VERSION 5.8 ;
BUSBITCHARS "[]" ;
DIVIDERCHAR "/" ;
UNITS
    DATABASE MICRONS 1000 ;
END UNITS

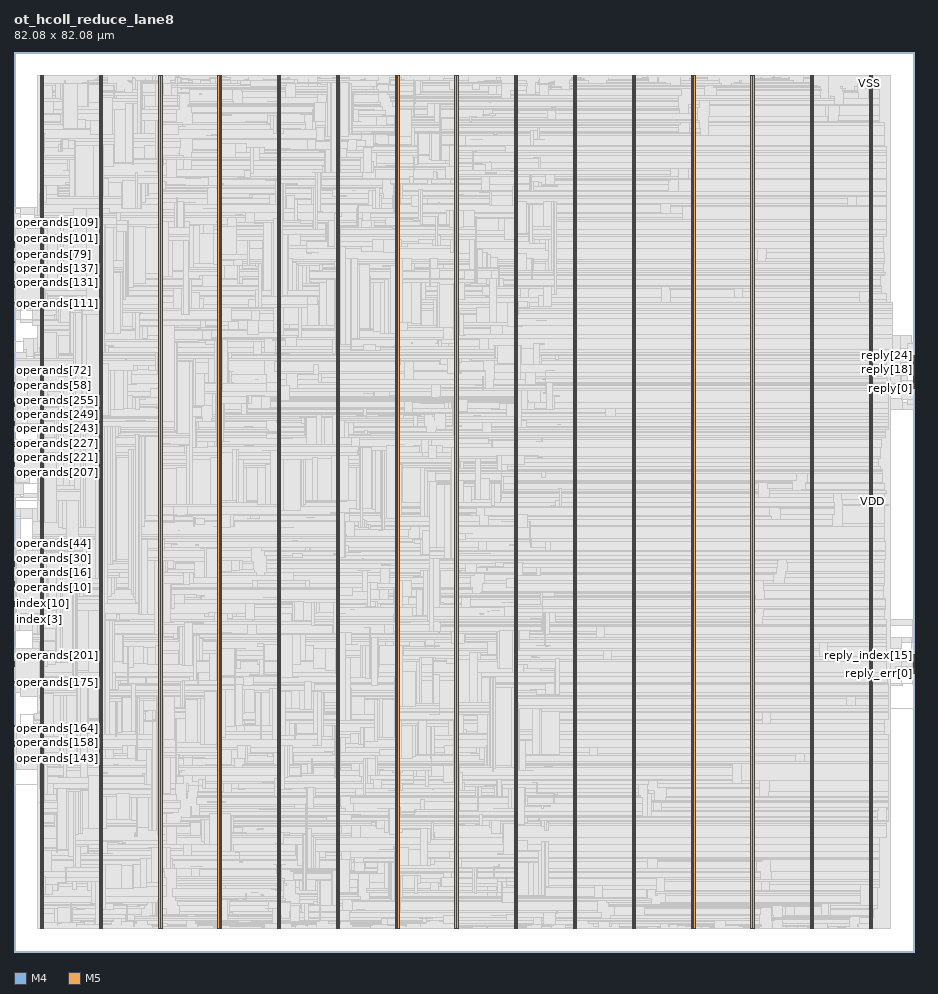
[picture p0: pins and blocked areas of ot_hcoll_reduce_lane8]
MACRO ot_hcoll_reduce_lane8
  FOREIGN ot_hcoll_reduce_lane8 0 0 ;
  CLASS BLOCK ;
  SIZE 82.08 BY 82.08 ;
  PIN clk
    DIRECTION INPUT ;
    USE SIGNAL ;
    PORT
      LAYER M4 ;
        RECT  0 30.672 0.084 30.696 ;
    END
  END clk
  PIN index[0]
    DIRECTION INPUT ;
    USE SIGNAL ;
    PORT
      LAYER M4 ;
        RECT  0 30.768 0.084 30.792 ;
    END
  END index[0]
  PIN index[10]
    DIRECTION INPUT ;
    USE SIGNAL ;
    PORT
      LAYER M4 ;
        RECT  0 31.728 0.084 31.752 ;
    END
  END index[10]
  PIN index[11]
    DIRECTION INPUT ;
    USE SIGNAL ;
    PORT
      LAYER M4 ;
        RECT  0 31.824 0.084 31.848 ;
    END
  END index[11]
  PIN index[12]
    DIRECTION INPUT ;
    USE SIGNAL ;
    PORT
      LAYER M4 ;
        RECT  0 31.92 0.084 31.944 ;
    END
  END index[12]
  PIN index[13]
    DIRECTION INPUT ;
    USE SIGNAL ;
    PORT
      LAYER M4 ;
        RECT  0 32.016 0.084 32.04 ;
    END
  END index[13]
  PIN index[14]
    DIRECTION INPUT ;
    USE SIGNAL ;
    PORT
      LAYER M4 ;
        RECT  0 32.112 0.084 32.136 ;
    END
  END index[14]
  PIN index[15]
    DIRECTION INPUT ;
    USE SIGNAL ;
    PORT
      LAYER M4 ;
        RECT  0 32.208 0.084 32.232 ;
    END
  END index[15]
  PIN index[1]
    DIRECTION INPUT ;
    USE SIGNAL ;
    PORT
      LAYER M4 ;
        RECT  0 30.864 0.084 30.888 ;
    END
  END index[1]
  PIN index[2]
    DIRECTION INPUT ;
    USE SIGNAL ;
    PORT
      LAYER M4 ;
        RECT  0 30.96 0.084 30.984 ;
    END
  END index[2]
  PIN index[3]
    DIRECTION INPUT ;
    USE SIGNAL ;
    PORT
      LAYER M4 ;
        RECT  0 31.056 0.084 31.08 ;
    END
  END index[3]
  PIN index[4]
    DIRECTION INPUT ;
    USE SIGNAL ;
    PORT
      LAYER M4 ;
        RECT  0 31.152 0.084 31.176 ;
    END
  END index[4]
  PIN index[5]
    DIRECTION INPUT ;
    USE SIGNAL ;
    PORT
      LAYER M4 ;
        RECT  0 31.248 0.084 31.272 ;
    END
  END index[5]
  PIN index[6]
    DIRECTION INPUT ;
    USE SIGNAL ;
    PORT
      LAYER M4 ;
        RECT  0 31.344 0.084 31.368 ;
    END
  END index[6]
  PIN index[7]
    DIRECTION INPUT ;
    USE SIGNAL ;
    PORT
      LAYER M4 ;
        RECT  0 31.44 0.084 31.464 ;
    END
  END index[7]
  PIN index[8]
    DIRECTION INPUT ;
    USE SIGNAL ;
    PORT
      LAYER M4 ;
        RECT  0 31.536 0.084 31.56 ;
    END
  END index[8]
  PIN index[9]
    DIRECTION INPUT ;
    USE SIGNAL ;
    PORT
      LAYER M4 ;
        RECT  0 31.632 0.084 31.656 ;
    END
  END index[9]
  PIN operands[0]
    DIRECTION INPUT ;
    USE SIGNAL ;
    PORT
      LAYER M4 ;
        RECT  0 32.304 0.084 32.328 ;
    END
  END operands[0]
  PIN operands[100]
    DIRECTION INPUT ;
    USE SIGNAL ;
    PORT
      LAYER M4 ;
        RECT  0 64.944 0.084 64.968 ;
    END
  END operands[100]
  PIN operands[101]
    DIRECTION INPUT ;
    USE SIGNAL ;
    PORT
      LAYER M4 ;
        RECT  0 65.04 0.084 65.064 ;
    END
  END operands[101]
  PIN operands[102]
    DIRECTION INPUT ;
    USE SIGNAL ;
    PORT
      LAYER M4 ;
        RECT  0 65.136 0.084 65.16 ;
    END
  END operands[102]
  PIN operands[103]
    DIRECTION INPUT ;
    USE SIGNAL ;
    PORT
      LAYER M4 ;
        RECT  0 65.232 0.084 65.256 ;
    END
  END operands[103]
  PIN operands[104]
    DIRECTION INPUT ;
    USE SIGNAL ;
    PORT
      LAYER M4 ;
        RECT  0 65.328 0.084 65.352 ;
    END
  END operands[104]
  PIN operands[105]
    DIRECTION INPUT ;
    USE SIGNAL ;
    PORT
      LAYER M4 ;
        RECT  0 65.424 0.084 65.448 ;
    END
  END operands[105]
  PIN operands[106]
    DIRECTION INPUT ;
    USE SIGNAL ;
    PORT
      LAYER M4 ;
        RECT  0 65.52 0.084 65.544 ;
    END
  END operands[106]
  PIN operands[107]
    DIRECTION INPUT ;
    USE SIGNAL ;
    PORT
      LAYER M4 ;
        RECT  0 65.616 0.084 65.64 ;
    END
  END operands[107]
  PIN operands[108]
    DIRECTION INPUT ;
    USE SIGNAL ;
    PORT
      LAYER M4 ;
        RECT  0 65.712 0.084 65.736 ;
    END
  END operands[108]
  PIN operands[109]
    DIRECTION INPUT ;
    USE SIGNAL ;
    PORT
      LAYER M4 ;
        RECT  0 65.808 0.084 65.832 ;
    END
  END operands[109]
  PIN operands[10]
    DIRECTION INPUT ;
    USE SIGNAL ;
    PORT
      LAYER M4 ;
        RECT  0 33.264 0.084 33.288 ;
    END
  END operands[10]
  PIN operands[110]
    DIRECTION INPUT ;
    USE SIGNAL ;
    PORT
      LAYER M4 ;
        RECT  0 65.904 0.084 65.928 ;
    END
  END operands[110]
  PIN operands[111]
    DIRECTION INPUT ;
    USE SIGNAL ;
    PORT
      LAYER M4 ;
        RECT  0 59.088 0.084 59.112 ;
    END
  END operands[111]
  PIN operands[112]
    DIRECTION INPUT ;
    USE SIGNAL ;
    PORT
      LAYER M4 ;
        RECT  0 59.184 0.084 59.208 ;
    END
  END operands[112]
  PIN operands[113]
    DIRECTION INPUT ;
    USE SIGNAL ;
    PORT
      LAYER M4 ;
        RECT  0 59.28 0.084 59.304 ;
    END
  END operands[113]
  PIN operands[114]
    DIRECTION INPUT ;
    USE SIGNAL ;
    PORT
      LAYER M4 ;
        RECT  0 59.376 0.084 59.4 ;
    END
  END operands[114]
  PIN operands[115]
    DIRECTION INPUT ;
    USE SIGNAL ;
    PORT
      LAYER M4 ;
        RECT  0 59.472 0.084 59.496 ;
    END
  END operands[115]
  PIN operands[116]
    DIRECTION INPUT ;
    USE SIGNAL ;
    PORT
      LAYER M4 ;
        RECT  0 59.568 0.084 59.592 ;
    END
  END operands[116]
  PIN operands[117]
    DIRECTION INPUT ;
    USE SIGNAL ;
    PORT
      LAYER M4 ;
        RECT  0 59.664 0.084 59.688 ;
    END
  END operands[117]
  PIN operands[118]
    DIRECTION INPUT ;
    USE SIGNAL ;
    PORT
      LAYER M4 ;
        RECT  0 59.76 0.084 59.784 ;
    END
  END operands[118]
  PIN operands[119]
    DIRECTION INPUT ;
    USE SIGNAL ;
    PORT
      LAYER M4 ;
        RECT  0 59.856 0.084 59.88 ;
    END
  END operands[119]
  PIN operands[11]
    DIRECTION INPUT ;
    USE SIGNAL ;
    PORT
      LAYER M4 ;
        RECT  0 33.36 0.084 33.384 ;
    END
  END operands[11]
  PIN operands[120]
    DIRECTION INPUT ;
    USE SIGNAL ;
    PORT
      LAYER M4 ;
        RECT  0 59.952 0.084 59.976 ;
    END
  END operands[120]
  PIN operands[121]
    DIRECTION INPUT ;
    USE SIGNAL ;
    PORT
      LAYER M4 ;
        RECT  0 60.048 0.084 60.072 ;
    END
  END operands[121]
  PIN operands[122]
    DIRECTION INPUT ;
    USE SIGNAL ;
    PORT
      LAYER M4 ;
        RECT  0 60.144 0.084 60.168 ;
    END
  END operands[122]
  PIN operands[123]
    DIRECTION INPUT ;
    USE SIGNAL ;
    PORT
      LAYER M4 ;
        RECT  0 60.24 0.084 60.264 ;
    END
  END operands[123]
  PIN operands[124]
    DIRECTION INPUT ;
    USE SIGNAL ;
    PORT
      LAYER M4 ;
        RECT  0 60.336 0.084 60.36 ;
    END
  END operands[124]
  PIN operands[125]
    DIRECTION INPUT ;
    USE SIGNAL ;
    PORT
      LAYER M4 ;
        RECT  0 60.432 0.084 60.456 ;
    END
  END operands[125]
  PIN operands[126]
    DIRECTION INPUT ;
    USE SIGNAL ;
    PORT
      LAYER M4 ;
        RECT  0 60.528 0.084 60.552 ;
    END
  END operands[126]
  PIN operands[127]
    DIRECTION INPUT ;
    USE SIGNAL ;
    PORT
      LAYER M4 ;
        RECT  0 60.624 0.084 60.648 ;
    END
  END operands[127]
  PIN operands[128]
    DIRECTION INPUT ;
    USE SIGNAL ;
    PORT
      LAYER M4 ;
        RECT  0 60.72 0.084 60.744 ;
    END
  END operands[128]
  PIN operands[129]
    DIRECTION INPUT ;
    USE SIGNAL ;
    PORT
      LAYER M4 ;
        RECT  0 60.816 0.084 60.84 ;
    END
  END operands[129]
  PIN operands[12]
    DIRECTION INPUT ;
    USE SIGNAL ;
    PORT
      LAYER M4 ;
        RECT  0 33.456 0.084 33.48 ;
    END
  END operands[12]
  PIN operands[130]
    DIRECTION INPUT ;
    USE SIGNAL ;
    PORT
      LAYER M4 ;
        RECT  0 60.912 0.084 60.936 ;
    END
  END operands[130]
  PIN operands[131]
    DIRECTION INPUT ;
    USE SIGNAL ;
    PORT
      LAYER M4 ;
        RECT  0 61.008 0.084 61.032 ;
    END
  END operands[131]
  PIN operands[132]
    DIRECTION INPUT ;
    USE SIGNAL ;
    PORT
      LAYER M4 ;
        RECT  0 61.104 0.084 61.128 ;
    END
  END operands[132]
  PIN operands[133]
    DIRECTION INPUT ;
    USE SIGNAL ;
    PORT
      LAYER M4 ;
        RECT  0 61.2 0.084 61.224 ;
    END
  END operands[133]
  PIN operands[134]
    DIRECTION INPUT ;
    USE SIGNAL ;
    PORT
      LAYER M4 ;
        RECT  0 61.296 0.084 61.32 ;
    END
  END operands[134]
  PIN operands[135]
    DIRECTION INPUT ;
    USE SIGNAL ;
    PORT
      LAYER M4 ;
        RECT  0 61.392 0.084 61.416 ;
    END
  END operands[135]
  PIN operands[136]
    DIRECTION INPUT ;
    USE SIGNAL ;
    PORT
      LAYER M4 ;
        RECT  0 61.488 0.084 61.512 ;
    END
  END operands[136]
  PIN operands[137]
    DIRECTION INPUT ;
    USE SIGNAL ;
    PORT
      LAYER M4 ;
        RECT  0 61.584 0.084 61.608 ;
    END
  END operands[137]
  PIN operands[138]
    DIRECTION INPUT ;
    USE SIGNAL ;
    PORT
      LAYER M4 ;
        RECT  0 61.68 0.084 61.704 ;
    END
  END operands[138]
  PIN operands[139]
    DIRECTION INPUT ;
    USE SIGNAL ;
    PORT
      LAYER M4 ;
        RECT  0 61.776 0.084 61.8 ;
    END
  END operands[139]
  PIN operands[13]
    DIRECTION INPUT ;
    USE SIGNAL ;
    PORT
      LAYER M4 ;
        RECT  0 33.552 0.084 33.576 ;
    END
  END operands[13]
  PIN operands[140]
    DIRECTION INPUT ;
    USE SIGNAL ;
    PORT
      LAYER M4 ;
        RECT  0 61.872 0.084 61.896 ;
    END
  END operands[140]
  PIN operands[141]
    DIRECTION INPUT ;
    USE SIGNAL ;
    PORT
      LAYER M4 ;
        RECT  0 61.968 0.084 61.992 ;
    END
  END operands[141]
  PIN operands[142]
    DIRECTION INPUT ;
    USE SIGNAL ;
    PORT
      LAYER M4 ;
        RECT  0 62.064 0.084 62.088 ;
    END
  END operands[142]
  PIN operands[143]
    DIRECTION INPUT ;
    USE SIGNAL ;
    PORT
      LAYER M4 ;
        RECT  0 17.616 0.084 17.64 ;
    END
  END operands[143]
  PIN operands[144]
    DIRECTION INPUT ;
    USE SIGNAL ;
    PORT
      LAYER M4 ;
        RECT  0 17.712 0.084 17.736 ;
    END
  END operands[144]
  PIN operands[145]
    DIRECTION INPUT ;
    USE SIGNAL ;
    PORT
      LAYER M4 ;
        RECT  0 17.808 0.084 17.832 ;
    END
  END operands[145]
  PIN operands[146]
    DIRECTION INPUT ;
    USE SIGNAL ;
    PORT
      LAYER M4 ;
        RECT  0 17.904 0.084 17.928 ;
    END
  END operands[146]
  PIN operands[147]
    DIRECTION INPUT ;
    USE SIGNAL ;
    PORT
      LAYER M4 ;
        RECT  0 18 0.084 18.024 ;
    END
  END operands[147]
  PIN operands[148]
    DIRECTION INPUT ;
    USE SIGNAL ;
    PORT
      LAYER M4 ;
        RECT  0 18.096 0.084 18.12 ;
    END
  END operands[148]
  PIN operands[149]
    DIRECTION INPUT ;
    USE SIGNAL ;
    PORT
      LAYER M4 ;
        RECT  0 18.192 0.084 18.216 ;
    END
  END operands[149]
  PIN operands[14]
    DIRECTION INPUT ;
    USE SIGNAL ;
    PORT
      LAYER M4 ;
        RECT  0 33.648 0.084 33.672 ;
    END
  END operands[14]
  PIN operands[150]
    DIRECTION INPUT ;
    USE SIGNAL ;
    PORT
      LAYER M4 ;
        RECT  0 18.288 0.084 18.312 ;
    END
  END operands[150]
  PIN operands[151]
    DIRECTION INPUT ;
    USE SIGNAL ;
    PORT
      LAYER M4 ;
        RECT  0 18.384 0.084 18.408 ;
    END
  END operands[151]
  PIN operands[152]
    DIRECTION INPUT ;
    USE SIGNAL ;
    PORT
      LAYER M4 ;
        RECT  0 18.48 0.084 18.504 ;
    END
  END operands[152]
  PIN operands[153]
    DIRECTION INPUT ;
    USE SIGNAL ;
    PORT
      LAYER M4 ;
        RECT  0 18.576 0.084 18.6 ;
    END
  END operands[153]
  PIN operands[154]
    DIRECTION INPUT ;
    USE SIGNAL ;
    PORT
      LAYER M4 ;
        RECT  0 18.672 0.084 18.696 ;
    END
  END operands[154]
  PIN operands[155]
    DIRECTION INPUT ;
    USE SIGNAL ;
    PORT
      LAYER M4 ;
        RECT  0 18.768 0.084 18.792 ;
    END
  END operands[155]
  PIN operands[156]
    DIRECTION INPUT ;
    USE SIGNAL ;
    PORT
      LAYER M4 ;
        RECT  0 18.864 0.084 18.888 ;
    END
  END operands[156]
  PIN operands[157]
    DIRECTION INPUT ;
    USE SIGNAL ;
    PORT
      LAYER M4 ;
        RECT  0 18.96 0.084 18.984 ;
    END
  END operands[157]
  PIN operands[158]
    DIRECTION INPUT ;
    USE SIGNAL ;
    PORT
      LAYER M4 ;
        RECT  0 19.056 0.084 19.08 ;
    END
  END operands[158]
  PIN operands[159]
    DIRECTION INPUT ;
    USE SIGNAL ;
    PORT
      LAYER M4 ;
        RECT  0 19.152 0.084 19.176 ;
    END
  END operands[159]
  PIN operands[15]
    DIRECTION INPUT ;
    USE SIGNAL ;
    PORT
      LAYER M4 ;
        RECT  0 33.744 0.084 33.768 ;
    END
  END operands[15]
  PIN operands[160]
    DIRECTION INPUT ;
    USE SIGNAL ;
    PORT
      LAYER M4 ;
        RECT  0 19.248 0.084 19.272 ;
    END
  END operands[160]
  PIN operands[161]
    DIRECTION INPUT ;
    USE SIGNAL ;
    PORT
      LAYER M4 ;
        RECT  0 19.344 0.084 19.368 ;
    END
  END operands[161]
  PIN operands[162]
    DIRECTION INPUT ;
    USE SIGNAL ;
    PORT
      LAYER M4 ;
        RECT  0 19.44 0.084 19.464 ;
    END
  END operands[162]
  PIN operands[163]
    DIRECTION INPUT ;
    USE SIGNAL ;
    PORT
      LAYER M4 ;
        RECT  0 19.536 0.084 19.56 ;
    END
  END operands[163]
  PIN operands[164]
    DIRECTION INPUT ;
    USE SIGNAL ;
    PORT
      LAYER M4 ;
        RECT  0 19.632 0.084 19.656 ;
    END
  END operands[164]
  PIN operands[165]
    DIRECTION INPUT ;
    USE SIGNAL ;
    PORT
      LAYER M4 ;
        RECT  0 19.728 0.084 19.752 ;
    END
  END operands[165]
  PIN operands[166]
    DIRECTION INPUT ;
    USE SIGNAL ;
    PORT
      LAYER M4 ;
        RECT  0 19.824 0.084 19.848 ;
    END
  END operands[166]
  PIN operands[167]
    DIRECTION INPUT ;
    USE SIGNAL ;
    PORT
      LAYER M4 ;
        RECT  0 19.92 0.084 19.944 ;
    END
  END operands[167]
  PIN operands[168]
    DIRECTION INPUT ;
    USE SIGNAL ;
    PORT
      LAYER M4 ;
        RECT  0 20.016 0.084 20.04 ;
    END
  END operands[168]
  PIN operands[169]
    DIRECTION INPUT ;
    USE SIGNAL ;
    PORT
      LAYER M4 ;
        RECT  0 20.112 0.084 20.136 ;
    END
  END operands[169]
  PIN operands[16]
    DIRECTION INPUT ;
    USE SIGNAL ;
    PORT
      LAYER M4 ;
        RECT  0 33.84 0.084 33.864 ;
    END
  END operands[16]
  PIN operands[170]
    DIRECTION INPUT ;
    USE SIGNAL ;
    PORT
      LAYER M4 ;
        RECT  0 20.208 0.084 20.232 ;
    END
  END operands[170]
  PIN operands[171]
    DIRECTION INPUT ;
    USE SIGNAL ;
    PORT
      LAYER M4 ;
        RECT  0 20.304 0.084 20.328 ;
    END
  END operands[171]
  PIN operands[172]
    DIRECTION INPUT ;
    USE SIGNAL ;
    PORT
      LAYER M4 ;
        RECT  0 20.4 0.084 20.424 ;
    END
  END operands[172]
  PIN operands[173]
    DIRECTION INPUT ;
    USE SIGNAL ;
    PORT
      LAYER M4 ;
        RECT  0 20.496 0.084 20.52 ;
    END
  END operands[173]
  PIN operands[174]
    DIRECTION INPUT ;
    USE SIGNAL ;
    PORT
      LAYER M4 ;
        RECT  0 20.592 0.084 20.616 ;
    END
  END operands[174]
  PIN operands[175]
    DIRECTION INPUT ;
    USE SIGNAL ;
    PORT
      LAYER M4 ;
        RECT  0 24.528 0.084 24.552 ;
    END
  END operands[175]
  PIN operands[176]
    DIRECTION INPUT ;
    USE SIGNAL ;
    PORT
      LAYER M4 ;
        RECT  0 24.624 0.084 24.648 ;
    END
  END operands[176]
  PIN operands[177]
    DIRECTION INPUT ;
    USE SIGNAL ;
    PORT
      LAYER M4 ;
        RECT  0 24.72 0.084 24.744 ;
    END
  END operands[177]
  PIN operands[178]
    DIRECTION INPUT ;
    USE SIGNAL ;
    PORT
      LAYER M4 ;
        RECT  0 24.816 0.084 24.84 ;
    END
  END operands[178]
  PIN operands[179]
    DIRECTION INPUT ;
    USE SIGNAL ;
    PORT
      LAYER M4 ;
        RECT  0 24.912 0.084 24.936 ;
    END
  END operands[179]
  PIN operands[17]
    DIRECTION INPUT ;
    USE SIGNAL ;
    PORT
      LAYER M4 ;
        RECT  0 33.936 0.084 33.96 ;
    END
  END operands[17]
  PIN operands[180]
    DIRECTION INPUT ;
    USE SIGNAL ;
    PORT
      LAYER M4 ;
        RECT  0 25.008 0.084 25.032 ;
    END
  END operands[180]
  PIN operands[181]
    DIRECTION INPUT ;
    USE SIGNAL ;
    PORT
      LAYER M4 ;
        RECT  0 25.104 0.084 25.128 ;
    END
  END operands[181]
  PIN operands[182]
    DIRECTION INPUT ;
    USE SIGNAL ;
    PORT
      LAYER M4 ;
        RECT  0 25.2 0.084 25.224 ;
    END
  END operands[182]
  PIN operands[183]
    DIRECTION INPUT ;
    USE SIGNAL ;
    PORT
      LAYER M4 ;
        RECT  0 25.296 0.084 25.32 ;
    END
  END operands[183]
  PIN operands[184]
    DIRECTION INPUT ;
    USE SIGNAL ;
    PORT
      LAYER M4 ;
        RECT  0 25.392 0.084 25.416 ;
    END
  END operands[184]
  PIN operands[185]
    DIRECTION INPUT ;
    USE SIGNAL ;
    PORT
      LAYER M4 ;
        RECT  0 25.488 0.084 25.512 ;
    END
  END operands[185]
  PIN operands[186]
    DIRECTION INPUT ;
    USE SIGNAL ;
    PORT
      LAYER M4 ;
        RECT  0 25.584 0.084 25.608 ;
    END
  END operands[186]
  PIN operands[187]
    DIRECTION INPUT ;
    USE SIGNAL ;
    PORT
      LAYER M4 ;
        RECT  0 25.68 0.084 25.704 ;
    END
  END operands[187]
  PIN operands[188]
    DIRECTION INPUT ;
    USE SIGNAL ;
    PORT
      LAYER M4 ;
        RECT  0 25.776 0.084 25.8 ;
    END
  END operands[188]
  PIN operands[189]
    DIRECTION INPUT ;
    USE SIGNAL ;
    PORT
      LAYER M4 ;
        RECT  0 25.872 0.084 25.896 ;
    END
  END operands[189]
  PIN operands[18]
    DIRECTION INPUT ;
    USE SIGNAL ;
    PORT
      LAYER M4 ;
        RECT  0 34.032 0.084 34.056 ;
    END
  END operands[18]
  PIN operands[190]
    DIRECTION INPUT ;
    USE SIGNAL ;
    PORT
      LAYER M4 ;
        RECT  0 25.968 0.084 25.992 ;
    END
  END operands[190]
  PIN operands[191]
    DIRECTION INPUT ;
    USE SIGNAL ;
    PORT
      LAYER M4 ;
        RECT  0 26.064 0.084 26.088 ;
    END
  END operands[191]
  PIN operands[192]
    DIRECTION INPUT ;
    USE SIGNAL ;
    PORT
      LAYER M4 ;
        RECT  0 26.16 0.084 26.184 ;
    END
  END operands[192]
  PIN operands[193]
    DIRECTION INPUT ;
    USE SIGNAL ;
    PORT
      LAYER M4 ;
        RECT  0 26.256 0.084 26.28 ;
    END
  END operands[193]
  PIN operands[194]
    DIRECTION INPUT ;
    USE SIGNAL ;
    PORT
      LAYER M4 ;
        RECT  0 26.352 0.084 26.376 ;
    END
  END operands[194]
  PIN operands[195]
    DIRECTION INPUT ;
    USE SIGNAL ;
    PORT
      LAYER M4 ;
        RECT  0 26.448 0.084 26.472 ;
    END
  END operands[195]
  PIN operands[196]
    DIRECTION INPUT ;
    USE SIGNAL ;
    PORT
      LAYER M4 ;
        RECT  0 26.544 0.084 26.568 ;
    END
  END operands[196]
  PIN operands[197]
    DIRECTION INPUT ;
    USE SIGNAL ;
    PORT
      LAYER M4 ;
        RECT  0 26.64 0.084 26.664 ;
    END
  END operands[197]
  PIN operands[198]
    DIRECTION INPUT ;
    USE SIGNAL ;
    PORT
      LAYER M4 ;
        RECT  0 26.736 0.084 26.76 ;
    END
  END operands[198]
  PIN operands[199]
    DIRECTION INPUT ;
    USE SIGNAL ;
    PORT
      LAYER M4 ;
        RECT  0 26.832 0.084 26.856 ;
    END
  END operands[199]
  PIN operands[19]
    DIRECTION INPUT ;
    USE SIGNAL ;
    PORT
      LAYER M4 ;
        RECT  0 34.128 0.084 34.152 ;
    END
  END operands[19]
  PIN operands[1]
    DIRECTION INPUT ;
    USE SIGNAL ;
    PORT
      LAYER M4 ;
        RECT  0 32.4 0.084 32.424 ;
    END
  END operands[1]
  PIN operands[200]
    DIRECTION INPUT ;
    USE SIGNAL ;
    PORT
      LAYER M4 ;
        RECT  0 26.928 0.084 26.952 ;
    END
  END operands[200]
  PIN operands[201]
    DIRECTION INPUT ;
    USE SIGNAL ;
    PORT
      LAYER M4 ;
        RECT  0 27.024 0.084 27.048 ;
    END
  END operands[201]
  PIN operands[202]
    DIRECTION INPUT ;
    USE SIGNAL ;
    PORT
      LAYER M4 ;
        RECT  0 27.12 0.084 27.144 ;
    END
  END operands[202]
  PIN operands[203]
    DIRECTION INPUT ;
    USE SIGNAL ;
    PORT
      LAYER M4 ;
        RECT  0 27.216 0.084 27.24 ;
    END
  END operands[203]
  PIN operands[204]
    DIRECTION INPUT ;
    USE SIGNAL ;
    PORT
      LAYER M4 ;
        RECT  0 27.312 0.084 27.336 ;
    END
  END operands[204]
  PIN operands[205]
    DIRECTION INPUT ;
    USE SIGNAL ;
    PORT
      LAYER M4 ;
        RECT  0 27.408 0.084 27.432 ;
    END
  END operands[205]
  PIN operands[206]
    DIRECTION INPUT ;
    USE SIGNAL ;
    PORT
      LAYER M4 ;
        RECT  0 27.504 0.084 27.528 ;
    END
  END operands[206]
  PIN operands[207]
    DIRECTION INPUT ;
    USE SIGNAL ;
    PORT
      LAYER M4 ;
        RECT  0 43.728 0.084 43.752 ;
    END
  END operands[207]
  PIN operands[208]
    DIRECTION INPUT ;
    USE SIGNAL ;
    PORT
      LAYER M4 ;
        RECT  0 43.824 0.084 43.848 ;
    END
  END operands[208]
  PIN operands[209]
    DIRECTION INPUT ;
    USE SIGNAL ;
    PORT
      LAYER M4 ;
        RECT  0 43.92 0.084 43.944 ;
    END
  END operands[209]
  PIN operands[20]
    DIRECTION INPUT ;
    USE SIGNAL ;
    PORT
      LAYER M4 ;
        RECT  0 34.224 0.084 34.248 ;
    END
  END operands[20]
  PIN operands[210]
    DIRECTION INPUT ;
    USE SIGNAL ;
    PORT
      LAYER M4 ;
        RECT  0 44.016 0.084 44.04 ;
    END
  END operands[210]
  PIN operands[211]
    DIRECTION INPUT ;
    USE SIGNAL ;
    PORT
      LAYER M4 ;
        RECT  0 44.112 0.084 44.136 ;
    END
  END operands[211]
  PIN operands[212]
    DIRECTION INPUT ;
    USE SIGNAL ;
    PORT
      LAYER M4 ;
        RECT  0 44.208 0.084 44.232 ;
    END
  END operands[212]
  PIN operands[213]
    DIRECTION INPUT ;
    USE SIGNAL ;
    PORT
      LAYER M4 ;
        RECT  0 44.304 0.084 44.328 ;
    END
  END operands[213]
  PIN operands[214]
    DIRECTION INPUT ;
    USE SIGNAL ;
    PORT
      LAYER M4 ;
        RECT  0 44.4 0.084 44.424 ;
    END
  END operands[214]
  PIN operands[215]
    DIRECTION INPUT ;
    USE SIGNAL ;
    PORT
      LAYER M4 ;
        RECT  0 44.496 0.084 44.52 ;
    END
  END operands[215]
  PIN operands[216]
    DIRECTION INPUT ;
    USE SIGNAL ;
    PORT
      LAYER M4 ;
        RECT  0 44.592 0.084 44.616 ;
    END
  END operands[216]
  PIN operands[217]
    DIRECTION INPUT ;
    USE SIGNAL ;
    PORT
      LAYER M4 ;
        RECT  0 44.688 0.084 44.712 ;
    END
  END operands[217]
  PIN operands[218]
    DIRECTION INPUT ;
    USE SIGNAL ;
    PORT
      LAYER M4 ;
        RECT  0 44.784 0.084 44.808 ;
    END
  END operands[218]
  PIN operands[219]
    DIRECTION INPUT ;
    USE SIGNAL ;
    PORT
      LAYER M4 ;
        RECT  0 44.88 0.084 44.904 ;
    END
  END operands[219]
  PIN operands[21]
    DIRECTION INPUT ;
    USE SIGNAL ;
    PORT
      LAYER M4 ;
        RECT  0 34.32 0.084 34.344 ;
    END
  END operands[21]
  PIN operands[220]
    DIRECTION INPUT ;
    USE SIGNAL ;
    PORT
      LAYER M4 ;
        RECT  0 44.976 0.084 45 ;
    END
  END operands[220]
  PIN operands[221]
    DIRECTION INPUT ;
    USE SIGNAL ;
    PORT
      LAYER M4 ;
        RECT  0 45.072 0.084 45.096 ;
    END
  END operands[221]
  PIN operands[222]
    DIRECTION INPUT ;
    USE SIGNAL ;
    PORT
      LAYER M4 ;
        RECT  0 45.168 0.084 45.192 ;
    END
  END operands[222]
  PIN operands[223]
    DIRECTION INPUT ;
    USE SIGNAL ;
    PORT
      LAYER M4 ;
        RECT  0 45.264 0.084 45.288 ;
    END
  END operands[223]
  PIN operands[224]
    DIRECTION INPUT ;
    USE SIGNAL ;
    PORT
      LAYER M4 ;
        RECT  0 45.36 0.084 45.384 ;
    END
  END operands[224]
  PIN operands[225]
    DIRECTION INPUT ;
    USE SIGNAL ;
    PORT
      LAYER M4 ;
        RECT  0 45.456 0.084 45.48 ;
    END
  END operands[225]
  PIN operands[226]
    DIRECTION INPUT ;
    USE SIGNAL ;
    PORT
      LAYER M4 ;
        RECT  0 45.552 0.084 45.576 ;
    END
  END operands[226]
  PIN operands[227]
    DIRECTION INPUT ;
    USE SIGNAL ;
    PORT
      LAYER M4 ;
        RECT  0 45.648 0.084 45.672 ;
    END
  END operands[227]
  PIN operands[228]
    DIRECTION INPUT ;
    USE SIGNAL ;
    PORT
      LAYER M4 ;
        RECT  0 45.744 0.084 45.768 ;
    END
  END operands[228]
  PIN operands[229]
    DIRECTION INPUT ;
    USE SIGNAL ;
    PORT
      LAYER M4 ;
        RECT  0 45.84 0.084 45.864 ;
    END
  END operands[229]
  PIN operands[22]
    DIRECTION INPUT ;
    USE SIGNAL ;
    PORT
      LAYER M4 ;
        RECT  0 34.416 0.084 34.44 ;
    END
  END operands[22]
  PIN operands[230]
    DIRECTION INPUT ;
    USE SIGNAL ;
    PORT
      LAYER M4 ;
        RECT  0 45.936 0.084 45.96 ;
    END
  END operands[230]
  PIN operands[231]
    DIRECTION INPUT ;
    USE SIGNAL ;
    PORT
      LAYER M4 ;
        RECT  0 46.032 0.084 46.056 ;
    END
  END operands[231]
  PIN operands[232]
    DIRECTION INPUT ;
    USE SIGNAL ;
    PORT
      LAYER M4 ;
        RECT  0 46.128 0.084 46.152 ;
    END
  END operands[232]
  PIN operands[233]
    DIRECTION INPUT ;
    USE SIGNAL ;
    PORT
      LAYER M4 ;
        RECT  0 46.224 0.084 46.248 ;
    END
  END operands[233]
  PIN operands[234]
    DIRECTION INPUT ;
    USE SIGNAL ;
    PORT
      LAYER M4 ;
        RECT  0 46.32 0.084 46.344 ;
    END
  END operands[234]
  PIN operands[235]
    DIRECTION INPUT ;
    USE SIGNAL ;
    PORT
      LAYER M4 ;
        RECT  0 46.416 0.084 46.44 ;
    END
  END operands[235]
  PIN operands[236]
    DIRECTION INPUT ;
    USE SIGNAL ;
    PORT
      LAYER M4 ;
        RECT  0 46.512 0.084 46.536 ;
    END
  END operands[236]
  PIN operands[237]
    DIRECTION INPUT ;
    USE SIGNAL ;
    PORT
      LAYER M4 ;
        RECT  0 46.608 0.084 46.632 ;
    END
  END operands[237]
  PIN operands[238]
    DIRECTION INPUT ;
    USE SIGNAL ;
    PORT
      LAYER M4 ;
        RECT  0 46.704 0.084 46.728 ;
    END
  END operands[238]
  PIN operands[239]
    DIRECTION INPUT ;
    USE SIGNAL ;
    PORT
      LAYER M4 ;
        RECT  0 48.048 0.084 48.072 ;
    END
  END operands[239]
  PIN operands[23]
    DIRECTION INPUT ;
    USE SIGNAL ;
    PORT
      LAYER M4 ;
        RECT  0 34.512 0.084 34.536 ;
    END
  END operands[23]
  PIN operands[240]
    DIRECTION INPUT ;
    USE SIGNAL ;
    PORT
      LAYER M4 ;
        RECT  0 48.144 0.084 48.168 ;
    END
  END operands[240]
  PIN operands[241]
    DIRECTION INPUT ;
    USE SIGNAL ;
    PORT
      LAYER M4 ;
        RECT  0 48.24 0.084 48.264 ;
    END
  END operands[241]
  PIN operands[242]
    DIRECTION INPUT ;
    USE SIGNAL ;
    PORT
      LAYER M4 ;
        RECT  0 48.336 0.084 48.36 ;
    END
  END operands[242]
  PIN operands[243]
    DIRECTION INPUT ;
    USE SIGNAL ;
    PORT
      LAYER M4 ;
        RECT  0 48.432 0.084 48.456 ;
    END
  END operands[243]
  PIN operands[244]
    DIRECTION INPUT ;
    USE SIGNAL ;
    PORT
      LAYER M4 ;
        RECT  0 48.528 0.084 48.552 ;
    END
  END operands[244]
  PIN operands[245]
    DIRECTION INPUT ;
    USE SIGNAL ;
    PORT
      LAYER M4 ;
        RECT  0 48.624 0.084 48.648 ;
    END
  END operands[245]
  PIN operands[246]
    DIRECTION INPUT ;
    USE SIGNAL ;
    PORT
      LAYER M4 ;
        RECT  0 48.72 0.084 48.744 ;
    END
  END operands[246]
  PIN operands[247]
    DIRECTION INPUT ;
    USE SIGNAL ;
    PORT
      LAYER M4 ;
        RECT  0 48.816 0.084 48.84 ;
    END
  END operands[247]
  PIN operands[248]
    DIRECTION INPUT ;
    USE SIGNAL ;
    PORT
      LAYER M4 ;
        RECT  0 48.912 0.084 48.936 ;
    END
  END operands[248]
  PIN operands[249]
    DIRECTION INPUT ;
    USE SIGNAL ;
    PORT
      LAYER M4 ;
        RECT  0 49.008 0.084 49.032 ;
    END
  END operands[249]
  PIN operands[24]
    DIRECTION INPUT ;
    USE SIGNAL ;
    PORT
      LAYER M4 ;
        RECT  0 34.608 0.084 34.632 ;
    END
  END operands[24]
  PIN operands[250]
    DIRECTION INPUT ;
    USE SIGNAL ;
    PORT
      LAYER M4 ;
        RECT  0 49.104 0.084 49.128 ;
    END
  END operands[250]
  PIN operands[251]
    DIRECTION INPUT ;
    USE SIGNAL ;
    PORT
      LAYER M4 ;
        RECT  0 49.2 0.084 49.224 ;
    END
  END operands[251]
  PIN operands[252]
    DIRECTION INPUT ;
    USE SIGNAL ;
    PORT
      LAYER M4 ;
        RECT  0 49.296 0.084 49.32 ;
    END
  END operands[252]
  PIN operands[253]
    DIRECTION INPUT ;
    USE SIGNAL ;
    PORT
      LAYER M4 ;
        RECT  0 49.392 0.084 49.416 ;
    END
  END operands[253]
  PIN operands[254]
    DIRECTION INPUT ;
    USE SIGNAL ;
    PORT
      LAYER M4 ;
        RECT  0 49.488 0.084 49.512 ;
    END
  END operands[254]
  PIN operands[255]
    DIRECTION INPUT ;
    USE SIGNAL ;
    PORT
      LAYER M4 ;
        RECT  0 49.584 0.084 49.608 ;
    END
  END operands[255]
  PIN operands[25]
    DIRECTION INPUT ;
    USE SIGNAL ;
    PORT
      LAYER M4 ;
        RECT  0 34.704 0.084 34.728 ;
    END
  END operands[25]
  PIN operands[26]
    DIRECTION INPUT ;
    USE SIGNAL ;
    PORT
      LAYER M4 ;
        RECT  0 34.8 0.084 34.824 ;
    END
  END operands[26]
  PIN operands[27]
    DIRECTION INPUT ;
    USE SIGNAL ;
    PORT
      LAYER M4 ;
        RECT  0 34.896 0.084 34.92 ;
    END
  END operands[27]
  PIN operands[28]
    DIRECTION INPUT ;
    USE SIGNAL ;
    PORT
      LAYER M4 ;
        RECT  0 34.992 0.084 35.016 ;
    END
  END operands[28]
  PIN operands[29]
    DIRECTION INPUT ;
    USE SIGNAL ;
    PORT
      LAYER M4 ;
        RECT  0 35.088 0.084 35.112 ;
    END
  END operands[29]
  PIN operands[2]
    DIRECTION INPUT ;
    USE SIGNAL ;
    PORT
      LAYER M4 ;
        RECT  0 32.496 0.084 32.52 ;
    END
  END operands[2]
  PIN operands[30]
    DIRECTION INPUT ;
    USE SIGNAL ;
    PORT
      LAYER M4 ;
        RECT  0 35.184 0.084 35.208 ;
    END
  END operands[30]
  PIN operands[31]
    DIRECTION INPUT ;
    USE SIGNAL ;
    PORT
      LAYER M4 ;
        RECT  0 35.28 0.084 35.304 ;
    END
  END operands[31]
  PIN operands[32]
    DIRECTION INPUT ;
    USE SIGNAL ;
    PORT
      LAYER M4 ;
        RECT  0 35.376 0.084 35.4 ;
    END
  END operands[32]
  PIN operands[33]
    DIRECTION INPUT ;
    USE SIGNAL ;
    PORT
      LAYER M4 ;
        RECT  0 35.472 0.084 35.496 ;
    END
  END operands[33]
  PIN operands[34]
    DIRECTION INPUT ;
    USE SIGNAL ;
    PORT
      LAYER M4 ;
        RECT  0 35.568 0.084 35.592 ;
    END
  END operands[34]
  PIN operands[35]
    DIRECTION INPUT ;
    USE SIGNAL ;
    PORT
      LAYER M4 ;
        RECT  0 35.664 0.084 35.688 ;
    END
  END operands[35]
  PIN operands[36]
    DIRECTION INPUT ;
    USE SIGNAL ;
    PORT
      LAYER M4 ;
        RECT  0 35.76 0.084 35.784 ;
    END
  END operands[36]
  PIN operands[37]
    DIRECTION INPUT ;
    USE SIGNAL ;
    PORT
      LAYER M4 ;
        RECT  0 35.856 0.084 35.88 ;
    END
  END operands[37]
  PIN operands[38]
    DIRECTION INPUT ;
    USE SIGNAL ;
    PORT
      LAYER M4 ;
        RECT  0 35.952 0.084 35.976 ;
    END
  END operands[38]
  PIN operands[39]
    DIRECTION INPUT ;
    USE SIGNAL ;
    PORT
      LAYER M4 ;
        RECT  0 36.048 0.084 36.072 ;
    END
  END operands[39]
  PIN operands[3]
    DIRECTION INPUT ;
    USE SIGNAL ;
    PORT
      LAYER M4 ;
        RECT  0 32.592 0.084 32.616 ;
    END
  END operands[3]
  PIN operands[40]
    DIRECTION INPUT ;
    USE SIGNAL ;
    PORT
      LAYER M4 ;
        RECT  0 36.144 0.084 36.168 ;
    END
  END operands[40]
  PIN operands[41]
    DIRECTION INPUT ;
    USE SIGNAL ;
    PORT
      LAYER M4 ;
        RECT  0 36.24 0.084 36.264 ;
    END
  END operands[41]
  PIN operands[42]
    DIRECTION INPUT ;
    USE SIGNAL ;
    PORT
      LAYER M4 ;
        RECT  0 36.336 0.084 36.36 ;
    END
  END operands[42]
  PIN operands[43]
    DIRECTION INPUT ;
    USE SIGNAL ;
    PORT
      LAYER M4 ;
        RECT  0 36.432 0.084 36.456 ;
    END
  END operands[43]
  PIN operands[44]
    DIRECTION INPUT ;
    USE SIGNAL ;
    PORT
      LAYER M4 ;
        RECT  0 36.528 0.084 36.552 ;
    END
  END operands[44]
  PIN operands[45]
    DIRECTION INPUT ;
    USE SIGNAL ;
    PORT
      LAYER M4 ;
        RECT  0 36.624 0.084 36.648 ;
    END
  END operands[45]
  PIN operands[46]
    DIRECTION INPUT ;
    USE SIGNAL ;
    PORT
      LAYER M4 ;
        RECT  0 36.72 0.084 36.744 ;
    END
  END operands[46]
  PIN operands[47]
    DIRECTION INPUT ;
    USE SIGNAL ;
    PORT
      LAYER M4 ;
        RECT  0 49.872 0.084 49.896 ;
    END
  END operands[47]
  PIN operands[48]
    DIRECTION INPUT ;
    USE SIGNAL ;
    PORT
      LAYER M4 ;
        RECT  0 49.968 0.084 49.992 ;
    END
  END operands[48]
  PIN operands[49]
    DIRECTION INPUT ;
    USE SIGNAL ;
    PORT
      LAYER M4 ;
        RECT  0 50.064 0.084 50.088 ;
    END
  END operands[49]
  PIN operands[4]
    DIRECTION INPUT ;
    USE SIGNAL ;
    PORT
      LAYER M4 ;
        RECT  0 32.688 0.084 32.712 ;
    END
  END operands[4]
  PIN operands[50]
    DIRECTION INPUT ;
    USE SIGNAL ;
    PORT
      LAYER M4 ;
        RECT  0 50.16 0.084 50.184 ;
    END
  END operands[50]
  PIN operands[51]
    DIRECTION INPUT ;
    USE SIGNAL ;
    PORT
      LAYER M4 ;
        RECT  0 50.256 0.084 50.28 ;
    END
  END operands[51]
  PIN operands[52]
    DIRECTION INPUT ;
    USE SIGNAL ;
    PORT
      LAYER M4 ;
        RECT  0 50.352 0.084 50.376 ;
    END
  END operands[52]
  PIN operands[53]
    DIRECTION INPUT ;
    USE SIGNAL ;
    PORT
      LAYER M4 ;
        RECT  0 50.448 0.084 50.472 ;
    END
  END operands[53]
  PIN operands[54]
    DIRECTION INPUT ;
    USE SIGNAL ;
    PORT
      LAYER M4 ;
        RECT  0 50.544 0.084 50.568 ;
    END
  END operands[54]
  PIN operands[55]
    DIRECTION INPUT ;
    USE SIGNAL ;
    PORT
      LAYER M4 ;
        RECT  0 50.64 0.084 50.664 ;
    END
  END operands[55]
  PIN operands[56]
    DIRECTION INPUT ;
    USE SIGNAL ;
    PORT
      LAYER M4 ;
        RECT  0 50.736 0.084 50.76 ;
    END
  END operands[56]
  PIN operands[57]
    DIRECTION INPUT ;
    USE SIGNAL ;
    PORT
      LAYER M4 ;
        RECT  0 50.832 0.084 50.856 ;
    END
  END operands[57]
  PIN operands[58]
    DIRECTION INPUT ;
    USE SIGNAL ;
    PORT
      LAYER M4 ;
        RECT  0 50.928 0.084 50.952 ;
    END
  END operands[58]
  PIN operands[59]
    DIRECTION INPUT ;
    USE SIGNAL ;
    PORT
      LAYER M4 ;
        RECT  0 51.024 0.084 51.048 ;
    END
  END operands[59]
  PIN operands[5]
    DIRECTION INPUT ;
    USE SIGNAL ;
    PORT
      LAYER M4 ;
        RECT  0 32.784 0.084 32.808 ;
    END
  END operands[5]
  PIN operands[60]
    DIRECTION INPUT ;
    USE SIGNAL ;
    PORT
      LAYER M4 ;
        RECT  0 51.12 0.084 51.144 ;
    END
  END operands[60]
  PIN operands[61]
    DIRECTION INPUT ;
    USE SIGNAL ;
    PORT
      LAYER M4 ;
        RECT  0 51.216 0.084 51.24 ;
    END
  END operands[61]
  PIN operands[62]
    DIRECTION INPUT ;
    USE SIGNAL ;
    PORT
      LAYER M4 ;
        RECT  0 51.312 0.084 51.336 ;
    END
  END operands[62]
  PIN operands[63]
    DIRECTION INPUT ;
    USE SIGNAL ;
    PORT
      LAYER M4 ;
        RECT  0 51.408 0.084 51.432 ;
    END
  END operands[63]
  PIN operands[64]
    DIRECTION INPUT ;
    USE SIGNAL ;
    PORT
      LAYER M4 ;
        RECT  0 51.504 0.084 51.528 ;
    END
  END operands[64]
  PIN operands[65]
    DIRECTION INPUT ;
    USE SIGNAL ;
    PORT
      LAYER M4 ;
        RECT  0 51.6 0.084 51.624 ;
    END
  END operands[65]
  PIN operands[66]
    DIRECTION INPUT ;
    USE SIGNAL ;
    PORT
      LAYER M4 ;
        RECT  0 51.696 0.084 51.72 ;
    END
  END operands[66]
  PIN operands[67]
    DIRECTION INPUT ;
    USE SIGNAL ;
    PORT
      LAYER M4 ;
        RECT  0 51.792 0.084 51.816 ;
    END
  END operands[67]
  PIN operands[68]
    DIRECTION INPUT ;
    USE SIGNAL ;
    PORT
      LAYER M4 ;
        RECT  0 51.888 0.084 51.912 ;
    END
  END operands[68]
  PIN operands[69]
    DIRECTION INPUT ;
    USE SIGNAL ;
    PORT
      LAYER M4 ;
        RECT  0 51.984 0.084 52.008 ;
    END
  END operands[69]
  PIN operands[6]
    DIRECTION INPUT ;
    USE SIGNAL ;
    PORT
      LAYER M4 ;
        RECT  0 32.88 0.084 32.904 ;
    END
  END operands[6]
  PIN operands[70]
    DIRECTION INPUT ;
    USE SIGNAL ;
    PORT
      LAYER M4 ;
        RECT  0 52.08 0.084 52.104 ;
    END
  END operands[70]
  PIN operands[71]
    DIRECTION INPUT ;
    USE SIGNAL ;
    PORT
      LAYER M4 ;
        RECT  0 52.176 0.084 52.2 ;
    END
  END operands[71]
  PIN operands[72]
    DIRECTION INPUT ;
    USE SIGNAL ;
    PORT
      LAYER M4 ;
        RECT  0 52.272 0.084 52.296 ;
    END
  END operands[72]
  PIN operands[73]
    DIRECTION INPUT ;
    USE SIGNAL ;
    PORT
      LAYER M4 ;
        RECT  0 52.368 0.084 52.392 ;
    END
  END operands[73]
  PIN operands[74]
    DIRECTION INPUT ;
    USE SIGNAL ;
    PORT
      LAYER M4 ;
        RECT  0 52.464 0.084 52.488 ;
    END
  END operands[74]
  PIN operands[75]
    DIRECTION INPUT ;
    USE SIGNAL ;
    PORT
      LAYER M4 ;
        RECT  0 52.56 0.084 52.584 ;
    END
  END operands[75]
  PIN operands[76]
    DIRECTION INPUT ;
    USE SIGNAL ;
    PORT
      LAYER M4 ;
        RECT  0 52.656 0.084 52.68 ;
    END
  END operands[76]
  PIN operands[77]
    DIRECTION INPUT ;
    USE SIGNAL ;
    PORT
      LAYER M4 ;
        RECT  0 52.752 0.084 52.776 ;
    END
  END operands[77]
  PIN operands[78]
    DIRECTION INPUT ;
    USE SIGNAL ;
    PORT
      LAYER M4 ;
        RECT  0 52.848 0.084 52.872 ;
    END
  END operands[78]
  PIN operands[79]
    DIRECTION INPUT ;
    USE SIGNAL ;
    PORT
      LAYER M4 ;
        RECT  0 62.928 0.084 62.952 ;
    END
  END operands[79]
  PIN operands[7]
    DIRECTION INPUT ;
    USE SIGNAL ;
    PORT
      LAYER M4 ;
        RECT  0 32.976 0.084 33 ;
    END
  END operands[7]
  PIN operands[80]
    DIRECTION INPUT ;
    USE SIGNAL ;
    PORT
      LAYER M4 ;
        RECT  0 63.024 0.084 63.048 ;
    END
  END operands[80]
  PIN operands[81]
    DIRECTION INPUT ;
    USE SIGNAL ;
    PORT
      LAYER M4 ;
        RECT  0 63.12 0.084 63.144 ;
    END
  END operands[81]
  PIN operands[82]
    DIRECTION INPUT ;
    USE SIGNAL ;
    PORT
      LAYER M4 ;
        RECT  0 63.216 0.084 63.24 ;
    END
  END operands[82]
  PIN operands[83]
    DIRECTION INPUT ;
    USE SIGNAL ;
    PORT
      LAYER M4 ;
        RECT  0 63.312 0.084 63.336 ;
    END
  END operands[83]
  PIN operands[84]
    DIRECTION INPUT ;
    USE SIGNAL ;
    PORT
      LAYER M4 ;
        RECT  0 63.408 0.084 63.432 ;
    END
  END operands[84]
  PIN operands[85]
    DIRECTION INPUT ;
    USE SIGNAL ;
    PORT
      LAYER M4 ;
        RECT  0 63.504 0.084 63.528 ;
    END
  END operands[85]
  PIN operands[86]
    DIRECTION INPUT ;
    USE SIGNAL ;
    PORT
      LAYER M4 ;
        RECT  0 63.6 0.084 63.624 ;
    END
  END operands[86]
  PIN operands[87]
    DIRECTION INPUT ;
    USE SIGNAL ;
    PORT
      LAYER M4 ;
        RECT  0 63.696 0.084 63.72 ;
    END
  END operands[87]
  PIN operands[88]
    DIRECTION INPUT ;
    USE SIGNAL ;
    PORT
      LAYER M4 ;
        RECT  0 63.792 0.084 63.816 ;
    END
  END operands[88]
  PIN operands[89]
    DIRECTION INPUT ;
    USE SIGNAL ;
    PORT
      LAYER M4 ;
        RECT  0 63.888 0.084 63.912 ;
    END
  END operands[89]
  PIN operands[8]
    DIRECTION INPUT ;
    USE SIGNAL ;
    PORT
      LAYER M4 ;
        RECT  0 33.072 0.084 33.096 ;
    END
  END operands[8]
  PIN operands[90]
    DIRECTION INPUT ;
    USE SIGNAL ;
    PORT
      LAYER M4 ;
        RECT  0 63.984 0.084 64.008 ;
    END
  END operands[90]
  PIN operands[91]
    DIRECTION INPUT ;
    USE SIGNAL ;
    PORT
      LAYER M4 ;
        RECT  0 64.08 0.084 64.104 ;
    END
  END operands[91]
  PIN operands[92]
    DIRECTION INPUT ;
    USE SIGNAL ;
    PORT
      LAYER M4 ;
        RECT  0 64.176 0.084 64.2 ;
    END
  END operands[92]
  PIN operands[93]
    DIRECTION INPUT ;
    USE SIGNAL ;
    PORT
      LAYER M4 ;
        RECT  0 64.272 0.084 64.296 ;
    END
  END operands[93]
  PIN operands[94]
    DIRECTION INPUT ;
    USE SIGNAL ;
    PORT
      LAYER M4 ;
        RECT  0 64.368 0.084 64.392 ;
    END
  END operands[94]
  PIN operands[95]
    DIRECTION INPUT ;
    USE SIGNAL ;
    PORT
      LAYER M4 ;
        RECT  0 64.464 0.084 64.488 ;
    END
  END operands[95]
  PIN operands[96]
    DIRECTION INPUT ;
    USE SIGNAL ;
    PORT
      LAYER M4 ;
        RECT  0 64.56 0.084 64.584 ;
    END
  END operands[96]
  PIN operands[97]
    DIRECTION INPUT ;
    USE SIGNAL ;
    PORT
      LAYER M4 ;
        RECT  0 64.656 0.084 64.68 ;
    END
  END operands[97]
  PIN operands[98]
    DIRECTION INPUT ;
    USE SIGNAL ;
    PORT
      LAYER M4 ;
        RECT  0 64.752 0.084 64.776 ;
    END
  END operands[98]
  PIN operands[99]
    DIRECTION INPUT ;
    USE SIGNAL ;
    PORT
      LAYER M4 ;
        RECT  0 64.848 0.084 64.872 ;
    END
  END operands[99]
  PIN operands[9]
    DIRECTION INPUT ;
    USE SIGNAL ;
    PORT
      LAYER M4 ;
        RECT  0 33.168 0.084 33.192 ;
    END
  END operands[9]
  PIN reply[0]
    DIRECTION OUTPUT ;
    USE SIGNAL ;
    PORT
      LAYER M4 ;
        RECT  81.996 51.408 82.08 51.432 ;
    END
  END reply[0]
  PIN reply[10]
    DIRECTION OUTPUT ;
    USE SIGNAL ;
    PORT
      LAYER M4 ;
        RECT  81.996 52.368 82.08 52.392 ;
    END
  END reply[10]
  PIN reply[11]
    DIRECTION OUTPUT ;
    USE SIGNAL ;
    PORT
      LAYER M4 ;
        RECT  81.996 52.464 82.08 52.488 ;
    END
  END reply[11]
  PIN reply[12]
    DIRECTION OUTPUT ;
    USE SIGNAL ;
    PORT
      LAYER M4 ;
        RECT  81.996 52.56 82.08 52.584 ;
    END
  END reply[12]
  PIN reply[13]
    DIRECTION OUTPUT ;
    USE SIGNAL ;
    PORT
      LAYER M4 ;
        RECT  81.996 52.656 82.08 52.68 ;
    END
  END reply[13]
  PIN reply[14]
    DIRECTION OUTPUT ;
    USE SIGNAL ;
    PORT
      LAYER M4 ;
        RECT  81.996 52.752 82.08 52.776 ;
    END
  END reply[14]
  PIN reply[15]
    DIRECTION OUTPUT ;
    USE SIGNAL ;
    PORT
      LAYER M4 ;
        RECT  81.996 52.848 82.08 52.872 ;
    END
  END reply[15]
  PIN reply[16]
    DIRECTION OUTPUT ;
    USE SIGNAL ;
    PORT
      LAYER M4 ;
        RECT  81.996 52.944 82.08 52.968 ;
    END
  END reply[16]
  PIN reply[17]
    DIRECTION OUTPUT ;
    USE SIGNAL ;
    PORT
      LAYER M4 ;
        RECT  81.996 53.04 82.08 53.064 ;
    END
  END reply[17]
  PIN reply[18]
    DIRECTION OUTPUT ;
    USE SIGNAL ;
    PORT
      LAYER M4 ;
        RECT  81.996 53.136 82.08 53.16 ;
    END
  END reply[18]
  PIN reply[19]
    DIRECTION OUTPUT ;
    USE SIGNAL ;
    PORT
      LAYER M4 ;
        RECT  81.996 53.232 82.08 53.256 ;
    END
  END reply[19]
  PIN reply[1]
    DIRECTION OUTPUT ;
    USE SIGNAL ;
    PORT
      LAYER M4 ;
        RECT  81.996 51.504 82.08 51.528 ;
    END
  END reply[1]
  PIN reply[20]
    DIRECTION OUTPUT ;
    USE SIGNAL ;
    PORT
      LAYER M4 ;
        RECT  81.996 53.328 82.08 53.352 ;
    END
  END reply[20]
  PIN reply[21]
    DIRECTION OUTPUT ;
    USE SIGNAL ;
    PORT
      LAYER M4 ;
        RECT  81.996 53.424 82.08 53.448 ;
    END
  END reply[21]
  PIN reply[22]
    DIRECTION OUTPUT ;
    USE SIGNAL ;
    PORT
      LAYER M4 ;
        RECT  81.996 53.52 82.08 53.544 ;
    END
  END reply[22]
  PIN reply[23]
    DIRECTION OUTPUT ;
    USE SIGNAL ;
    PORT
      LAYER M4 ;
        RECT  81.996 53.616 82.08 53.64 ;
    END
  END reply[23]
  PIN reply[24]
    DIRECTION OUTPUT ;
    USE SIGNAL ;
    PORT
      LAYER M4 ;
        RECT  81.996 53.712 82.08 53.736 ;
    END
  END reply[24]
  PIN reply[25]
    DIRECTION OUTPUT ;
    USE SIGNAL ;
    PORT
      LAYER M4 ;
        RECT  81.996 53.808 82.08 53.832 ;
    END
  END reply[25]
  PIN reply[26]
    DIRECTION OUTPUT ;
    USE SIGNAL ;
    PORT
      LAYER M4 ;
        RECT  81.996 53.904 82.08 53.928 ;
    END
  END reply[26]
  PIN reply[27]
    DIRECTION OUTPUT ;
    USE SIGNAL ;
    PORT
      LAYER M4 ;
        RECT  81.996 54 82.08 54.024 ;
    END
  END reply[27]
  PIN reply[28]
    DIRECTION OUTPUT ;
    USE SIGNAL ;
    PORT
      LAYER M4 ;
        RECT  81.996 54.096 82.08 54.12 ;
    END
  END reply[28]
  PIN reply[29]
    DIRECTION OUTPUT ;
    USE SIGNAL ;
    PORT
      LAYER M4 ;
        RECT  81.996 54.192 82.08 54.216 ;
    END
  END reply[29]
  PIN reply[2]
    DIRECTION OUTPUT ;
    USE SIGNAL ;
    PORT
      LAYER M4 ;
        RECT  81.996 51.6 82.08 51.624 ;
    END
  END reply[2]
  PIN reply[30]
    DIRECTION OUTPUT ;
    USE SIGNAL ;
    PORT
      LAYER M4 ;
        RECT  81.996 54.288 82.08 54.312 ;
    END
  END reply[30]
  PIN reply[31]
    DIRECTION OUTPUT ;
    USE SIGNAL ;
    PORT
      LAYER M4 ;
        RECT  81.996 54.384 82.08 54.408 ;
    END
  END reply[31]
  PIN reply[3]
    DIRECTION OUTPUT ;
    USE SIGNAL ;
    PORT
      LAYER M4 ;
        RECT  81.996 51.696 82.08 51.72 ;
    END
  END reply[3]
  PIN reply[4]
    DIRECTION OUTPUT ;
    USE SIGNAL ;
    PORT
      LAYER M4 ;
        RECT  81.996 51.792 82.08 51.816 ;
    END
  END reply[4]
  PIN reply[5]
    DIRECTION OUTPUT ;
    USE SIGNAL ;
    PORT
      LAYER M4 ;
        RECT  81.996 51.888 82.08 51.912 ;
    END
  END reply[5]
  PIN reply[6]
    DIRECTION OUTPUT ;
    USE SIGNAL ;
    PORT
      LAYER M4 ;
        RECT  81.996 51.984 82.08 52.008 ;
    END
  END reply[6]
  PIN reply[7]
    DIRECTION OUTPUT ;
    USE SIGNAL ;
    PORT
      LAYER M4 ;
        RECT  81.996 52.08 82.08 52.104 ;
    END
  END reply[7]
  PIN reply[8]
    DIRECTION OUTPUT ;
    USE SIGNAL ;
    PORT
      LAYER M4 ;
        RECT  81.996 52.176 82.08 52.2 ;
    END
  END reply[8]
  PIN reply[9]
    DIRECTION OUTPUT ;
    USE SIGNAL ;
    PORT
      LAYER M4 ;
        RECT  81.996 52.272 82.08 52.296 ;
    END
  END reply[9]
  PIN reply_err[0]
    DIRECTION OUTPUT ;
    USE SIGNAL ;
    PORT
      LAYER M4 ;
        RECT  81.996 25.392 82.08 25.416 ;
    END
  END reply_err[0]
  PIN reply_err[1]
    DIRECTION OUTPUT ;
    USE SIGNAL ;
    PORT
      LAYER M4 ;
        RECT  81.996 25.488 82.08 25.512 ;
    END
  END reply_err[1]
  PIN reply_index[0]
    DIRECTION OUTPUT ;
    USE SIGNAL ;
    PORT
      LAYER M4 ;
        RECT  81.996 25.584 82.08 25.608 ;
    END
  END reply_index[0]
  PIN reply_index[10]
    DIRECTION OUTPUT ;
    USE SIGNAL ;
    PORT
      LAYER M4 ;
        RECT  81.996 26.544 82.08 26.568 ;
    END
  END reply_index[10]
  PIN reply_index[11]
    DIRECTION OUTPUT ;
    USE SIGNAL ;
    PORT
      LAYER M4 ;
        RECT  81.996 26.64 82.08 26.664 ;
    END
  END reply_index[11]
  PIN reply_index[12]
    DIRECTION OUTPUT ;
    USE SIGNAL ;
    PORT
      LAYER M4 ;
        RECT  81.996 26.736 82.08 26.76 ;
    END
  END reply_index[12]
  PIN reply_index[13]
    DIRECTION OUTPUT ;
    USE SIGNAL ;
    PORT
      LAYER M4 ;
        RECT  81.996 26.832 82.08 26.856 ;
    END
  END reply_index[13]
  PIN reply_index[14]
    DIRECTION OUTPUT ;
    USE SIGNAL ;
    PORT
      LAYER M4 ;
        RECT  81.996 26.928 82.08 26.952 ;
    END
  END reply_index[14]
  PIN reply_index[15]
    DIRECTION OUTPUT ;
    USE SIGNAL ;
    PORT
      LAYER M4 ;
        RECT  81.996 27.024 82.08 27.048 ;
    END
  END reply_index[15]
  PIN reply_index[1]
    DIRECTION OUTPUT ;
    USE SIGNAL ;
    PORT
      LAYER M4 ;
        RECT  81.996 25.68 82.08 25.704 ;
    END
  END reply_index[1]
  PIN reply_index[2]
    DIRECTION OUTPUT ;
    USE SIGNAL ;
    PORT
      LAYER M4 ;
        RECT  81.996 25.776 82.08 25.8 ;
    END
  END reply_index[2]
  PIN reply_index[3]
    DIRECTION OUTPUT ;
    USE SIGNAL ;
    PORT
      LAYER M4 ;
        RECT  81.996 25.872 82.08 25.896 ;
    END
  END reply_index[3]
  PIN reply_index[4]
    DIRECTION OUTPUT ;
    USE SIGNAL ;
    PORT
      LAYER M4 ;
        RECT  81.996 25.968 82.08 25.992 ;
    END
  END reply_index[4]
  PIN reply_index[5]
    DIRECTION OUTPUT ;
    USE SIGNAL ;
    PORT
      LAYER M4 ;
        RECT  81.996 26.064 82.08 26.088 ;
    END
  END reply_index[5]
  PIN reply_index[6]
    DIRECTION OUTPUT ;
    USE SIGNAL ;
    PORT
      LAYER M4 ;
        RECT  81.996 26.16 82.08 26.184 ;
    END
  END reply_index[6]
  PIN reply_index[7]
    DIRECTION OUTPUT ;
    USE SIGNAL ;
    PORT
      LAYER M4 ;
        RECT  81.996 26.256 82.08 26.28 ;
    END
  END reply_index[7]
  PIN reply_index[8]
    DIRECTION OUTPUT ;
    USE SIGNAL ;
    PORT
      LAYER M4 ;
        RECT  81.996 26.352 82.08 26.376 ;
    END
  END reply_index[8]
  PIN reply_index[9]
    DIRECTION OUTPUT ;
    USE SIGNAL ;
    PORT
      LAYER M4 ;
        RECT  81.996 26.448 82.08 26.472 ;
    END
  END reply_index[9]
  PIN reply_v
    DIRECTION OUTPUT ;
    USE SIGNAL ;
    PORT
      LAYER M4 ;
        RECT  81.996 27.12 82.08 27.144 ;
    END
  END reply_v
  PIN rst_n
    DIRECTION INPUT ;
    USE SIGNAL ;
    PORT
      LAYER M4 ;
        RECT  0 49.68 0.084 49.704 ;
    END
  END rst_n
  PIN valid
    DIRECTION INPUT ;
    USE SIGNAL ;
    PORT
      LAYER M4 ;
        RECT  0 49.776 0.084 49.8 ;
    END
  END valid
  PIN VDD
    DIRECTION INOUT ;
    USE POWER ;
    PORT
      LAYER M5 ;
        RECT  78.192 2.151 78.312 79.929 ;
        RECT  72.792 2.151 72.912 79.929 ;
        RECT  67.392 2.151 67.512 79.929 ;
        RECT  61.992 2.151 62.112 79.929 ;
        RECT  56.592 2.151 56.712 79.929 ;
        RECT  51.192 2.151 51.312 79.929 ;
        RECT  45.792 2.151 45.912 79.929 ;
        RECT  40.392 2.151 40.512 79.929 ;
        RECT  34.992 2.151 35.112 79.929 ;
        RECT  29.592 2.151 29.712 79.929 ;
        RECT  24.192 2.151 24.312 79.929 ;
        RECT  18.792 2.151 18.912 79.929 ;
        RECT  13.392 2.151 13.512 79.929 ;
        RECT  7.992 2.151 8.112 79.929 ;
        RECT  2.592 2.151 2.712 79.929 ;
    END
  END VDD
  PIN VSS
    DIRECTION INOUT ;
    USE GROUND ;
    PORT
      LAYER M5 ;
        RECT  78 2.137 78.12 79.943 ;
        RECT  72.6 2.137 72.72 79.943 ;
        RECT  67.2 2.137 67.32 79.943 ;
        RECT  61.8 2.137 61.92 79.943 ;
        RECT  56.4 2.137 56.52 79.943 ;
        RECT  51 2.137 51.12 79.943 ;
        RECT  45.6 2.137 45.72 79.943 ;
        RECT  40.2 2.137 40.32 79.943 ;
        RECT  34.8 2.137 34.92 79.943 ;
        RECT  29.4 2.137 29.52 79.943 ;
        RECT  24 2.137 24.12 79.943 ;
        RECT  18.6 2.137 18.72 79.943 ;
        RECT  13.2 2.137 13.32 79.943 ;
        RECT  7.8 2.137 7.92 79.943 ;
        RECT  2.4 2.137 2.52 79.943 ;
    END
  END VSS
  # OT_OBS_CLOSED layer=M5 d_um=1.536 added=299
  OBS
    LAYER RVTN ;
     RECT  2.16 2.16 79.92 2.295 ;
     RECT  2.16 2.565 79.92 2.835 ;
     RECT  2.16 3.105 79.92 3.375 ;
     RECT  2.16 3.645 79.92 3.915 ;
     RECT  2.16 4.185 79.92 4.455 ;
     RECT  2.16 4.725 79.92 4.995 ;
     RECT  2.16 5.265 79.92 5.535 ;
     RECT  2.16 5.805 79.92 6.075 ;
     RECT  2.16 6.345 79.92 6.615 ;
     RECT  2.16 6.885 79.92 7.155 ;
     RECT  2.16 7.425 79.92 7.695 ;
     RECT  2.16 7.965 79.92 8.235 ;
     RECT  2.16 8.505 79.92 8.775 ;
     RECT  2.16 9.045 79.92 9.315 ;
     RECT  2.16 9.585 79.92 9.855 ;
     RECT  2.16 10.125 79.92 10.395 ;
     RECT  2.16 10.665 79.92 10.935 ;
     RECT  2.16 11.205 79.92 11.475 ;
     RECT  2.16 11.745 79.92 12.015 ;
     RECT  2.16 12.285 79.92 12.555 ;
     RECT  2.16 12.825 79.92 13.095 ;
     RECT  2.16 13.365 79.92 13.635 ;
     RECT  2.16 13.905 79.92 14.175 ;
     RECT  2.16 14.445 79.92 14.715 ;
     RECT  2.16 14.985 79.92 15.255 ;
     RECT  2.16 15.525 79.92 15.795 ;
     RECT  2.16 16.065 79.92 16.335 ;
     RECT  2.16 16.605 79.92 16.875 ;
     RECT  2.16 17.145 79.92 17.415 ;
     RECT  2.16 17.685 79.92 17.955 ;
     RECT  2.16 18.225 79.92 18.495 ;
     RECT  2.16 18.765 79.92 19.035 ;
     RECT  2.16 19.305 79.92 19.575 ;
     RECT  2.16 19.845 79.92 20.115 ;
     RECT  2.16 20.385 79.92 20.655 ;
     RECT  2.16 20.925 79.92 21.195 ;
     RECT  2.16 21.465 79.92 21.735 ;
     RECT  2.16 22.005 79.92 22.275 ;
     RECT  2.16 22.545 79.92 22.815 ;
     RECT  2.16 23.085 79.92 23.355 ;
     RECT  2.16 23.625 79.92 23.895 ;
     RECT  2.16 24.165 79.92 24.435 ;
     RECT  2.16 24.705 79.92 24.975 ;
     RECT  2.16 25.245 79.92 25.515 ;
     RECT  2.16 25.785 79.92 26.055 ;
     RECT  2.16 26.325 79.92 26.595 ;
     RECT  2.16 26.865 79.92 27.135 ;
     RECT  2.16 27.405 79.92 27.675 ;
     RECT  2.16 27.945 79.92 28.215 ;
     RECT  2.16 28.485 79.92 28.755 ;
     RECT  2.16 29.025 79.92 29.295 ;
     RECT  2.16 29.565 79.92 29.835 ;
     RECT  2.16 30.105 79.92 30.375 ;
     RECT  2.16 30.645 79.92 30.915 ;
     RECT  2.16 31.185 79.92 31.455 ;
     RECT  2.16 31.725 79.92 31.995 ;
     RECT  2.16 32.265 79.92 32.535 ;
     RECT  2.16 32.805 79.92 33.075 ;
     RECT  2.16 33.345 79.92 33.615 ;
     RECT  2.16 33.885 79.92 34.155 ;
     RECT  2.16 34.425 79.92 34.695 ;
     RECT  2.16 34.965 79.92 35.235 ;
     RECT  2.16 35.505 79.92 35.775 ;
     RECT  2.16 36.045 79.92 36.315 ;
     RECT  2.16 36.585 79.92 36.855 ;
     RECT  2.16 37.125 79.92 37.395 ;
     RECT  2.16 37.665 79.92 37.935 ;
     RECT  2.16 38.205 79.92 38.475 ;
     RECT  2.16 38.745 79.92 39.015 ;
     RECT  2.16 39.285 79.92 39.555 ;
     RECT  2.16 39.825 79.92 40.095 ;
     RECT  2.16 40.365 79.92 40.635 ;
     RECT  2.16 40.905 79.92 41.175 ;
     RECT  2.16 41.445 79.92 41.715 ;
     RECT  2.16 41.985 79.92 42.255 ;
     RECT  2.16 42.525 79.92 42.795 ;
     RECT  2.16 43.065 79.92 43.335 ;
     RECT  2.16 43.605 79.92 43.875 ;
     RECT  2.16 44.145 79.92 44.415 ;
     RECT  2.16 44.685 79.92 44.955 ;
     RECT  2.16 45.225 79.92 45.495 ;
     RECT  2.16 45.765 79.92 46.035 ;
     RECT  2.16 46.305 79.92 46.575 ;
     RECT  2.16 46.845 79.92 47.115 ;
     RECT  2.16 47.385 79.92 47.655 ;
     RECT  2.16 47.925 79.92 48.195 ;
     RECT  2.16 48.465 79.92 48.735 ;
     RECT  2.16 49.005 79.92 49.275 ;
     RECT  2.16 49.545 79.92 49.815 ;
     RECT  2.16 50.085 79.92 50.355 ;
     RECT  2.16 50.625 79.92 50.895 ;
     RECT  2.16 51.165 79.92 51.435 ;
     RECT  2.16 51.705 79.92 51.975 ;
     RECT  2.16 52.245 79.92 52.515 ;
     RECT  2.16 52.785 79.92 53.055 ;
     RECT  2.16 53.325 79.92 53.595 ;
     RECT  2.16 53.865 79.92 54.135 ;
     RECT  2.16 54.405 79.92 54.675 ;
     RECT  2.16 54.945 79.92 55.215 ;
     RECT  2.16 55.485 79.92 55.755 ;
     RECT  2.16 56.025 79.92 56.295 ;
     RECT  2.16 56.565 79.92 56.835 ;
     RECT  2.16 57.105 79.92 57.375 ;
     RECT  2.16 57.645 79.92 57.915 ;
     RECT  2.16 58.185 79.92 58.455 ;
     RECT  2.16 58.725 79.92 58.995 ;
     RECT  2.16 59.265 79.92 59.535 ;
     RECT  2.16 59.805 79.92 60.075 ;
     RECT  2.16 60.345 79.92 60.615 ;
     RECT  2.16 60.885 79.92 61.155 ;
     RECT  2.16 61.425 79.92 61.695 ;
     RECT  2.16 61.965 79.92 62.235 ;
     RECT  2.16 62.505 79.92 62.775 ;
     RECT  2.16 63.045 79.92 63.315 ;
     RECT  2.16 63.585 79.92 63.855 ;
     RECT  2.16 64.125 79.92 64.395 ;
     RECT  2.16 64.665 79.92 64.935 ;
     RECT  2.16 65.205 79.92 65.475 ;
     RECT  2.16 65.745 79.92 66.015 ;
     RECT  2.16 66.285 79.92 66.555 ;
     RECT  2.16 66.825 79.92 67.095 ;
     RECT  2.16 67.365 79.92 67.635 ;
     RECT  2.16 67.905 79.92 68.175 ;
     RECT  2.16 68.445 79.92 68.715 ;
     RECT  2.16 68.985 79.92 69.255 ;
     RECT  2.16 69.525 79.92 69.795 ;
     RECT  2.16 70.065 79.92 70.335 ;
     RECT  2.16 70.605 79.92 70.875 ;
     RECT  2.16 71.145 79.92 71.415 ;
     RECT  2.16 71.685 79.92 71.955 ;
     RECT  2.16 72.225 79.92 72.495 ;
     RECT  2.16 72.765 79.92 73.035 ;
     RECT  2.16 73.305 79.92 73.575 ;
     RECT  2.16 73.845 79.92 74.115 ;
     RECT  2.16 74.385 79.92 74.655 ;
     RECT  2.16 74.925 79.92 75.195 ;
     RECT  2.16 75.465 79.92 75.735 ;
     RECT  2.16 76.005 79.92 76.275 ;
     RECT  2.16 76.545 79.92 76.815 ;
     RECT  2.16 77.085 79.92 77.355 ;
     RECT  2.16 77.625 79.92 77.895 ;
     RECT  2.16 78.165 79.92 78.435 ;
     RECT  2.16 78.705 79.92 78.975 ;
     RECT  2.16 79.245 79.92 79.515 ;
     RECT  2.16 79.785 79.92 79.92 ;
    LAYER RVTP ;
     RECT  2.16 2.295 79.92 2.565 ;
     RECT  2.16 2.835 79.92 3.105 ;
     RECT  2.16 3.375 79.92 3.645 ;
     RECT  2.16 3.915 79.92 4.185 ;
     RECT  2.16 4.455 79.92 4.725 ;
     RECT  2.16 4.995 79.92 5.265 ;
     RECT  2.16 5.535 79.92 5.805 ;
     RECT  2.16 6.075 79.92 6.345 ;
     RECT  2.16 6.615 79.92 6.885 ;
     RECT  2.16 7.155 79.92 7.425 ;
     RECT  2.16 7.695 79.92 7.965 ;
     RECT  2.16 8.235 79.92 8.505 ;
     RECT  2.16 8.775 79.92 9.045 ;
     RECT  2.16 9.315 79.92 9.585 ;
     RECT  2.16 9.855 79.92 10.125 ;
     RECT  2.16 10.395 79.92 10.665 ;
     RECT  2.16 10.935 79.92 11.205 ;
     RECT  2.16 11.475 79.92 11.745 ;
     RECT  2.16 12.015 79.92 12.285 ;
     RECT  2.16 12.555 79.92 12.825 ;
     RECT  2.16 13.095 79.92 13.365 ;
     RECT  2.16 13.635 79.92 13.905 ;
     RECT  2.16 14.175 79.92 14.445 ;
     RECT  2.16 14.715 79.92 14.985 ;
     RECT  2.16 15.255 79.92 15.525 ;
     RECT  2.16 15.795 79.92 16.065 ;
     RECT  2.16 16.335 79.92 16.605 ;
     RECT  2.16 16.875 79.92 17.145 ;
     RECT  2.16 17.415 79.92 17.685 ;
     RECT  2.16 17.955 79.92 18.225 ;
     RECT  2.16 18.495 79.92 18.765 ;
     RECT  2.16 19.035 79.92 19.305 ;
     RECT  2.16 19.575 79.92 19.845 ;
     RECT  2.16 20.115 79.92 20.385 ;
     RECT  2.16 20.655 79.92 20.925 ;
     RECT  2.16 21.195 79.92 21.465 ;
     RECT  2.16 21.735 79.92 22.005 ;
     RECT  2.16 22.275 79.92 22.545 ;
     RECT  2.16 22.815 79.92 23.085 ;
     RECT  2.16 23.355 79.92 23.625 ;
     RECT  2.16 23.895 79.92 24.165 ;
     RECT  2.16 24.435 79.92 24.705 ;
     RECT  2.16 24.975 79.92 25.245 ;
     RECT  2.16 25.515 79.92 25.785 ;
     RECT  2.16 26.055 79.92 26.325 ;
     RECT  2.16 26.595 79.92 26.865 ;
     RECT  2.16 27.135 79.92 27.405 ;
     RECT  2.16 27.675 79.92 27.945 ;
     RECT  2.16 28.215 79.92 28.485 ;
     RECT  2.16 28.755 79.92 29.025 ;
     RECT  2.16 29.295 79.92 29.565 ;
     RECT  2.16 29.835 79.92 30.105 ;
     RECT  2.16 30.375 79.92 30.645 ;
     RECT  2.16 30.915 79.92 31.185 ;
     RECT  2.16 31.455 79.92 31.725 ;
     RECT  2.16 31.995 79.92 32.265 ;
     RECT  2.16 32.535 79.92 32.805 ;
     RECT  2.16 33.075 79.92 33.345 ;
     RECT  2.16 33.615 79.92 33.885 ;
     RECT  2.16 34.155 79.92 34.425 ;
     RECT  2.16 34.695 79.92 34.965 ;
     RECT  2.16 35.235 79.92 35.505 ;
     RECT  2.16 35.775 79.92 36.045 ;
     RECT  2.16 36.315 79.92 36.585 ;
     RECT  2.16 36.855 79.92 37.125 ;
     RECT  2.16 37.395 79.92 37.665 ;
     RECT  2.16 37.935 79.92 38.205 ;
     RECT  2.16 38.475 79.92 38.745 ;
     RECT  2.16 39.015 79.92 39.285 ;
     RECT  2.16 39.555 79.92 39.825 ;
     RECT  2.16 40.095 79.92 40.365 ;
     RECT  2.16 40.635 79.92 40.905 ;
     RECT  2.16 41.175 79.92 41.445 ;
     RECT  2.16 41.715 79.92 41.985 ;
     RECT  2.16 42.255 79.92 42.525 ;
     RECT  2.16 42.795 79.92 43.065 ;
     RECT  2.16 43.335 79.92 43.605 ;
     RECT  2.16 43.875 79.92 44.145 ;
     RECT  2.16 44.415 79.92 44.685 ;
     RECT  2.16 44.955 79.92 45.225 ;
     RECT  2.16 45.495 79.92 45.765 ;
     RECT  2.16 46.035 79.92 46.305 ;
     RECT  2.16 46.575 79.92 46.845 ;
     RECT  2.16 47.115 79.92 47.385 ;
     RECT  2.16 47.655 79.92 47.925 ;
     RECT  2.16 48.195 79.92 48.465 ;
     RECT  2.16 48.735 79.92 49.005 ;
     RECT  2.16 49.275 79.92 49.545 ;
     RECT  2.16 49.815 79.92 50.085 ;
     RECT  2.16 50.355 79.92 50.625 ;
     RECT  2.16 50.895 79.92 51.165 ;
     RECT  2.16 51.435 79.92 51.705 ;
     RECT  2.16 51.975 79.92 52.245 ;
     RECT  2.16 52.515 79.92 52.785 ;
     RECT  2.16 53.055 79.92 53.325 ;
     RECT  2.16 53.595 79.92 53.865 ;
     RECT  2.16 54.135 79.92 54.405 ;
     RECT  2.16 54.675 79.92 54.945 ;
     RECT  2.16 55.215 79.92 55.485 ;
     RECT  2.16 55.755 79.92 56.025 ;
     RECT  2.16 56.295 79.92 56.565 ;
     RECT  2.16 56.835 79.92 57.105 ;
     RECT  2.16 57.375 79.92 57.645 ;
     RECT  2.16 57.915 79.92 58.185 ;
     RECT  2.16 58.455 79.92 58.725 ;
     RECT  2.16 58.995 79.92 59.265 ;
     RECT  2.16 59.535 79.92 59.805 ;
     RECT  2.16 60.075 79.92 60.345 ;
     RECT  2.16 60.615 79.92 60.885 ;
     RECT  2.16 61.155 79.92 61.425 ;
     RECT  2.16 61.695 79.92 61.965 ;
     RECT  2.16 62.235 79.92 62.505 ;
     RECT  2.16 62.775 79.92 63.045 ;
     RECT  2.16 63.315 79.92 63.585 ;
     RECT  2.16 63.855 79.92 64.125 ;
     RECT  2.16 64.395 79.92 64.665 ;
     RECT  2.16 64.935 79.92 65.205 ;
     RECT  2.16 65.475 79.92 65.745 ;
     RECT  2.16 66.015 79.92 66.285 ;
     RECT  2.16 66.555 79.92 66.825 ;
     RECT  2.16 67.095 79.92 67.365 ;
     RECT  2.16 67.635 79.92 67.905 ;
     RECT  2.16 68.175 79.92 68.445 ;
     RECT  2.16 68.715 79.92 68.985 ;
     RECT  2.16 69.255 79.92 69.525 ;
     RECT  2.16 69.795 79.92 70.065 ;
     RECT  2.16 70.335 79.92 70.605 ;
     RECT  2.16 70.875 79.92 71.145 ;
     RECT  2.16 71.415 79.92 71.685 ;
     RECT  2.16 71.955 79.92 72.225 ;
     RECT  2.16 72.495 79.92 72.765 ;
     RECT  2.16 73.035 79.92 73.305 ;
     RECT  2.16 73.575 79.92 73.845 ;
     RECT  2.16 74.115 79.92 74.385 ;
     RECT  2.16 74.655 79.92 74.925 ;
     RECT  2.16 75.195 79.92 75.465 ;
     RECT  2.16 75.735 79.92 76.005 ;
     RECT  2.16 76.275 79.92 76.545 ;
     RECT  2.16 76.815 79.92 77.085 ;
     RECT  2.16 77.355 79.92 77.625 ;
     RECT  2.16 77.895 79.92 78.165 ;
     RECT  2.16 78.435 79.92 78.705 ;
     RECT  2.16 78.975 79.92 79.245 ;
     RECT  2.16 79.515 79.92 79.785 ;
    LAYER M1 ;
     RECT  2.16 2.151 79.92 79.929 ;
    LAYER M2 ;
     RECT  0.031 40.41 0.103 40.428 ;
     RECT  0.031 54.684 0.103 54.702 ;
     RECT  0.031 65.646 0.103 65.664 ;
     RECT  0.031 42.768 0.131 42.786 ;
     RECT  0.103 30.69 0.139 30.978 ;
     RECT  0.031 31.896 0.139 31.914 ;
     RECT  0.103 44.424 0.139 45.216 ;
     RECT  0.103 47.862 0.139 47.88 ;
     RECT  0.103 48.942 0.139 49.338 ;
     RECT  0.103 51.291 0.139 51.309 ;
     RECT  0.103 62.55 0.139 62.568 ;
     RECT  0.103 64.98 0.167 66.159 ;
     RECT  0.103 18.162 0.175 18.72 ;
     RECT  0.139 23.67 0.175 23.688 ;
     RECT  0.103 24.48 0.175 24.768 ;
     RECT  0.031 29.34 0.175 29.358 ;
     RECT  0.139 30.42 0.175 30.978 ;
     RECT  0.139 31.896 0.175 32.292 ;
     RECT  0.139 47.7 0.175 49.338 ;
     RECT  0.103 58.5 0.175 58.518 ;
     RECT  0.103 16.65 0.211 16.668 ;
     RECT  0.175 17.46 0.211 18.72 ;
     RECT  0.103 60.93 0.247 60.948 ;
     RECT  0.175 61.74 0.247 61.758 ;
     RECT  0.175 23.67 0.535 24.768 ;
     RECT  0.139 25.56 0.535 25.578 ;
     RECT  0.175 29.34 0.535 32.292 ;
     RECT  0.103 33.048 0.535 33.066 ;
     RECT  0.103 59.814 0.535 59.832 ;
     RECT  0.247 60.93 0.535 61.758 ;
     RECT  0.535 23.67 0.571 25.578 ;
     RECT  0.139 57.654 0.571 57.672 ;
     RECT  0.031 67.842 0.571 67.86 ;
     RECT  0.167 66.141 0.599 66.159 ;
     RECT  0.103 39.762 0.607 40.428 ;
     RECT  0.167 64.98 0.635 64.998 ;
     RECT  0.103 54.342 0.823 54.702 ;
     RECT  0.031 55.692 0.823 55.71 ;
     RECT  0.571 41.49 0.859 41.508 ;
     RECT  0.823 54.342 0.859 55.71 ;
     RECT  0.139 51.291 0.887 51.894 ;
     RECT  0.535 59.814 1.139 61.758 ;
     RECT  0.887 51.876 1.175 51.894 ;
     RECT  0.175 19.89 1.723 19.908 ;
     RECT  0.535 29.34 1.723 33.174 ;
     RECT  0.607 39.492 1.723 40.428 ;
     RECT  0.571 53.262 1.723 53.28 ;
     RECT  0.571 57.42 1.723 57.672 ;
     RECT  1.723 19.89 1.759 20.61 ;
     RECT  1.723 52.452 1.759 53.55 ;
     RECT  0.859 54.342 1.759 55.98 ;
     RECT  1.759 19.89 1.795 20.682 ;
     RECT  0.571 21.672 1.795 21.69 ;
     RECT  1.795 19.89 1.831 21.69 ;
     RECT  0.571 67.302 1.903 67.86 ;
     RECT  0.139 15.3 2.16 15.318 ;
     RECT  0.211 16.65 2.16 18.72 ;
     RECT  1.831 19.89 2.16 21.762 ;
     RECT  0.571 23.328 2.16 25.578 ;
     RECT  1.723 29.034 2.16 33.174 ;
     RECT  0.103 34.74 2.16 34.758 ;
     RECT  0.103 35.82 2.16 35.838 ;
     RECT  0.535 37.062 2.16 37.08 ;
     RECT  1.723 39.222 2.16 40.428 ;
     RECT  0.859 41.49 2.16 41.778 ;
     RECT  1.399 42.732 2.16 42.75 ;
     RECT  0.139 43.848 2.16 45.216 ;
     RECT  0.175 47.628 2.16 49.338 ;
     RECT  1.759 52.452 2.16 55.98 ;
     RECT  1.723 57.15 2.16 57.672 ;
     RECT  0.175 58.5 2.16 58.986 ;
     RECT  1.139 60.354 2.16 61.758 ;
     RECT  0.139 62.55 2.16 62.838 ;
     RECT  0.139 63.828 2.16 63.846 ;
     RECT  0.607 66.222 2.16 66.24 ;
     RECT  1.903 67.104 2.16 67.86 ;
     RECT  2.16 2.151 12.595 79.929 ;
     RECT  12.595 2.106 12.911 79.929 ;
     RECT  12.911 2.151 57.739 79.929 ;
     RECT  57.739 2.106 74.255 79.929 ;
     RECT  74.255 2.151 79.92 79.929 ;
     RECT  79.92 59.166 80.087 59.184 ;
     RECT  79.92 51.444 80.879 56.214 ;
     RECT  79.92 27.648 80.915 28.674 ;
     RECT  80.879 51.444 80.915 54.054 ;
     RECT  79.92 25.488 80.951 26.784 ;
     RECT  80.915 51.444 80.951 53.964 ;
     RECT  79.92 24.336 80.987 24.462 ;
     RECT  79.92 49.446 80.987 50.454 ;
     RECT  80.951 51.444 80.987 53.01 ;
     RECT  80.987 51.444 81.023 52.074 ;
     RECT  81.023 51.444 81.059 51.894 ;
     RECT  81.059 51.444 81.455 51.804 ;
     RECT  80.951 25.992 81.491 26.046 ;
     RECT  81.455 51.786 81.491 51.804 ;
     RECT  80.987 52.992 81.491 53.01 ;
     RECT  81.491 26.028 81.527 26.046 ;
     RECT  80.879 55.026 81.851 56.214 ;
     RECT  80.915 28.224 81.887 28.674 ;
     RECT  81.851 55.026 81.887 55.674 ;
     RECT  79.92 29.736 81.923 30.294 ;
     RECT  81.887 55.026 81.923 55.584 ;
     RECT  80.987 24.444 81.959 24.462 ;
     RECT  81.859 26.802 81.959 26.82 ;
     RECT  81.887 28.656 81.959 28.674 ;
     RECT  81.923 55.116 81.959 55.584 ;
     RECT  81.923 30.276 81.995 30.294 ;
     RECT  80.987 49.446 81.995 50.148 ;
     RECT  81.959 55.566 81.995 55.584 ;
     RECT  79.92 22.212 82.067 22.23 ;
     RECT  81.995 49.446 82.067 49.464 ;
     RECT  81.967 52.056 82.067 52.074 ;
    LAYER M3 ;
     RECT  12.6 2.101 12.906 2.143 ;
     RECT  62.496 2.101 62.73 2.143 ;
     RECT  66.708 2.101 67.194 2.143 ;
     RECT  18.615 2.143 18.705 2.191 ;
     RECT  29.415 2.143 29.505 2.191 ;
     RECT  40.215 2.143 40.305 2.191 ;
     RECT  56.415 2.143 56.505 2.191 ;
     RECT  72.615 2.143 72.705 2.191 ;
     RECT  51.015 2.143 51.105 2.227 ;
     RECT  66.708 2.143 67.305 2.227 ;
     RECT  55.224 2.191 55.242 2.251 ;
     RECT  56.415 2.191 56.574 2.251 ;
     RECT  57.744 2.101 57.762 2.251 ;
     RECT  58.716 2.101 58.806 2.251 ;
     RECT  72.576 2.191 72.705 2.251 ;
     RECT  22.572 2.191 22.59 2.263 ;
     RECT  40.176 2.191 40.305 2.263 ;
     RECT  41.58 2.227 41.85 2.263 ;
     RECT  45.615 2.143 45.705 2.263 ;
     RECT  46.764 2.227 46.782 2.263 ;
     RECT  75.06 2.191 75.078 2.263 ;
     RECT  18.216 2.191 18.705 2.293 ;
     RECT  12.6 2.143 13.305 2.299 ;
     RECT  40.176 2.263 41.85 2.299 ;
     RECT  48.132 2.227 48.15 2.299 ;
     RECT  49.032 2.263 49.05 2.299 ;
     RECT  53.316 2.263 53.334 2.299 ;
     RECT  61.815 2.143 62.73 2.299 ;
     RECT  63.468 2.263 63.882 2.299 ;
     RECT  72.324 2.251 72.705 2.299 ;
     RECT  14.976 2.299 14.994 2.335 ;
     RECT  19.656 2.299 20.214 2.335 ;
     RECT  21.024 2.299 21.042 2.335 ;
     RECT  22.572 2.263 22.842 2.335 ;
     RECT  40.176 2.299 42.39 2.335 ;
     RECT  61.308 2.299 63.882 2.335 ;
     RECT  70.452 2.251 70.47 2.335 ;
     RECT  10.98 2.335 10.998 2.371 ;
     RECT  14.976 2.335 15.498 2.371 ;
     RECT  25.632 2.191 25.65 2.371 ;
     RECT  29.376 2.191 29.505 2.371 ;
     RECT  31.572 2.335 31.59 2.371 ;
     RECT  32.508 2.191 32.526 2.371 ;
     RECT  40.14 2.335 42.39 2.371 ;
     RECT  43.128 2.227 43.146 2.371 ;
     RECT  45.615 2.263 46.782 2.371 ;
     RECT  55.224 2.251 57.762 2.371 ;
     RECT  58.716 2.251 58.95 2.371 ;
     RECT  66.564 2.227 67.986 2.371 ;
     RECT  70.128 2.335 70.47 2.371 ;
     RECT  71.46 2.251 71.478 2.371 ;
     RECT  72.324 2.299 72.774 2.371 ;
     RECT  74.232 2.101 74.25 2.371 ;
     RECT  75.06 2.263 75.798 2.371 ;
     RECT  2.415 2.143 2.505 2.413 ;
     RECT  7.815 2.143 7.905 2.413 ;
     RECT  18.216 2.293 18.774 2.413 ;
     RECT  24.015 2.143 24.105 2.413 ;
     RECT  29.376 2.371 29.574 2.413 ;
     RECT  34.815 2.143 34.905 2.413 ;
     RECT  35.748 2.371 35.766 2.413 ;
     RECT  50.292 2.227 51.105 2.413 ;
     RECT  70.128 2.371 72.774 2.413 ;
     RECT  78.015 2.143 78.105 2.413 ;
     RECT  12.6 2.299 14.022 2.461 ;
     RECT  14.976 2.371 15.714 2.461 ;
     RECT  16.776 2.371 16.794 2.461 ;
     RECT  18.216 2.413 18.897 2.461 ;
     RECT  19.656 2.335 22.842 2.461 ;
     RECT  25.308 2.371 25.65 2.461 ;
     RECT  26.748 2.371 26.766 2.461 ;
     RECT  30.852 2.371 32.526 2.461 ;
     RECT  34.815 2.413 35.766 2.461 ;
     RECT  40.14 2.371 46.782 2.461 ;
     RECT  48.132 2.299 49.05 2.461 ;
     RECT  60.48 2.335 60.498 2.461 ;
     RECT  61.236 2.335 63.882 2.461 ;
     RECT  64.872 2.371 64.89 2.461 ;
     RECT  66.132 2.371 68.13 2.461 ;
     RECT  16.776 2.461 22.842 2.488 ;
     RECT  64.872 2.461 68.13 2.489 ;
     RECT  5.724 2.299 5.742 2.497 ;
     RECT  12.528 2.461 15.714 2.497 ;
     RECT  26.604 2.461 26.766 2.497 ;
     RECT  27.612 2.371 27.63 2.497 ;
     RECT  30.852 2.461 32.67 2.497 ;
     RECT  59.724 2.371 59.742 2.497 ;
     RECT  60.48 2.461 63.882 2.497 ;
     RECT  76.968 2.371 76.986 2.525 ;
     RECT  25.308 2.461 25.722 2.533 ;
     RECT  26.604 2.497 27.63 2.533 ;
     RECT  34.056 2.461 35.766 2.533 ;
     RECT  48.132 2.461 49.158 2.533 ;
     RECT  50.292 2.413 51.297 2.533 ;
     RECT  16.74 2.488 22.842 2.569 ;
     RECT  24.015 2.413 24.297 2.569 ;
     RECT  33.66 2.533 35.766 2.569 ;
     RECT  37.044 2.371 37.062 2.569 ;
     RECT  54.288 2.371 54.45 2.569 ;
     RECT  55.224 2.371 58.95 2.569 ;
     RECT  24.015 2.569 24.354 2.587 ;
     RECT  25.308 2.533 27.63 2.587 ;
     RECT  7.815 2.413 8.097 2.605 ;
     RECT  8.892 2.539 8.91 2.605 ;
     RECT  10.908 2.371 10.998 2.605 ;
     RECT  16.704 2.569 22.842 2.605 ;
     RECT  23.58 2.587 27.63 2.605 ;
     RECT  29.376 2.413 29.697 2.605 ;
     RECT  30.708 2.497 32.886 2.605 ;
     RECT  33.66 2.569 35.946 2.605 ;
     RECT  37.044 2.569 37.422 2.605 ;
     RECT  52.848 2.299 53.334 2.605 ;
     RECT  3.924 2.461 3.942 2.641 ;
     RECT  16.704 2.605 27.63 2.641 ;
     RECT  30.708 2.605 35.946 2.641 ;
     RECT  37.044 2.605 37.53 2.641 ;
     RECT  39.204 2.587 39.222 2.641 ;
     RECT  40.14 2.461 47.214 2.641 ;
     RECT  54.288 2.569 58.95 2.641 ;
     RECT  59.724 2.497 63.882 2.641 ;
     RECT  70.128 2.413 72.897 2.641 ;
     RECT  74.232 2.371 76.194 2.641 ;
     RECT  78.015 2.413 78.297 2.641 ;
     RECT  10.908 2.605 11.214 2.669 ;
     RECT  30.708 2.641 37.566 2.725 ;
     RECT  2.415 2.413 2.697 2.731 ;
     RECT  3.924 2.641 4.338 2.731 ;
     RECT  16.596 2.641 27.63 2.731 ;
     RECT  39.204 2.641 39.402 2.731 ;
     RECT  16.56 2.731 27.63 2.759 ;
     RECT  26.064 2.759 27.63 2.767 ;
     RECT  30.708 2.725 37.638 2.767 ;
     RECT  52.38 2.605 53.334 2.767 ;
     RECT  54.288 2.641 63.882 2.767 ;
     RECT  5.724 2.497 6.426 2.803 ;
     RECT  7.416 2.605 8.91 2.803 ;
     RECT  9.828 2.533 9.846 2.803 ;
     RECT  26.064 2.767 27.702 2.803 ;
     RECT  30.6 2.767 37.638 2.803 ;
     RECT  39.132 2.731 39.402 2.803 ;
     RECT  52.308 2.767 53.334 2.803 ;
     RECT  54.18 2.767 63.882 2.803 ;
     RECT  28.656 2.605 29.79 2.827 ;
     RECT  30.6 2.803 37.854 2.827 ;
     RECT  16.56 2.759 25.218 2.839 ;
     RECT  38.844 2.803 39.402 2.839 ;
     RECT  64.872 2.489 67.986 2.839 ;
     RECT  69.192 2.191 69.21 2.839 ;
     RECT  2.415 2.731 4.806 2.875 ;
     RECT  5.724 2.803 9.054 2.875 ;
     RECT  10.98 2.669 11.214 2.875 ;
     RECT  12.204 2.497 15.714 2.875 ;
     RECT  26.064 2.803 27.882 2.875 ;
     RECT  28.656 2.827 37.854 2.875 ;
     RECT  38.7 2.839 39.402 2.875 ;
     RECT  52.308 2.803 63.882 2.875 ;
     RECT  64.764 2.839 67.986 2.875 ;
     RECT  69.084 2.839 69.246 2.875 ;
     RECT  10.98 2.875 15.714 2.911 ;
     RECT  16.488 2.839 25.218 2.911 ;
     RECT  26.064 2.875 39.402 2.911 ;
     RECT  40.14 2.641 47.358 2.911 ;
     RECT  48.132 2.533 51.297 2.911 ;
     RECT  52.308 2.875 67.986 2.911 ;
     RECT  69.084 2.875 69.318 3.001 ;
     RECT  70.128 2.641 76.194 3.001 ;
     RECT  9.828 2.803 10.134 3.019 ;
     RECT  69.084 3.001 76.194 3.029 ;
     RECT  10.98 2.911 25.218 3.065 ;
     RECT  48.132 2.911 67.986 3.065 ;
     RECT  2.415 2.875 9.054 3.073 ;
     RECT  9.828 3.019 10.206 3.073 ;
     RECT  69.12 3.029 76.194 3.109 ;
     RECT  26.064 2.911 47.358 3.145 ;
     RECT  48.132 3.065 53.622 3.145 ;
     RECT  69.12 3.109 76.23 3.173 ;
     RECT  70.056 3.173 76.23 3.181 ;
     RECT  77.112 2.641 78.297 3.181 ;
     RECT  10.98 3.065 24.354 3.209 ;
     RECT  70.056 3.181 76.302 3.271 ;
     RECT  77.112 3.181 78.354 3.271 ;
     RECT  12.384 3.209 24.354 3.299 ;
     RECT  54.36 3.065 67.986 3.299 ;
     RECT  69.12 3.173 69.246 3.299 ;
     RECT  70.056 3.271 78.354 3.299 ;
     RECT  54.432 3.299 67.986 3.341 ;
     RECT  54.432 3.341 56.697 3.371 ;
     RECT  70.056 3.299 73.602 3.371 ;
     RECT  12.816 3.299 24.297 3.437 ;
     RECT  12.996 3.437 24.297 3.443 ;
     RECT  2.415 3.073 10.206 3.451 ;
     RECT  10.98 3.209 11.646 3.451 ;
     RECT  57.456 3.341 67.986 3.451 ;
     RECT  26.064 3.145 53.622 3.569 ;
     RECT  26.064 3.569 53.226 3.581 ;
     RECT  26.064 3.581 29.97 3.649 ;
     RECT  15.12 3.443 24.297 3.713 ;
     RECT  25.128 3.065 25.218 3.713 ;
     RECT  30.744 3.581 53.226 3.749 ;
     RECT  74.448 3.299 78.354 3.883 ;
     RECT  57.456 3.451 68.094 3.955 ;
     RECT  74.448 3.883 78.462 3.955 ;
     RECT  12.996 3.443 13.95 3.983 ;
     RECT  2.415 3.451 11.646 3.991 ;
     RECT  57.456 3.955 68.202 4.081 ;
     RECT  69.12 3.299 69.138 4.081 ;
     RECT  54.72 3.371 56.697 4.117 ;
     RECT  57.456 4.081 69.138 4.117 ;
     RECT  70.056 3.371 70.398 4.189 ;
     RECT  71.136 3.371 73.602 4.189 ;
     RECT  74.448 3.955 78.75 4.253 ;
     RECT  2.415 3.991 11.934 4.261 ;
     RECT  15.12 3.713 23.202 4.261 ;
     RECT  25.2 3.713 25.218 4.261 ;
     RECT  25.992 3.649 29.97 4.261 ;
     RECT  54.252 4.117 69.138 4.261 ;
     RECT  70.056 4.189 73.602 4.261 ;
     RECT  54.252 4.261 73.602 4.289 ;
     RECT  2.415 4.261 12.078 4.351 ;
     RECT  58.968 4.289 73.602 4.423 ;
     RECT  74.448 4.253 77.238 4.423 ;
     RECT  25.2 4.261 29.97 4.445 ;
     RECT  54.252 4.289 58.158 4.495 ;
     RECT  58.968 4.423 77.238 4.523 ;
     RECT  2.415 4.351 12.15 4.531 ;
     RECT  12.996 3.983 13.518 4.531 ;
     RECT  24.015 3.713 24.297 4.555 ;
     RECT  25.2 4.445 25.218 4.555 ;
     RECT  24.015 4.555 25.218 4.589 ;
     RECT  14.94 4.261 23.202 4.621 ;
     RECT  24.015 4.589 24.75 4.621 ;
     RECT  30.888 3.749 53.226 4.621 ;
     RECT  14.94 4.621 24.75 4.657 ;
     RECT  30.78 4.621 53.226 4.685 ;
     RECT  32.436 4.685 53.226 4.693 ;
     RECT  54.072 4.495 58.158 4.693 ;
     RECT  25.992 4.445 29.97 4.765 ;
     RECT  30.78 4.685 31.59 4.765 ;
     RECT  14.724 4.657 24.75 4.919 ;
     RECT  32.436 4.693 58.158 4.919 ;
     RECT  32.436 4.919 57.654 4.955 ;
     RECT  14.724 4.919 24.57 5.035 ;
     RECT  2.415 4.531 13.518 5.069 ;
     RECT  14.652 5.035 24.57 5.071 ;
     RECT  25.992 4.765 31.59 5.099 ;
     RECT  32.436 4.955 52.902 5.099 ;
     RECT  59.436 4.523 77.238 5.117 ;
     RECT  25.992 5.099 31.374 5.269 ;
     RECT  25.884 5.269 31.374 5.341 ;
     RECT  58.536 5.131 58.698 5.341 ;
     RECT  59.436 5.117 77.166 5.341 ;
     RECT  32.436 5.099 43.218 5.467 ;
     RECT  58.536 5.341 77.166 5.531 ;
     RECT  32.148 5.467 43.218 5.603 ;
     RECT  59.364 5.531 77.166 5.639 ;
     RECT  53.64 4.955 57.654 5.701 ;
     RECT  58.536 5.531 58.554 5.701 ;
     RECT  14.436 5.071 24.57 5.765 ;
     RECT  32.148 5.603 37.998 5.765 ;
     RECT  78.015 4.253 78.75 5.845 ;
     RECT  25.668 5.341 31.374 5.885 ;
     RECT  44.028 5.099 52.902 5.909 ;
     RECT  44.028 5.909 44.118 5.971 ;
     RECT  2.415 5.069 13.497 5.995 ;
     RECT  38.736 5.603 43.218 6.007 ;
     RECT  43.992 5.971 44.118 6.007 ;
     RECT  14.832 5.765 24.57 6.079 ;
     RECT  44.892 5.909 52.902 6.079 ;
     RECT  53.64 5.701 58.554 6.079 ;
     RECT  68.94 5.639 77.166 6.151 ;
     RECT  78.015 5.845 78.966 6.151 ;
     RECT  14.832 6.079 24.822 6.269 ;
     RECT  38.736 6.007 44.118 6.269 ;
     RECT  32.436 5.765 37.998 6.349 ;
     RECT  38.736 6.269 39.186 6.349 ;
     RECT  31.32 5.885 31.374 6.385 ;
     RECT  59.364 5.639 68.202 6.421 ;
     RECT  68.94 6.151 78.966 6.421 ;
     RECT  14.832 6.269 24.678 6.547 ;
     RECT  31.32 6.385 31.41 6.574 ;
     RECT  59.364 6.421 78.966 6.611 ;
     RECT  25.668 5.885 30.51 6.613 ;
     RECT  25.668 6.613 30.546 6.619 ;
     RECT  31.32 6.574 31.446 6.619 ;
     RECT  25.668 6.619 31.446 6.655 ;
     RECT  39.924 6.269 44.118 6.691 ;
     RECT  44.892 6.079 58.554 6.691 ;
     RECT  14.796 6.547 24.678 6.719 ;
     RECT  39.924 6.691 58.554 6.781 ;
     RECT  59.364 6.611 68.094 6.781 ;
     RECT  2.415 5.995 13.914 6.809 ;
     RECT  14.796 6.719 24.297 6.845 ;
     RECT  25.524 6.655 31.446 7.123 ;
     RECT  32.436 6.349 39.186 7.123 ;
     RECT  25.524 7.123 39.186 7.231 ;
     RECT  39.924 6.781 68.094 7.231 ;
     RECT  25.524 7.231 68.094 7.321 ;
     RECT  2.415 6.809 13.77 7.349 ;
     RECT  25.2 7.321 68.094 7.349 ;
     RECT  69.048 6.611 78.966 7.357 ;
     RECT  31.932 7.349 68.094 7.373 ;
     RECT  25.2 7.349 31.194 7.385 ;
     RECT  25.2 7.385 31.014 7.421 ;
     RECT  16.956 6.845 24.297 7.501 ;
     RECT  25.2 7.421 29.898 7.501 ;
     RECT  14.796 6.845 16.182 7.591 ;
     RECT  16.956 7.501 29.898 7.591 ;
     RECT  31.932 7.373 67.698 7.619 ;
     RECT  14.796 7.591 29.898 7.627 ;
     RECT  30.672 7.421 31.014 8.155 ;
     RECT  30.636 8.155 31.014 8.239 ;
     RECT  58.644 7.619 67.698 8.239 ;
     RECT  31.932 7.619 57.798 8.275 ;
     RECT  3.42 7.349 13.626 8.311 ;
     RECT  14.4 7.627 29.898 8.311 ;
     RECT  30.636 8.239 31.086 8.311 ;
     RECT  58.644 8.239 68.166 8.311 ;
     RECT  58.644 8.311 68.238 8.401 ;
     RECT  68.976 7.357 78.966 8.401 ;
     RECT  3.42 8.311 31.086 8.429 ;
     RECT  31.86 8.275 57.798 8.539 ;
     RECT  58.644 8.401 78.966 8.539 ;
     RECT  30.672 8.429 31.086 8.581 ;
     RECT  31.86 8.539 78.966 8.581 ;
     RECT  3.42 8.429 29.862 8.807 ;
     RECT  16.164 8.807 29.862 9.211 ;
     RECT  30.672 8.581 78.966 9.211 ;
     RECT  2.415 7.349 2.697 9.247 ;
     RECT  3.42 8.807 15.426 9.247 ;
     RECT  2.415 9.247 15.426 9.419 ;
     RECT  3.42 9.419 15.426 9.779 ;
     RECT  14.796 9.779 15.426 9.823 ;
     RECT  16.164 9.211 78.966 9.823 ;
     RECT  2.415 9.419 2.697 10.201 ;
     RECT  3.42 9.779 13.95 10.201 ;
     RECT  14.796 9.823 78.966 10.463 ;
     RECT  31.572 10.463 78.966 10.471 ;
     RECT  14.796 10.463 30.798 10.661 ;
     RECT  14.832 10.661 30.798 10.769 ;
     RECT  2.415 10.201 13.95 11.479 ;
     RECT  14.832 10.769 29.862 11.479 ;
     RECT  2.415 11.479 29.862 11.551 ;
     RECT  30.78 10.769 30.798 11.551 ;
     RECT  31.572 10.471 79.578 11.551 ;
     RECT  2.415 11.551 79.578 11.705 ;
     RECT  15.228 11.705 79.578 11.947 ;
     RECT  15.228 11.947 79.758 12.011 ;
     RECT  15.264 12.011 79.758 12.029 ;
     RECT  15.264 12.029 78.75 12.281 ;
     RECT  15.264 12.281 15.282 12.317 ;
     RECT  16.128 12.281 78.75 12.317 ;
     RECT  16.128 12.317 57.33 12.479 ;
     RECT  2.415 11.705 13.95 12.631 ;
     RECT  2.415 12.631 14.49 12.763 ;
     RECT  16.92 12.479 57.33 12.785 ;
     RECT  58.104 12.317 78.75 12.857 ;
     RECT  58.14 12.857 78.75 12.893 ;
     RECT  59.04 12.893 78.75 12.901 ;
     RECT  79.56 12.029 79.758 13.027 ;
     RECT  16.92 12.785 30.222 13.055 ;
     RECT  2.415 12.763 15.03 13.099 ;
     RECT  79.56 13.027 79.794 13.102 ;
     RECT  59.04 12.901 78.822 13.171 ;
     RECT  79.56 13.102 79.758 13.171 ;
     RECT  16.128 12.479 16.146 13.289 ;
     RECT  16.92 13.055 29.898 13.289 ;
     RECT  16.92 13.289 29.79 13.441 ;
     RECT  30.96 12.785 57.33 13.531 ;
     RECT  2.415 13.099 15.174 13.603 ;
     RECT  2.34 13.603 15.174 13.661 ;
     RECT  58.14 12.893 58.302 13.675 ;
     RECT  59.04 13.171 79.758 13.675 ;
     RECT  58.14 13.675 79.758 13.711 ;
     RECT  2.415 13.661 15.174 13.829 ;
     RECT  58.104 13.711 79.758 13.829 ;
     RECT  16.632 13.441 29.79 14.099 ;
     RECT  30.672 13.531 57.33 14.099 ;
     RECT  59.436 13.829 79.758 14.099 ;
     RECT  16.704 14.099 29.79 14.143 ;
     RECT  30.672 14.099 57.15 14.143 ;
     RECT  59.508 14.099 79.758 14.171 ;
     RECT  16.704 14.143 57.15 14.237 ;
     RECT  2.415 13.829 14.85 14.369 ;
     RECT  58.104 13.829 58.446 14.449 ;
     RECT  16.704 14.237 56.97 14.513 ;
     RECT  16.704 14.513 19.098 14.639 ;
     RECT  15.732 13.981 15.858 14.647 ;
     RECT  68.796 14.171 79.758 14.675 ;
     RECT  57.888 14.449 58.446 14.711 ;
     RECT  2.415 14.369 14.742 14.791 ;
     RECT  57.888 14.711 57.906 14.819 ;
     RECT  2.376 14.791 14.742 14.881 ;
     RECT  59.508 14.171 68.022 14.881 ;
     RECT  19.872 14.513 56.97 14.909 ;
     RECT  59.472 14.881 68.022 15.025 ;
     RECT  33.552 14.909 56.97 15.295 ;
     RECT  15.732 14.647 15.93 15.323 ;
     RECT  2.304 14.881 14.742 15.331 ;
     RECT  16.848 14.639 19.098 15.355 ;
     RECT  19.872 14.909 32.814 15.355 ;
     RECT  58.68 15.025 68.022 15.359 ;
     RECT  16.848 15.355 32.814 15.389 ;
     RECT  16.848 15.389 31.698 15.529 ;
     RECT  33.552 15.295 57.834 15.601 ;
     RECT  58.68 15.359 65.502 15.601 ;
     RECT  66.348 15.359 68.022 15.601 ;
     RECT  68.868 14.675 79.758 15.601 ;
     RECT  32.508 15.389 32.814 15.691 ;
     RECT  33.552 15.601 65.502 15.691 ;
     RECT  2.304 15.331 15.462 15.989 ;
     RECT  16.308 15.529 31.698 16.123 ;
     RECT  32.508 15.691 65.502 16.123 ;
     RECT  2.34 15.989 15.462 16.141 ;
     RECT  16.308 16.123 65.502 16.141 ;
     RECT  0.144 15.295 0.162 16.645 ;
     RECT  2.34 16.141 65.502 16.871 ;
     RECT  2.34 16.871 20.07 16.979 ;
     RECT  20.808 16.871 65.502 17.041 ;
     RECT  20.808 17.041 65.538 17.069 ;
     RECT  20.988 17.069 65.538 17.185 ;
     RECT  66.348 15.601 79.758 17.185 ;
     RECT  20.988 17.185 79.758 17.339 ;
     RECT  0.108 16.645 0.162 17.383 ;
     RECT  0.108 17.383 0.234 17.419 ;
     RECT  2.34 16.979 15.462 17.608 ;
     RECT  16.236 16.979 20.07 17.611 ;
     RECT  20.988 17.339 71.298 17.915 ;
     RECT  2.304 17.608 15.462 17.923 ;
     RECT  16.236 17.611 20.25 17.923 ;
     RECT  53.244 17.915 71.298 18.139 ;
     RECT  72.072 17.339 79.758 18.139 ;
     RECT  2.304 17.923 20.25 18.157 ;
     RECT  20.988 17.915 52.506 18.157 ;
     RECT  0.108 17.419 0.558 18.221 ;
     RECT  0.108 18.221 0.234 18.413 ;
     RECT  0.108 18.413 0.198 18.605 ;
     RECT  2.304 18.157 52.506 18.661 ;
     RECT  53.244 18.139 79.758 18.661 ;
     RECT  2.304 18.661 79.758 19.339 ;
     RECT  0.108 18.605 0.162 19.757 ;
     RECT  1.728 19.339 79.758 19.877 ;
     RECT  0.144 19.757 0.162 19.885 ;
     RECT  0.144 19.885 0.198 19.915 ;
     RECT  1.728 19.877 79.434 20.093 ;
     RECT  17.424 20.093 79.434 20.111 ;
     RECT  0.144 19.915 0.594 20.429 ;
     RECT  1.728 20.093 16.686 20.615 ;
     RECT  0.18 20.429 0.594 20.621 ;
     RECT  1.764 20.615 16.686 20.687 ;
     RECT  1.8 20.687 16.686 20.821 ;
     RECT  17.424 20.111 20.25 20.821 ;
     RECT  20.988 20.111 79.434 20.849 ;
     RECT  1.8 20.821 20.25 21.091 ;
     RECT  20.988 20.849 68.238 21.091 ;
     RECT  1.8 21.091 68.238 21.155 ;
     RECT  1.8 21.155 11.97 21.227 ;
     RECT  12.708 21.155 68.238 21.227 ;
     RECT  68.976 20.849 79.434 21.235 ;
     RECT  0.576 20.621 0.594 21.695 ;
     RECT  1.836 21.227 11.97 21.767 ;
     RECT  12.924 21.227 68.238 21.811 ;
     RECT  68.976 21.235 79.794 21.811 ;
     RECT  2.304 21.767 11.97 21.901 ;
     RECT  2.304 21.901 12.186 21.929 ;
     RECT  12.924 21.811 79.794 21.929 ;
     RECT  2.376 21.929 12.186 22.171 ;
     RECT  12.924 21.929 79.758 22.171 ;
     RECT  2.376 22.171 79.758 22.235 ;
     RECT  2.412 22.235 79.758 22.505 ;
     RECT  76.716 22.505 79.758 23.089 ;
     RECT  2.412 22.505 75.942 23.125 ;
     RECT  2.376 23.125 75.942 23.161 ;
     RECT  76.716 23.089 79.794 23.279 ;
     RECT  2.34 23.161 75.942 23.323 ;
     RECT  76.716 23.279 79.758 23.323 ;
     RECT  2.304 23.323 79.758 23.423 ;
     RECT  2.415 23.423 79.758 23.657 ;
     RECT  0.576 23.323 0.594 23.665 ;
     RECT  2.415 23.657 36.558 23.819 ;
     RECT  2.415 23.819 26.55 24.269 ;
     RECT  2.415 24.269 20.934 24.359 ;
     RECT  21.708 24.269 26.55 24.359 ;
     RECT  27.432 23.819 36.558 24.403 ;
     RECT  37.332 23.657 79.758 24.403 ;
     RECT  82.044 22.207 82.062 24.439 ;
     RECT  0.144 23.665 0.594 24.475 ;
     RECT  27.432 24.403 79.758 24.503 ;
     RECT  21.816 24.359 26.55 24.601 ;
     RECT  27.432 24.503 79.65 24.601 ;
     RECT  21.816 24.601 26.622 24.619 ;
     RECT  27.36 24.601 79.65 24.619 ;
     RECT  2.415 24.359 20.898 25.003 ;
     RECT  2.304 25.003 20.898 25.141 ;
     RECT  21.816 24.619 79.65 25.141 ;
     RECT  81.936 24.439 82.062 25.325 ;
     RECT  81.936 25.325 81.99 25.421 ;
     RECT  2.304 25.141 79.65 25.475 ;
     RECT  80.964 24.331 80.982 25.483 ;
     RECT  0.108 24.475 0.594 25.517 ;
     RECT  0.108 25.517 0.558 25.613 ;
     RECT  80.928 25.483 80.982 25.681 ;
     RECT  0.144 25.613 0.558 25.709 ;
     RECT  80.388 25.681 80.982 25.861 ;
     RECT  0.324 25.709 0.558 25.901 ;
     RECT  80.352 25.861 80.982 25.901 ;
     RECT  80.388 25.901 80.982 25.987 ;
     RECT  81.936 25.421 81.954 25.987 ;
     RECT  80.388 25.987 81.954 25.997 ;
     RECT  0.324 25.901 0.342 26.093 ;
     RECT  80.928 25.997 81.954 26.477 ;
     RECT  2.304 25.475 79.614 26.539 ;
     RECT  2.196 26.539 79.614 26.699 ;
     RECT  80.928 26.477 80.946 26.731 ;
     RECT  81.864 26.477 81.954 26.827 ;
     RECT  54.504 26.699 79.614 26.933 ;
     RECT  2.196 26.699 53.766 27.019 ;
     RECT  1.728 27.019 53.766 27.473 ;
     RECT  34.632 27.473 53.766 27.481 ;
     RECT  54.504 26.933 73.422 27.481 ;
     RECT  34.632 27.481 73.422 27.635 ;
     RECT  80.892 26.731 80.946 27.671 ;
     RECT  0.108 27.499 0.126 27.725 ;
     RECT  74.16 26.933 79.614 27.869 ;
     RECT  38.34 27.635 73.422 28.183 ;
     RECT  74.16 27.869 79.542 28.183 ;
     RECT  81.864 26.827 81.99 28.247 ;
     RECT  1.728 27.473 33.858 28.291 ;
     RECT  34.632 27.635 37.566 28.291 ;
     RECT  80.928 27.671 80.946 28.409 ;
     RECT  1.728 28.291 37.566 28.489 ;
     RECT  38.34 28.183 79.542 28.489 ;
     RECT  1.728 28.489 79.542 28.715 ;
     RECT  53.892 28.715 79.542 28.921 ;
     RECT  1.728 28.715 53.118 28.949 ;
     RECT  22.14 28.949 53.118 29.021 ;
     RECT  1.728 28.949 21.33 29.057 ;
     RECT  34.596 29.021 53.118 29.219 ;
     RECT  38.88 29.219 53.118 29.641 ;
     RECT  53.892 28.921 79.614 29.641 ;
     RECT  81.9 28.247 81.99 29.759 ;
     RECT  38.88 29.641 79.614 29.795 ;
     RECT  38.88 29.795 79.542 29.867 ;
     RECT  0.036 29.335 0.054 29.875 ;
     RECT  2.34 29.057 21.33 29.875 ;
     RECT  22.14 29.021 33.822 29.875 ;
     RECT  2.34 29.875 33.822 29.911 ;
     RECT  34.596 29.219 37.962 29.911 ;
     RECT  38.88 29.867 67.497 30.037 ;
     RECT  2.34 29.911 37.962 30.187 ;
     RECT  38.808 30.037 67.497 30.187 ;
     RECT  2.34 30.187 67.497 30.299 ;
     RECT  81.972 29.759 81.99 30.299 ;
     RECT  68.22 29.867 79.542 30.335 ;
     RECT  21.924 30.299 67.497 30.569 ;
     RECT  68.22 30.335 79.434 30.569 ;
     RECT  0.036 29.875 0.198 30.613 ;
     RECT  2.34 30.299 21.114 30.859 ;
     RECT  45.615 30.569 67.497 30.991 ;
     RECT  68.328 30.569 79.434 31.261 ;
     RECT  0.036 30.613 0.306 31.339 ;
     RECT  45.615 30.991 67.59 31.351 ;
     RECT  68.328 31.261 79.47 31.351 ;
     RECT  21.924 30.569 44.694 31.379 ;
     RECT  0.036 31.339 0.378 31.469 ;
     RECT  41.616 31.379 44.694 31.531 ;
     RECT  45.615 31.351 79.47 31.531 ;
     RECT  21.924 31.379 40.77 31.709 ;
     RECT  2.304 30.859 21.114 31.765 ;
     RECT  21.924 31.709 35.097 31.765 ;
     RECT  0.036 31.469 0.306 31.919 ;
     RECT  2.304 31.765 35.097 32.189 ;
     RECT  41.616 31.531 79.47 32.189 ;
     RECT  68.4 32.189 79.47 32.225 ;
     RECT  0.108 31.919 0.306 32.341 ;
     RECT  36 31.709 40.77 32.341 ;
     RECT  41.616 32.189 67.59 32.341 ;
     RECT  34.164 32.189 35.097 32.467 ;
     RECT  36 32.341 67.59 32.467 ;
     RECT  34.164 32.467 67.59 32.531 ;
     RECT  34.164 32.531 67.554 32.729 ;
     RECT  42.552 32.729 67.554 32.765 ;
     RECT  42.624 32.765 67.554 32.837 ;
     RECT  68.4 32.225 79.326 32.971 ;
     RECT  2.304 32.189 33.318 33.067 ;
     RECT  34.164 32.729 41.778 33.067 ;
     RECT  2.304 33.067 41.778 33.163 ;
     RECT  2.268 33.163 41.778 33.269 ;
     RECT  0.108 32.341 0.558 33.389 ;
     RECT  68.364 32.971 79.326 33.421 ;
     RECT  2.268 33.269 41.634 33.575 ;
     RECT  42.768 32.837 67.554 33.611 ;
     RECT  68.364 33.421 79.362 33.629 ;
     RECT  42.912 33.611 67.554 33.889 ;
     RECT  68.364 33.629 69.246 33.889 ;
     RECT  0.54 33.389 0.558 34.061 ;
     RECT  70.308 33.629 79.362 34.115 ;
     RECT  34.236 33.575 41.634 34.123 ;
     RECT  34.236 34.123 41.67 34.321 ;
     RECT  2.268 33.575 33.462 34.349 ;
     RECT  42.912 33.889 69.246 34.465 ;
     RECT  34.236 34.321 42.03 34.501 ;
     RECT  42.912 34.465 69.318 34.501 ;
     RECT  70.344 34.115 79.362 34.501 ;
     RECT  2.268 34.349 22.086 34.619 ;
     RECT  22.86 34.349 33.462 34.619 ;
     RECT  34.236 34.501 69.498 34.619 ;
     RECT  42.012 34.619 69.498 34.655 ;
     RECT  70.344 34.501 79.434 34.691 ;
     RECT  0.144 34.507 0.234 34.735 ;
     RECT  0.108 34.735 0.234 34.891 ;
     RECT  2.268 34.619 21.942 34.925 ;
     RECT  23.004 34.619 33.462 34.969 ;
     RECT  34.236 34.619 41.166 34.969 ;
     RECT  42.156 34.655 69.498 35.041 ;
     RECT  23.004 34.969 41.166 35.401 ;
     RECT  42.156 35.041 69.606 35.401 ;
     RECT  2.268 34.925 21.798 35.419 ;
     RECT  70.56 34.691 79.434 35.545 ;
     RECT  2.232 35.419 21.798 35.573 ;
     RECT  2.232 35.573 21.654 35.597 ;
     RECT  23.004 35.401 69.606 35.671 ;
     RECT  23.004 35.671 69.678 35.815 ;
     RECT  70.488 35.545 79.434 35.815 ;
     RECT  2.268 35.597 21.654 36.005 ;
     RECT  0.108 34.891 0.558 36.043 ;
     RECT  23.004 35.815 79.47 36.121 ;
     RECT  22.86 36.121 79.47 36.517 ;
     RECT  22.824 36.517 79.47 36.581 ;
     RECT  2.268 36.005 21.618 36.619 ;
     RECT  22.824 36.581 42.354 36.661 ;
     RECT  22.536 36.661 42.354 36.895 ;
     RECT  1.728 36.619 21.618 36.931 ;
     RECT  22.428 36.895 42.354 36.931 ;
     RECT  43.128 36.581 79.47 37.463 ;
     RECT  1.728 36.931 42.354 37.471 ;
     RECT  43.128 37.463 79.434 37.471 ;
     RECT  1.728 37.471 79.434 37.733 ;
     RECT  1.728 37.733 35.982 37.859 ;
     RECT  1.728 37.859 30.33 38.045 ;
     RECT  31.068 37.859 35.982 38.551 ;
     RECT  31.068 38.551 36.126 38.785 ;
     RECT  36.936 37.733 79.434 38.785 ;
     RECT  31.068 38.785 79.434 38.813 ;
     RECT  31.068 38.813 74.646 38.939 ;
     RECT  75.564 38.813 79.434 39.119 ;
     RECT  1.728 38.045 30.258 39.245 ;
     RECT  2.304 39.245 30.258 39.289 ;
     RECT  31.068 38.939 42.426 39.289 ;
     RECT  2.304 39.289 42.426 39.293 ;
     RECT  2.304 39.293 29.697 39.317 ;
     RECT  43.308 38.939 74.646 39.479 ;
     RECT  0.108 36.043 0.63 39.515 ;
     RECT  43.308 39.479 69.102 39.749 ;
     RECT  0.108 39.515 0.126 39.785 ;
     RECT  43.308 39.749 68.958 39.785 ;
     RECT  2.415 39.317 29.697 39.821 ;
     RECT  30.6 39.293 42.426 39.821 ;
     RECT  43.308 39.785 68.922 39.829 ;
     RECT  2.415 39.821 14.85 39.857 ;
     RECT  69.948 39.479 74.646 39.883 ;
     RECT  2.415 39.857 14.634 39.893 ;
     RECT  15.624 39.821 29.697 39.893 ;
     RECT  30.6 39.821 42.21 40.021 ;
     RECT  30.42 40.021 42.21 40.061 ;
     RECT  69.948 39.883 74.79 40.441 ;
     RECT  30.636 40.061 42.21 40.469 ;
     RECT  42.948 39.829 68.922 40.555 ;
     RECT  69.732 40.441 74.79 40.555 ;
     RECT  31.32 40.469 42.21 40.567 ;
     RECT  42.948 40.555 74.79 40.567 ;
     RECT  31.32 40.567 74.79 40.603 ;
     RECT  2.415 39.893 14.562 40.639 ;
     RECT  15.84 39.893 29.697 40.639 ;
     RECT  75.564 39.119 79.398 40.711 ;
     RECT  75.564 40.711 79.794 40.829 ;
     RECT  2.415 40.639 29.697 40.973 ;
     RECT  31.32 40.603 74.826 40.973 ;
     RECT  20.196 40.973 29.697 41.071 ;
     RECT  2.415 40.973 19.35 41.135 ;
     RECT  20.196 41.071 30.294 41.171 ;
     RECT  2.415 41.135 15.462 41.215 ;
     RECT  25.92 41.171 30.294 41.251 ;
     RECT  75.564 40.829 79.398 41.251 ;
     RECT  31.32 40.973 35.586 41.377 ;
     RECT  36.324 40.973 74.718 41.405 ;
     RECT  25.92 41.251 30.546 41.449 ;
     RECT  31.284 41.377 35.586 41.449 ;
     RECT  0.036 40.405 0.054 41.485 ;
     RECT  0.036 41.485 0.594 41.755 ;
     RECT  16.272 41.135 19.35 41.791 ;
     RECT  20.196 41.171 25.11 41.791 ;
     RECT  25.92 41.449 35.586 41.791 ;
     RECT  36.324 41.405 67.914 41.791 ;
     RECT  68.868 41.405 74.718 41.791 ;
     RECT  75.456 41.251 79.398 41.791 ;
     RECT  16.272 41.791 25.11 41.917 ;
     RECT  25.92 41.791 67.914 41.917 ;
     RECT  2.268 41.215 15.462 42.025 ;
     RECT  16.272 41.917 67.914 42.025 ;
     RECT  68.868 41.791 79.578 42.053 ;
     RECT  68.868 42.053 79.398 42.089 ;
     RECT  71.784 42.089 79.398 42.179 ;
     RECT  2.268 42.025 67.914 42.215 ;
     RECT  68.868 42.089 70.974 42.272 ;
     RECT  68.76 42.272 70.974 42.715 ;
     RECT  0.036 41.755 0.882 42.727 ;
     RECT  2.268 42.215 27.378 42.755 ;
     RECT  28.188 42.215 67.914 42.755 ;
     RECT  72.18 42.179 79.398 42.755 ;
     RECT  0.036 42.727 1.422 42.791 ;
     RECT  72.18 42.755 79.182 42.827 ;
     RECT  38.412 42.755 67.914 42.835 ;
     RECT  68.724 42.715 70.974 42.835 ;
     RECT  38.412 42.835 70.974 42.899 ;
     RECT  25.992 42.755 27.378 42.961 ;
     RECT  28.188 42.755 37.674 42.961 ;
     RECT  38.448 42.899 70.974 42.997 ;
     RECT  25.992 42.961 37.674 43.025 ;
     RECT  31.932 43.025 37.674 43.295 ;
     RECT  31.932 43.295 33.03 43.325 ;
     RECT  2.268 42.755 25.254 43.601 ;
     RECT  20.016 43.601 25.254 43.609 ;
     RECT  25.992 43.025 30.87 43.609 ;
     RECT  38.448 42.997 71.334 43.681 ;
     RECT  72.324 42.827 79.182 43.681 ;
     RECT  31.932 43.325 32.886 43.771 ;
     RECT  34.02 43.295 37.674 43.843 ;
     RECT  38.448 43.681 79.182 43.843 ;
     RECT  2.268 43.601 19.278 43.871 ;
     RECT  34.02 43.843 79.182 43.871 ;
     RECT  20.016 43.609 30.87 43.915 ;
     RECT  31.68 43.771 32.886 43.915 ;
     RECT  45.036 43.871 79.182 43.979 ;
     RECT  34.02 43.871 44.226 44.059 ;
     RECT  0.108 42.791 1.422 44.141 ;
     RECT  20.016 43.915 32.886 44.185 ;
     RECT  33.912 44.059 44.226 44.185 ;
     RECT  45.036 43.979 79.002 44.249 ;
     RECT  2.304 43.871 19.278 44.347 ;
     RECT  20.016 44.185 44.226 44.347 ;
     RECT  1.404 44.141 1.422 44.447 ;
     RECT  2.304 44.347 44.226 44.519 ;
     RECT  34.2 44.519 44.226 44.617 ;
     RECT  45.036 44.249 78.822 44.617 ;
     RECT  34.2 44.617 78.822 44.681 ;
     RECT  2.304 44.519 33.318 44.887 ;
     RECT  0.108 44.141 0.234 44.959 ;
     RECT  34.524 44.681 78.822 45.019 ;
     RECT  0.108 44.959 0.558 45.197 ;
     RECT  34.524 45.019 79.002 45.221 ;
     RECT  2.268 44.887 33.318 45.265 ;
     RECT  2.268 45.265 33.462 45.301 ;
     RECT  2.268 45.301 33.642 45.535 ;
     RECT  34.524 45.221 37.242 45.535 ;
     RECT  0.108 45.197 0.198 45.869 ;
     RECT  38.052 45.221 79.002 45.967 ;
     RECT  2.268 45.535 37.242 46.111 ;
     RECT  2.268 46.111 37.278 46.139 ;
     RECT  2.268 46.139 30.798 46.253 ;
     RECT  0.108 45.869 0.126 46.445 ;
     RECT  31.536 46.139 37.278 46.699 ;
     RECT  38.052 45.967 79.146 46.699 ;
     RECT  2.304 46.253 30.798 46.885 ;
     RECT  31.536 46.699 79.146 46.885 ;
     RECT  2.304 46.885 79.146 46.921 ;
     RECT  2.304 46.921 79.47 47.075 ;
     RECT  2.376 47.075 79.47 47.345 ;
     RECT  43.524 47.345 79.47 47.461 ;
     RECT  2.376 47.345 37.638 47.489 ;
     RECT  38.412 47.345 42.714 47.579 ;
     RECT  2.376 47.489 23.202 47.615 ;
     RECT  38.556 47.579 42.714 47.615 ;
     RECT  43.524 47.461 79.506 47.623 ;
     RECT  0.18 47.623 0.198 47.695 ;
     RECT  0.144 47.695 0.198 47.731 ;
     RECT  2.376 47.615 23.058 47.821 ;
     RECT  43.524 47.623 79.722 47.848 ;
     RECT  24.015 47.489 37.638 47.849 ;
     RECT  38.556 47.615 38.574 47.849 ;
     RECT  0.144 47.731 0.558 47.857 ;
     RECT  24.015 47.849 37.602 47.885 ;
     RECT  43.524 47.848 79.794 47.885 ;
     RECT  0.108 47.857 0.558 48.077 ;
     RECT  24.015 47.885 37.422 48.271 ;
     RECT  39.348 47.615 42.714 48.271 ;
     RECT  43.524 47.885 79.722 48.271 ;
     RECT  2.304 47.821 23.058 48.425 ;
     RECT  18 48.425 23.058 48.505 ;
     RECT  23.976 48.271 37.422 48.505 ;
     RECT  39.348 48.271 79.722 48.541 ;
     RECT  0.144 48.077 0.558 48.653 ;
     RECT  2.304 48.425 17.19 48.695 ;
     RECT  18 48.505 37.422 48.695 ;
     RECT  7.668 48.695 17.19 48.731 ;
     RECT  38.376 48.505 38.394 48.739 ;
     RECT  0.144 48.653 0.234 48.749 ;
     RECT  18.072 48.695 37.422 48.811 ;
     RECT  38.304 48.739 38.394 48.811 ;
     RECT  7.668 48.731 17.118 48.839 ;
     RECT  39.312 48.541 79.722 48.845 ;
     RECT  0.144 48.749 0.198 48.937 ;
     RECT  18.072 48.811 37.458 49.045 ;
     RECT  38.196 48.811 38.394 49.045 ;
     RECT  18.072 49.045 38.394 49.081 ;
     RECT  39.312 48.845 53.982 49.081 ;
     RECT  54.828 48.845 79.722 49.081 ;
     RECT  2.304 48.695 6.93 49.099 ;
     RECT  18.072 49.081 53.982 49.199 ;
     RECT  0.108 48.937 0.198 49.421 ;
     RECT  18.072 49.199 35.622 49.469 ;
     RECT  18.18 49.469 35.622 49.577 ;
     RECT  36.36 49.199 53.982 49.579 ;
     RECT  54.828 49.081 79.758 49.579 ;
     RECT  23.328 49.577 35.622 49.613 ;
     RECT  2.268 49.099 6.93 49.621 ;
     RECT  7.704 48.839 17.118 49.621 ;
     RECT  2.268 49.621 17.118 49.747 ;
     RECT  2.268 49.747 17.19 49.891 ;
     RECT  82.044 49.441 82.062 49.891 ;
     RECT  36.36 49.579 79.758 50.141 ;
     RECT  23.364 49.613 35.622 50.161 ;
     RECT  36.36 50.141 46.962 50.161 ;
     RECT  0.108 49.421 0.126 50.251 ;
     RECT  23.364 50.161 46.962 50.279 ;
     RECT  23.364 50.279 46.818 50.429 ;
     RECT  81.504 49.891 82.062 50.431 ;
     RECT  23.364 50.429 46.566 50.459 ;
     RECT  2.268 49.891 17.442 50.539 ;
     RECT  23.364 50.459 46.53 50.549 ;
     RECT  38.844 50.549 46.53 50.621 ;
     RECT  1.728 50.539 17.442 50.629 ;
     RECT  18.18 49.577 22.59 50.629 ;
     RECT  1.728 50.629 22.59 50.683 ;
     RECT  23.364 50.549 38.106 50.683 ;
     RECT  1.728 50.683 38.106 51.149 ;
     RECT  48.024 50.141 79.758 51.211 ;
     RECT  38.916 50.621 46.53 51.241 ;
     RECT  47.304 51.211 79.758 51.241 ;
     RECT  0.108 50.251 0.846 51.286 ;
     RECT  38.916 51.241 79.758 51.395 ;
     RECT  24.015 51.149 38.106 51.431 ;
     RECT  38.916 51.395 42.966 51.439 ;
     RECT  80.964 50.431 82.062 51.511 ;
     RECT  43.704 51.395 79.758 51.673 ;
     RECT  80.928 51.511 82.062 51.673 ;
     RECT  43.704 51.673 82.062 51.773 ;
     RECT  25.848 51.431 38.106 51.781 ;
     RECT  38.88 51.439 42.966 51.781 ;
     RECT  47.52 51.773 82.062 51.821 ;
     RECT  0.108 51.286 0.882 51.871 ;
     RECT  1.728 51.149 23.058 51.871 ;
     RECT  47.52 51.821 79.758 51.971 ;
     RECT  80.928 51.821 82.062 52.079 ;
     RECT  80.928 52.079 81.99 52.109 ;
     RECT  43.704 51.773 46.638 52.205 ;
     RECT  24.015 51.431 24.822 52.213 ;
     RECT  25.848 51.781 42.966 52.241 ;
     RECT  47.52 51.971 79.65 52.277 ;
     RECT  47.52 52.277 79.578 52.493 ;
     RECT  80.928 52.109 81.486 52.555 ;
     RECT  80.388 52.555 81.486 52.592 ;
     RECT  0.108 51.871 23.058 52.709 ;
     RECT  24.015 52.213 24.894 52.789 ;
     RECT  25.848 52.241 35.622 52.789 ;
     RECT  43.776 52.205 46.638 52.825 ;
     RECT  47.52 52.493 79.506 52.825 ;
     RECT  80.892 52.592 81.486 52.843 ;
     RECT  36.396 52.241 42.966 52.979 ;
     RECT  24.015 52.789 35.622 52.987 ;
     RECT  36.432 52.979 42.966 53.051 ;
     RECT  43.776 52.825 79.506 53.563 ;
     RECT  80.892 52.843 81.99 53.788 ;
     RECT  23.76 52.987 35.622 53.869 ;
     RECT  36.432 53.051 42.822 53.869 ;
     RECT  23.76 53.869 42.822 53.905 ;
     RECT  43.776 53.563 79.578 53.905 ;
     RECT  0.108 52.709 22.878 53.941 ;
     RECT  23.76 53.905 79.614 53.941 ;
     RECT  0.108 53.941 79.722 54.095 ;
     RECT  80.856 53.788 81.99 54.329 ;
     RECT  1.908 54.095 79.722 54.379 ;
     RECT  1.908 54.379 80.082 54.509 ;
     RECT  1.908 54.509 21.834 54.635 ;
     RECT  0.108 54.095 1.17 54.679 ;
     RECT  22.572 54.509 80.082 54.701 ;
     RECT  0.036 54.679 1.17 54.707 ;
     RECT  23.652 54.701 80.082 54.707 ;
     RECT  0.828 54.707 1.17 54.905 ;
     RECT  23.868 54.707 80.082 54.905 ;
     RECT  0.828 54.905 0.882 55.013 ;
     RECT  22.572 54.701 22.878 55.139 ;
     RECT  2.304 54.635 21.834 55.175 ;
     RECT  23.868 54.905 42.498 55.211 ;
     RECT  81.468 54.329 81.99 55.481 ;
     RECT  81.828 55.481 81.99 55.589 ;
     RECT  2.415 55.175 21.834 55.651 ;
     RECT  22.572 55.139 22.806 55.651 ;
     RECT  81.828 55.589 81.882 55.679 ;
     RECT  0.036 54.707 0.054 55.715 ;
     RECT  23.868 55.211 24.786 55.759 ;
     RECT  2.415 55.651 22.806 55.823 ;
     RECT  23.616 55.759 24.786 55.831 ;
     RECT  2.415 55.823 17.298 55.859 ;
     RECT  25.74 55.211 42.498 55.859 ;
     RECT  18.036 55.823 22.806 55.921 ;
     RECT  23.58 55.831 24.786 55.921 ;
     RECT  40.104 55.859 42.498 55.921 ;
     RECT  43.308 54.905 80.082 55.921 ;
     RECT  0.864 55.013 0.882 55.985 ;
     RECT  18.036 55.921 24.786 56.029 ;
     RECT  25.74 55.859 39.186 56.029 ;
     RECT  81.828 55.679 81.846 56.219 ;
     RECT  40.104 55.921 80.082 56.291 ;
     RECT  2.415 55.859 17.226 56.641 ;
     RECT  18.036 56.029 39.186 56.641 ;
     RECT  2.415 56.641 39.186 56.669 ;
     RECT  2.415 56.669 35.19 56.795 ;
     RECT  20.448 56.795 35.19 56.831 ;
     RECT  40.104 56.291 43.47 56.875 ;
     RECT  35.928 56.669 39.186 56.971 ;
     RECT  40.032 56.875 43.47 56.971 ;
     RECT  2.415 56.795 19.602 57.145 ;
     RECT  35.928 56.971 43.47 57.181 ;
     RECT  44.568 56.291 80.082 57.181 ;
     RECT  1.728 57.145 19.602 57.577 ;
     RECT  20.448 56.831 25.146 57.581 ;
     RECT  0.576 57.415 0.594 57.649 ;
     RECT  1.692 57.577 19.602 57.685 ;
     RECT  20.448 57.581 21.654 57.685 ;
     RECT  25.92 56.831 35.19 57.811 ;
     RECT  35.928 57.181 80.082 57.811 ;
     RECT  22.428 57.581 25.146 58.225 ;
     RECT  25.92 57.811 80.082 58.225 ;
     RECT  0.144 57.649 0.594 58.495 ;
     RECT  1.692 57.685 21.654 58.531 ;
     RECT  22.428 58.225 80.082 58.531 ;
     RECT  0.108 58.495 0.594 58.657 ;
     RECT  1.692 58.531 80.082 58.657 ;
     RECT  0.108 58.657 80.082 59.069 ;
     RECT  27.648 59.069 80.082 59.189 ;
     RECT  27.648 59.189 79.578 59.225 ;
     RECT  77.904 59.225 79.578 59.495 ;
     RECT  36.468 59.225 59.058 59.729 ;
     RECT  59.868 59.225 77.13 59.729 ;
     RECT  0.108 59.069 26.802 59.809 ;
     RECT  27.648 59.225 35.55 59.809 ;
     RECT  0.108 59.809 35.55 59.837 ;
     RECT  36.468 59.729 46.206 59.837 ;
     RECT  77.976 59.495 79.578 60.035 ;
     RECT  66.456 59.729 77.13 60.241 ;
     RECT  77.976 60.035 79.11 60.241 ;
     RECT  36.468 59.837 42.75 60.277 ;
     RECT  1.692 59.837 35.55 60.349 ;
     RECT  36.324 60.277 42.75 60.349 ;
     RECT  59.868 59.729 65.682 60.421 ;
     RECT  59.796 60.421 65.682 60.511 ;
     RECT  66.456 60.241 79.11 60.511 ;
     RECT  43.56 59.837 46.206 60.547 ;
     RECT  46.944 59.729 59.058 60.547 ;
     RECT  43.56 60.547 59.058 60.655 ;
     RECT  59.796 60.511 79.11 60.655 ;
     RECT  1.692 60.349 42.75 60.667 ;
     RECT  43.488 60.655 79.11 60.667 ;
     RECT  1.692 60.667 79.11 60.749 ;
     RECT  2.304 60.749 79.11 60.809 ;
     RECT  0.108 59.837 0.558 60.845 ;
     RECT  0.108 60.845 0.162 61.037 ;
     RECT  2.304 60.809 79.038 61.349 ;
     RECT  2.304 61.349 41.094 61.457 ;
     RECT  0.144 61.037 0.162 61.517 ;
     RECT  44.244 61.349 79.038 61.663 ;
     RECT  44.244 61.663 79.362 61.771 ;
     RECT  0.18 61.663 0.27 61.867 ;
     RECT  44.244 61.771 79.47 61.961 ;
     RECT  0.18 61.867 0.342 61.997 ;
     RECT  2.304 61.457 37.998 62.059 ;
     RECT  38.772 61.457 41.094 62.131 ;
     RECT  42.192 61.349 43.506 62.131 ;
     RECT  44.244 61.961 79.326 62.131 ;
     RECT  2.268 62.059 37.998 62.231 ;
     RECT  20.808 62.231 37.998 62.299 ;
     RECT  38.772 62.131 79.326 62.299 ;
     RECT  2.268 62.231 20.034 62.465 ;
     RECT  0.18 61.997 0.27 62.545 ;
     RECT  20.808 62.299 79.326 62.779 ;
     RECT  20.808 62.779 79.362 62.969 ;
     RECT  2.304 62.465 20.034 63.085 ;
     RECT  2.304 63.085 20.07 63.121 ;
     RECT  20.808 62.969 67.806 63.121 ;
     RECT  0.108 62.545 0.27 63.245 ;
     RECT  68.58 62.969 79.362 63.275 ;
     RECT  68.652 63.275 79.362 63.779 ;
     RECT  2.304 63.121 67.806 64.129 ;
     RECT  68.652 63.779 79.326 64.129 ;
     RECT  2.304 64.129 79.326 64.843 ;
     RECT  0.108 63.245 0.162 64.975 ;
     RECT  2.268 64.843 79.326 65.281 ;
     RECT  2.268 65.281 79.614 65.419 ;
     RECT  1.908 65.419 79.614 65.435 ;
     RECT  0.108 64.975 0.63 65.641 ;
     RECT  18.216 65.435 79.614 65.849 ;
     RECT  18.216 65.849 44.73 66.209 ;
     RECT  0.036 65.641 0.63 66.245 ;
     RECT  20.268 66.209 44.73 66.245 ;
     RECT  1.908 65.435 17.262 66.325 ;
     RECT  18.216 66.209 19.494 66.325 ;
     RECT  20.268 66.245 33.858 66.515 ;
     RECT  34.776 66.245 44.73 66.631 ;
     RECT  45.468 65.849 79.614 66.631 ;
     RECT  21.96 66.515 33.858 66.701 ;
     RECT  34.776 66.631 79.614 66.785 ;
     RECT  1.908 66.325 19.494 66.991 ;
     RECT  20.268 66.515 21.114 66.991 ;
     RECT  32.544 66.701 33.858 67.027 ;
     RECT  34.776 66.785 60.966 67.027 ;
     RECT  1.908 66.991 21.114 67.127 ;
     RECT  0.036 66.245 0.594 67.325 ;
     RECT  32.544 67.027 60.966 67.325 ;
     RECT  2.304 67.127 21.114 67.405 ;
     RECT  21.96 66.701 31.806 67.405 ;
     RECT  2.304 67.405 31.806 67.441 ;
     RECT  32.544 67.325 59.094 67.441 ;
     RECT  2.304 67.441 59.094 67.469 ;
     RECT  0.036 67.325 0.054 67.865 ;
     RECT  59.868 67.325 60.966 67.981 ;
     RECT  61.815 66.785 79.614 67.981 ;
     RECT  59.868 67.981 79.614 68.099 ;
     RECT  2.304 67.469 58.95 68.135 ;
     RECT  18.615 68.135 58.95 68.251 ;
     RECT  59.868 68.099 76.05 68.251 ;
     RECT  2.304 68.135 17.622 68.675 ;
     RECT  18.615 68.251 76.05 68.675 ;
     RECT  34.56 68.675 76.05 68.881 ;
     RECT  76.824 68.099 79.614 68.881 ;
     RECT  34.56 68.881 79.614 68.981 ;
     RECT  18.615 68.675 33.678 69.179 ;
     RECT  2.34 68.675 17.622 69.215 ;
     RECT  2.376 69.215 17.622 69.331 ;
     RECT  34.596 68.981 79.614 69.341 ;
     RECT  2.376 69.331 17.658 69.449 ;
     RECT  34.596 69.341 59.706 69.449 ;
     RECT  2.415 69.449 17.658 69.601 ;
     RECT  18.615 69.179 33.57 69.601 ;
     RECT  2.415 69.601 17.694 69.691 ;
     RECT  18.504 69.601 33.57 69.691 ;
     RECT  2.415 69.691 33.57 69.899 ;
     RECT  43.344 69.449 59.706 70.025 ;
     RECT  34.596 69.449 42.606 70.033 ;
     RECT  34.416 70.033 42.606 70.069 ;
     RECT  49.284 70.025 59.706 70.375 ;
     RECT  18.576 69.899 33.57 70.411 ;
     RECT  34.344 70.069 42.606 70.411 ;
     RECT  49.284 70.375 59.85 70.411 ;
     RECT  60.588 69.341 79.614 70.411 ;
     RECT  18.576 70.411 42.606 70.529 ;
     RECT  49.284 70.411 79.614 70.529 ;
     RECT  32.544 70.529 42.606 70.565 ;
     RECT  2.415 69.899 17.694 70.673 ;
     RECT  14.796 70.673 17.694 70.681 ;
     RECT  18.576 70.529 31.806 70.681 ;
     RECT  40.215 70.565 42.606 70.681 ;
     RECT  43.344 70.025 48.51 70.681 ;
     RECT  49.284 70.529 60.606 70.685 ;
     RECT  2.415 70.673 13.95 70.807 ;
     RECT  40.215 70.681 48.51 70.879 ;
     RECT  49.284 70.685 59.85 70.879 ;
     RECT  40.215 70.879 59.85 71.261 ;
     RECT  14.796 70.681 31.806 71.339 ;
     RECT  33.012 70.565 39.366 71.383 ;
     RECT  43.524 71.261 59.85 71.455 ;
     RECT  60.588 70.685 60.606 71.455 ;
     RECT  43.524 71.455 60.606 71.491 ;
     RECT  61.524 70.529 79.614 71.491 ;
     RECT  32.652 71.383 39.366 71.519 ;
     RECT  33.048 71.519 39.366 71.611 ;
     RECT  40.215 71.261 42.75 71.611 ;
     RECT  16.164 71.339 31.806 71.725 ;
     RECT  33.048 71.611 42.75 71.879 ;
     RECT  2.376 70.807 13.95 71.915 ;
     RECT  40.215 71.879 42.75 72.031 ;
     RECT  43.524 71.491 79.614 72.031 ;
     RECT  16.164 71.725 32.238 72.149 ;
     RECT  2.415 71.915 13.95 72.265 ;
     RECT  14.796 71.339 15.426 72.265 ;
     RECT  2.415 72.265 15.426 72.301 ;
     RECT  16.164 72.149 32.022 72.301 ;
     RECT  2.415 72.301 32.022 72.419 ;
     RECT  2.415 72.419 15.426 72.599 ;
     RECT  33.048 71.879 39.366 72.667 ;
     RECT  40.215 72.031 79.614 72.667 ;
     RECT  16.164 72.419 32.022 72.907 ;
     RECT  33.048 72.667 79.614 72.907 ;
     RECT  16.164 72.907 79.614 72.959 ;
     RECT  16.236 72.959 79.614 73.139 ;
     RECT  16.236 73.139 30.438 73.229 ;
     RECT  2.415 72.599 15.066 73.381 ;
     RECT  31.212 73.139 79.614 73.499 ;
     RECT  32.796 73.499 79.398 73.535 ;
     RECT  32.796 73.535 40.497 73.607 ;
     RECT  32.796 73.607 33.138 73.769 ;
     RECT  2.415 73.381 15.174 73.921 ;
     RECT  27.504 73.229 30.438 73.921 ;
     RECT  27.504 73.921 30.474 74.039 ;
     RECT  31.212 73.499 32.022 74.039 ;
     RECT  31.212 74.039 31.734 74.075 ;
     RECT  16.236 73.229 26.73 74.083 ;
     RECT  27.504 74.039 27.558 74.083 ;
     RECT  28.296 74.039 30.474 74.119 ;
     RECT  31.212 74.075 31.698 74.119 ;
     RECT  2.415 73.921 15.21 74.191 ;
     RECT  16.236 74.083 27.558 74.191 ;
     RECT  34.164 73.607 40.497 74.425 ;
     RECT  34.056 74.425 40.497 74.461 ;
     RECT  41.22 73.535 79.398 74.461 ;
     RECT  34.056 74.461 79.398 74.489 ;
     RECT  32.796 73.769 32.994 74.623 ;
     RECT  34.056 74.489 62.622 74.623 ;
     RECT  32.58 74.623 62.622 74.759 ;
     RECT  28.296 74.119 31.698 74.821 ;
     RECT  32.58 74.759 60.642 74.821 ;
     RECT  2.415 74.191 27.558 75.005 ;
     RECT  61.56 74.759 62.622 75.119 ;
     RECT  27.54 75.005 27.558 75.199 ;
     RECT  28.296 74.821 60.642 75.199 ;
     RECT  27.54 75.199 60.642 75.389 ;
     RECT  63.36 74.489 79.398 75.389 ;
     RECT  2.415 75.005 26.55 75.425 ;
     RECT  33.948 75.389 60.642 75.461 ;
     RECT  34.74 75.461 60.642 75.505 ;
     RECT  34.74 75.505 60.786 75.631 ;
     RECT  61.56 75.119 62.514 75.631 ;
     RECT  2.415 75.425 15.39 75.659 ;
     RECT  16.236 75.425 26.55 75.659 ;
     RECT  34.74 75.631 62.514 75.659 ;
     RECT  63.36 75.389 79.362 75.659 ;
     RECT  2.415 75.659 14.85 75.767 ;
     RECT  63.36 75.659 78.894 75.767 ;
     RECT  75.132 75.767 78.894 75.812 ;
     RECT  34.776 75.659 62.514 75.839 ;
     RECT  34.776 75.839 62.37 75.965 ;
     RECT  34.776 75.965 48.654 76.109 ;
     RECT  33.948 75.461 33.966 76.199 ;
     RECT  63.36 75.767 74.178 76.199 ;
     RECT  27.54 75.389 33.066 76.207 ;
     RECT  63.432 76.199 74.178 76.235 ;
     RECT  75.168 75.812 78.894 76.271 ;
     RECT  27.54 76.207 33.858 76.363 ;
     RECT  27.324 76.363 33.858 76.397 ;
     RECT  16.236 75.659 26.478 76.441 ;
     RECT  27.324 76.397 27.342 76.441 ;
     RECT  2.415 75.767 14.778 76.469 ;
     RECT  49.428 75.965 62.37 76.469 ;
     RECT  16.236 76.441 27.342 76.585 ;
     RECT  28.116 76.397 33.858 76.739 ;
     RECT  43.596 76.109 48.654 76.747 ;
     RECT  49.428 76.469 60.714 76.747 ;
     RECT  3.564 76.469 14.778 76.855 ;
     RECT  34.776 76.109 42.786 76.855 ;
     RECT  43.596 76.747 60.714 76.855 ;
     RECT  34.776 76.855 60.714 76.919 ;
     RECT  61.488 76.469 62.37 76.981 ;
     RECT  16.164 76.585 27.342 77.083 ;
     RECT  34.776 76.919 60.57 77.089 ;
     RECT  28.116 76.739 33.642 77.153 ;
     RECT  15.84 77.083 27.342 77.161 ;
     RECT  28.116 77.153 33.462 77.161 ;
     RECT  63.432 76.235 74.034 77.161 ;
     RECT  75.24 76.271 78.894 77.161 ;
     RECT  15.84 77.161 33.462 77.189 ;
     RECT  15.912 77.189 33.462 77.279 ;
     RECT  61.488 76.981 62.514 77.279 ;
     RECT  63.432 77.161 78.894 77.279 ;
     RECT  15.984 77.279 27.666 77.387 ;
     RECT  28.512 77.279 33.462 77.459 ;
     RECT  15.984 77.387 20.034 77.549 ;
     RECT  2.415 76.469 2.697 77.557 ;
     RECT  3.564 76.855 15.066 77.557 ;
     RECT  34.524 77.089 60.57 77.557 ;
     RECT  34.38 77.557 60.57 77.701 ;
     RECT  61.812 77.279 62.514 77.701 ;
     RECT  63.432 77.279 74.79 77.701 ;
     RECT  2.415 77.557 15.066 77.819 ;
     RECT  34.38 77.701 60.642 77.819 ;
     RECT  61.812 77.701 74.79 77.855 ;
     RECT  75.672 77.279 78.894 77.855 ;
     RECT  34.38 77.819 44.442 77.899 ;
     RECT  34.344 77.899 44.442 77.935 ;
     RECT  20.88 77.387 27.666 77.963 ;
     RECT  74.448 77.855 74.79 77.999 ;
     RECT  34.272 77.935 44.442 78.061 ;
     RECT  3.528 77.819 15.066 78.089 ;
     RECT  61.812 77.855 73.566 78.089 ;
     RECT  74.448 77.999 74.466 78.089 ;
     RECT  45.252 77.819 60.642 78.097 ;
     RECT  3.528 78.089 14.418 78.125 ;
     RECT  45.252 78.097 60.858 78.125 ;
     RECT  34.2 78.061 44.442 78.161 ;
     RECT  45.252 78.125 47.934 78.161 ;
     RECT  45.252 78.161 46.782 78.173 ;
     RECT  34.2 78.161 43.29 78.205 ;
     RECT  25.632 77.963 27.666 78.241 ;
     RECT  28.512 77.459 33.21 78.241 ;
     RECT  3.528 78.125 13.59 78.359 ;
     RECT  47.52 78.161 47.934 78.359 ;
     RECT  75.672 77.855 76.986 78.359 ;
     RECT  25.632 78.241 33.21 78.367 ;
     RECT  34.092 78.205 43.29 78.367 ;
     RECT  20.88 77.963 24.786 78.439 ;
     RECT  25.632 78.367 43.29 78.467 ;
     RECT  3.528 78.359 10.098 78.503 ;
     RECT  75.672 78.359 76.914 78.511 ;
     RECT  3.528 78.503 9.342 78.539 ;
     RECT  45.324 78.173 46.782 78.539 ;
     RECT  75.528 78.511 76.914 78.539 ;
     RECT  64.044 78.089 73.566 78.601 ;
     RECT  10.08 78.503 10.098 78.629 ;
     RECT  25.632 78.467 33.21 78.629 ;
     RECT  77.904 77.855 78.894 78.629 ;
     RECT  15.984 77.549 19.926 78.673 ;
     RECT  20.772 78.439 24.786 78.673 ;
     RECT  48.744 78.125 60.858 78.701 ;
     RECT  64.044 78.601 73.602 78.701 ;
     RECT  61.812 78.089 62.982 78.709 ;
     RECT  50.688 78.701 60.858 78.745 ;
     RECT  61.668 78.709 62.982 78.745 ;
     RECT  75.528 78.539 75.798 78.745 ;
     RECT  75.384 78.745 75.798 78.773 ;
     RECT  15.156 78.673 15.246 78.781 ;
     RECT  15.984 78.673 24.786 78.781 ;
     RECT  77.904 78.629 78.297 78.781 ;
     RECT  14.328 78.125 14.346 78.871 ;
     RECT  15.156 78.781 24.786 78.871 ;
     RECT  48.744 78.701 49.95 78.871 ;
     RECT  64.044 78.701 73.53 78.871 ;
     RECT  63.828 78.871 73.53 78.899 ;
     RECT  75.384 78.773 75.546 78.899 ;
     RECT  76.644 78.539 76.914 78.899 ;
     RECT  50.688 78.745 62.982 78.907 ;
     RECT  25.632 78.629 33.102 78.935 ;
     RECT  63.828 78.899 73.278 78.935 ;
     RECT  76.716 78.899 76.914 78.935 ;
     RECT  48.708 78.871 49.95 78.971 ;
     RECT  63.828 78.935 73.242 79.007 ;
     RECT  2.415 77.819 2.697 79.015 ;
     RECT  3.528 78.539 4.734 79.015 ;
     RECT  50.688 78.907 63.054 79.043 ;
     RECT  63.828 79.007 72.954 79.043 ;
     RECT  14.328 78.871 24.786 79.051 ;
     RECT  34.164 78.467 43.29 79.051 ;
     RECT  44.028 78.161 44.442 79.051 ;
     RECT  45.615 78.539 46.782 79.051 ;
     RECT  60.804 79.043 63.054 79.051 ;
     RECT  63.828 79.043 64.53 79.051 ;
     RECT  2.415 79.015 4.734 79.169 ;
     RECT  5.472 78.539 9.342 79.169 ;
     RECT  10.836 78.359 13.59 79.169 ;
     RECT  34.164 79.051 44.442 79.169 ;
     RECT  45.615 79.051 46.854 79.169 ;
     RECT  50.688 79.043 59.886 79.169 ;
     RECT  60.804 79.051 64.53 79.169 ;
     RECT  65.412 79.043 72.897 79.169 ;
     RECT  77.688 78.781 78.297 79.169 ;
     RECT  34.164 79.169 36.558 79.181 ;
     RECT  5.58 79.169 9.162 79.205 ;
     RECT  53.676 79.169 59.886 79.205 ;
     RECT  60.804 79.169 64.35 79.205 ;
     RECT  76.896 78.935 76.914 79.205 ;
     RECT  14.328 79.051 24.894 79.213 ;
     RECT  25.632 78.935 26.838 79.213 ;
     RECT  2.415 79.169 3.402 79.229 ;
     RECT  14.328 79.213 26.838 79.229 ;
     RECT  4.356 79.169 4.734 79.241 ;
     RECT  5.688 79.205 8.514 79.241 ;
     RECT  14.328 79.229 19.746 79.241 ;
     RECT  20.484 79.229 26.838 79.241 ;
     RECT  50.688 79.169 52.434 79.241 ;
     RECT  53.676 79.205 59.418 79.241 ;
     RECT  65.412 79.169 66.33 79.241 ;
     RECT  6.264 79.241 8.514 79.277 ;
     RECT  54.036 79.241 59.418 79.277 ;
     RECT  10.836 79.169 13.497 79.285 ;
     RECT  14.328 79.241 16.254 79.285 ;
     RECT  22.716 79.241 26.838 79.313 ;
     RECT  37.296 79.169 44.442 79.313 ;
     RECT  47.592 78.359 47.934 79.313 ;
     RECT  48.708 78.971 49.266 79.313 ;
     RECT  54.036 79.277 59.346 79.313 ;
     RECT  65.736 79.241 66.33 79.313 ;
     RECT  67.215 79.169 72.897 79.313 ;
     RECT  42.264 79.313 44.442 79.349 ;
     RECT  49.032 79.313 49.266 79.349 ;
     RECT  10.548 79.285 13.497 79.435 ;
     RECT  4.608 79.241 4.734 79.439 ;
     RECT  20.484 79.241 21.87 79.439 ;
     RECT  27.72 78.935 33.102 79.439 ;
     RECT  37.296 79.313 41.49 79.439 ;
     RECT  42.912 79.349 44.442 79.439 ;
     RECT  47.808 79.313 47.934 79.439 ;
     RECT  49.248 79.349 49.266 79.439 ;
     RECT  60.804 79.205 64.314 79.439 ;
     RECT  66.168 79.313 66.33 79.439 ;
     RECT  33.084 79.439 33.102 79.447 ;
     RECT  4.608 79.439 4.626 79.475 ;
     RECT  6.732 79.277 8.514 79.475 ;
     RECT  10.404 79.435 13.497 79.475 ;
     RECT  14.292 79.285 16.254 79.475 ;
     RECT  20.628 79.439 21.402 79.475 ;
     RECT  27.72 79.439 32.022 79.475 ;
     RECT  33.084 79.447 33.246 79.475 ;
     RECT  34.236 79.181 36.558 79.475 ;
     RECT  39.204 79.439 41.49 79.475 ;
     RECT  42.912 79.439 43.182 79.475 ;
     RECT  43.956 79.439 44.37 79.475 ;
     RECT  45.615 79.169 46.71 79.475 ;
     RECT  47.88 79.439 47.934 79.475 ;
     RECT  54.036 79.313 57.906 79.475 ;
     RECT  66.312 79.439 66.33 79.475 ;
     RECT  10.836 79.475 12.006 79.511 ;
     RECT  16.992 79.241 19.746 79.511 ;
     RECT  34.236 79.475 36.45 79.511 ;
     RECT  43.164 79.475 43.182 79.511 ;
     RECT  50.688 79.241 52.398 79.511 ;
     RECT  67.215 79.313 71.118 79.511 ;
     RECT  37.296 79.439 37.926 79.517 ;
     RECT  14.616 79.475 16.254 79.547 ;
     RECT  17.028 79.511 19.746 79.547 ;
     RECT  21.06 79.475 21.402 79.547 ;
     RECT  22.716 79.313 25.866 79.547 ;
     RECT  26.82 79.313 26.838 79.547 ;
     RECT  31.608 79.475 32.022 79.547 ;
     RECT  36.432 79.511 36.45 79.547 ;
     RECT  54.18 79.475 57.906 79.547 ;
     RECT  7.38 79.475 8.514 79.583 ;
     RECT  14.724 79.547 16.254 79.583 ;
     RECT  21.132 79.547 21.402 79.583 ;
     RECT  34.236 79.511 35.658 79.583 ;
     RECT  50.796 79.511 52.002 79.583 ;
     RECT  54.18 79.547 54.45 79.583 ;
     RECT  55.224 79.547 55.242 79.583 ;
     RECT  67.215 79.511 70.758 79.583 ;
     RECT  24.015 79.547 25.866 79.613 ;
     RECT  11.988 79.511 12.006 79.619 ;
     RECT  14.724 79.583 15.966 79.619 ;
     RECT  22.716 79.547 22.734 79.619 ;
     RECT  27.72 79.475 30.582 79.619 ;
     RECT  32.004 79.547 32.022 79.619 ;
     RECT  39.204 79.475 40.497 79.619 ;
     RECT  47.88 79.475 47.898 79.619 ;
     RECT  50.832 79.583 52.002 79.619 ;
     RECT  54.18 79.583 54.198 79.619 ;
     RECT  61.596 79.439 63.234 79.619 ;
     RECT  64.296 79.439 64.314 79.619 ;
     RECT  67.215 79.583 70.686 79.619 ;
     RECT  2.415 79.229 2.697 79.667 ;
     RECT  13.215 79.475 13.497 79.667 ;
     RECT  24.015 79.613 25.146 79.667 ;
     RECT  40.215 79.619 40.497 79.667 ;
     RECT  45.615 79.475 45.897 79.667 ;
     RECT  56.415 79.547 57.906 79.667 ;
     RECT  67.215 79.619 68.166 79.667 ;
     RECT  71.964 79.313 72.897 79.667 ;
     RECT  78.015 79.169 78.297 79.667 ;
     RECT  7.596 79.583 8.514 79.709 ;
     RECT  10.836 79.511 11.034 79.709 ;
     RECT  14.724 79.619 15.282 79.709 ;
     RECT  17.82 79.547 19.746 79.709 ;
     RECT  24.984 79.667 25.146 79.709 ;
     RECT  27.72 79.619 27.954 79.709 ;
     RECT  29.016 79.619 30.582 79.709 ;
     RECT  37.908 79.517 37.926 79.709 ;
     RECT  43.992 79.475 44.334 79.709 ;
     RECT  50.832 79.619 51.75 79.709 ;
     RECT  57.348 79.667 57.906 79.709 ;
     RECT  60.804 79.439 60.822 79.709 ;
     RECT  61.815 79.619 63.234 79.709 ;
     RECT  68.04 79.667 68.166 79.709 ;
     RECT  69.12 79.619 69.93 79.709 ;
     RECT  71.964 79.667 72.705 79.709 ;
     RECT  10.836 79.709 10.962 79.715 ;
     RECT  17.82 79.709 19.458 79.745 ;
     RECT  24.984 79.709 25.002 79.745 ;
     RECT  27.792 79.709 27.81 79.745 ;
     RECT  29.415 79.709 30.15 79.745 ;
     RECT  33.228 79.475 33.246 79.745 ;
     RECT  40.215 79.667 40.374 79.745 ;
     RECT  41.472 79.475 41.49 79.745 ;
     RECT  43.992 79.709 44.01 79.745 ;
     RECT  62.676 79.709 63.198 79.745 ;
     RECT  10.944 79.715 10.962 79.781 ;
     RECT  17.856 79.745 19.458 79.781 ;
     RECT  21.384 79.583 21.402 79.781 ;
     RECT  34.236 79.583 35.334 79.781 ;
     RECT  39.276 79.619 39.294 79.781 ;
     RECT  50.976 79.709 51.105 79.781 ;
     RECT  57.348 79.709 57.366 79.781 ;
     RECT  58.716 79.313 58.734 79.781 ;
     RECT  62.676 79.745 62.694 79.781 ;
     RECT  68.04 79.709 68.058 79.781 ;
     RECT  69.12 79.709 69.678 79.781 ;
     RECT  70.668 79.619 70.686 79.781 ;
     RECT  14.724 79.709 15.138 79.805 ;
     RECT  69.3 79.781 69.318 79.817 ;
     RECT  18.615 79.781 19.386 79.853 ;
     RECT  2.415 79.667 2.505 79.937 ;
     RECT  7.815 79.709 7.905 79.937 ;
     RECT  13.215 79.667 13.305 79.937 ;
     RECT  18.615 79.853 18.705 79.937 ;
     RECT  24.015 79.667 24.105 79.937 ;
     RECT  29.415 79.745 29.505 79.937 ;
     RECT  34.815 79.781 34.905 79.937 ;
     RECT  40.215 79.745 40.305 79.937 ;
     RECT  45.615 79.667 45.705 79.937 ;
     RECT  51.015 79.781 51.105 79.937 ;
     RECT  56.415 79.667 56.505 79.937 ;
     RECT  61.815 79.709 61.905 79.937 ;
     RECT  67.215 79.667 67.305 79.937 ;
     RECT  72.615 79.709 72.705 79.937 ;
     RECT  78.015 79.667 78.105 79.937 ;
    LAYER M4 ;
     RECT  0.06 24.528 0.097 27.528 ;
     RECT  0.06 59.088 0.133 65.928 ;
     RECT  0.097 24.528 0.137 27.72 ;
     RECT  0.06 30.672 0.137 36.744 ;
     RECT  0.06 48.048 0.137 52.872 ;
     RECT  0.137 24.624 0.173 27.72 ;
     RECT  0.137 48.144 0.173 52.872 ;
     RECT  0.06 17.616 0.209 20.616 ;
     RECT  0.137 30.672 0.227 36.648 ;
     RECT  0.173 48.24 1.249 52.872 ;
     RECT  0.173 24.72 2.293 27.72 ;
     RECT  2.329 13.632 2.408 13.656 ;
     RECT  2.365 15.984 2.408 16.008 ;
     RECT  0.209 17.616 2.408 20.52 ;
     RECT  2.401 22.8 2.408 22.824 ;
     RECT  2.293 24.72 2.408 28.344 ;
     RECT  2.285 29.76 2.408 29.784 ;
     RECT  0.227 30.864 2.408 36.648 ;
     RECT  0.181 41.136 2.408 41.16 ;
     RECT  0.06 43.728 2.408 46.728 ;
     RECT  1.249 48.24 2.408 52.968 ;
     RECT  0.133 59.088 2.408 66.024 ;
     RECT  2.408 2.148 2.512 79.932 ;
     RECT  2.512 2.418 2.704 79.662 ;
     RECT  2.704 13.632 2.765 18.648 ;
     RECT  2.704 24.528 2.765 27.384 ;
     RECT  2.704 50.544 2.765 52.008 ;
     RECT  2.704 59.184 2.765 65.976 ;
     RECT  2.765 24.528 2.801 24.936 ;
     RECT  2.704 39.168 2.801 47.304 ;
     RECT  2.765 13.632 2.819 17.112 ;
     RECT  2.765 59.28 2.819 65.976 ;
     RECT  2.704 71.184 2.819 71.208 ;
     RECT  2.704 72.912 2.819 74.664 ;
     RECT  2.704 48.432 2.837 49.512 ;
     RECT  2.819 59.28 2.837 60.36 ;
     RECT  2.704 5.28 2.867 6.888 ;
     RECT  2.819 74.64 2.867 74.664 ;
     RECT  2.704 31.152 2.945 36.504 ;
     RECT  2.704 68.352 2.963 69.864 ;
     RECT  2.819 61.344 3.017 65.976 ;
     RECT  2.819 14.352 3.053 17.112 ;
     RECT  2.837 59.28 3.053 60.024 ;
     RECT  2.765 26.064 3.089 27.384 ;
     RECT  2.945 31.152 3.089 34.776 ;
     RECT  2.765 50.544 3.089 51.24 ;
     RECT  3.089 31.152 3.125 34.68 ;
     RECT  3.089 50.544 3.125 50.856 ;
     RECT  2.867 5.28 3.491 6.12 ;
     RECT  3.053 14.352 3.557 15.384 ;
     RECT  2.704 19.632 3.635 23.544 ;
     RECT  2.704 2.736 3.685 3.48 ;
     RECT  2.704 11.808 3.697 12.552 ;
     RECT  2.704 58.032 3.697 58.056 ;
     RECT  3.697 11.52 3.733 12.552 ;
     RECT  2.801 46.896 3.733 47.304 ;
     RECT  2.837 48.432 3.733 49.224 ;
     RECT  3.089 26.256 3.773 27.384 ;
     RECT  3.773 26.448 3.805 27.384 ;
     RECT  2.704 28.416 3.805 29.544 ;
     RECT  2.704 77.856 3.805 77.88 ;
     RECT  2.704 79.2 3.805 79.224 ;
     RECT  2.704 9.552 3.841 10.344 ;
     RECT  3.733 11.424 3.841 12.552 ;
     RECT  3.733 46.896 3.841 49.224 ;
     RECT  2.704 54.144 3.845 56.52 ;
     RECT  3.841 9.552 3.877 12.552 ;
     RECT  3.805 26.448 3.877 29.544 ;
     RECT  3.125 31.152 3.877 34.248 ;
     RECT  2.801 39.168 3.877 44.904 ;
     RECT  3.697 57.696 3.877 58.152 ;
     RECT  3.053 59.28 3.877 59.64 ;
     RECT  3.877 39.168 3.881 45.048 ;
     RECT  3.769 52.848 3.905 52.872 ;
     RECT  3.557 14.352 3.913 14.904 ;
     RECT  3.125 50.544 3.925 50.664 ;
     RECT  3.017 61.344 3.949 65.304 ;
     RECT  2.963 69.072 3.949 69.864 ;
     RECT  3.877 9.12 3.964 12.552 ;
     RECT  3.685 2.736 3.985 3.96 ;
     RECT  3.491 5.616 3.985 6.12 ;
     RECT  3.964 9.36 3.985 12.552 ;
     RECT  3.913 13.872 3.985 14.904 ;
     RECT  3.905 52.848 3.989 53.064 ;
     RECT  3.881 39.168 4.021 41.16 ;
     RECT  3.841 46.512 4.021 49.224 ;
     RECT  3.877 57.696 4.021 59.64 ;
     RECT  3.949 73.056 4.021 73.08 ;
     RECT  3.985 5.616 4.025 6.312 ;
     RECT  3.845 54.144 4.025 56.184 ;
     RECT  2.945 36.48 4.057 36.504 ;
     RECT  4.021 46.176 4.057 49.224 ;
     RECT  3.925 50.4 4.057 50.664 ;
     RECT  3.989 52.848 4.057 52.872 ;
     RECT  3.949 68.928 4.061 69.864 ;
     RECT  4.021 73.056 4.093 73.656 ;
     RECT  3.053 16.944 4.165 17.112 ;
     RECT  2.765 18.24 4.165 18.648 ;
     RECT  2.704 76.416 4.201 76.44 ;
     RECT  3.805 77.856 4.201 79.224 ;
     RECT  4.057 36.288 4.237 36.504 ;
     RECT  4.057 46.176 4.237 50.664 ;
     RECT  3.949 61.152 4.237 65.304 ;
     RECT  4.165 66.72 4.237 66.744 ;
     RECT  4.165 16.944 4.273 18.648 ;
     RECT  3.635 19.632 4.273 23.352 ;
     RECT  3.877 26.448 4.273 34.248 ;
     RECT  4.093 73.008 4.273 73.656 ;
     RECT  4.021 57.408 4.277 59.64 ;
     RECT  4.273 73.008 4.309 73.992 ;
     RECT  4.273 26.448 4.403 34.536 ;
     RECT  2.801 24.528 4.417 24.552 ;
     RECT  4.237 35.952 4.417 36.504 ;
     RECT  4.201 75.456 4.417 76.44 ;
     RECT  4.403 26.448 4.421 33.576 ;
     RECT  4.309 73.008 4.421 74.088 ;
     RECT  4.021 38.736 4.453 41.16 ;
     RECT  4.417 75.36 4.453 76.44 ;
     RECT  4.201 77.712 4.453 79.224 ;
     RECT  3.881 42.528 4.489 45.048 ;
     RECT  4.237 46.176 4.489 51.288 ;
     RECT  4.237 61.152 4.489 66.744 ;
     RECT  4.453 75.36 4.501 79.224 ;
     RECT  4.057 15.936 4.549 15.96 ;
     RECT  4.273 16.944 4.549 23.352 ;
     RECT  4.025 6.288 4.705 6.312 ;
     RECT  4.633 7.68 4.705 7.704 ;
     RECT  4.549 15.936 4.745 23.352 ;
     RECT  3.985 9.36 4.781 14.904 ;
     RECT  4.417 24.528 4.789 25.08 ;
     RECT  2.704 37.584 4.813 37.608 ;
     RECT  4.453 38.64 4.813 41.16 ;
     RECT  4.705 6.288 4.817 7.704 ;
     RECT  4.489 71.232 4.921 71.256 ;
     RECT  4.057 52.464 4.957 52.872 ;
     RECT  4.817 7.68 4.961 7.704 ;
     RECT  4.781 9.36 4.993 14.616 ;
     RECT  4.421 73.248 4.997 74.088 ;
     RECT  4.025 54.576 5.029 56.184 ;
     RECT  4.277 57.408 5.029 59.304 ;
     RECT  4.061 68.928 5.101 68.952 ;
     RECT  4.669 69.984 5.101 70.152 ;
     RECT  4.921 71.232 5.101 72.264 ;
     RECT  4.489 42.528 5.105 51.288 ;
     RECT  5.029 54.576 5.141 59.304 ;
     RECT  3.985 2.736 5.173 4.056 ;
     RECT  5.141 59.28 5.245 59.304 ;
     RECT  5.173 2.736 5.257 4.536 ;
     RECT  4.817 6.288 5.317 6.408 ;
     RECT  4.789 24.336 5.317 25.08 ;
     RECT  4.421 26.448 5.317 33.24 ;
     RECT  5.105 49.392 5.317 51.288 ;
     RECT  4.957 52.464 5.317 52.968 ;
     RECT  5.257 2.736 5.363 4.056 ;
     RECT  4.417 34.656 5.389 36.504 ;
     RECT  4.489 60.912 5.389 66.984 ;
     RECT  5.029 7.728 5.42 7.752 ;
     RECT  4.993 8.736 5.42 14.616 ;
     RECT  5.317 49.392 5.425 52.968 ;
     RECT  5.141 54.576 5.425 58.296 ;
     RECT  5.317 24.336 5.461 33.24 ;
     RECT  5.105 42.528 5.497 48.36 ;
     RECT  5.101 68.928 5.525 72.264 ;
     RECT  4.997 73.248 5.525 73.992 ;
     RECT  5.497 42.144 5.537 48.36 ;
     RECT  5.425 49.392 5.573 58.296 ;
     RECT  5.42 7.728 5.609 14.616 ;
     RECT  5.461 24.336 5.609 33.432 ;
     RECT  5.525 68.928 5.609 73.992 ;
     RECT  5.245 59.28 5.677 59.496 ;
     RECT  5.317 5.664 5.699 6.408 ;
     RECT  4.745 17.664 5.708 23.352 ;
     RECT  5.609 24.336 5.708 33.24 ;
     RECT  5.363 3.888 5.717 4.056 ;
     RECT  4.501 75.12 5.747 79.224 ;
     RECT  5.717 3.888 5.753 3.96 ;
     RECT  5.708 17.664 5.789 33.24 ;
     RECT  5.609 10.752 5.861 14.616 ;
     RECT  4.813 37.584 5.897 41.16 ;
     RECT  5.789 32.448 6.005 33.24 ;
     RECT  5.861 10.848 6.037 14.616 ;
     RECT  5.609 7.728 6.041 9.624 ;
     RECT  5.363 2.736 6.077 2.904 ;
     RECT  4.745 15.936 6.109 16.536 ;
     RECT  5.789 17.664 6.109 24.36 ;
     RECT  5.897 38.736 6.109 41.16 ;
     RECT  5.537 42.144 6.109 48.312 ;
     RECT  5.573 49.44 6.14 58.296 ;
     RECT  5.677 59.28 6.14 59.832 ;
     RECT  6.037 10.848 6.227 14.76 ;
     RECT  6.14 49.44 6.227 59.832 ;
     RECT  5.389 34.56 6.277 36.504 ;
     RECT  5.897 37.584 6.277 37.608 ;
     RECT  6.005 32.448 6.293 33 ;
     RECT  6.109 38.736 6.293 48.312 ;
     RECT  6.077 2.736 6.397 2.808 ;
     RECT  5.753 3.888 6.401 3.912 ;
     RECT  6.293 38.736 6.508 47.928 ;
     RECT  5.747 75.12 6.509 75.96 ;
     RECT  6.227 59.472 6.577 59.832 ;
     RECT  5.389 60.912 6.577 67.8 ;
     RECT  6.277 34.56 6.613 37.608 ;
     RECT  6.227 49.44 6.617 58.152 ;
     RECT  6.041 9.024 6.677 9.624 ;
     RECT  6.109 15.936 6.689 24.36 ;
     RECT  5.699 6.288 6.709 6.408 ;
     RECT  5.747 77.088 6.716 79.224 ;
     RECT  6.677 9.024 6.761 9.72 ;
     RECT  6.689 20.928 6.761 24.36 ;
     RECT  6.716 77.088 6.761 79.464 ;
     RECT  5.789 25.68 6.793 31.128 ;
     RECT  6.761 77.52 6.803 79.464 ;
     RECT  6.227 11.232 6.829 14.76 ;
     RECT  6.689 15.936 6.829 16.104 ;
     RECT  6.509 75.12 6.973 75.864 ;
     RECT  7.009 4.464 7.081 4.488 ;
     RECT  6.709 5.616 7.081 6.408 ;
     RECT  5.609 68.928 7.225 73.56 ;
     RECT  6.397 2.544 7.333 2.808 ;
     RECT  6.761 9.024 7.369 9.192 ;
     RECT  7.333 2.544 7.441 3.096 ;
     RECT  7.081 4.464 7.441 6.408 ;
     RECT  6.613 34.08 7.477 37.608 ;
     RECT  6.508 38.736 7.477 47.304 ;
     RECT  6.761 21.264 7.669 24.36 ;
     RECT  7.477 34.08 7.669 47.304 ;
     RECT  7.669 34.08 7.693 47.352 ;
     RECT  7.369 8.976 7.765 9.192 ;
     RECT  7.441 2.544 7.808 6.408 ;
     RECT  6.041 7.728 7.808 7.992 ;
     RECT  7.765 8.976 7.808 9.288 ;
     RECT  6.829 11.232 7.808 16.104 ;
     RECT  6.689 17.76 7.808 19.944 ;
     RECT  7.669 21.264 7.808 24.456 ;
     RECT  6.793 25.488 7.808 31.128 ;
     RECT  6.293 32.448 7.808 32.472 ;
     RECT  7.693 34.08 7.808 47.4 ;
     RECT  6.617 50.4 7.808 58.152 ;
     RECT  6.577 59.472 7.808 67.8 ;
     RECT  7.225 68.88 7.808 73.56 ;
     RECT  6.973 74.592 7.808 75.864 ;
     RECT  6.803 77.52 7.808 79.08 ;
     RECT  7.808 2.148 7.912 79.932 ;
     RECT  7.912 2.418 8.104 79.662 ;
     RECT  8.104 68.928 8.165 73.608 ;
     RECT  8.104 54.72 8.243 66.36 ;
     RECT  8.104 19.872 8.291 47.928 ;
     RECT  8.104 3.84 8.309 7.992 ;
     RECT  8.104 17.664 8.309 18.504 ;
     RECT  8.243 54.72 8.309 55.464 ;
     RECT  8.243 56.448 8.309 66.36 ;
     RECT  8.291 19.872 8.317 30.744 ;
     RECT  8.104 11.28 8.417 14.184 ;
     RECT  8.104 16.32 8.489 16.344 ;
     RECT  8.104 8.976 8.525 10.104 ;
     RECT  8.291 31.824 8.531 47.928 ;
     RECT  8.104 48.912 8.633 53.64 ;
     RECT  8.309 54.72 8.633 55.272 ;
     RECT  8.165 68.928 8.633 70.584 ;
     RECT  8.104 67.392 8.705 67.848 ;
     RECT  8.317 19.872 8.741 30.216 ;
     RECT  8.531 35.328 8.777 47.928 ;
     RECT  8.633 48.912 8.819 53.064 ;
     RECT  8.531 32.448 8.849 34.152 ;
     RECT  8.104 2.544 8.921 2.568 ;
     RECT  8.777 35.328 8.957 47.88 ;
     RECT  8.104 74.592 8.957 77.928 ;
     RECT  8.741 23.904 8.963 30.216 ;
     RECT  8.525 8.976 8.993 9 ;
     RECT  8.309 3.84 9.029 4.44 ;
     RECT  8.309 17.664 9.029 18.456 ;
     RECT  8.309 56.448 9.029 66.072 ;
     RECT  8.165 71.664 9.065 73.608 ;
     RECT  8.957 77.856 9.097 77.928 ;
     RECT  8.104 79.008 9.097 79.032 ;
     RECT  8.633 55.248 9.109 55.272 ;
     RECT  8.963 26.496 9.137 30.216 ;
     RECT  8.849 32.688 9.137 34.152 ;
     RECT  8.819 49.488 9.137 53.064 ;
     RECT  9.097 77.856 9.173 79.032 ;
     RECT  9.065 72 9.205 73.608 ;
     RECT  8.957 74.592 9.205 76.824 ;
     RECT  9.173 77.856 9.209 78.072 ;
     RECT  8.741 19.872 9.241 22.824 ;
     RECT  8.963 23.904 9.281 25.512 ;
     RECT  8.957 35.664 9.299 47.88 ;
     RECT  9.137 30.192 9.313 30.216 ;
     RECT  9.029 63.072 9.313 66.072 ;
     RECT  8.705 67.392 9.313 67.416 ;
     RECT  9.137 33.024 9.317 34.152 ;
     RECT  9.209 77.904 9.317 78.072 ;
     RECT  9.299 35.664 9.347 45.24 ;
     RECT  8.417 12.048 9.349 14.184 ;
     RECT  9.313 63.072 9.353 67.416 ;
     RECT  9.241 19.68 9.389 22.824 ;
     RECT  9.317 33.024 9.389 33.096 ;
     RECT  9.317 77.904 9.389 77.928 ;
     RECT  9.389 19.872 9.461 22.824 ;
     RECT  9.097 17.088 9.497 17.112 ;
     RECT  9.281 23.904 9.497 24.792 ;
     RECT  9.029 4.416 9.529 4.44 ;
     RECT  8.525 10.032 9.529 10.104 ;
     RECT  9.299 47.04 9.569 47.88 ;
     RECT  9.313 30.192 9.587 30.792 ;
     RECT  9.317 34.128 9.637 34.152 ;
     RECT  9.569 47.28 9.677 47.88 ;
     RECT  9.029 56.448 9.677 61.992 ;
     RECT  9.497 24.432 9.713 24.792 ;
     RECT  9.677 47.856 9.749 47.88 ;
     RECT  9.353 66.672 9.749 67.416 ;
     RECT  9.461 20.016 9.781 22.824 ;
     RECT  8.633 68.928 9.817 70.152 ;
     RECT  8.309 5.76 9.821 7.992 ;
     RECT  9.529 4.416 9.857 4.488 ;
     RECT  9.817 67.824 9.889 70.152 ;
     RECT  9.529 9.936 9.893 10.104 ;
     RECT  9.781 20.016 9.923 23.256 ;
     RECT  9.029 18.144 9.925 18.456 ;
     RECT  9.137 26.496 9.925 28.968 ;
     RECT  9.857 4.416 9.929 4.44 ;
     RECT  9.677 57.024 9.929 61.992 ;
     RECT  9.925 26.304 9.965 28.968 ;
     RECT  9.929 59.472 9.997 61.992 ;
     RECT  9.353 63.072 9.997 65.688 ;
     RECT  9.137 49.488 10.001 53.016 ;
     RECT  10.069 54.096 10.152 54.12 ;
     RECT  9.205 72 10.177 76.824 ;
     RECT  9.893 9.936 10.181 9.96 ;
     RECT  9.997 59.472 10.211 65.688 ;
     RECT  9.961 3.024 10.249 3.048 ;
     RECT  10.152 54.048 10.259 54.12 ;
     RECT  10.249 3.024 10.261 4.296 ;
     RECT  10.211 59.76 10.289 65.688 ;
     RECT  10.261 2.784 10.307 4.296 ;
     RECT  9.713 24.48 10.321 24.792 ;
     RECT  10.001 49.536 10.325 53.016 ;
     RECT  10.307 3.984 10.333 4.296 ;
     RECT  10.321 24.48 10.357 25.032 ;
     RECT  9.965 26.304 10.357 27.864 ;
     RECT  9.925 18.144 10.393 18.84 ;
     RECT  10.289 59.904 10.393 65.688 ;
     RECT  9.749 66.672 10.393 66.696 ;
     RECT  10.393 59.904 10.397 66.696 ;
     RECT  9.637 34.128 10.405 34.632 ;
     RECT  9.347 35.76 10.405 45.144 ;
     RECT  10.405 34.128 10.412 45.144 ;
     RECT  10.357 24.48 10.433 27.864 ;
     RECT  10.397 60.576 10.433 66.696 ;
     RECT  9.389 33.024 10.465 33.048 ;
     RECT  10.412 34.128 10.465 45.864 ;
     RECT  9.349 12.048 10.541 14.472 ;
     RECT  9.587 30.192 10.541 30.216 ;
     RECT  10.541 12.048 10.681 14.136 ;
     RECT  10.465 33.024 10.681 45.864 ;
     RECT  9.923 20.112 10.717 23.256 ;
     RECT  10.433 24.48 10.717 24.504 ;
     RECT  10.325 51.792 10.757 53.016 ;
     RECT  10.325 49.536 10.793 50.712 ;
     RECT  9.821 5.76 10.825 7.896 ;
     RECT  9.929 57.024 10.825 58.344 ;
     RECT  10.177 72 10.825 77.352 ;
     RECT  10.393 79.44 10.825 79.464 ;
     RECT  10.681 32.64 10.861 45.864 ;
     RECT  10.757 52.992 10.861 53.016 ;
     RECT  10.825 5.76 10.865 7.992 ;
     RECT  10.433 25.968 10.865 27.864 ;
     RECT  10.433 60.576 10.865 66.12 ;
     RECT  10.825 71.808 10.883 77.352 ;
     RECT  10.883 71.808 10.909 73.416 ;
     RECT  10.861 32.304 11.036 45.864 ;
     RECT  11.005 47.136 11.036 47.16 ;
     RECT  10.969 10.512 11.041 10.776 ;
     RECT  10.393 17.616 11.041 18.84 ;
     RECT  10.825 78.624 11.045 79.704 ;
     RECT  11.036 32.304 11.077 47.16 ;
     RECT  10.793 49.536 11.077 50.616 ;
     RECT  10.307 2.784 11.081 2.904 ;
     RECT  10.717 20.112 11.081 24.504 ;
     RECT  11.081 20.112 11.113 23.256 ;
     RECT  9.889 67.824 11.113 70.392 ;
     RECT  11.005 55.872 11.125 55.896 ;
     RECT  10.825 56.88 11.125 58.344 ;
     RECT  11.041 17.472 11.149 18.84 ;
     RECT  11.113 19.824 11.149 23.256 ;
     RECT  10.757 51.792 11.171 51.816 ;
     RECT  11.041 10.512 11.185 10.872 ;
     RECT  10.681 11.952 11.185 14.136 ;
     RECT  11.113 67.824 11.225 71.064 ;
     RECT  10.883 74.64 11.257 77.352 ;
     RECT  11.045 78.624 11.257 79.464 ;
     RECT  10.333 4.176 11.261 4.296 ;
     RECT  11.185 10.512 11.261 14.136 ;
     RECT  11.149 17.472 11.261 23.256 ;
     RECT  10.861 52.992 11.297 53.496 ;
     RECT  11.077 31.872 11.365 47.16 ;
     RECT  11.261 4.176 11.405 4.2 ;
     RECT  11.077 49.488 11.411 50.616 ;
     RECT  11.125 55.872 11.441 58.344 ;
     RECT  11.261 19.824 11.477 23.256 ;
     RECT  11.365 30.768 11.477 47.16 ;
     RECT  11.081 2.88 11.513 2.904 ;
     RECT  11.257 74.64 11.513 79.464 ;
     RECT  11.441 58.128 11.549 58.344 ;
     RECT  11.225 67.824 11.557 70.104 ;
     RECT  10.865 5.856 11.581 7.992 ;
     RECT  11.293 10.128 11.585 10.152 ;
     RECT  11.477 30.768 11.585 46.968 ;
     RECT  11.513 74.64 11.621 79.224 ;
     RECT  11.557 67.776 11.644 70.104 ;
     RECT  10.753 54.672 11.729 54.696 ;
     RECT  11.441 55.872 11.729 57.048 ;
     RECT  11.549 58.224 11.729 58.344 ;
     RECT  11.621 76.944 11.729 79.224 ;
     RECT  11.329 16.08 11.761 16.104 ;
     RECT  10.865 26.304 11.765 27.864 ;
     RECT  11.477 19.824 11.837 22.92 ;
     RECT  11.621 74.64 11.873 75.864 ;
     RECT  11.729 76.944 11.873 78.12 ;
     RECT  11.761 16.08 11.905 16.296 ;
     RECT  10.909 72.384 11.905 73.416 ;
     RECT  11.585 38.784 11.945 46.968 ;
     RECT  11.081 24.48 11.969 24.504 ;
     RECT  10.865 60.96 11.981 66.12 ;
     RECT  11.945 39.552 12.017 46.968 ;
     RECT  10.141 48.432 12.017 48.456 ;
     RECT  11.411 50.4 12.017 50.616 ;
     RECT  11.981 60.96 12.017 66.072 ;
     RECT  11.644 68.352 12.017 70.104 ;
     RECT  11.969 24.48 12.053 25.128 ;
     RECT  11.905 15.312 12.085 16.296 ;
     RECT  11.261 17.472 12.085 18.456 ;
     RECT  11.581 5.856 12.089 8.568 ;
     RECT  11.765 26.304 12.157 27.768 ;
     RECT  11.585 30.768 12.161 37.656 ;
     RECT  11.729 55.92 12.161 57.048 ;
     RECT  12.017 68.976 12.161 70.104 ;
     RECT  11.261 11.328 12.229 14.136 ;
     RECT  12.161 69.024 12.233 70.104 ;
     RECT  11.297 53.088 12.265 53.496 ;
     RECT  12.017 50.592 12.409 50.616 ;
     RECT  12.229 11.088 12.517 14.136 ;
     RECT  12.085 15.312 12.517 18.456 ;
     RECT  12.089 6.384 12.565 8.568 ;
     RECT  12.229 9.552 12.565 9.576 ;
     RECT  12.517 11.088 12.625 18.456 ;
     RECT  11.837 19.824 12.625 21 ;
     RECT  9.965 28.944 12.841 28.968 ;
     RECT  12.161 30.768 12.841 35.736 ;
     RECT  11.873 77.088 12.877 78.12 ;
     RECT  11.729 79.2 12.877 79.224 ;
     RECT  11.905 72.384 12.901 73.56 ;
     RECT  11.873 74.64 12.901 75.816 ;
     RECT  12.157 26.208 12.913 27.768 ;
     RECT  12.265 53.04 12.913 53.496 ;
     RECT  12.913 53.04 12.949 54.456 ;
     RECT  12.625 11.088 12.985 21 ;
     RECT  11.837 21.984 12.985 22.92 ;
     RECT  11.941 71.184 13.057 71.208 ;
     RECT  12.805 3.408 13.093 3.432 ;
     RECT  12.985 11.088 13.093 23.304 ;
     RECT  12.949 53.04 13.093 54.696 ;
     RECT  13.057 71.088 13.093 71.208 ;
     RECT  12.901 72.384 13.093 75.816 ;
     RECT  13.093 52.992 13.129 54.696 ;
     RECT  12.913 26.208 13.165 27.96 ;
     RECT  12.841 28.944 13.165 35.736 ;
     RECT  13.201 2.352 13.208 2.376 ;
     RECT  13.093 3.408 13.208 4.68 ;
     RECT  12.565 6.384 13.208 9.576 ;
     RECT  13.093 10.704 13.208 23.304 ;
     RECT  12.053 24.48 13.208 24.504 ;
     RECT  13.165 26.208 13.208 35.736 ;
     RECT  12.161 36.816 13.208 37.656 ;
     RECT  12.017 39.84 13.208 46.968 ;
     RECT  12.985 49.584 13.208 49.608 ;
     RECT  12.409 50.592 13.208 51.432 ;
     RECT  13.129 52.752 13.208 54.696 ;
     RECT  12.161 56.208 13.208 57.048 ;
     RECT  11.729 58.224 13.208 58.248 ;
     RECT  12.017 61.872 13.208 66.072 ;
     RECT  12.233 69.168 13.208 70.104 ;
     RECT  13.093 71.088 13.208 75.816 ;
     RECT  12.877 77.088 13.208 79.224 ;
     RECT  13.208 2.148 13.312 79.932 ;
     RECT  13.312 2.352 13.504 79.662 ;
     RECT  13.504 4.656 13.529 6.024 ;
     RECT  13.504 71.76 13.619 72.36 ;
     RECT  13.504 28.8 13.637 35.736 ;
     RECT  13.504 14.496 13.667 23.304 ;
     RECT  13.619 72.336 13.667 72.36 ;
     RECT  13.504 36.816 13.715 37.608 ;
     RECT  13.504 10.704 13.737 10.728 ;
     RECT  13.715 36.864 13.756 37.608 ;
     RECT  13.637 34.656 13.817 35.736 ;
     RECT  13.504 69.504 13.859 70.248 ;
     RECT  13.859 69.984 13.9 70.248 ;
     RECT  13.529 5.04 13.907 6.024 ;
     RECT  13.504 7.632 13.925 9.576 ;
     RECT  13.907 6 13.948 6.024 ;
     RECT  13.504 2.352 13.997 2.616 ;
     RECT  13.817 34.704 13.997 35.736 ;
     RECT  13.504 61.584 14.105 66.6 ;
     RECT  13.925 7.632 14.243 9.528 ;
     RECT  14.243 9.504 14.249 9.528 ;
     RECT  13.637 30.048 14.249 33.576 ;
     RECT  13.667 14.496 14.291 17.736 ;
     RECT  13.504 46.32 14.291 46.344 ;
     RECT  14.249 30.048 14.393 30.12 ;
     RECT  14.249 31.296 14.393 33.576 ;
     RECT  13.756 36.864 14.393 37.224 ;
     RECT  14.243 7.632 14.429 8.52 ;
     RECT  14.105 61.584 14.429 64.92 ;
     RECT  13.504 39.168 14.533 39.192 ;
     RECT  13.504 58.656 14.533 59.256 ;
     RECT  13.504 60.48 14.533 60.504 ;
     RECT  14.393 30.048 14.537 30.072 ;
     RECT  13.997 34.944 14.537 35.736 ;
     RECT  13.637 28.8 14.569 29.016 ;
     RECT  14.105 66.048 14.605 66.6 ;
     RECT  13.504 67.728 14.605 68.376 ;
     RECT  14.533 39.168 14.609 39.768 ;
     RECT  13.667 19.344 14.641 23.304 ;
     RECT  14.429 7.632 14.645 7.992 ;
     RECT  14.641 19.296 14.645 23.304 ;
     RECT  14.393 31.296 14.645 32.568 ;
     RECT  13.504 48.384 14.677 57.144 ;
     RECT  14.677 47.568 14.681 57.144 ;
     RECT  14.645 19.296 14.705 21.288 ;
     RECT  13.504 79.2 14.713 79.224 ;
     RECT  14.537 34.944 14.717 35.592 ;
     RECT  14.291 15.408 14.725 17.736 ;
     RECT  14.705 18.768 14.725 21.288 ;
     RECT  13.504 40.848 14.785 44.136 ;
     RECT  14.725 15.408 14.789 21.288 ;
     RECT  14.605 66.048 14.821 68.376 ;
     RECT  14.393 37.152 14.825 37.224 ;
     RECT  14.681 47.568 14.857 55.608 ;
     RECT  14.789 15.408 14.861 18.024 ;
     RECT  13.504 77.136 14.869 77.16 ;
     RECT  14.713 79.2 14.869 79.8 ;
     RECT  14.569 28.56 14.893 29.016 ;
     RECT  14.825 37.152 14.897 37.176 ;
     RECT  14.681 56.976 14.897 57.144 ;
     RECT  14.869 77.136 14.915 79.8 ;
     RECT  14.857 47.328 14.933 55.608 ;
     RECT  14.821 66.048 14.933 68.808 ;
     RECT  14.915 77.136 14.956 78.36 ;
     RECT  14.861 16.08 14.969 18.024 ;
     RECT  14.956 77.136 14.997 77.16 ;
     RECT  13.504 74.592 15.004 75.432 ;
     RECT  14.645 7.632 15.005 7.656 ;
     RECT  13.504 26.208 15.037 27.192 ;
     RECT  14.893 28.56 15.037 29.688 ;
     RECT  13.504 12.768 15.041 13.128 ;
     RECT  14.969 16.08 15.077 16.536 ;
     RECT  14.969 17.712 15.077 18.024 ;
     RECT  14.917 72.816 15.077 72.84 ;
     RECT  15.037 26.208 15.109 27.384 ;
     RECT  15.037 28.416 15.109 29.688 ;
     RECT  14.965 38.448 15.113 38.472 ;
     RECT  14.915 79.344 15.149 79.8 ;
     RECT  15.041 13.104 15.185 13.128 ;
     RECT  14.645 22.32 15.217 23.304 ;
     RECT  13.504 24.48 15.217 24.648 ;
     RECT  14.533 58.656 15.253 60.504 ;
     RECT  15.077 16.416 15.293 16.536 ;
     RECT  15.149 79.344 15.293 79.656 ;
     RECT  15.109 26.208 15.356 29.688 ;
     RECT  15.217 22.32 15.361 24.648 ;
     RECT  15.004 75.264 15.401 75.432 ;
     RECT  14.393 33.552 15.433 33.576 ;
     RECT  15.361 34.56 15.433 34.584 ;
     RECT  15.253 58.128 15.433 60.504 ;
     RECT  15.433 58.128 15.469 61.032 ;
     RECT  14.429 62.16 15.469 64.92 ;
     RECT  14.933 66.048 15.473 68.424 ;
     RECT  13.997 2.352 15.509 2.376 ;
     RECT  15.293 16.512 15.509 16.536 ;
     RECT  14.645 31.776 15.509 32.568 ;
     RECT  15.356 26.112 15.541 29.688 ;
     RECT  15.109 46.128 15.541 46.152 ;
     RECT  15.473 66.048 15.545 68.376 ;
     RECT  15.361 22.32 15.581 24.744 ;
     RECT  15.545 67.728 15.581 68.376 ;
     RECT  13.9 69.984 15.617 70.008 ;
     RECT  15.401 75.264 15.617 75.288 ;
     RECT  14.789 19.104 15.685 21.288 ;
     RECT  15.581 22.32 15.685 23.016 ;
     RECT  14.785 40.848 15.757 44.232 ;
     RECT  15.541 45.456 15.757 46.152 ;
     RECT  15.541 3.408 15.829 3.432 ;
     RECT  15.469 58.128 15.941 64.92 ;
     RECT  15.293 79.344 15.941 79.56 ;
     RECT  15.581 24.72 15.973 24.744 ;
     RECT  15.757 40.848 16.009 46.152 ;
     RECT  14.933 47.328 16.009 53.88 ;
     RECT  15.433 33.552 16.013 34.584 ;
     RECT  15.545 66.048 16.013 66.6 ;
     RECT  15.941 62.448 16.021 64.92 ;
     RECT  16.013 66.048 16.021 66.264 ;
     RECT  16.009 11.664 16.045 11.688 ;
     RECT  15.941 58.128 16.049 61.368 ;
     RECT  14.956 78.336 16.049 78.36 ;
     RECT  16.009 10.608 16.081 10.632 ;
     RECT  16.045 11.664 16.081 11.784 ;
     RECT  16.049 58.656 16.157 61.368 ;
     RECT  15.941 79.488 16.157 79.56 ;
     RECT  16.009 40.848 16.265 53.88 ;
     RECT  16.153 72.912 16.265 72.936 ;
     RECT  15.541 26.112 16.301 30.024 ;
     RECT  14.609 39.744 16.301 39.768 ;
     RECT  16.265 40.848 16.301 48.84 ;
     RECT  16.013 33.6 16.337 34.584 ;
     RECT  16.021 62.448 16.337 66.264 ;
     RECT  15.973 24.72 16.369 25.128 ;
     RECT  16.301 26.112 16.369 28.824 ;
     RECT  16.265 49.824 16.369 53.88 ;
     RECT  16.337 34.176 16.477 34.584 ;
     RECT  14.717 35.568 16.477 35.592 ;
     RECT  16.369 38.784 16.481 39.624 ;
     RECT  16.369 49.824 16.517 54.12 ;
     RECT  16.301 45.984 16.547 48.84 ;
     RECT  15.829 3.264 16.553 3.432 ;
     RECT  16.553 3.264 16.589 3.288 ;
     RECT  16.481 39.024 16.589 39.624 ;
     RECT  15.581 68.352 16.589 68.376 ;
     RECT  14.897 56.976 16.621 57 ;
     RECT  15.509 32.304 16.625 32.568 ;
     RECT  16.547 45.984 16.625 48.312 ;
     RECT  16.369 24.72 16.661 28.824 ;
     RECT  16.621 56.928 16.693 57 ;
     RECT  15.685 19.104 16.741 23.016 ;
     RECT  16.661 24.72 16.741 25.512 ;
     RECT  16.549 37.104 16.805 37.128 ;
     RECT  16.741 24.288 16.828 25.512 ;
     RECT  15.901 15.168 16.837 15.192 ;
     RECT  14.933 55.584 16.837 55.608 ;
     RECT  16.625 47.616 16.841 48.312 ;
     RECT  16.337 62.832 16.877 66.264 ;
     RECT  16.157 61.344 16.909 61.368 ;
     RECT  16.157 58.656 16.913 60.168 ;
     RECT  16.661 26.544 16.949 28.824 ;
     RECT  15.829 77.088 16.949 77.112 ;
     RECT  16.625 32.304 16.981 32.472 ;
     RECT  16.693 56.88 16.981 57 ;
     RECT  16.741 19.104 17.017 23.16 ;
     RECT  16.981 56.88 17.021 57.048 ;
     RECT  15.649 70.512 17.021 70.536 ;
     RECT  16.081 10.608 17.053 11.784 ;
     RECT  17.021 56.928 17.053 57.048 ;
     RECT  17.053 10.608 17.089 12.072 ;
     RECT  16.981 32.256 17.093 32.472 ;
     RECT  16.945 78.24 17.093 78.264 ;
     RECT  16.837 15.168 17.161 15.72 ;
     RECT  16.909 61.344 17.161 61.704 ;
     RECT  16.117 7.776 17.165 7.8 ;
     RECT  16.949 26.544 17.165 28.584 ;
     RECT  17.165 28.368 17.237 28.584 ;
     RECT  16.913 58.656 17.237 59.64 ;
     RECT  16.301 30 17.273 30.024 ;
     RECT  15.077 17.76 17.345 17.784 ;
     RECT  16.589 39.024 17.345 39.576 ;
     RECT  16.517 49.824 17.345 52.776 ;
     RECT  17.017 18.96 17.377 23.16 ;
     RECT  17.093 32.448 17.381 32.472 ;
     RECT  17.089 10.08 17.413 12.072 ;
     RECT  16.477 34.176 17.413 35.592 ;
     RECT  17.053 36.816 17.413 36.888 ;
     RECT  17.345 39.024 17.417 39.048 ;
     RECT  17.161 14.928 17.42 15.72 ;
     RECT  17.053 56.928 17.453 57.624 ;
     RECT  16.837 55.584 17.485 55.8 ;
     RECT  17.42 14.928 17.507 16.008 ;
     RECT  17.413 34.176 17.561 36.888 ;
     RECT  16.157 79.536 17.593 79.56 ;
     RECT  16.625 45.984 17.603 46.536 ;
     RECT  17.345 51.936 17.701 52.776 ;
     RECT  16.517 53.76 17.701 54.12 ;
     RECT  17.377 30.576 17.737 30.84 ;
     RECT  17.593 79.44 17.809 79.56 ;
     RECT  17.413 9.792 17.845 12.072 ;
     RECT  16.828 24.72 17.845 25.512 ;
     RECT  17.165 26.544 17.845 27.192 ;
     RECT  16.301 40.848 17.917 44.904 ;
     RECT  17.809 79.44 17.953 79.656 ;
     RECT  17.593 74.448 17.989 74.472 ;
     RECT  17.345 49.824 18.061 50.952 ;
     RECT  16.877 62.832 18.169 65.496 ;
     RECT  17.603 46.128 18.277 46.536 ;
     RECT  17.701 51.936 18.277 54.12 ;
     RECT  17.485 55.44 18.277 55.8 ;
     RECT  17.737 30.576 18.313 30.936 ;
     RECT  17.953 79.248 18.385 79.656 ;
     RECT  16.841 47.616 18.421 47.64 ;
     RECT  18.061 49.056 18.421 50.952 ;
     RECT  18.277 46.128 18.457 46.584 ;
     RECT  18.421 47.616 18.457 50.952 ;
     RECT  17.507 14.928 18.469 14.952 ;
     RECT  17.377 18.96 18.469 23.736 ;
     RECT  18.457 46.128 18.469 50.952 ;
     RECT  18.277 51.936 18.469 55.8 ;
     RECT  17.845 24.72 18.493 27.192 ;
     RECT  17.237 28.368 18.493 28.392 ;
     RECT  18.493 3.84 18.608 3.864 ;
     RECT  17.593 8.448 18.608 8.472 ;
     RECT  17.845 9.792 18.608 12.6 ;
     RECT  17.629 13.68 18.608 13.704 ;
     RECT  18.469 14.784 18.608 14.952 ;
     RECT  17.485 17.088 18.608 17.112 ;
     RECT  18.469 18.432 18.608 23.736 ;
     RECT  18.493 24.72 18.608 28.488 ;
     RECT  18.313 30.144 18.608 30.936 ;
     RECT  17.561 34.176 18.608 36.84 ;
     RECT  18.161 38.784 18.608 38.808 ;
     RECT  17.917 40.848 18.608 45.144 ;
     RECT  18.469 46.128 18.608 55.8 ;
     RECT  17.453 56.928 18.608 57.048 ;
     RECT  17.237 58.656 18.608 58.728 ;
     RECT  17.161 60.72 18.608 61.704 ;
     RECT  18.169 62.688 18.608 65.496 ;
     RECT  18.493 66.576 18.608 66.6 ;
     RECT  17.269 67.776 18.608 67.8 ;
     RECT  17.233 72.432 18.608 72.456 ;
     RECT  17.989 74.448 18.608 74.568 ;
     RECT  18.385 79.248 18.608 79.752 ;
     RECT  18.608 2.148 18.712 79.932 ;
     RECT  18.712 2.304 18.785 79.752 ;
     RECT  18.785 2.418 18.857 79.752 ;
     RECT  18.857 2.418 18.904 79.662 ;
     RECT  18.904 14.928 18.965 15.384 ;
     RECT  18.904 51.12 19.001 55.848 ;
     RECT  19.001 51.216 19.043 55.848 ;
     RECT  18.904 46.512 19.109 50.04 ;
     RECT  18.904 70.032 19.109 70.056 ;
     RECT  19.109 47.616 19.181 50.04 ;
     RECT  18.904 61.392 19.217 62.616 ;
     RECT  18.904 5.76 19.253 6.024 ;
     RECT  19.253 5.904 19.289 6.024 ;
     RECT  18.904 19.584 19.289 23.976 ;
     RECT  19.289 6 19.325 6.024 ;
     RECT  18.904 13.68 19.325 13.704 ;
     RECT  18.904 2.88 19.433 4.776 ;
     RECT  18.904 30.144 19.505 30.888 ;
     RECT  19.043 51.888 19.505 55.848 ;
     RECT  19.505 51.888 19.577 54.696 ;
     RECT  19.433 3.408 19.649 4.776 ;
     RECT  18.904 79.44 19.649 79.56 ;
     RECT  19.109 46.512 19.667 46.536 ;
     RECT  19.577 51.888 19.685 53.064 ;
     RECT  18.904 9.168 19.757 12.6 ;
     RECT  18.904 38.688 19.763 39.912 ;
     RECT  18.904 34.704 19.793 35.736 ;
     RECT  19.757 9.168 19.829 12.36 ;
     RECT  18.904 57.456 19.859 58.824 ;
     RECT  18.904 17.088 19.865 18.456 ;
     RECT  19.685 51.888 19.865 52.968 ;
     RECT  18.904 76.32 19.865 76.344 ;
     RECT  18.904 77.712 19.865 77.736 ;
     RECT  18.904 29.088 19.873 29.112 ;
     RECT  19.577 54.096 19.873 54.696 ;
     RECT  19.505 30.432 19.901 30.888 ;
     RECT  19.649 3.408 19.937 3.624 ;
     RECT  18.904 41.136 19.969 45.528 ;
     RECT  19.865 51.888 19.973 51.912 ;
     RECT  19.865 52.944 19.973 52.968 ;
     RECT  19.829 9.168 20.009 9.816 ;
     RECT  19.829 10.896 20.045 12.36 ;
     RECT  19.763 38.784 20.045 39.912 ;
     RECT  19.505 55.824 20.045 55.848 ;
     RECT  20.045 38.784 20.081 39.336 ;
     RECT  19.289 20.544 20.117 23.976 ;
     RECT  20.117 20.688 20.149 23.976 ;
     RECT  18.904 25.248 20.149 27.72 ;
     RECT  19.937 3.408 20.153 3.432 ;
     RECT  20.149 20.688 20.189 27.72 ;
     RECT  19.181 47.616 20.189 47.64 ;
     RECT  18.904 72.432 20.189 73.752 ;
     RECT  20.009 9.168 20.221 9.192 ;
     RECT  20.189 25.824 20.261 27.72 ;
     RECT  19.901 30.576 20.261 30.888 ;
     RECT  18.904 63.6 20.261 66.12 ;
     RECT  20.261 63.6 20.297 65.4 ;
     RECT  19.969 41.136 20.329 45.816 ;
     RECT  19.865 17.616 20.365 18.456 ;
     RECT  19.217 61.44 20.365 62.616 ;
     RECT  19.969 70.704 20.365 70.728 ;
     RECT  19.649 79.44 20.401 79.464 ;
     RECT  18.965 15.36 20.437 15.384 ;
     RECT  19.649 4.752 20.477 4.776 ;
     RECT  20.437 14.832 20.477 15.384 ;
     RECT  20.329 40.992 20.477 45.816 ;
     RECT  19.859 57.456 20.509 57.576 ;
     RECT  20.221 9.12 20.545 9.192 ;
     RECT  19.793 34.8 20.549 35.736 ;
     RECT  20.365 61.008 20.549 62.616 ;
     RECT  20.545 8.208 20.585 9.192 ;
     RECT  20.401 79.2 20.617 79.464 ;
     RECT  20.261 25.824 20.693 26.616 ;
     RECT  19.181 49.488 20.725 50.04 ;
     RECT  20.585 8.208 20.801 8.232 ;
     RECT  20.045 10.896 20.801 11.4 ;
     RECT  20.549 61.008 20.801 61.56 ;
     RECT  20.189 20.688 20.837 24.36 ;
     RECT  20.549 34.896 20.837 35.736 ;
     RECT  19.873 54.096 20.837 54.12 ;
     RECT  20.221 67.248 20.837 67.272 ;
     RECT  20.837 20.688 20.873 23.928 ;
     RECT  20.477 40.992 20.909 44.904 ;
     RECT  20.873 21.792 20.981 23.928 ;
     RECT  20.365 70.608 21.049 70.728 ;
     RECT  20.477 14.832 21.053 14.856 ;
     RECT  20.365 17.616 21.085 18.792 ;
     RECT  20.837 34.896 21.089 34.92 ;
     RECT  20.869 4.8 21.121 4.824 ;
     RECT  20.261 27.696 21.125 27.72 ;
     RECT  20.261 30.576 21.125 30.6 ;
     RECT  20.801 10.896 21.161 10.92 ;
     RECT  20.909 40.992 21.161 44.232 ;
     RECT  21.121 4.8 21.197 5.352 ;
     RECT  20.725 49.008 21.205 50.04 ;
     RECT  21.197 5.328 21.233 5.352 ;
     RECT  20.189 72.912 21.233 73.752 ;
     RECT  21.085 17.232 21.269 18.792 ;
     RECT  21.205 49.008 21.269 50.76 ;
     RECT  20.509 56.736 21.337 57.576 ;
     RECT  20.549 62.592 21.337 62.616 ;
     RECT  20.297 63.6 21.337 64.92 ;
     RECT  21.269 50.016 21.341 50.76 ;
     RECT  19.859 58.656 21.341 58.824 ;
     RECT  21.341 58.8 21.409 58.824 ;
     RECT  18.904 68.784 21.445 68.808 ;
     RECT  21.337 62.592 21.485 64.92 ;
     RECT  21.301 39.504 21.553 39.528 ;
     RECT  21.049 70.608 21.557 71.256 ;
     RECT  21.557 71.04 21.589 71.256 ;
     RECT  21.233 72.912 21.589 73.368 ;
     RECT  20.617 79.152 21.589 79.464 ;
     RECT  21.269 18.096 21.593 18.792 ;
     RECT  21.337 54.144 21.635 54.168 ;
     RECT  21.341 50.016 21.693 50.712 ;
     RECT  20.437 2.736 21.701 2.904 ;
     RECT  20.693 26.592 21.733 26.616 ;
     RECT  21.049 47.856 21.737 47.88 ;
     RECT  21.725 33.264 21.769 33.288 ;
     RECT  21.445 68.784 21.769 69.048 ;
     RECT  20.977 46.128 21.809 46.152 ;
     RECT  21.733 30.192 21.817 30.216 ;
     RECT  21.589 71.04 21.845 73.368 ;
     RECT  21.845 71.04 21.881 71.064 ;
     RECT  20.981 21.84 21.917 23.928 ;
     RECT  21.485 62.592 22.021 62.76 ;
     RECT  21.701 2.736 22.025 2.808 ;
     RECT  20.873 20.688 22.057 20.76 ;
     RECT  21.917 21.84 22.057 23.64 ;
     RECT  21.409 58.8 22.057 59.496 ;
     RECT  21.733 26.592 22.201 26.664 ;
     RECT  21.769 33.264 22.205 33.864 ;
     RECT  22.193 27.888 22.213 27.912 ;
     RECT  22.093 11.184 22.237 11.208 ;
     RECT  21.161 41.136 22.237 44.232 ;
     RECT  21.625 5.424 22.277 5.448 ;
     RECT  22.021 52.224 22.277 52.248 ;
     RECT  21.337 56.352 22.277 57.576 ;
     RECT  22.057 58.8 22.309 60.408 ;
     RECT  20.801 61.44 22.309 61.56 ;
     RECT  22.021 62.544 22.309 62.76 ;
     RECT  21.445 25.248 22.345 25.272 ;
     RECT  22.201 26.256 22.345 26.664 ;
     RECT  22.025 2.736 22.349 2.76 ;
     RECT  21.845 72.192 22.349 73.368 ;
     RECT  21.553 39.504 22.421 39.816 ;
     RECT  22.237 19.392 22.46 19.416 ;
     RECT  22.057 20.688 22.46 23.64 ;
     RECT  22.309 58.8 22.529 62.76 ;
     RECT  22.46 19.392 22.547 23.64 ;
     RECT  22.489 5.232 22.597 5.256 ;
     RECT  22.165 54.096 22.601 54.12 ;
     RECT  22.529 60.288 22.633 62.76 ;
     RECT  21.485 64.176 22.633 64.92 ;
     RECT  22.597 5.136 22.745 5.256 ;
     RECT  22.237 11.184 22.745 11.256 ;
     RECT  22.213 27.888 22.745 28.152 ;
     RECT  22.345 25.248 22.777 26.664 ;
     RECT  22.745 27.888 22.777 28.008 ;
     RECT  22.633 60.288 22.777 64.92 ;
     RECT  21.913 66.48 22.777 66.504 ;
     RECT  22.777 25.248 22.889 28.008 ;
     RECT  21.693 50.688 22.889 50.712 ;
     RECT  22.349 72.816 22.889 73.368 ;
     RECT  22.237 40.848 22.921 44.232 ;
     RECT  21.121 75.696 22.993 75.72 ;
     RECT  22.988 47.28 23.029 47.304 ;
     RECT  21.593 18.096 23.101 18.12 ;
     RECT  22.993 75.6 23.137 75.72 ;
     RECT  21.769 68.736 23.281 69.048 ;
     RECT  22.547 20.688 23.317 23.64 ;
     RECT  22.529 58.8 23.353 58.824 ;
     RECT  22.921 40.848 23.425 44.472 ;
     RECT  22.669 45.696 23.425 45.72 ;
     RECT  23.137 75.6 23.425 76.248 ;
     RECT  22.777 60.288 23.497 66.504 ;
     RECT  22.921 3.936 23.557 3.96 ;
     RECT  23.101 17.856 23.564 18.12 ;
     RECT  23.557 3.168 23.569 3.96 ;
     RECT  22.547 19.392 23.605 19.416 ;
     RECT  23.317 20.688 23.605 24.024 ;
     RECT  23.564 17.856 23.641 18.168 ;
     RECT  22.277 56.496 23.641 57.576 ;
     RECT  23.353 58.656 23.641 58.824 ;
     RECT  23.497 59.808 23.677 66.504 ;
     RECT  23.425 74.976 23.677 76.248 ;
     RECT  22.597 14.208 23.785 14.232 ;
     RECT  22.705 15.408 23.785 15.432 ;
     RECT  23.209 54.672 23.785 54.696 ;
     RECT  22.889 25.248 23.821 25.272 ;
     RECT  23.281 68.16 23.821 69.048 ;
     RECT  22.957 70.368 23.821 70.392 ;
     RECT  23.461 5.664 23.893 5.688 ;
     RECT  23.677 74.688 23.929 76.248 ;
     RECT  23.641 7.968 23.965 7.992 ;
     RECT  23.569 2.592 24.008 3.96 ;
     RECT  23.893 5.568 24.008 5.688 ;
     RECT  23.965 7.2 24.008 7.992 ;
     RECT  23.857 9.888 24.008 9.912 ;
     RECT  23.461 11.952 24.008 11.976 ;
     RECT  22.381 13.008 24.008 13.032 ;
     RECT  23.785 14.208 24.008 15.864 ;
     RECT  23.641 17.136 24.008 18.168 ;
     RECT  23.605 19.392 24.008 24.024 ;
     RECT  23.821 25.2 24.008 25.272 ;
     RECT  22.889 26.592 24.008 28.008 ;
     RECT  22.741 32.352 24.008 32.376 ;
     RECT  22.205 33.84 24.008 33.864 ;
     RECT  22.421 39.792 24.008 39.816 ;
     RECT  23.425 40.848 24.008 45.72 ;
     RECT  23.029 46.8 24.008 47.304 ;
     RECT  23.029 51.12 24.008 51.912 ;
     RECT  23.785 54.624 24.008 54.696 ;
     RECT  23.641 56.496 24.008 58.824 ;
     RECT  23.677 59.808 24.008 66.888 ;
     RECT  23.821 68.16 24.008 70.392 ;
     RECT  22.889 72.816 24.008 72.84 ;
     RECT  23.929 74.64 24.008 76.248 ;
     RECT  23.101 77.568 24.008 77.592 ;
     RECT  21.589 78.96 24.008 79.464 ;
     RECT  24.008 2.148 24.112 79.932 ;
     RECT  24.112 2.418 24.304 79.662 ;
     RECT  24.304 54.624 24.329 54.696 ;
     RECT  24.304 5.568 24.419 7.992 ;
     RECT  24.304 59.808 24.473 70.056 ;
     RECT  24.473 59.904 24.515 70.056 ;
     RECT  24.419 5.568 24.545 6.552 ;
     RECT  24.304 56.208 24.545 58.824 ;
     RECT  24.304 74.64 24.545 75.096 ;
     RECT  24.304 9.888 24.581 10.92 ;
     RECT  24.515 66.672 24.581 70.056 ;
     RECT  24.304 40.272 24.617 44.952 ;
     RECT  24.304 14.832 24.653 18.792 ;
     RECT  24.419 7.968 24.725 7.992 ;
     RECT  24.581 67.824 24.761 70.056 ;
     RECT  24.304 2.592 24.797 2.616 ;
     RECT  24.304 19.776 24.797 23.736 ;
     RECT  24.761 67.824 24.833 69 ;
     RECT  24.653 15.936 24.905 18.792 ;
     RECT  24.515 59.904 24.905 65.4 ;
     RECT  24.905 60.336 25.049 65.4 ;
     RECT  24.797 19.776 25.085 21.096 ;
     RECT  24.304 50.304 25.091 51.624 ;
     RECT  24.581 10.704 25.121 10.92 ;
     RECT  24.905 15.984 25.121 18.792 ;
     RECT  24.329 54.624 25.121 54.648 ;
     RECT  25.121 10.704 25.157 10.728 ;
     RECT  24.304 73.248 25.193 73.272 ;
     RECT  24.304 4.56 25.229 4.584 ;
     RECT  24.797 22.224 25.297 23.736 ;
     RECT  24.653 14.832 25.337 14.856 ;
     RECT  24.304 30.144 25.337 30.888 ;
     RECT  25.121 17.088 25.373 18.792 ;
     RECT  24.304 46.8 25.379 46.824 ;
     RECT  25.337 30.192 25.405 30.888 ;
     RECT  24.304 31.92 25.405 31.944 ;
     RECT  24.304 25.008 25.409 28.968 ;
     RECT  25.049 60.336 25.409 63.288 ;
     RECT  24.304 35.952 25.441 35.976 ;
     RECT  24.304 38.688 25.445 38.712 ;
     RECT  25.373 17.088 25.517 18.216 ;
     RECT  24.304 33.84 25.517 34.632 ;
     RECT  25.085 19.776 25.549 20.856 ;
     RECT  24.833 67.824 25.553 68.952 ;
     RECT  25.405 30.192 25.585 31.944 ;
     RECT  24.581 66.672 25.585 66.744 ;
     RECT  25.553 67.824 25.585 68.664 ;
     RECT  24.304 13.44 25.621 13.464 ;
     RECT  24.304 79.584 25.621 79.608 ;
     RECT  25.549 19.344 25.661 20.856 ;
     RECT  25.549 9.792 25.693 9.816 ;
     RECT  25.693 8.832 25.765 9.816 ;
     RECT  25.661 19.776 25.769 20.856 ;
     RECT  25.409 60.336 25.769 62.904 ;
     RECT  24.545 56.208 25.837 56.232 ;
     RECT  24.761 70.032 25.841 70.056 ;
     RECT  25.765 8.544 25.873 9.816 ;
     RECT  25.405 37.488 25.877 37.512 ;
     RECT  25.585 66.672 25.877 68.664 ;
     RECT  25.621 79.248 25.877 79.608 ;
     RECT  25.837 56.016 25.909 56.232 ;
     RECT  24.545 57.264 25.909 58.824 ;
     RECT  25.409 25.008 25.985 25.032 ;
     RECT  25.769 60.336 25.985 62.664 ;
     RECT  24.545 6.528 26.053 6.552 ;
     RECT  25.297 22.224 26.053 23.832 ;
     RECT  25.405 4.416 26.089 4.44 ;
     RECT  25.409 26.208 26.093 28.968 ;
     RECT  24.545 75.072 26.093 75.096 ;
     RECT  25.877 66.672 26.125 66.84 ;
     RECT  25.049 64.416 26.129 65.4 ;
     RECT  25.121 15.984 26.161 16.008 ;
     RECT  25.517 17.088 26.161 17.112 ;
     RECT  24.617 40.272 26.165 44.904 ;
     RECT  26.125 66.432 26.165 66.84 ;
     RECT  26.089 3.984 26.197 4.44 ;
     RECT  26.165 40.656 26.197 44.904 ;
     RECT  26.017 48.72 26.197 48.744 ;
     RECT  26.161 15.984 26.201 17.112 ;
     RECT  25.909 56.016 26.237 58.824 ;
     RECT  25.873 7.872 26.269 9.816 ;
     RECT  25.985 60.336 26.273 62.616 ;
     RECT  26.053 5.568 26.305 6.552 ;
     RECT  26.269 7.872 26.305 10.728 ;
     RECT  25.441 35.952 26.309 36.312 ;
     RECT  25.585 30.192 26.381 31.992 ;
     RECT  26.197 40.656 26.381 44.952 ;
     RECT  26.305 5.568 26.417 10.728 ;
     RECT  26.197 3.648 26.485 4.44 ;
     RECT  26.053 22.08 26.485 23.832 ;
     RECT  26.161 47.088 26.485 47.112 ;
     RECT  26.197 48.24 26.485 48.744 ;
     RECT  26.485 14.976 26.593 15 ;
     RECT  25.517 33.84 26.593 33.864 ;
     RECT  26.485 47.088 26.593 48.744 ;
     RECT  26.093 26.592 26.597 28.968 ;
     RECT  26.381 40.848 26.627 44.952 ;
     RECT  26.417 5.616 26.629 10.728 ;
     RECT  25.297 12 26.629 12.024 ;
     RECT  25.621 13.056 26.629 13.464 ;
     RECT  26.593 47.04 26.665 48.744 ;
     RECT  26.129 64.416 26.665 64.872 ;
     RECT  26.665 63.696 26.669 64.872 ;
     RECT  26.629 5.616 26.677 13.464 ;
     RECT  26.593 14.784 26.677 15 ;
     RECT  26.677 5.616 26.705 15 ;
     RECT  26.273 60.96 26.705 62.616 ;
     RECT  26.705 7.584 26.723 15 ;
     RECT  26.237 57.168 26.773 58.824 ;
     RECT  26.723 7.584 26.777 12.024 ;
     RECT  26.201 16.272 26.809 17.112 ;
     RECT  26.485 2.832 26.813 4.44 ;
     RECT  26.597 28.944 26.885 28.968 ;
     RECT  26.593 33.264 26.921 33.864 ;
     RECT  26.705 61.008 26.921 62.616 ;
     RECT  26.557 36.576 26.957 36.888 ;
     RECT  26.957 36.624 27.029 36.888 ;
     RECT  26.777 7.584 27.101 11.304 ;
     RECT  26.485 22.08 27.101 24.648 ;
     RECT  26.921 61.008 27.101 61.128 ;
     RECT  25.877 68.16 27.133 68.664 ;
     RECT  26.125 69.696 27.133 69.72 ;
     RECT  26.669 63.696 27.137 63.816 ;
     RECT  26.809 16.272 27.164 17.16 ;
     RECT  26.381 30.192 27.169 31.848 ;
     RECT  26.627 41.136 27.205 44.952 ;
     RECT  27.164 74.976 27.205 75 ;
     RECT  26.161 76.368 27.205 76.392 ;
     RECT  27.205 74.976 27.241 76.392 ;
     RECT  27.164 16.272 27.251 17.64 ;
     RECT  27.241 74.976 27.251 76.872 ;
     RECT  26.165 66.432 27.253 66.696 ;
     RECT  26.813 4.368 27.277 4.44 ;
     RECT  26.597 26.592 27.277 27.912 ;
     RECT  27.101 7.584 27.299 10.536 ;
     RECT  26.723 13.056 27.299 15 ;
     RECT  27.253 66.096 27.308 66.696 ;
     RECT  25.769 19.92 27.313 20.856 ;
     RECT  27.101 22.08 27.313 23.736 ;
     RECT  27.277 26.4 27.313 27.912 ;
     RECT  25.909 52.704 27.313 52.728 ;
     RECT  27.308 65.856 27.313 66.696 ;
     RECT  27.133 68.16 27.313 69.72 ;
     RECT  27.251 75.744 27.313 76.872 ;
     RECT  27.251 16.272 27.317 17.16 ;
     RECT  27.313 25.824 27.353 27.912 ;
     RECT  27.299 13.056 27.389 13.08 ;
     RECT  26.665 39.6 27.389 39.624 ;
     RECT  27.313 75.744 27.421 76.92 ;
     RECT  27.169 29.808 27.425 31.848 ;
     RECT  27.317 17.136 27.461 17.16 ;
     RECT  27.029 36.624 27.461 36.648 ;
     RECT  26.705 5.616 27.497 6.6 ;
     RECT  27.299 14.208 27.497 15 ;
     RECT  27.313 65.856 27.529 69.72 ;
     RECT  27.241 71.088 27.529 71.112 ;
     RECT  27.299 7.584 27.533 10.44 ;
     RECT  27.425 30.864 27.569 31.848 ;
     RECT  26.665 46.32 27.601 48.744 ;
     RECT  27.205 18.816 27.637 18.84 ;
     RECT  27.313 19.92 27.637 23.736 ;
     RECT  27.277 4.368 27.673 4.632 ;
     RECT  27.497 5.616 27.673 6.552 ;
     RECT  27.205 41.136 27.677 45.144 ;
     RECT  27.529 65.856 27.677 71.112 ;
     RECT  27.313 52.704 27.745 53.544 ;
     RECT  26.773 57.168 27.745 59.064 ;
     RECT  27.137 63.792 27.749 63.816 ;
     RECT  27.745 51.936 27.785 53.544 ;
     RECT  26.813 2.832 27.817 3.096 ;
     RECT  27.673 4.368 27.817 6.552 ;
     RECT  27.533 7.584 27.821 9.144 ;
     RECT  27.569 30.96 27.853 31.848 ;
     RECT  27.745 57.168 27.853 59.4 ;
     RECT  27.101 61.008 27.853 61.032 ;
     RECT  26.921 62.112 27.889 62.616 ;
     RECT  27.821 7.872 27.893 9.144 ;
     RECT  27.677 67.536 27.929 71.112 ;
     RECT  25.877 79.248 27.961 79.272 ;
     RECT  27.817 2.832 27.965 6.552 ;
     RECT  27.929 68.88 27.965 71.112 ;
     RECT  27.965 68.928 27.971 71.112 ;
     RECT  27.637 18.816 28.001 23.736 ;
     RECT  27.971 69.456 28.012 71.112 ;
     RECT  28.001 18.816 28.037 23.688 ;
     RECT  27.601 46.32 28.037 48.984 ;
     RECT  27.785 51.936 28.073 52.728 ;
     RECT  26.237 56.016 28.109 56.04 ;
     RECT  27.889 62.112 28.109 62.664 ;
     RECT  27.929 67.536 28.145 67.56 ;
     RECT  28.012 71.088 28.177 71.112 ;
     RECT  28.037 19.632 28.253 23.688 ;
     RECT  28.253 21.696 28.289 23.688 ;
     RECT  28.037 46.32 28.321 48.792 ;
     RECT  28.177 71.088 28.321 71.64 ;
     RECT  27.853 72.96 28.321 72.984 ;
     RECT  28.321 71.088 28.393 72.984 ;
     RECT  27.893 8.592 28.397 9.144 ;
     RECT  27.353 25.824 28.429 27.72 ;
     RECT  26.669 64.848 28.429 64.872 ;
     RECT  27.677 65.856 28.429 66.456 ;
     RECT  28.285 74.4 28.429 74.424 ;
     RECT  27.421 75.744 28.429 77.496 ;
     RECT  28.429 64.848 28.465 66.456 ;
     RECT  27.853 11.952 28.537 11.976 ;
     RECT  27.853 57.168 28.537 61.032 ;
     RECT  28.429 74.4 28.549 77.496 ;
     RECT  27.961 79.152 28.549 79.272 ;
     RECT  28.465 64.8 28.597 66.456 ;
     RECT  28.597 64.32 28.681 66.456 ;
     RECT  28.393 71.088 28.825 73.224 ;
     RECT  28.549 74.4 28.825 79.272 ;
     RECT  27.965 4.272 28.969 6.552 ;
     RECT  27.677 41.136 28.969 45.048 ;
     RECT  28.825 71.088 28.969 79.272 ;
     RECT  27.425 29.808 29.005 29.832 ;
     RECT  28.285 18.24 29.029 18.264 ;
     RECT  28.253 19.632 29.029 20.664 ;
     RECT  28.393 55.872 29.036 55.896 ;
     RECT  28.969 4.272 29.041 7.368 ;
     RECT  26.449 54.672 29.041 54.696 ;
     RECT  29.036 55.824 29.041 55.896 ;
     RECT  28.012 69.456 29.077 69.576 ;
     RECT  28.321 46.272 29.084 48.792 ;
     RECT  29.005 29.04 29.173 29.832 ;
     RECT  27.853 30.96 29.173 31.896 ;
     RECT  28.109 62.448 29.185 62.664 ;
     RECT  28.681 64.32 29.185 66.696 ;
     RECT  29.185 64.176 29.221 66.696 ;
     RECT  28.537 57.168 29.257 61.368 ;
     RECT  28.501 16.848 29.269 16.872 ;
     RECT  29.029 18.048 29.269 18.264 ;
     RECT  29.029 19.392 29.269 20.664 ;
     RECT  28.429 25.68 29.293 27.72 ;
     RECT  29.041 54.576 29.293 55.896 ;
     RECT  29.257 56.88 29.293 61.368 ;
     RECT  29.269 15.888 29.365 16.872 ;
     RECT  29.269 18.048 29.365 20.664 ;
     RECT  27.965 2.832 29.408 2.856 ;
     RECT  29.041 4.272 29.408 7.416 ;
     RECT  28.397 9.12 29.408 9.144 ;
     RECT  27.533 10.272 29.408 10.44 ;
     RECT  28.537 11.952 29.408 12.36 ;
     RECT  27.497 14.208 29.408 14.232 ;
     RECT  29.365 15.888 29.408 20.664 ;
     RECT  28.289 21.696 29.408 21.72 ;
     RECT  28.289 22.8 29.408 23.688 ;
     RECT  29.293 25.44 29.408 27.72 ;
     RECT  29.173 29.04 29.408 31.896 ;
     RECT  26.921 33.264 29.408 33.288 ;
     RECT  29.113 36.288 29.408 36.312 ;
     RECT  28.825 40.032 29.408 40.056 ;
     RECT  28.969 41.136 29.408 45.288 ;
     RECT  29.084 46.272 29.408 49.032 ;
     RECT  25.091 50.304 29.408 50.328 ;
     RECT  28.073 51.936 29.408 52.44 ;
     RECT  29.293 54.576 29.408 61.368 ;
     RECT  29.185 62.448 29.408 63 ;
     RECT  29.221 64.176 29.408 67.32 ;
     RECT  29.077 68.928 29.408 69.576 ;
     RECT  28.969 71.088 29.408 79.32 ;
     RECT  29.408 2.148 29.512 79.932 ;
     RECT  29.512 2.418 29.704 79.662 ;
     RECT  29.704 16.512 29.765 19.56 ;
     RECT  29.704 71.088 29.765 79.32 ;
     RECT  29.704 55.44 29.801 66.072 ;
     RECT  29.765 71.088 29.801 73.272 ;
     RECT  29.704 67.104 29.837 67.416 ;
     RECT  29.837 67.104 29.873 67.128 ;
     RECT  29.704 36 30.124 40.056 ;
     RECT  29.704 46.896 30.161 48.456 ;
     RECT  30.124 36 30.227 38.808 ;
     RECT  29.801 55.44 30.227 64.344 ;
     RECT  29.765 18.24 30.233 19.56 ;
     RECT  29.704 30.864 30.233 30.888 ;
     RECT  30.227 36 30.233 37.032 ;
     RECT  29.704 21.12 30.269 29.112 ;
     RECT  29.801 72.432 30.305 73.272 ;
     RECT  30.227 38.016 30.341 38.04 ;
     RECT  29.704 68.928 30.341 68.952 ;
     RECT  30.305 72.432 30.341 73.08 ;
     RECT  30.124 40.032 30.449 40.056 ;
     RECT  30.233 36.48 30.485 37.032 ;
     RECT  30.161 46.896 30.485 48.264 ;
     RECT  29.704 41.136 30.521 45.288 ;
     RECT  29.765 74.352 30.521 79.32 ;
     RECT  30.521 74.544 30.557 79.32 ;
     RECT  29.704 5.424 30.621 8.472 ;
     RECT  29.704 2.832 30.629 3.768 ;
     RECT  29.704 10.416 30.659 10.44 ;
     RECT  30.233 19.056 30.697 19.56 ;
     RECT  30.269 21.12 30.701 26.856 ;
     RECT  30.227 55.44 30.709 63.24 ;
     RECT  29.704 12 30.737 12.552 ;
     RECT  30.701 21.12 30.737 24.072 ;
     RECT  30.709 54.864 30.755 63.24 ;
     RECT  29.765 16.512 30.769 16.872 ;
     RECT  30.557 74.544 30.803 79.176 ;
     RECT  30.621 7.392 30.809 8.472 ;
     RECT  30.737 21.648 30.809 24.072 ;
     RECT  30.269 28.032 30.809 29.112 ;
     RECT  30.803 74.544 30.809 78.504 ;
     RECT  29.704 32.496 30.881 33.288 ;
     RECT  30.809 74.592 30.892 78.504 ;
     RECT  30.809 8.16 30.953 8.472 ;
     RECT  30.485 47.232 30.953 48.264 ;
     RECT  30.892 75.744 30.989 78.504 ;
     RECT  30.697 31.2 31.061 31.224 ;
     RECT  30.989 78.336 31.097 78.504 ;
     RECT  29.704 14.256 31.129 14.28 ;
     RECT  30.877 69.408 31.169 69.432 ;
     RECT  30.629 3.744 31.201 3.768 ;
     RECT  29.801 66.048 31.201 66.072 ;
     RECT  30.521 41.136 31.273 44.232 ;
     RECT  30.809 28.032 31.283 28.056 ;
     RECT  30.521 45.264 31.309 45.288 ;
     RECT  31.201 3.744 31.313 3.864 ;
     RECT  30.755 55.92 31.313 63.24 ;
     RECT  30.621 5.424 31.333 5.88 ;
     RECT  31.201 66.048 31.345 67.8 ;
     RECT  30.989 75.744 31.385 76.872 ;
     RECT  31.333 5.04 31.413 5.88 ;
     RECT  31.381 39.216 31.417 39.24 ;
     RECT  31.309 45.264 31.417 45.768 ;
     RECT  31.413 5.04 31.421 5.064 ;
     RECT  30.697 19.056 31.453 19.944 ;
     RECT  31.345 66.048 31.457 68.088 ;
     RECT  31.273 40.32 31.489 44.232 ;
     RECT  31.417 45.264 31.489 46.008 ;
     RECT  30.769 16.512 31.525 17.208 ;
     RECT  31.313 55.92 31.529 62.712 ;
     RECT  31.453 18.96 31.561 19.944 ;
     RECT  30.701 25.056 31.561 26.856 ;
     RECT  29.801 71.088 31.561 71.112 ;
     RECT  30.341 72.432 31.561 72.456 ;
     RECT  30.485 36.48 31.619 36.504 ;
     RECT  31.417 38.688 31.633 39.24 ;
     RECT  31.489 40.32 31.633 46.008 ;
     RECT  30.737 12.528 31.637 12.552 ;
     RECT  30.227 64.32 31.669 64.344 ;
     RECT  30.953 47.232 31.705 47.352 ;
     RECT  31.457 66.048 31.709 66.888 ;
     RECT  31.385 75.744 31.709 75.768 ;
     RECT  31.633 38.688 31.745 46.008 ;
     RECT  31.333 34.752 31.772 34.776 ;
     RECT  31.561 25.056 31.813 27.96 ;
     RECT  30.881 32.88 31.813 33.288 ;
     RECT  31.772 34.704 31.813 34.776 ;
     RECT  31.525 15.984 31.849 17.208 ;
     RECT  31.561 71.088 31.849 72.456 ;
     RECT  31.273 48.912 31.885 48.984 ;
     RECT  30.755 54.864 31.885 54.888 ;
     RECT  31.813 35.904 31.897 35.928 ;
     RECT  31.129 14.256 31.909 14.952 ;
     RECT  31.849 15.984 31.909 17.64 ;
     RECT  31.561 18.96 31.909 20.52 ;
     RECT  31.745 38.688 31.925 39.432 ;
     RECT  31.705 47.184 31.957 47.352 ;
     RECT  31.313 3.84 31.961 3.864 ;
     RECT  31.909 18.672 31.996 20.52 ;
     RECT  30.809 21.648 31.997 23.304 ;
     RECT  31.813 25.008 32.029 27.96 ;
     RECT  30.953 8.16 32.065 8.184 ;
     RECT  31.909 14.256 32.069 17.64 ;
     RECT  31.925 38.688 32.105 39.336 ;
     RECT  31.885 48.912 32.108 49.608 ;
     RECT  31.097 78.48 32.137 78.504 ;
     RECT  32.108 48.624 32.147 49.608 ;
     RECT  32.147 48.624 32.177 48.984 ;
     RECT  32.137 78.48 32.177 78.696 ;
     RECT  31.957 47.184 32.195 47.544 ;
     RECT  32.177 48.624 32.195 48.648 ;
     RECT  32.101 31.488 32.245 31.512 ;
     RECT  31.813 32.88 32.245 34.776 ;
     RECT  32.069 15.36 32.249 17.64 ;
     RECT  32.245 31.488 32.249 34.776 ;
     RECT  32.105 38.688 32.317 38.952 ;
     RECT  31.457 68.064 32.317 68.088 ;
     RECT  31.529 56.88 32.393 62.712 ;
     RECT  32.393 56.88 32.429 62.28 ;
     RECT  32.029 24.96 32.437 27.96 ;
     RECT  31.921 29.616 32.437 29.64 ;
     RECT  32.437 24.96 32.483 29.64 ;
     RECT  32.249 31.488 32.537 33.672 ;
     RECT  32.249 34.752 32.537 34.776 ;
     RECT  32.317 38.496 32.537 38.952 ;
     RECT  32.195 47.184 32.537 47.352 ;
     RECT  32.429 56.88 32.537 61.608 ;
     RECT  32.483 24.96 32.569 28.68 ;
     RECT  31.849 71.088 32.572 73.368 ;
     RECT  31.745 40.464 32.573 46.008 ;
     RECT  31.921 11.52 32.605 11.544 ;
     RECT  31.709 66.048 32.609 66.696 ;
     RECT  32.573 40.464 32.713 45.72 ;
     RECT  31.669 63.84 32.713 64.344 ;
     RECT  32.317 68.064 32.725 69.432 ;
     RECT  32.177 78.672 32.749 78.696 ;
     RECT  32.572 71.088 32.771 72.072 ;
     RECT  32.537 56.88 32.773 61.032 ;
     RECT  32.749 78.672 32.789 78.936 ;
     RECT  31.849 50.928 32.821 50.952 ;
     RECT  32.572 73.344 32.825 73.368 ;
     RECT  31.385 76.848 32.853 76.872 ;
     RECT  32.609 66.096 32.867 66.696 ;
     RECT  31.996 19.2 32.904 20.52 ;
     RECT  31.997 21.648 32.904 23.064 ;
     RECT  32.821 50.688 32.908 51.096 ;
     RECT  32.249 16.128 32.929 17.64 ;
     RECT  32.605 11.52 32.965 11.784 ;
     RECT  32.713 40.32 32.965 45.72 ;
     RECT  32.537 31.488 33.001 31.944 ;
     RECT  31.885 54.864 33.005 55.416 ;
     RECT  32.725 67.776 33.013 69.432 ;
     RECT  32.965 11.472 33.073 11.784 ;
     RECT  32.789 78.912 33.073 78.936 ;
     RECT  32.065 7.728 33.109 8.184 ;
     RECT  32.069 14.256 33.113 14.28 ;
     RECT  32.904 19.2 33.113 23.064 ;
     RECT  32.569 24.336 33.113 28.68 ;
     RECT  32.537 33.072 33.113 33.672 ;
     RECT  33.073 78.912 33.113 79.176 ;
     RECT  33.001 31.392 33.149 31.944 ;
     RECT  32.929 16.128 33.185 17.928 ;
     RECT  33.113 19.44 33.185 23.064 ;
     RECT  33.113 25.056 33.221 28.68 ;
     RECT  32.537 38.496 33.253 38.52 ;
     RECT  33.221 26.016 33.257 28.68 ;
     RECT  33.185 16.128 33.293 16.632 ;
     RECT  33.185 17.904 33.325 17.928 ;
     RECT  33.185 19.584 33.325 23.064 ;
     RECT  33.013 67.776 33.329 69.72 ;
     RECT  33.257 26.016 33.365 27.912 ;
     RECT  32.965 40.08 33.433 45.72 ;
     RECT  32.773 56.592 33.433 61.032 ;
     RECT  33.149 31.392 33.437 31.8 ;
     RECT  33.005 54.864 33.437 55.176 ;
     RECT  31.561 2.544 33.505 2.568 ;
     RECT  33.253 38.448 33.541 38.52 ;
     RECT  33.433 39.504 33.541 45.72 ;
     RECT  33.329 67.776 33.545 69 ;
     RECT  33.325 19.584 33.581 23.16 ;
     RECT  33.541 38.448 33.617 45.72 ;
     RECT  32.713 63.84 33.721 64.968 ;
     RECT  33.293 16.56 33.725 16.632 ;
     RECT  32.857 5.808 33.757 5.832 ;
     RECT  33.109 7.2 33.757 8.184 ;
     RECT  33.617 38.496 33.761 45.72 ;
     RECT  33.433 56.4 33.793 61.032 ;
     RECT  33.761 38.64 33.797 45.72 ;
     RECT  33.073 11.232 33.829 12.024 ;
     RECT  32.771 71.616 33.865 71.64 ;
     RECT  33.797 39.504 34.009 45.72 ;
     RECT  33.505 2.544 34.081 3.048 ;
     RECT  33.757 5.808 34.117 8.184 ;
     RECT  33.829 10.896 34.153 12.024 ;
     RECT  33.181 13.056 34.153 13.08 ;
     RECT  33.793 56.4 34.153 61.368 ;
     RECT  34.153 10.896 34.213 13.08 ;
     RECT  32.908 51.072 34.225 51.096 ;
     RECT  34.117 4.992 34.228 8.184 ;
     RECT  33.505 35.28 34.297 35.304 ;
     RECT  34.153 56.4 34.333 61.464 ;
     RECT  33.649 62.544 34.333 62.568 ;
     RECT  34.228 4.944 34.369 8.184 ;
     RECT  33.113 79.152 34.369 79.176 ;
     RECT  34.369 4.752 34.441 8.184 ;
     RECT  33.725 16.56 34.549 16.584 ;
     RECT  32.867 66.096 34.549 66.12 ;
     RECT  33.545 67.776 34.549 68.232 ;
     RECT  34.549 67.776 34.585 68.952 ;
     RECT  33.437 31.776 34.597 31.8 ;
     RECT  33.113 33.072 34.597 33.24 ;
     RECT  33.289 9.312 34.621 9.336 ;
     RECT  34.585 30.72 34.621 30.744 ;
     RECT  33.581 19.584 34.657 23.064 ;
     RECT  34.652 24.624 34.657 24.648 ;
     RECT  34.117 14.736 34.693 14.76 ;
     RECT  34.657 19.584 34.693 24.648 ;
     RECT  33.437 55.152 34.693 55.176 ;
     RECT  34.585 67.392 34.693 68.952 ;
     RECT  34.333 70.08 34.693 70.104 ;
     RECT  34.441 4.704 34.729 8.184 ;
     RECT  34.621 9.312 34.729 9.624 ;
     RECT  34.621 30.048 34.729 30.744 ;
     RECT  34.597 31.776 34.729 33.24 ;
     RECT  30.892 74.592 34.729 74.616 ;
     RECT  33.649 76.224 34.729 76.248 ;
     RECT  34.549 16.368 34.765 16.584 ;
     RECT  34.297 35.28 34.765 35.448 ;
     RECT  34.009 39.504 34.765 46.2 ;
     RECT  34.081 2.544 34.801 3.096 ;
     RECT  34.729 4.704 34.801 9.624 ;
     RECT  34.213 10.752 34.801 13.08 ;
     RECT  34.801 2.544 34.808 3.72 ;
     RECT  34.801 4.704 34.808 13.08 ;
     RECT  34.693 14.736 34.808 14.904 ;
     RECT  34.765 15.984 34.808 16.584 ;
     RECT  33.325 17.904 34.808 18.456 ;
     RECT  34.693 19.584 34.808 25.032 ;
     RECT  33.365 26.208 34.808 27.912 ;
     RECT  34.729 30.048 34.808 33.24 ;
     RECT  34.765 35.28 34.808 35.544 ;
     RECT  34.765 39.504 34.808 46.296 ;
     RECT  32.537 47.328 34.808 47.352 ;
     RECT  33.253 48.96 34.808 48.984 ;
     RECT  34.225 50.736 34.808 51.096 ;
     RECT  34.621 54.144 34.808 54.168 ;
     RECT  34.693 55.152 34.808 55.272 ;
     RECT  34.333 56.4 34.808 62.568 ;
     RECT  33.721 63.792 34.808 64.968 ;
     RECT  34.549 66 34.808 66.12 ;
     RECT  34.693 67.344 34.808 70.104 ;
     RECT  33.865 71.616 34.808 71.736 ;
     RECT  34.729 74.592 34.808 76.248 ;
     RECT  34.369 79.152 34.808 79.512 ;
     RECT  34.808 2.148 34.912 79.932 ;
     RECT  34.912 2.418 35.104 79.662 ;
     RECT  35.104 53.568 35.129 55.272 ;
     RECT  35.104 66.576 35.165 66.888 ;
     RECT  35.104 77.856 35.165 78.504 ;
     RECT  35.104 7.92 35.201 9.816 ;
     RECT  35.104 14.64 35.201 16.584 ;
     RECT  35.104 3.696 35.219 6.936 ;
     RECT  35.129 55.152 35.219 55.176 ;
     RECT  35.104 68.208 35.219 70.104 ;
     RECT  35.219 4.752 35.237 6.936 ;
     RECT  35.201 14.736 35.237 16.584 ;
     RECT  35.129 53.568 35.245 54.12 ;
     RECT  35.104 12.528 35.273 13.176 ;
     RECT  35.165 66.768 35.273 66.888 ;
     RECT  35.104 17.664 35.345 21.144 ;
     RECT  35.104 35.424 35.381 35.448 ;
     RECT  35.104 39.744 35.381 44.472 ;
     RECT  35.104 64.368 35.381 64.968 ;
     RECT  35.237 4.944 35.417 6.936 ;
     RECT  35.104 10.896 35.417 11.256 ;
     RECT  35.237 14.736 35.417 15.384 ;
     RECT  35.237 16.368 35.417 16.584 ;
     RECT  35.104 22.368 35.417 27.912 ;
     RECT  35.104 31.392 35.417 33.912 ;
     RECT  35.381 41.04 35.417 44.472 ;
     RECT  35.219 68.688 35.417 70.104 ;
     RECT  35.104 57.408 35.459 63.24 ;
     RECT  35.104 48.672 35.489 49.032 ;
     RECT  35.417 27.168 35.525 27.912 ;
     RECT  35.104 46.272 35.597 46.296 ;
     RECT  35.381 64.368 35.891 64.632 ;
     RECT  35.201 7.92 35.993 9.528 ;
     RECT  35.525 27.888 36.085 27.912 ;
     RECT  35.417 70.08 36.097 70.104 ;
     RECT  35.104 30.048 36.131 30.072 ;
     RECT  35.104 74.4 36.209 76.824 ;
     RECT  35.459 62.112 36.245 63.24 ;
     RECT  35.459 57.408 36.277 61.032 ;
     RECT  35.417 68.688 36.277 68.952 ;
     RECT  36.209 74.4 36.277 75.192 ;
     RECT  35.417 32.448 36.281 33.912 ;
     RECT  35.245 54.096 36.323 54.12 ;
     RECT  36.236 55.536 36.323 55.56 ;
     RECT  35.345 17.664 36.353 20.616 ;
     RECT  35.417 31.392 36.385 31.416 ;
     RECT  35.104 37.392 36.385 37.416 ;
     RECT  35.489 48.672 36.413 48.936 ;
     RECT  35.417 15.36 36.421 15.384 ;
     RECT  35.417 16.56 36.421 16.584 ;
     RECT  35.273 66.864 36.421 66.888 ;
     RECT  36.097 70.08 36.421 70.68 ;
     RECT  36.38 72.432 36.421 72.456 ;
     RECT  36.209 76.176 36.421 76.824 ;
     RECT  35.165 78.096 36.421 78.504 ;
     RECT  36.421 76.176 36.457 78.504 ;
     RECT  35.104 79.488 36.457 79.512 ;
     RECT  36.421 15.36 36.467 16.584 ;
     RECT  36.421 70.08 36.467 72.456 ;
     RECT  35.273 12.528 36.493 12.744 ;
     RECT  36.385 37.392 36.493 37.656 ;
     RECT  35.417 5.808 36.529 6.936 ;
     RECT  36.493 12.528 36.533 13.032 ;
     RECT  36.245 62.112 36.533 62.76 ;
     RECT  36.467 70.08 36.533 70.104 ;
     RECT  36.467 71.376 36.533 72.456 ;
     RECT  36.457 76.176 36.533 79.512 ;
     RECT  36.277 73.536 36.569 75.192 ;
     RECT  36.533 12.72 36.605 13.032 ;
     RECT  35.417 22.368 36.605 25.608 ;
     RECT  36.533 77.376 36.605 79.512 ;
     RECT  36.353 17.856 36.641 20.616 ;
     RECT  36.605 22.704 36.673 25.608 ;
     RECT  36.385 30.672 36.673 31.416 ;
     RECT  36.281 32.448 36.673 33.048 ;
     RECT  36.467 15.984 36.677 16.584 ;
     RECT  36.641 18.048 36.757 20.616 ;
     RECT  36.533 71.808 36.812 72.456 ;
     RECT  36.569 73.536 36.812 74.616 ;
     RECT  36.529 5.376 36.821 6.936 ;
     RECT  36.413 47.904 36.821 48.936 ;
     RECT  36.757 18.048 36.853 20.952 ;
     RECT  35.891 64.608 36.853 64.632 ;
     RECT  36.421 66.72 36.901 66.888 ;
     RECT  36.277 67.968 36.901 68.952 ;
     RECT  36.812 71.808 36.929 74.616 ;
     RECT  36.673 22.704 36.961 26.52 ;
     RECT  36.421 46.176 36.961 46.2 ;
     RECT  36.821 48.912 36.997 48.936 ;
     RECT  35.417 11.184 37.033 11.256 ;
     RECT  36.605 13.008 37.033 13.032 ;
     RECT  35.381 39.744 37.033 39.912 ;
     RECT  35.417 41.04 37.033 44.184 ;
     RECT  36.821 6.288 37.037 6.936 ;
     RECT  36.997 48.912 37.043 49.032 ;
     RECT  36.277 57.312 37.045 61.032 ;
     RECT  37.033 13.008 37.069 13.704 ;
     RECT  37.052 36.24 37.069 36.264 ;
     RECT  36.493 37.248 37.069 37.656 ;
     RECT  37.037 6.672 37.073 6.936 ;
     RECT  36.421 34.224 37.093 34.248 ;
     RECT  35.993 7.92 37.1 9.384 ;
     RECT  37.033 10.944 37.1 11.256 ;
     RECT  37.045 57.12 37.105 61.032 ;
     RECT  36.901 66.72 37.105 69.576 ;
     RECT  36.605 78.24 37.109 79.512 ;
     RECT  36.961 22.704 37.145 26.856 ;
     RECT  36.961 45.552 37.177 46.2 ;
     RECT  37.043 49.008 37.181 49.032 ;
     RECT  37.105 57.12 37.181 61.08 ;
     RECT  37.105 66.336 37.217 69.576 ;
     RECT  37.109 78.432 37.217 79.512 ;
     RECT  37.069 36.24 37.249 37.656 ;
     RECT  37.217 78.432 37.253 78.456 ;
     RECT  36.961 3.024 37.285 3.048 ;
     RECT  36.673 30.672 37.285 33.048 ;
     RECT  37.285 30.672 37.321 33.192 ;
     RECT  37.093 34.224 37.321 34.824 ;
     RECT  37.069 13.008 37.433 13.944 ;
     RECT  36.085 27.888 37.433 28.296 ;
     RECT  37.033 39.744 37.433 44.184 ;
     RECT  37.181 59.52 37.505 61.08 ;
     RECT  36.677 15.984 37.537 16.536 ;
     RECT  36.853 18.048 37.577 21.144 ;
     RECT  37.249 47.856 37.613 47.88 ;
     RECT  37.285 2.736 37.649 3.048 ;
     RECT  37.321 30.672 37.681 34.824 ;
     RECT  37.1 7.92 37.685 11.256 ;
     RECT  37.433 39.744 37.685 43.944 ;
     RECT  37.217 68.256 37.685 68.712 ;
     RECT  37.501 69.984 37.717 70.008 ;
     RECT  36.533 76.176 37.717 76.392 ;
     RECT  37.537 15.12 37.793 16.536 ;
     RECT  37.177 45.552 37.825 46.728 ;
     RECT  37.825 44.976 37.829 46.728 ;
     RECT  37.505 60.672 37.868 61.08 ;
     RECT  36.533 62.448 37.868 62.76 ;
     RECT  37.681 30.192 37.897 34.824 ;
     RECT  37.897 29.232 37.933 34.824 ;
     RECT  37.249 36.24 37.933 38.472 ;
     RECT  37.685 39.744 37.933 42.888 ;
     RECT  37.868 60.672 37.933 62.76 ;
     RECT  36.929 72.768 37.933 74.616 ;
     RECT  37.933 29.232 37.937 42.888 ;
     RECT  37.685 10.032 37.955 11.256 ;
     RECT  37.933 60.672 37.955 63.288 ;
     RECT  37.685 7.92 37.973 8.52 ;
     RECT  37.577 18.048 38.012 20.568 ;
     RECT  37.955 10.224 38.041 11.256 ;
     RECT  37.933 72.24 38.041 74.616 ;
     RECT  37.793 15.984 38.053 16.536 ;
     RECT  38.012 17.616 38.053 20.568 ;
     RECT  38.041 72.192 38.077 74.616 ;
     RECT  37.717 69.984 38.081 70.488 ;
     RECT  38.053 15.984 38.099 20.568 ;
     RECT  37.145 22.704 38.149 24.744 ;
     RECT  37.145 26.208 38.149 26.856 ;
     RECT  37.649 3.024 38.153 3.048 ;
     RECT  36.853 64.608 38.185 64.968 ;
     RECT  37.181 57.12 38.221 58.536 ;
     RECT  37.505 59.52 38.221 59.544 ;
     RECT  37.685 68.688 38.225 68.712 ;
     RECT  38.156 14.784 38.243 14.808 ;
     RECT  38.081 70.464 38.257 70.488 ;
     RECT  38.041 10.224 38.261 11.784 ;
     RECT  38.149 22.704 38.261 26.856 ;
     RECT  37.937 29.232 38.297 35.88 ;
     RECT  37.973 7.968 38.333 8.52 ;
     RECT  38.261 10.224 38.333 10.872 ;
     RECT  38.099 18.048 38.333 20.568 ;
     RECT  37.717 76.176 38.365 77.352 ;
     RECT  38.261 26.592 38.405 26.856 ;
     RECT  38.185 64.416 38.473 64.968 ;
     RECT  37.217 66.336 38.473 67.08 ;
     RECT  38.221 57.12 38.509 59.544 ;
     RECT  37.937 36.912 38.513 42.888 ;
     RECT  37.829 44.976 38.513 46.2 ;
     RECT  38.257 70.464 38.513 71.208 ;
     RECT  38.513 70.464 38.531 71.112 ;
     RECT  38.509 56.976 38.581 59.544 ;
     RECT  37.955 60.672 38.581 61.032 ;
     RECT  38.473 64.416 38.585 67.08 ;
     RECT  38.531 70.464 38.585 71.064 ;
     RECT  38.437 55.488 38.653 55.512 ;
     RECT  37.955 62.304 38.657 63.288 ;
     RECT  38.297 29.232 38.684 29.256 ;
     RECT  38.653 55.488 38.725 55.8 ;
     RECT  38.585 66.336 38.725 67.08 ;
     RECT  38.297 31.392 38.765 35.88 ;
     RECT  37.433 27.888 38.771 27.912 ;
     RECT  38.684 29.136 38.771 29.256 ;
     RECT  37.897 21.648 38.773 21.672 ;
     RECT  38.261 22.704 38.773 25.32 ;
     RECT  38.077 72.192 38.773 74.664 ;
     RECT  38.365 75.696 38.773 77.352 ;
     RECT  38.773 21.648 38.801 25.32 ;
     RECT  38.765 31.392 38.801 34.776 ;
     RECT  38.581 56.976 38.801 61.032 ;
     RECT  38.801 21.648 38.819 24.744 ;
     RECT  38.732 68.304 38.819 68.328 ;
     RECT  38.005 53.856 38.833 53.88 ;
     RECT  38.585 64.416 38.86 65.352 ;
     RECT  37.073 6.672 38.869 6.696 ;
     RECT  38.833 53.568 38.869 53.88 ;
     RECT  38.773 72.192 38.873 77.352 ;
     RECT  38.86 64.416 38.881 65.064 ;
     RECT  38.801 31.728 38.909 34.776 ;
     RECT  38.873 72.192 38.981 76.056 ;
     RECT  38.869 5.952 39.013 6.696 ;
     RECT  38.725 55.248 39.017 55.8 ;
     RECT  38.513 45.552 39.053 46.2 ;
     RECT  38.657 62.304 39.125 62.712 ;
     RECT  37.685 43.92 39.157 43.944 ;
     RECT  38.333 10.224 39.161 10.296 ;
     RECT  38.909 31.728 39.161 31.896 ;
     RECT  39.164 2.688 39.193 2.712 ;
     RECT  38.099 15.984 39.193 16.968 ;
     RECT  39.193 2.592 39.205 2.712 ;
     RECT  37.033 50.064 39.229 50.088 ;
     RECT  38.333 18.048 39.301 18.216 ;
     RECT  38.765 35.856 39.301 35.88 ;
     RECT  38.513 36.912 39.301 42.6 ;
     RECT  38.405 26.592 39.409 26.76 ;
     RECT  38.725 66.336 39.445 67.32 ;
     RECT  38.869 53.568 39.517 54.12 ;
     RECT  39.229 49.536 39.589 50.088 ;
     RECT  39.157 43.872 39.625 43.944 ;
     RECT  38.333 19.776 39.661 20.568 ;
     RECT  39.017 55.248 39.661 55.512 ;
     RECT  38.981 72.192 39.685 73.56 ;
     RECT  39.445 66.336 39.697 67.656 ;
     RECT  38.333 8.496 39.733 8.52 ;
     RECT  37.217 79.488 39.733 79.512 ;
     RECT  39.301 35.856 39.769 42.6 ;
     RECT  39.625 43.872 39.769 44.088 ;
     RECT  38.881 64.416 39.805 64.968 ;
     RECT  38.771 29.232 39.841 29.256 ;
     RECT  38.585 70.464 39.841 70.488 ;
     RECT  39.841 29.04 39.877 29.256 ;
     RECT  39.769 35.856 39.877 44.088 ;
     RECT  39.053 45.552 39.877 46.056 ;
     RECT  39.589 49.536 39.877 50.136 ;
     RECT  39.445 47.952 39.949 47.976 ;
     RECT  39.949 47.952 40.021 48.456 ;
     RECT  39.877 49.536 40.021 50.424 ;
     RECT  39.301 18.048 40.049 18.792 ;
     RECT  39.661 19.776 40.049 21.144 ;
     RECT  40.021 47.952 40.049 50.424 ;
     RECT  39.193 15.456 40.069 16.968 ;
     RECT  40.049 18.048 40.069 21.144 ;
     RECT  40.049 47.184 40.069 50.424 ;
     RECT  39.805 63.792 40.069 64.968 ;
     RECT  39.697 66.048 40.069 67.656 ;
     RECT  38.801 56.976 40.093 60.84 ;
     RECT  39.205 2.592 40.208 3.336 ;
     RECT  39.013 5.952 40.208 6.84 ;
     RECT  39.733 8.496 40.208 9.144 ;
     RECT  39.161 10.272 40.208 10.296 ;
     RECT  39.253 11.952 40.208 11.976 ;
     RECT  37.433 13.008 40.208 13.704 ;
     RECT  40.069 15.456 40.208 21.144 ;
     RECT  38.819 22.176 40.208 24.744 ;
     RECT  39.409 26.352 40.208 26.76 ;
     RECT  39.877 28.176 40.208 29.256 ;
     RECT  39.161 31.728 40.208 31.8 ;
     RECT  38.909 33.264 40.208 34.776 ;
     RECT  39.877 35.856 40.208 46.056 ;
     RECT  40.069 47.184 40.208 50.568 ;
     RECT  39.517 52.8 40.208 54.12 ;
     RECT  39.661 55.2 40.208 55.512 ;
     RECT  40.093 56.976 40.208 60.936 ;
     RECT  39.125 62.688 40.208 62.712 ;
     RECT  40.069 63.792 40.208 67.656 ;
     RECT  39.841 70.08 40.208 70.488 ;
     RECT  39.685 71.616 40.208 73.56 ;
     RECT  38.981 75.024 40.208 76.056 ;
     RECT  38.873 77.328 40.208 77.352 ;
     RECT  39.733 78.624 40.208 79.512 ;
     RECT  40.208 2.148 40.312 79.932 ;
     RECT  40.312 2.418 40.504 79.662 ;
     RECT  40.504 46.032 40.529 46.824 ;
     RECT  40.504 2.592 40.601 2.616 ;
     RECT  40.504 12.912 40.637 13.704 ;
     RECT  40.504 14.736 40.673 17.112 ;
     RECT  40.504 44.064 40.673 45 ;
     RECT  40.504 52.8 40.673 54.12 ;
     RECT  40.504 56.256 40.673 58.536 ;
     RECT  40.504 34.704 40.745 34.776 ;
     RECT  40.673 44.064 40.745 44.76 ;
     RECT  40.504 7.68 40.781 8.52 ;
     RECT  40.504 31.776 40.781 31.8 ;
     RECT  40.673 53.808 40.781 54.12 ;
     RECT  40.504 47.952 40.817 47.976 ;
     RECT  40.673 52.8 40.817 52.824 ;
     RECT  40.673 14.736 40.925 16.344 ;
     RECT  40.504 66.048 40.961 67.656 ;
     RECT  40.504 19.92 40.997 21.624 ;
     RECT  40.504 41.04 40.997 43.032 ;
     RECT  40.745 44.064 40.997 44.712 ;
     RECT  40.673 56.256 40.997 58.152 ;
     RECT  40.504 69.072 40.997 69.096 ;
     RECT  40.925 14.736 41.069 15.48 ;
     RECT  40.504 28.176 41.069 29.064 ;
     RECT  40.745 34.752 41.069 34.776 ;
     RECT  40.504 59.52 41.069 61.032 ;
     RECT  40.504 11.664 41.105 11.736 ;
     RECT  41.069 59.52 41.171 59.544 ;
     RECT  41.069 28.272 41.213 29.064 ;
     RECT  40.504 37.632 41.213 38.184 ;
     RECT  40.997 56.256 41.213 56.28 ;
     RECT  40.997 19.92 41.249 20.328 ;
     RECT  41.105 11.712 41.321 11.736 ;
     RECT  40.504 49.296 41.321 50.424 ;
     RECT  41.321 49.296 41.357 49.512 ;
     RECT  40.504 22.752 41.497 26.664 ;
     RECT  40.504 62.208 41.533 62.712 ;
     RECT  40.504 63.744 41.533 64.968 ;
     RECT  40.781 53.856 41.569 54.12 ;
     RECT  41.069 60.912 41.609 61.032 ;
     RECT  41.497 33.648 41.645 33.672 ;
     RECT  40.504 39.84 41.645 39.864 ;
     RECT  40.504 70.08 41.645 70.104 ;
     RECT  40.997 41.04 41.681 42.408 ;
     RECT  41.533 75.744 41.681 76.2 ;
     RECT  41.569 53.856 41.753 54.168 ;
     RECT  40.504 79.2 41.777 79.224 ;
     RECT  40.504 6.24 41.785 6.264 ;
     RECT  40.781 7.68 41.785 7.704 ;
     RECT  40.504 72.384 41.785 72.408 ;
     RECT  41.213 38.16 41.789 38.184 ;
     RECT  41.785 6.24 41.821 7.704 ;
     RECT  41.785 71.808 41.821 72.408 ;
     RECT  41.821 71.232 41.845 72.408 ;
     RECT  41.845 71.232 41.891 72.984 ;
     RECT  40.961 66.192 41.969 67.656 ;
     RECT  41.821 5.424 42.001 7.704 ;
     RECT  41.681 41.232 42.001 42.408 ;
     RECT  41.609 60.96 42.037 61.032 ;
     RECT  41.533 62.208 42.037 64.968 ;
     RECT  40.997 44.688 42.092 44.712 ;
     RECT  41.069 14.736 42.109 15.096 ;
     RECT  42.092 44.016 42.109 44.712 ;
     RECT  42.001 41.232 42.133 42.792 ;
     RECT  42.109 44.016 42.133 45.048 ;
     RECT  42.037 60.96 42.133 64.968 ;
     RECT  41.969 66.192 42.133 67.08 ;
     RECT  42.001 5.376 42.179 7.704 ;
     RECT  42.133 60.96 42.179 67.08 ;
     RECT  41.677 18.144 42.181 18.168 ;
     RECT  40.997 57.408 42.217 58.152 ;
     RECT  42.179 65.664 42.22 67.08 ;
     RECT  42.22 65.76 42.221 67.08 ;
     RECT  41.891 72.96 42.221 72.984 ;
     RECT  41.681 76.176 42.221 76.2 ;
     RECT  41.249 19.92 42.253 19.944 ;
     RECT  40.997 21.6 42.253 21.624 ;
     RECT  41.497 22.752 42.257 27.288 ;
     RECT  40.637 12.912 42.277 12.936 ;
     RECT  42.109 14.208 42.277 15.096 ;
     RECT  42.179 6.864 42.293 7.704 ;
     RECT  42.179 60.96 42.293 64.104 ;
     RECT  42.277 12.912 42.364 15.096 ;
     RECT  41.821 2.304 42.401 2.328 ;
     RECT  42.109 11.664 42.428 11.688 ;
     RECT  42.181 18.144 42.433 18.648 ;
     RECT  42.428 11.52 42.469 11.688 ;
     RECT  41.777 78.624 42.473 79.224 ;
     RECT  41.893 48.912 42.509 48.936 ;
     RECT  42.469 30.864 42.541 30.888 ;
     RECT  42.257 26.64 42.545 27.288 ;
     RECT  42.361 38.832 42.545 38.856 ;
     RECT  42.133 41.232 42.545 45.048 ;
     RECT  42.364 14.208 42.611 15.096 ;
     RECT  42.611 14.784 42.652 15.096 ;
     RECT  42.257 22.752 42.653 25.512 ;
     RECT  42.293 62.4 42.689 64.104 ;
     RECT  41.713 74.064 42.725 74.088 ;
     RECT  42.109 51.648 42.757 51.672 ;
     RECT  42.469 11.52 42.761 12.504 ;
     RECT  42.541 30.816 42.797 30.888 ;
     RECT  42.757 51.216 42.803 52.488 ;
     RECT  42.803 52.464 42.841 52.488 ;
     RECT  42.803 51.216 42.844 51.24 ;
     RECT  42.652 15.072 42.865 15.096 ;
     RECT  42.433 17.568 42.937 18.648 ;
     RECT  41.891 71.232 42.973 71.832 ;
     RECT  42.973 71.04 43.013 71.832 ;
     RECT  41.213 28.272 43.045 28.296 ;
     RECT  42.293 60.96 43.081 61.416 ;
     RECT  42.937 17.04 43.117 18.648 ;
     RECT  42.433 35.136 43.117 35.16 ;
     RECT  42.689 62.4 43.121 63.816 ;
     RECT  43.117 17.04 43.189 18.84 ;
     RECT  42.253 19.92 43.189 21.624 ;
     RECT  43.121 62.4 43.193 63.768 ;
     RECT  43.117 34.752 43.201 35.16 ;
     RECT  42.545 27.168 43.225 27.288 ;
     RECT  43.045 28.272 43.225 28.344 ;
     RECT  40.529 46.368 43.229 46.824 ;
     RECT  42.761 11.52 43.325 11.976 ;
     RECT  43.189 17.04 43.333 21.624 ;
     RECT  42.653 22.752 43.333 25.032 ;
     RECT  42.433 69.312 43.361 69.336 ;
     RECT  42.217 57.408 43.369 58.776 ;
     RECT  42.973 59.76 43.369 59.784 ;
     RECT  43.189 31.056 43.373 31.08 ;
     RECT  42.757 76.32 43.381 76.344 ;
     RECT  43.369 57.408 43.405 59.784 ;
     RECT  43.081 60.912 43.405 61.416 ;
     RECT  43.361 68.352 43.405 69.336 ;
     RECT  42.545 41.232 43.409 43.176 ;
     RECT  43.333 17.04 43.441 25.032 ;
     RECT  40.504 36.336 43.445 36.36 ;
     RECT  43.193 62.4 43.445 63.624 ;
     RECT  43.381 72.096 43.468 72.12 ;
     RECT  43.381 77.52 43.481 77.544 ;
     RECT  43.405 68.112 43.517 69.336 ;
     RECT  43.229 46.368 43.532 46.68 ;
     RECT  43.409 41.232 43.573 42.744 ;
     RECT  43.325 11.376 43.585 11.976 ;
     RECT  43.532 46.128 43.619 46.68 ;
     RECT  43.441 16.848 43.649 25.032 ;
     RECT  43.649 16.8 43.657 25.032 ;
     RECT  42.293 7.68 43.717 7.704 ;
     RECT  43.657 16.464 43.763 25.032 ;
     RECT  42.865 15.072 43.801 15.192 ;
     RECT  43.573 40.752 43.805 42.744 ;
     RECT  43.765 74.544 43.837 74.568 ;
     RECT  43.717 6.72 43.859 7.8 ;
     RECT  41.753 54.144 43.861 54.168 ;
     RECT  43.693 55.296 43.861 55.32 ;
     RECT  43.861 54.144 43.907 55.32 ;
     RECT  43.201 35.136 43.909 35.16 ;
     RECT  43.381 76.32 43.913 76.488 ;
     RECT  43.763 16.752 43.949 25.032 ;
     RECT  43.225 27.168 43.981 28.344 ;
     RECT  42.545 44.688 43.981 45.048 ;
     RECT  43.837 74.544 43.985 74.76 ;
     RECT  43.801 14.208 44.017 15.192 ;
     RECT  43.405 57.408 44.021 61.416 ;
     RECT  43.013 71.04 44.021 71.064 ;
     RECT  43.981 44.688 44.053 45.288 ;
     RECT  43.985 74.544 44.057 74.712 ;
     RECT  42.179 5.424 44.089 5.64 ;
     RECT  44.017 14.208 44.089 15.72 ;
     RECT  43.981 26.784 44.089 29.256 ;
     RECT  43.907 54.144 44.089 55.272 ;
     RECT  43.729 39.744 44.129 39.768 ;
     RECT  43.445 62.4 44.129 63.336 ;
     RECT  42.221 65.76 44.165 66.936 ;
     RECT  43.859 7.68 44.197 7.8 ;
     RECT  44.021 60.672 44.204 61.416 ;
     RECT  44.129 62.4 44.204 62.616 ;
     RECT  44.089 25.824 44.269 29.256 ;
     RECT  44.197 7.68 44.284 7.944 ;
     RECT  44.204 60.672 44.291 62.616 ;
     RECT  43.573 49.488 44.305 49.512 ;
     RECT  43.549 31.152 44.309 31.176 ;
     RECT  43.805 41.04 44.345 42.744 ;
     RECT  44.057 74.64 44.345 74.712 ;
     RECT  43.585 10.8 44.387 11.976 ;
     RECT  44.089 5.424 44.437 6.456 ;
     RECT  44.345 41.232 44.437 42.744 ;
     RECT  44.053 43.92 44.437 45.288 ;
     RECT  44.089 14.16 44.453 15.72 ;
     RECT  44.437 41.232 44.483 45.288 ;
     RECT  44.387 10.8 44.521 11.688 ;
     RECT  44.453 14.16 44.525 15.192 ;
     RECT  44.437 4.512 44.531 6.456 ;
     RECT  43.909 35.136 44.597 35.496 ;
     RECT  44.483 42 44.597 43.32 ;
     RECT  44.291 60.672 44.597 61.416 ;
     RECT  44.597 60.672 44.633 61.272 ;
     RECT  44.053 8.928 44.677 8.952 ;
     RECT  44.521 9.984 44.677 11.688 ;
     RECT  44.165 65.76 44.725 66.888 ;
     RECT  43.981 72.912 44.828 72.936 ;
     RECT  44.869 33.264 44.881 33.288 ;
     RECT  43.513 3.312 44.917 3.336 ;
     RECT  44.305 49.488 44.917 50.04 ;
     RECT  44.021 57.408 44.989 59.256 ;
     RECT  43.717 13.104 45.061 13.128 ;
     RECT  44.525 14.16 45.061 14.952 ;
     RECT  45.061 13.104 45.385 14.952 ;
     RECT  43.949 16.992 45.385 24.168 ;
     RECT  43.517 68.112 45.445 68.952 ;
     RECT  44.269 25.824 45.493 29.304 ;
     RECT  44.917 2.832 45.608 3.432 ;
     RECT  44.531 4.512 45.608 5.448 ;
     RECT  44.531 6.432 45.608 6.456 ;
     RECT  44.284 7.68 45.608 7.704 ;
     RECT  44.677 8.928 45.608 11.688 ;
     RECT  45.385 13.056 45.608 14.952 ;
     RECT  45.385 16.8 45.608 24.168 ;
     RECT  45.493 25.536 45.608 29.304 ;
     RECT  44.485 31.872 45.608 31.896 ;
     RECT  44.881 33.264 45.608 34.104 ;
     RECT  44.597 35.424 45.608 35.496 ;
     RECT  45.205 37.104 45.608 37.128 ;
     RECT  44.437 39.264 45.608 39.288 ;
     RECT  44.597 42.72 45.608 43.32 ;
     RECT  44.483 44.448 45.608 45.288 ;
     RECT  43.619 46.656 45.608 46.68 ;
     RECT  44.917 48.816 45.608 50.04 ;
     RECT  44.089 53.664 45.608 55.272 ;
     RECT  44.989 57.024 45.608 59.256 ;
     RECT  44.633 60.912 45.608 61.272 ;
     RECT  44.291 62.496 45.608 62.616 ;
     RECT  44.725 64.944 45.608 66.888 ;
     RECT  45.445 68.112 45.608 69.768 ;
     RECT  45.241 71.184 45.608 71.208 ;
     RECT  44.828 72.912 45.608 73.512 ;
     RECT  44.345 74.688 45.608 74.712 ;
     RECT  43.913 76.464 45.608 76.488 ;
     RECT  45.241 78.144 45.608 78.168 ;
     RECT  42.473 79.2 45.608 79.224 ;
     RECT  45.608 2.148 45.712 79.932 ;
     RECT  45.712 2.418 45.904 79.662 ;
     RECT  45.904 16.512 45.965 22.776 ;
     RECT  45.904 27.456 46.019 29.304 ;
     RECT  45.904 58.176 46.037 59.304 ;
     RECT  45.904 76.464 46.037 76.872 ;
     RECT  46.019 27.552 46.06 29.304 ;
     RECT  45.965 16.512 46.073 22.2 ;
     RECT  45.904 52.224 46.181 55.272 ;
     RECT  46.181 52.224 46.217 52.248 ;
     RECT  45.904 47.856 46.253 51.24 ;
     RECT  45.904 78.096 46.253 78.168 ;
     RECT  46.181 53.568 46.289 55.272 ;
     RECT  45.904 57.024 46.333 57.144 ;
     RECT  45.904 34.368 46.397 35.496 ;
     RECT  45.904 25.536 46.433 26.232 ;
     RECT  46.397 35.472 46.451 35.496 ;
     RECT  45.904 11.664 46.541 15.048 ;
     RECT  45.904 44.448 46.577 45.288 ;
     RECT  46.073 16.512 46.643 19.272 ;
     RECT  46.253 78.144 46.649 78.168 ;
     RECT  46.643 17.616 46.684 19.272 ;
     RECT  46.541 13.296 46.685 15.048 ;
     RECT  45.904 79.2 46.721 79.224 ;
     RECT  45.904 62.16 46.732 63.672 ;
     RECT  45.904 65.568 46.739 68.424 ;
     RECT  46.253 47.856 46.757 48.504 ;
     RECT  46.541 11.808 46.829 12.264 ;
     RECT  46.685 13.296 46.829 14.28 ;
     RECT  46.433 25.824 46.829 26.232 ;
     RECT  45.904 38.736 46.829 39.912 ;
     RECT  46.253 49.488 46.835 51.24 ;
     RECT  45.904 9.216 46.865 10.152 ;
     RECT  46.037 58.8 46.865 59.304 ;
     RECT  46.739 65.568 46.897 68.184 ;
     RECT  45.904 5.136 46.933 8.136 ;
     RECT  46.892 60.384 46.979 60.408 ;
     RECT  46.897 64.848 46.981 68.184 ;
     RECT  45.904 70.128 46.981 70.728 ;
     RECT  45.904 37.584 46.988 37.656 ;
     RECT  46.829 38.736 46.988 39.288 ;
     RECT  46.06 28.512 47.009 29.304 ;
     RECT  46.988 37.584 47.029 39.288 ;
     RECT  46.981 69.456 47.029 70.728 ;
     RECT  46.333 57.12 47.045 57.144 ;
     RECT  46.865 58.8 47.045 59.256 ;
     RECT  47.029 37.392 47.075 39.288 ;
     RECT  45.904 73.536 47.077 73.56 ;
     RECT  45.904 23.808 47.113 23.832 ;
     RECT  47.075 37.392 47.113 37.608 ;
     RECT  47.029 69.456 47.125 70.824 ;
     RECT  47.077 73.536 47.125 74.136 ;
     RECT  47.113 36.912 47.153 37.608 ;
     RECT  45.904 42.72 47.153 42.744 ;
     RECT  47.125 69.36 47.171 70.824 ;
     RECT  47.077 30.432 47.185 30.456 ;
     RECT  46.732 62.16 47.185 63.288 ;
     RECT  46.684 18 47.257 19.272 ;
     RECT  46.073 20.304 47.257 22.2 ;
     RECT  46.981 64.608 47.267 68.184 ;
     RECT  47.185 61.44 47.297 63.288 ;
     RECT  47.297 61.728 47.315 63.288 ;
     RECT  47.267 64.608 47.315 68.136 ;
     RECT  46.643 16.512 47.333 16.536 ;
     RECT  46.757 47.856 47.333 47.88 ;
     RECT  46.835 51.216 47.333 51.24 ;
     RECT  47.315 62.16 47.333 63.288 ;
     RECT  47.171 69.36 47.361 70.248 ;
     RECT  46.289 53.568 47.365 55.032 ;
     RECT  45.904 72.336 47.365 72.36 ;
     RECT  47.365 53.568 47.401 55.176 ;
     RECT  46.933 5.136 47.405 8.184 ;
     RECT  47.125 73.536 47.405 74.904 ;
     RECT  46.835 49.488 47.513 50.136 ;
     RECT  47.315 64.608 47.513 65.064 ;
     RECT  47.113 23.808 47.617 23.976 ;
     RECT  46.397 34.368 47.617 34.392 ;
     RECT  47.293 15.456 47.653 15.48 ;
     RECT  47.185 26.88 47.657 26.952 ;
     RECT  47.653 14.496 47.699 15.48 ;
     RECT  47.405 74.064 47.725 74.904 ;
     RECT  46.577 45.264 47.761 45.288 ;
     RECT  47.405 5.184 47.797 8.184 ;
     RECT  46.865 9.216 47.797 9.24 ;
     RECT  46.829 12.24 47.797 12.264 ;
     RECT  47.761 45.12 47.801 45.288 ;
     RECT  47.045 58.896 47.833 59.256 ;
     RECT  47.361 69.84 47.836 70.248 ;
     RECT  47.365 72.336 47.845 72.456 ;
     RECT  47.725 74.064 47.891 75.24 ;
     RECT  47.257 18 47.909 22.2 ;
     RECT  47.513 64.608 47.909 65.016 ;
     RECT  47.657 26.88 47.939 26.904 ;
     RECT  47.797 11.952 47.945 12.264 ;
     RECT  47.401 53.568 47.953 55.464 ;
     RECT  47.945 11.952 47.977 11.976 ;
     RECT  47.617 34.368 47.981 35.112 ;
     RECT  47.845 71.472 48.017 72.456 ;
     RECT  46.829 25.824 48.037 25.848 ;
     RECT  47.041 43.824 48.044 43.848 ;
     RECT  45.904 31.68 48.049 31.704 ;
     RECT  45.904 32.736 48.049 32.76 ;
     RECT  47.909 18 48.083 22.152 ;
     RECT  47.797 5.184 48.085 9.24 ;
     RECT  47.977 11.52 48.085 11.976 ;
     RECT  46.829 13.296 48.085 13.32 ;
     RECT  47.009 29.232 48.085 29.304 ;
     RECT  47.185 30.384 48.085 30.456 ;
     RECT  48.044 43.824 48.085 44.04 ;
     RECT  47.953 53.568 48.089 54.36 ;
     RECT  47.836 69.84 48.089 70.152 ;
     RECT  47.689 46.512 48.129 46.536 ;
     RECT  48.085 43.296 48.131 44.04 ;
     RECT  45.904 2.496 48.157 2.52 ;
     RECT  48.085 29.232 48.181 30.456 ;
     RECT  48.049 31.68 48.181 32.76 ;
     RECT  48.181 29.232 48.227 32.76 ;
     RECT  48.129 46.512 48.227 46.92 ;
     RECT  47.801 45.12 48.233 45.144 ;
     RECT  48.085 13.104 48.269 13.32 ;
     RECT  48.157 2.496 48.301 2.568 ;
     RECT  45.904 3.6 48.301 3.624 ;
     RECT  47.315 66.144 48.301 68.136 ;
     RECT  48.229 78.096 48.313 78.12 ;
     RECT  47.833 58.896 48.325 59.832 ;
     RECT  48.227 29.232 48.332 30.984 ;
     RECT  48.085 11.424 48.337 11.976 ;
     RECT  47.953 55.44 48.341 55.464 ;
     RECT  48.337 11.376 48.373 11.976 ;
     RECT  47.653 27.936 48.373 27.96 ;
     RECT  48.332 28.944 48.373 30.984 ;
     RECT  47.891 74.064 48.377 74.088 ;
     RECT  48.085 5.184 48.409 10.056 ;
     RECT  47.153 36.912 48.445 37.416 ;
     RECT  47.333 62.16 48.445 62.76 ;
     RECT  46.037 76.464 48.449 76.488 ;
     RECT  48.373 27.936 48.467 30.984 ;
     RECT  48.467 27.936 48.469 27.96 ;
     RECT  48.265 50.976 48.469 51 ;
     RECT  48.193 52.224 48.469 52.248 ;
     RECT  47.617 23.52 48.481 23.976 ;
     RECT  47.909 64.608 48.481 64.968 ;
     RECT  48.409 5.184 48.485 10.104 ;
     RECT  48.131 43.296 48.485 43.848 ;
     RECT  48.469 50.976 48.515 53.016 ;
     RECT  48.373 11.088 48.557 11.976 ;
     RECT  47.513 49.488 48.589 49.512 ;
     RECT  48.515 50.976 48.589 51.912 ;
     RECT  47.653 57.552 48.593 57.576 ;
     RECT  47.891 75.216 48.665 75.24 ;
     RECT  48.485 6 48.733 10.104 ;
     RECT  48.557 11.088 48.733 11.832 ;
     RECT  48.445 62.16 48.733 62.952 ;
     RECT  48.481 63.936 48.733 64.968 ;
     RECT  48.469 27.888 48.773 27.96 ;
     RECT  48.017 71.472 48.773 71.496 ;
     RECT  48.467 28.944 48.803 30.984 ;
     RECT  48.409 16.896 48.877 16.92 ;
     RECT  48.445 36.624 48.899 37.416 ;
     RECT  48.269 13.296 48.917 13.32 ;
     RECT  48.773 27.936 48.917 27.96 ;
     RECT  48.803 28.944 48.917 28.968 ;
     RECT  47.761 79.152 48.949 79.176 ;
     RECT  48.877 16.896 48.989 16.968 ;
     RECT  48.325 58.896 48.989 60.648 ;
     RECT  48.733 62.16 49.021 64.968 ;
     RECT  48.301 66.144 49.021 68.424 ;
     RECT  48.989 58.896 49.043 58.92 ;
     RECT  48.949 78.768 49.061 79.176 ;
     RECT  48.589 49.488 49.097 51.912 ;
     RECT  48.989 16.896 49.133 16.92 ;
     RECT  47.699 14.496 49.189 14.52 ;
     RECT  49.021 62.16 49.237 68.424 ;
     RECT  49.061 79.152 49.241 79.176 ;
     RECT  49.189 13.584 49.276 14.52 ;
     RECT  48.515 52.992 49.277 53.016 ;
     RECT  48.481 23.52 49.309 24.504 ;
     RECT  48.037 25.68 49.309 25.848 ;
     RECT  48.989 59.952 49.309 60.648 ;
     RECT  49.237 61.92 49.309 68.424 ;
     RECT  48.227 32.448 49.313 32.76 ;
     RECT  49.097 49.488 49.313 50.712 ;
     RECT  49.097 51.888 49.331 51.912 ;
     RECT  49.021 76.992 49.349 77.016 ;
     RECT  49.309 23.52 49.381 25.848 ;
     RECT  48.089 54.096 49.381 54.36 ;
     RECT  48.913 40.656 49.417 40.68 ;
     RECT  48.301 2.496 49.421 3.624 ;
     RECT  48.803 30.048 49.421 30.984 ;
     RECT  49.309 59.952 49.457 68.424 ;
     RECT  49.421 3.552 49.489 3.624 ;
     RECT  49.489 3.552 49.525 3.672 ;
     RECT  49.276 14.4 49.525 14.52 ;
     RECT  48.089 69.84 49.529 69.864 ;
     RECT  49.381 54.048 49.633 54.36 ;
     RECT  49.313 50.688 49.709 50.712 ;
     RECT  48.083 18 49.745 21.96 ;
     RECT  49.381 23.52 49.745 26.808 ;
     RECT  49.745 24.48 49.777 26.808 ;
     RECT  49.417 40.656 49.777 41.16 ;
     RECT  49.633 42.288 49.777 42.312 ;
     RECT  49.597 48.096 49.885 48.12 ;
     RECT  47.981 35.088 49.909 35.112 ;
     RECT  49.777 40.656 49.921 42.312 ;
     RECT  48.227 46.896 49.921 46.92 ;
     RECT  49.921 40.32 49.957 42.312 ;
     RECT  49.561 16.272 49.961 16.296 ;
     RECT  49.957 40.032 49.993 42.312 ;
     RECT  48.485 43.296 49.993 43.32 ;
     RECT  49.421 30.096 49.997 30.984 ;
     RECT  49.909 34.752 49.997 35.112 ;
     RECT  49.745 18 50.029 21.672 ;
     RECT  50.029 17.472 50.101 21.672 ;
     RECT  49.921 46.56 50.101 46.92 ;
     RECT  49.885 48.096 50.101 48.408 ;
     RECT  49.525 3.552 50.137 3.912 ;
     RECT  48.805 56.736 50.137 56.76 ;
     RECT  49.273 58.512 50.137 58.728 ;
     RECT  49.777 24.48 50.209 26.904 ;
     RECT  49.993 40.032 50.353 43.32 ;
     RECT  50.209 72.336 50.389 72.36 ;
     RECT  50.101 46.56 50.425 48.408 ;
     RECT  49.313 32.736 50.485 32.76 ;
     RECT  50.425 44.928 50.497 44.952 ;
     RECT  50.461 74.592 50.497 74.616 ;
     RECT  50.353 40.032 50.533 43.896 ;
     RECT  50.497 44.928 50.533 45 ;
     RECT  50.137 56.736 50.533 58.728 ;
     RECT  49.457 59.952 50.533 67.848 ;
     RECT  50.137 3.552 50.641 3.96 ;
     RECT  48.733 6 50.641 11.832 ;
     RECT  49.993 13.104 50.641 13.32 ;
     RECT  49.421 2.496 50.677 2.52 ;
     RECT  50.641 3.552 50.677 4.248 ;
     RECT  50.533 40.032 50.677 45 ;
     RECT  50.425 46.32 50.677 48.408 ;
     RECT  49.633 54.048 50.677 55.272 ;
     RECT  50.533 56.736 50.677 67.848 ;
     RECT  50.677 2.496 50.713 4.248 ;
     RECT  50.101 17.424 50.713 21.672 ;
     RECT  50.485 32.496 50.713 32.76 ;
     RECT  48.899 36.624 50.713 36.648 ;
     RECT  50.677 40.032 50.713 48.408 ;
     RECT  49.313 49.488 50.713 49.512 ;
     RECT  50.713 2.496 50.725 4.536 ;
     RECT  50.713 31.728 50.821 32.76 ;
     RECT  50.713 40.032 50.821 49.512 ;
     RECT  50.725 50.736 50.821 50.76 ;
     RECT  50.725 2.496 50.857 5.016 ;
     RECT  50.641 6 50.857 13.32 ;
     RECT  50.497 74.592 50.869 75.144 ;
     RECT  50.869 74.592 50.893 75.48 ;
     RECT  50.713 36.528 50.965 36.648 ;
     RECT  50.857 2.496 51.008 13.32 ;
     RECT  49.525 14.4 51.008 14.808 ;
     RECT  50.713 16.8 51.008 21.672 ;
     RECT  50.821 22.752 51.008 22.776 ;
     RECT  50.209 24.48 51.008 27.72 ;
     RECT  50.713 28.992 51.008 29.016 ;
     RECT  49.997 30.096 51.008 30.744 ;
     RECT  50.821 31.728 51.008 32.856 ;
     RECT  50.857 35.232 51.008 35.256 ;
     RECT  50.965 36.528 51.008 37.08 ;
     RECT  49.957 38.448 51.008 38.472 ;
     RECT  50.821 40.032 51.008 50.76 ;
     RECT  50.137 52.416 51.008 52.44 ;
     RECT  50.677 54.048 51.008 67.848 ;
     RECT  50.137 68.976 51.008 69 ;
     RECT  50.389 72.336 51.008 73.32 ;
     RECT  50.893 74.4 51.008 75.48 ;
     RECT  50.821 76.848 51.008 76.872 ;
     RECT  51.001 78.096 51.008 78.12 ;
     RECT  51.008 2.148 51.112 79.932 ;
     RECT  51.112 2.418 51.304 79.662 ;
     RECT  51.304 68.976 51.329 75.144 ;
     RECT  51.304 60.144 51.365 65.208 ;
     RECT  51.304 34.896 51.437 35.352 ;
     RECT  51.304 23.28 51.443 26.04 ;
     RECT  51.304 14.64 51.509 15.96 ;
     RECT  51.304 36.48 51.509 37.128 ;
     RECT  51.304 67.152 51.683 67.704 ;
     RECT  51.329 68.976 51.725 74.664 ;
     RECT  51.437 35.328 51.731 35.352 ;
     RECT  51.304 54.096 51.833 56.424 ;
     RECT  51.304 17.424 51.905 21.96 ;
     RECT  51.304 48.96 51.905 50.568 ;
     RECT  51.905 48.96 51.941 49.512 ;
     RECT  51.683 67.152 51.941 67.176 ;
     RECT  51.304 8.16 51.977 13.08 ;
     RECT  51.304 31.92 52.049 32.856 ;
     RECT  51.304 42.288 52.049 47.88 ;
     RECT  51.304 52.848 52.121 52.872 ;
     RECT  51.443 23.856 52.193 26.04 ;
     RECT  51.833 54.336 52.273 56.424 ;
     RECT  51.304 76.512 52.297 78.504 ;
     RECT  51.725 69.168 52.333 74.664 ;
     RECT  51.304 41.136 52.369 41.16 ;
     RECT  52.049 42.288 52.369 46.92 ;
     RECT  51.365 60.144 52.369 63 ;
     RECT  52.369 60.144 52.373 63.096 ;
     RECT  52.193 23.856 52.405 25.704 ;
     RECT  52.333 69.168 52.405 75.24 ;
     RECT  52.297 76.368 52.405 78.504 ;
     RECT  51.304 2.784 52.409 6.84 ;
     RECT  51.941 49.296 52.409 49.512 ;
     RECT  51.905 19.008 52.445 21.96 ;
     RECT  52.049 32.16 52.445 32.856 ;
     RECT  52.405 69.168 52.451 78.504 ;
     RECT  51.304 59.088 52.469 59.112 ;
     RECT  52.373 60.144 52.469 61.368 ;
     RECT  51.304 38.4 52.477 38.76 ;
     RECT  51.304 57.504 52.501 57.576 ;
     RECT  52.501 57.504 52.513 58.008 ;
     RECT  52.513 57.024 52.549 58.008 ;
     RECT  52.469 59.088 52.549 61.368 ;
     RECT  52.409 3.6 52.553 6.84 ;
     RECT  52.273 54.336 52.553 55.992 ;
     RECT  52.549 57.024 52.553 61.368 ;
     RECT  52.373 62.496 52.553 63.096 ;
     RECT  51.905 17.424 52.589 17.88 ;
     RECT  52.477 38.4 52.589 39.048 ;
     RECT  51.304 33.84 52.621 33.864 ;
     RECT  52.621 33.84 52.661 34.776 ;
     RECT  52.553 57.024 52.661 59.112 ;
     RECT  51.977 8.16 52.693 8.808 ;
     RECT  52.451 76.176 52.693 78.504 ;
     RECT  51.509 14.64 52.729 14.808 ;
     RECT  51.509 15.936 52.729 15.96 ;
     RECT  52.369 41.136 52.733 46.92 ;
     RECT  52.451 69.168 52.801 75.048 ;
     RECT  52.405 23.328 52.805 25.704 ;
     RECT  52.661 57.024 52.841 58.728 ;
     RECT  52.553 6 52.877 6.84 ;
     RECT  52.553 54.336 52.913 55.32 ;
     RECT  52.801 69.024 52.945 75.048 ;
     RECT  52.733 41.136 52.949 44.472 ;
     RECT  52.661 34.752 52.985 34.776 ;
     RECT  52.729 14.64 53.017 14.856 ;
     RECT  51.304 29.808 53.017 30.504 ;
     RECT  51.365 64.56 53.017 65.208 ;
     RECT  52.913 54.336 53.084 54.744 ;
     RECT  53.017 29.664 53.089 30.504 ;
     RECT  52.729 53.04 53.089 53.064 ;
     RECT  53.084 54.048 53.089 54.744 ;
     RECT  52.693 7.92 53.093 8.808 ;
     RECT  51.977 9.792 53.093 13.08 ;
     RECT  53.089 53.04 53.125 54.744 ;
     RECT  52.805 25.68 53.129 25.704 ;
     RECT  51.509 36.48 53.129 37.08 ;
     RECT  52.949 41.664 53.165 44.472 ;
     RECT  52.553 3.6 53.201 5.016 ;
     RECT  53.129 36.528 53.233 37.08 ;
     RECT  52.589 38.4 53.233 38.76 ;
     RECT  52.589 17.616 53.269 17.88 ;
     RECT  52.445 19.008 53.269 21.528 ;
     RECT  53.125 52.32 53.273 54.744 ;
     RECT  53.093 10.08 53.305 13.08 ;
     RECT  53.017 14.448 53.305 14.856 ;
     RECT  52.553 60.144 53.377 61.368 ;
     RECT  52.553 62.496 53.377 63 ;
     RECT  52.841 57.024 53.417 57.24 ;
     RECT  53.201 3.6 53.449 3.624 ;
     RECT  53.305 10.08 53.453 14.856 ;
     RECT  52.945 2.304 53.461 2.328 ;
     RECT  53.449 3.408 53.461 3.624 ;
     RECT  53.089 29.616 53.461 30.504 ;
     RECT  53.273 52.32 53.461 54.072 ;
     RECT  53.017 64.032 53.485 65.208 ;
     RECT  53.461 2.304 53.507 3.624 ;
     RECT  52.909 27.744 53.516 27.768 ;
     RECT  52.729 15.936 53.525 16.536 ;
     RECT  53.461 51.888 53.548 54.072 ;
     RECT  53.516 27.744 53.557 28.2 ;
     RECT  53.461 29.52 53.557 30.504 ;
     RECT  52.445 32.16 53.593 32.472 ;
     RECT  53.269 67.824 53.593 67.848 ;
     RECT  52.945 68.976 53.593 75.048 ;
     RECT  53.557 27.168 53.603 28.2 ;
     RECT  53.557 29.52 53.603 30.792 ;
     RECT  52.733 45.744 53.629 46.92 ;
     RECT  52.877 6.816 53.665 6.84 ;
     RECT  53.377 60.144 53.665 63 ;
     RECT  53.453 10.08 53.669 13.656 ;
     RECT  53.269 17.616 53.701 21.528 ;
     RECT  53.603 27.168 53.741 27.768 ;
     RECT  52.693 76.176 53.773 78.552 ;
     RECT  52.409 49.296 53.809 49.368 ;
     RECT  53.165 41.664 53.813 44.424 ;
     RECT  53.665 6.816 53.881 7.272 ;
     RECT  53.453 14.736 53.881 14.856 ;
     RECT  53.809 49.296 53.881 49.512 ;
     RECT  53.593 67.824 53.921 75.048 ;
     RECT  53.921 67.824 53.939 73.32 ;
     RECT  53.881 14.736 53.989 14.952 ;
     RECT  53.593 31.872 53.989 32.472 ;
     RECT  53.813 41.664 53.989 42.216 ;
     RECT  53.525 16.512 54.025 16.536 ;
     RECT  53.773 76.176 54.025 78.744 ;
     RECT  53.669 12.528 54.035 13.656 ;
     RECT  53.603 29.616 54.037 30.792 ;
     RECT  53.989 31.824 54.037 32.472 ;
     RECT  54.037 29.616 54.083 32.472 ;
     RECT  54.025 16.512 54.085 16.584 ;
     RECT  53.701 17.616 54.085 21.96 ;
     RECT  52.805 23.328 54.097 24.504 ;
     RECT  54.025 76.176 54.097 78.84 ;
     RECT  54.083 29.616 54.124 31.848 ;
     RECT  53.881 48.48 54.133 49.512 ;
     RECT  51.905 50.544 54.133 50.568 ;
     RECT  53.665 60.048 54.169 63 ;
     RECT  53.485 64.032 54.169 66.12 ;
     RECT  54.097 76.176 54.169 78.936 ;
     RECT  54.085 16.512 54.172 21.96 ;
     RECT  53.921 74.304 54.173 75.048 ;
     RECT  53.093 8.688 54.205 8.808 ;
     RECT  53.669 10.08 54.205 11.496 ;
     RECT  53.813 43.296 54.205 44.424 ;
     RECT  53.629 45.744 54.205 47.064 ;
     RECT  54.173 74.496 54.205 75.048 ;
     RECT  54.169 76.032 54.205 78.936 ;
     RECT  53.548 52.416 54.217 54.072 ;
     RECT  53.507 2.592 54.241 3.624 ;
     RECT  53.665 5.088 54.241 5.112 ;
     RECT  54.205 43.296 54.241 47.064 ;
     RECT  54.133 48.48 54.241 50.568 ;
     RECT  54.205 74.496 54.241 78.936 ;
     RECT  54.205 8.688 54.245 11.496 ;
     RECT  54.097 23.328 54.245 25.08 ;
     RECT  54.241 43.296 54.281 50.568 ;
     RECT  53.939 67.824 54.281 73.128 ;
     RECT  53.989 41.232 54.313 42.216 ;
     RECT  54.124 29.616 54.317 30.792 ;
     RECT  54.217 52.704 54.317 54.072 ;
     RECT  54.281 67.824 54.349 69.192 ;
     RECT  53.989 14.736 54.353 15.288 ;
     RECT  53.417 57.216 54.385 57.24 ;
     RECT  52.841 58.704 54.385 58.728 ;
     RECT  54.281 43.296 54.419 50.136 ;
     RECT  53.881 6.624 54.425 7.272 ;
     RECT  54.353 14.736 54.425 14.856 ;
     RECT  54.169 60.048 54.425 66.12 ;
     RECT  54.172 17.856 54.457 21.96 ;
     RECT  54.245 23.328 54.457 24.648 ;
     RECT  53.233 36.528 54.461 38.76 ;
     RECT  54.425 14.832 54.497 14.856 ;
     RECT  54.245 8.688 54.533 11.16 ;
     RECT  54.385 57.216 54.533 58.728 ;
     RECT  54.457 17.856 54.541 24.648 ;
     RECT  54.317 52.704 54.605 52.728 ;
     RECT  54.349 67.152 54.629 69.192 ;
     RECT  54.425 6.624 54.637 6.84 ;
     RECT  54.317 30.768 54.641 30.792 ;
     RECT  54.172 16.512 54.661 16.584 ;
     RECT  54.541 17.856 54.707 22.488 ;
     RECT  54.317 29.616 54.707 29.688 ;
     RECT  54.629 66.72 54.707 69.192 ;
     RECT  54.241 2.592 54.713 5.112 ;
     RECT  54.533 8.688 54.713 10.632 ;
     RECT  54.461 36.528 54.713 38.472 ;
     RECT  54.425 60.048 54.713 65.64 ;
     RECT  54.707 66.72 54.713 66.744 ;
     RECT  54.713 8.688 54.749 10.344 ;
     RECT  54.241 74.496 54.749 79.032 ;
     RECT  54.713 62.016 54.785 65.64 ;
     RECT  54.281 70.848 54.785 73.128 ;
     RECT  54.533 57.408 54.821 58.728 ;
     RECT  54.785 62.112 54.821 65.64 ;
     RECT  54.713 3.312 54.853 5.112 ;
     RECT  54.637 6.576 54.853 6.84 ;
     RECT  54.419 43.296 54.857 48.84 ;
     RECT  54.853 3.312 54.899 6.84 ;
     RECT  54.857 46.752 54.929 48.84 ;
     RECT  54.821 62.112 54.929 65.4 ;
     RECT  54.124 31.824 54.965 31.848 ;
     RECT  54.713 60.048 54.965 60.984 ;
     RECT  54.749 8.688 54.995 9.048 ;
     RECT  54.965 60.672 55.001 60.984 ;
     RECT  54.929 62.112 55.001 64.056 ;
     RECT  54.749 74.544 55.001 79.032 ;
     RECT  54.929 65.136 55.037 65.4 ;
     RECT  54.929 46.8 55.073 48.84 ;
     RECT  54.097 55.776 55.073 55.8 ;
     RECT  55.001 77.616 55.105 79.032 ;
     RECT  54.785 72.96 55.141 73.128 ;
     RECT  54.899 3.312 55.145 4.584 ;
     RECT  55.105 77.616 55.177 79.176 ;
     RECT  54.661 16.368 55.181 16.584 ;
     RECT  55.001 74.544 55.217 76.2 ;
     RECT  54.541 23.52 55.253 24.648 ;
     RECT  55.181 16.368 55.321 16.392 ;
     RECT  54.035 13.104 55.325 13.656 ;
     RECT  55.105 32.976 55.325 33 ;
     RECT  54.857 43.296 55.325 45.768 ;
     RECT  55.217 74.592 55.325 76.2 ;
     RECT  55.177 77.616 55.325 79.224 ;
     RECT  54.313 40.944 55.465 42.216 ;
     RECT  55.325 43.296 55.465 45.576 ;
     RECT  54.707 68.352 55.465 69.192 ;
     RECT  54.317 54.048 55.525 54.072 ;
     RECT  54.821 58.128 55.537 58.728 ;
     RECT  55.249 52.464 55.645 52.488 ;
     RECT  55.525 54.048 55.645 54.12 ;
     RECT  54.713 36.528 55.753 37.08 ;
     RECT  54.713 38.4 55.753 38.472 ;
     RECT  55.645 52.464 55.753 52.776 ;
     RECT  55.645 53.76 55.753 54.12 ;
     RECT  55.753 36.528 55.789 38.472 ;
     RECT  53.741 27.168 55.813 27.624 ;
     RECT  55.393 35.088 55.861 35.112 ;
     RECT  54.785 70.848 55.969 71.736 ;
     RECT  55.001 62.112 56.005 63.576 ;
     RECT  56.005 31.728 56.041 31.752 ;
     RECT  55.537 58.128 56.077 58.92 ;
     RECT  55.465 68.352 56.077 69.72 ;
     RECT  56.077 57.6 56.101 58.92 ;
     RECT  55.813 26.64 56.113 27.624 ;
     RECT  55.285 29.088 56.113 29.112 ;
     RECT  55.429 30.144 56.149 30.168 ;
     RECT  56.041 31.728 56.149 32.328 ;
     RECT  55.325 13.104 56.185 13.608 ;
     RECT  55.753 66.48 56.221 66.504 ;
     RECT  56.077 68.208 56.221 69.72 ;
     RECT  54.707 18.048 56.293 22.488 ;
     RECT  55.253 23.856 56.293 24.648 ;
     RECT  55.789 36.528 56.293 39.24 ;
     RECT  56.221 66.48 56.293 69.72 ;
     RECT  55.969 70.848 56.293 71.832 ;
     RECT  56.197 7.92 56.329 7.944 ;
     RECT  54.995 9.024 56.329 9.048 ;
     RECT  55.141 56.064 56.365 56.088 ;
     RECT  54.899 5.76 56.401 6.84 ;
     RECT  56.113 26.64 56.401 29.112 ;
     RECT  55.897 2.256 56.408 2.28 ;
     RECT  55.145 3.312 56.408 3.624 ;
     RECT  56.401 5.28 56.408 6.84 ;
     RECT  56.329 7.92 56.408 9.048 ;
     RECT  54.749 10.32 56.408 10.344 ;
     RECT  56.185 12.576 56.408 13.608 ;
     RECT  55.321 15.408 56.408 16.392 ;
     RECT  56.293 18.048 56.408 24.648 ;
     RECT  56.401 25.728 56.408 29.112 ;
     RECT  56.149 30.144 56.408 32.328 ;
     RECT  55.861 34.752 56.408 35.544 ;
     RECT  56.293 36.528 56.408 39.528 ;
     RECT  55.465 40.944 56.408 45.576 ;
     RECT  55.073 46.8 56.408 46.824 ;
     RECT  55.073 47.856 56.408 48.84 ;
     RECT  54.419 50.112 56.408 50.136 ;
     RECT  55.753 52.464 56.408 54.12 ;
     RECT  56.365 56.064 56.408 56.52 ;
     RECT  56.101 57.6 56.408 59.448 ;
     RECT  55.001 60.96 56.408 60.984 ;
     RECT  56.005 62.016 56.408 63.576 ;
     RECT  55.037 65.136 56.408 65.16 ;
     RECT  56.293 66.48 56.408 71.832 ;
     RECT  55.141 72.96 56.408 73.272 ;
     RECT  55.325 74.592 56.408 76.056 ;
     RECT  55.325 78.384 56.408 79.224 ;
     RECT  56.408 2.148 56.512 79.932 ;
     RECT  56.512 2.256 56.704 79.662 ;
     RECT  56.704 41.04 56.729 43.656 ;
     RECT  56.704 5.28 56.765 7.416 ;
     RECT  56.704 35.52 56.765 37.08 ;
     RECT  56.704 44.64 56.765 46.824 ;
     RECT  56.704 21.216 56.801 23.352 ;
     RECT  56.704 59.568 56.801 62.04 ;
     RECT  56.704 72.768 56.819 74.616 ;
     RECT  56.704 38.208 56.837 38.472 ;
     RECT  56.765 5.76 56.873 7.416 ;
     RECT  56.704 12.528 56.873 13.128 ;
     RECT  56.704 29.808 56.873 32.328 ;
     RECT  56.765 35.52 56.873 36.936 ;
     RECT  56.837 38.256 56.945 38.472 ;
     RECT  56.704 10.56 56.981 10.92 ;
     RECT  56.704 66.144 56.981 71.784 ;
     RECT  56.704 2.256 57.053 3.384 ;
     RECT  56.873 32.016 57.053 32.328 ;
     RECT  56.873 35.904 57.053 36.936 ;
     RECT  56.801 21.216 57.089 23.304 ;
     RECT  56.873 29.808 57.089 30.936 ;
     RECT  56.704 50.112 57.089 50.136 ;
     RECT  56.704 51.6 57.089 57.624 ;
     RECT  56.873 12.528 57.125 13.08 ;
     RECT  56.945 38.4 57.161 38.472 ;
     RECT  57.089 29.808 57.197 29.832 ;
     RECT  57.053 36.24 57.197 36.936 ;
     RECT  57.161 38.4 57.233 38.424 ;
     RECT  56.729 41.04 57.233 43.128 ;
     RECT  56.765 44.64 57.233 46.776 ;
     RECT  56.981 70.512 57.233 71.784 ;
     RECT  56.801 59.568 57.305 61.224 ;
     RECT  56.981 66.144 57.305 69.528 ;
     RECT  56.819 72.768 57.305 73.272 ;
     RECT  56.704 8.544 57.341 9.048 ;
     RECT  56.981 10.56 57.341 10.824 ;
     RECT  57.305 59.568 57.413 60.792 ;
     RECT  56.704 17.664 57.485 17.688 ;
     RECT  56.704 64.896 57.521 65.16 ;
     RECT  56.704 63.216 57.557 63.576 ;
     RECT  57.089 21.216 57.593 22.488 ;
     RECT  57.233 70.512 57.629 71.736 ;
     RECT  57.197 36.24 57.665 36.552 ;
     RECT  57.341 10.8 57.701 10.824 ;
     RECT  57.089 53.904 57.733 57.624 ;
     RECT  56.704 77.568 57.733 77.592 ;
     RECT  56.704 78.672 57.733 79.224 ;
     RECT  57.665 36.24 57.737 36.264 ;
     RECT  57.593 21.456 57.773 22.488 ;
     RECT  57.733 53.904 57.801 57.912 ;
     RECT  57.053 2.832 57.809 3.384 ;
     RECT  56.704 14.208 57.836 14.232 ;
     RECT  56.704 15.6 57.836 16.392 ;
     RECT  57.801 54.288 57.877 57.912 ;
     RECT  57.836 14.208 57.923 16.392 ;
     RECT  56.704 19.008 57.973 19.896 ;
     RECT  57.877 54.288 57.985 58.152 ;
     RECT  57.413 59.568 57.985 59.592 ;
     RECT  57.913 17.616 58.019 17.64 ;
     RECT  57.089 51.6 58.021 52.776 ;
     RECT  57.053 32.304 58.057 32.328 ;
     RECT  56.704 33.504 58.057 33.528 ;
     RECT  57.973 18.672 58.061 19.896 ;
     RECT  57.733 77.568 58.061 79.224 ;
     RECT  56.704 48.48 58.097 48.984 ;
     RECT  57.985 54.288 58.097 59.592 ;
     RECT  57.521 64.896 58.117 64.92 ;
     RECT  57.809 2.832 58.165 3.192 ;
     RECT  56.704 76.32 58.165 76.344 ;
     RECT  57.125 13.056 58.169 13.08 ;
     RECT  58.057 32.304 58.201 33.528 ;
     RECT  58.021 51.264 58.201 52.776 ;
     RECT  58.117 64.368 58.204 64.92 ;
     RECT  57.305 66.144 58.237 66.552 ;
     RECT  57.305 72.768 58.237 72.984 ;
     RECT  56.873 5.76 58.277 5.784 ;
     RECT  57.923 14.208 58.277 14.232 ;
     RECT  57.923 15.6 58.277 16.392 ;
     RECT  58.061 77.76 58.277 79.224 ;
     RECT  58.061 19.44 58.309 19.896 ;
     RECT  56.704 24.624 58.309 28.488 ;
     RECT  58.097 48.48 58.309 48.648 ;
     RECT  58.309 23.856 58.313 28.488 ;
     RECT  57.089 30.816 58.313 30.936 ;
     RECT  57.233 41.232 58.345 43.128 ;
     RECT  57.233 44.688 58.345 46.776 ;
     RECT  57.341 8.544 58.453 8.568 ;
     RECT  58.201 32.208 58.453 33.528 ;
     RECT  58.237 66.096 58.453 66.552 ;
     RECT  58.345 41.232 58.457 46.776 ;
     RECT  58.313 30.912 58.489 30.936 ;
     RECT  58.453 32.064 58.489 33.528 ;
     RECT  57.305 68.352 58.493 69.528 ;
     RECT  58.313 23.856 58.525 28.392 ;
     RECT  57.805 29.664 58.525 29.688 ;
     RECT  56.819 74.592 58.525 74.616 ;
     RECT  58.165 75.648 58.525 76.344 ;
     RECT  58.165 49.632 58.549 49.656 ;
     RECT  58.457 41.232 58.595 43.896 ;
     RECT  58.525 29.664 58.597 29.784 ;
     RECT  58.097 59.568 58.597 59.592 ;
     RECT  57.413 60.768 58.597 60.792 ;
     RECT  58.097 54.288 58.601 58.152 ;
     RECT  57.985 4.512 58.625 4.536 ;
     RECT  56.873 6.816 58.633 7.416 ;
     RECT  58.453 8.544 58.633 9.144 ;
     RECT  58.549 49.632 58.636 50.04 ;
     RECT  58.489 30.912 58.637 33.528 ;
     RECT  58.633 6.816 58.673 9.144 ;
     RECT  58.277 77.76 58.673 79.128 ;
     RECT  58.625 4.512 58.691 5.16 ;
     RECT  58.453 66.096 58.691 66.744 ;
     RECT  58.597 59.568 58.693 60.792 ;
     RECT  58.691 5.136 58.709 5.16 ;
     RECT  58.277 15.6 58.709 15.96 ;
     RECT  58.673 6.816 58.745 7.896 ;
     RECT  58.309 19.44 58.745 20.424 ;
     RECT  58.457 44.88 58.745 46.776 ;
     RECT  58.745 7.44 58.781 7.896 ;
     RECT  58.525 23.136 58.781 28.392 ;
     RECT  58.493 68.352 58.781 69.288 ;
     RECT  58.201 51.264 58.849 53.064 ;
     RECT  58.601 54.288 58.849 54.312 ;
     RECT  58.637 31.776 58.853 33.528 ;
     RECT  58.601 55.392 58.853 58.152 ;
     RECT  58.781 68.4 58.853 69.288 ;
     RECT  58.204 64.416 58.885 64.92 ;
     RECT  58.885 64.416 58.889 65.016 ;
     RECT  58.853 68.4 58.889 68.472 ;
     RECT  58.745 19.872 58.925 20.424 ;
     RECT  58.781 24.624 58.925 28.392 ;
     RECT  58.693 59.568 58.925 61.032 ;
     RECT  57.769 62.016 58.931 62.04 ;
     RECT  58.165 2.256 58.961 3.192 ;
     RECT  58.745 44.88 58.961 44.904 ;
     RECT  58.745 46.128 58.961 46.776 ;
     RECT  58.925 59.568 58.961 60.696 ;
     RECT  58.889 64.992 58.969 65.016 ;
     RECT  57.773 21.456 58.993 21.624 ;
     RECT  58.237 72.528 58.997 72.984 ;
     RECT  58.925 24.624 59.033 26.04 ;
     RECT  58.309 47.904 59.065 48.648 ;
     RECT  58.781 23.136 59.137 23.16 ;
     RECT  58.691 66.192 59.141 66.744 ;
     RECT  58.597 29.616 59.173 29.784 ;
     RECT  58.669 17.664 59.177 17.688 ;
     RECT  59.065 47.904 59.221 49.08 ;
     RECT  58.673 77.76 59.245 78.936 ;
     RECT  58.997 72.96 59.249 72.984 ;
     RECT  59.137 39.312 59.267 39.336 ;
     RECT  58.595 41.52 59.267 43.896 ;
     RECT  58.961 46.128 59.267 46.152 ;
     RECT  58.849 51.264 59.321 54.312 ;
     RECT  58.961 2.784 59.389 3.192 ;
     RECT  59.267 41.52 59.393 43.368 ;
     RECT  58.525 74.592 59.425 76.344 ;
     RECT  59.245 77.568 59.429 78.936 ;
     RECT  59.389 2.784 59.465 3.96 ;
     RECT  58.993 21.456 59.497 21.72 ;
     RECT  59.137 22.8 59.497 23.16 ;
     RECT  59.173 29.568 59.497 29.784 ;
     RECT  58.853 32.016 59.497 33.528 ;
     RECT  59.033 24.624 59.501 25.8 ;
     RECT  58.853 55.488 59.501 58.152 ;
     RECT  57.629 70.512 59.501 71.352 ;
     RECT  59.321 51.264 59.509 53.064 ;
     RECT  58.925 27.168 59.533 28.392 ;
     RECT  59.497 29.568 59.533 29.928 ;
     RECT  57.557 63.216 59.533 63.24 ;
     RECT  59.393 41.52 59.537 43.272 ;
     RECT  59.321 54.288 59.537 54.312 ;
     RECT  59.509 50.784 59.555 53.064 ;
     RECT  58.925 20.064 59.605 20.424 ;
     RECT  59.497 21.456 59.605 23.16 ;
     RECT  59.501 58.128 59.605 58.152 ;
     RECT  59.555 51.936 59.609 53.064 ;
     RECT  59.429 77.568 59.609 78.84 ;
     RECT  59.425 74.592 59.717 76.536 ;
     RECT  59.555 50.784 59.749 50.808 ;
     RECT  59.497 32.016 59.785 34.392 ;
     RECT  59.609 77.568 59.789 78.696 ;
     RECT  59.605 58.128 59.797 58.44 ;
     RECT  58.961 59.568 59.797 59.64 ;
     RECT  59.221 47.856 59.821 49.08 ;
     RECT  59.749 50.064 59.821 50.808 ;
     RECT  59.501 55.488 59.845 57.144 ;
     RECT  58.889 68.448 59.845 68.472 ;
     RECT  59.717 74.592 59.845 76.344 ;
     RECT  59.101 18.72 59.857 18.744 ;
     RECT  59.501 70.56 59.891 71.352 ;
     RECT  59.821 47.856 59.893 50.808 ;
     RECT  58.709 15.936 59.897 15.96 ;
     RECT  59.857 18.72 59.897 18.936 ;
     RECT  59.605 20.064 59.897 23.16 ;
     RECT  59.497 9.504 59.933 9.528 ;
     RECT  59.785 32.016 59.933 34.632 ;
     RECT  59.893 47.328 60.005 50.808 ;
     RECT  59.891 70.56 60.005 70.68 ;
     RECT  59.845 55.248 60.041 57.144 ;
     RECT  59.845 74.4 60.041 76.344 ;
     RECT  59.501 25.104 60.044 25.8 ;
     RECT  59.533 27.168 60.044 29.928 ;
     RECT  59.797 58.128 60.073 59.64 ;
     RECT  58.961 60.672 60.073 60.696 ;
     RECT  59.537 41.52 60.113 43.128 ;
     RECT  59.804 44.352 60.113 44.376 ;
     RECT  59.845 68.448 60.113 69.336 ;
     RECT  60.041 74.736 60.149 76.344 ;
     RECT  59.897 18.816 60.181 18.936 ;
     RECT  59.897 20.064 60.181 21.672 ;
     RECT  60.041 55.248 60.185 57.096 ;
     RECT  60.149 75.84 60.185 76.344 ;
     RECT  60.181 18.816 60.221 21.672 ;
     RECT  59.965 72 60.221 72.024 ;
     RECT  59.221 40.512 60.253 40.536 ;
     RECT  60.113 41.52 60.253 42.504 ;
     RECT  60.073 58.128 60.253 60.696 ;
     RECT  59.641 12.528 60.361 12.552 ;
     RECT  60.253 40.512 60.365 42.504 ;
     RECT  59.497 17.04 60.397 17.064 ;
     RECT  59.533 62.736 60.397 63.24 ;
     RECT  60.221 19.392 60.401 21.672 ;
     RECT  59.789 77.952 60.419 78.696 ;
     RECT  59.141 66.192 60.469 66.216 ;
     RECT  60.401 19.392 60.473 21.528 ;
     RECT  60.185 55.248 60.473 56.808 ;
     RECT  60.005 47.328 60.476 48.648 ;
     RECT  60.253 58.128 60.509 61.32 ;
     RECT  59.609 51.936 60.545 53.016 ;
     RECT  60.149 74.736 60.545 74.76 ;
     RECT  59.897 22.752 60.565 23.16 ;
     RECT  60.005 70.56 60.572 70.632 ;
     RECT  60.361 12.528 60.613 13.416 ;
     RECT  60.044 25.104 60.613 29.928 ;
     RECT  60.001 36.72 60.613 36.744 ;
     RECT  60.572 69.936 60.659 70.632 ;
     RECT  60.185 75.84 60.689 75.864 ;
     RECT  60.545 52.032 60.721 53.016 ;
     RECT  60.613 12.528 60.725 13.752 ;
     RECT  59.933 32.064 60.797 34.632 ;
     RECT  60.365 41.808 60.797 42.504 ;
     RECT  60.613 25.104 60.829 30.744 ;
     RECT  60.473 55.248 60.829 55.752 ;
     RECT  60.469 66.192 60.829 66.744 ;
     RECT  59.465 2.784 60.865 2.808 ;
     RECT  59.465 3.936 60.865 3.96 ;
     RECT  60.797 32.496 60.865 34.632 ;
     RECT  60.397 16.272 60.937 17.064 ;
     RECT  60.365 40.512 61.004 40.536 ;
     RECT  60.397 64.32 61.045 64.344 ;
     RECT  60.829 66.048 61.045 66.744 ;
     RECT  60.829 78.912 61.093 78.936 ;
     RECT  60.829 25.008 61.117 30.744 ;
     RECT  60.613 36.72 61.225 37.608 ;
     RECT  60.937 16.272 61.261 17.112 ;
     RECT  61.117 25.008 61.261 30.936 ;
     RECT  60.721 52.032 61.261 53.4 ;
     RECT  60.829 54.72 61.261 55.752 ;
     RECT  61.297 18.768 61.405 18.792 ;
     RECT  61.369 43.536 61.405 43.56 ;
     RECT  60.797 42.048 61.441 42.504 ;
     RECT  61.405 43.536 61.441 43.896 ;
     RECT  60.469 11.52 61.477 11.544 ;
     RECT  61.405 18.144 61.477 18.792 ;
     RECT  60.473 21.504 61.477 21.528 ;
     RECT  61.004 39.888 61.477 40.536 ;
     RECT  60.397 62.64 61.477 63.24 ;
     RECT  61.045 64.32 61.477 66.744 ;
     RECT  60.473 20.064 61.549 20.088 ;
     RECT  61.477 21.504 61.549 21.672 ;
     RECT  60.725 13.056 61.585 13.752 ;
     RECT  60.565 22.752 61.585 23.832 ;
     RECT  61.261 25.008 61.585 31.176 ;
     RECT  61.225 36.048 61.585 37.608 ;
     RECT  61.045 38.64 61.585 38.664 ;
     RECT  61.153 7.92 61.621 7.944 ;
     RECT  61.405 9.072 61.621 9.096 ;
     RECT  60.865 2.784 61.657 3.96 ;
     RECT  61.261 15.312 61.669 17.112 ;
     RECT  61.477 18.144 61.669 18.84 ;
     RECT  60.473 56.736 61.669 56.808 ;
     RECT  60.509 58.128 61.669 60.984 ;
     RECT  61.621 7.92 61.693 9.096 ;
     RECT  61.585 13.056 61.729 14.04 ;
     RECT  60.005 50.544 61.801 50.808 ;
     RECT  61.657 2.784 61.808 4.776 ;
     RECT  61.693 7.632 61.808 9.096 ;
     RECT  61.477 11.52 61.808 11.976 ;
     RECT  61.729 13.056 61.808 14.136 ;
     RECT  61.669 15.312 61.808 18.84 ;
     RECT  61.549 20.064 61.808 21.672 ;
     RECT  61.585 22.752 61.808 31.176 ;
     RECT  60.865 32.496 61.808 34.776 ;
     RECT  61.585 36.048 61.808 38.664 ;
     RECT  61.477 39.888 61.808 40.584 ;
     RECT  61.441 42.048 61.808 43.896 ;
     RECT  59.793 45.696 61.808 45.72 ;
     RECT  60.476 47.184 61.808 48.648 ;
     RECT  61.801 49.872 61.808 50.808 ;
     RECT  61.261 52.032 61.808 55.752 ;
     RECT  61.669 56.736 61.808 60.984 ;
     RECT  61.477 62.64 61.808 66.744 ;
     RECT  60.613 68.112 61.808 68.136 ;
     RECT  60.659 70.608 61.808 70.632 ;
     RECT  61.477 74.592 61.808 74.616 ;
     RECT  61.093 78.912 61.808 79.416 ;
     RECT  61.808 2.148 61.912 79.932 ;
     RECT  61.912 2.418 62.104 79.662 ;
     RECT  62.104 7.92 62.165 7.944 ;
     RECT  62.104 13.104 62.165 13.704 ;
     RECT  62.104 33.024 62.237 33.576 ;
     RECT  62.104 40.128 62.237 41.16 ;
     RECT  62.104 65.136 62.265 66.744 ;
     RECT  62.104 19.968 62.309 27.816 ;
     RECT  62.165 13.104 62.345 13.416 ;
     RECT  62.104 29.76 62.345 29.784 ;
     RECT  62.104 42.192 62.345 45.72 ;
     RECT  62.104 63.072 62.435 63.912 ;
     RECT  62.104 70.608 62.435 70.68 ;
     RECT  62.104 75.024 62.435 75.048 ;
     RECT  62.435 63.072 62.453 63.864 ;
     RECT  62.104 78.672 62.461 78.744 ;
     RECT  62.104 34.752 62.489 34.776 ;
     RECT  62.104 46.752 62.525 51.336 ;
     RECT  62.309 21.408 62.561 27.816 ;
     RECT  62.104 31.344 62.669 31.512 ;
     RECT  62.237 33.12 62.669 33.576 ;
     RECT  62.104 37.584 62.705 38.76 ;
     RECT  62.104 52.416 62.741 61.656 ;
     RECT  62.453 63.072 62.741 63.816 ;
     RECT  62.265 65.136 62.741 65.688 ;
     RECT  62.461 78.72 62.741 78.744 ;
     RECT  62.104 14.88 62.777 17.064 ;
     RECT  62.705 37.584 62.777 37.608 ;
     RECT  62.104 2.784 62.813 4.776 ;
     RECT  62.345 13.152 62.813 13.416 ;
     RECT  62.561 21.408 62.813 25.752 ;
     RECT  62.237 40.56 62.813 41.16 ;
     RECT  62.345 42.192 62.849 45.672 ;
     RECT  62.741 55.392 62.849 61.656 ;
     RECT  62.849 43.536 62.885 45.672 ;
     RECT  62.525 47.328 62.885 51.336 ;
     RECT  62.885 43.536 62.921 45.528 ;
     RECT  62.885 47.328 62.957 51.24 ;
     RECT  62.957 49.008 62.993 51.24 ;
     RECT  62.777 15.504 63.011 17.064 ;
     RECT  62.705 38.736 63.029 38.76 ;
     RECT  62.849 42.192 63.029 42.312 ;
     RECT  62.104 9.936 63.097 9.96 ;
     RECT  63.011 15.504 63.101 16.776 ;
     RECT  62.813 22.704 63.101 25.752 ;
     RECT  62.813 2.784 63.205 3.336 ;
     RECT  62.104 73.632 63.209 73.656 ;
     RECT  62.669 31.488 63.245 31.512 ;
     RECT  62.741 52.416 63.245 53.784 ;
     RECT  63.101 15.504 63.281 16.392 ;
     RECT  62.104 11.952 63.349 11.976 ;
     RECT  62.813 13.152 63.349 13.32 ;
     RECT  63.308 37.056 63.349 37.08 ;
     RECT  63.101 23.568 63.353 25.752 ;
     RECT  63.281 15.504 63.389 16.296 ;
     RECT  62.993 49.008 63.389 50.712 ;
     RECT  63.205 2.64 63.425 3.336 ;
     RECT  62.265 66.72 63.425 66.744 ;
     RECT  63.389 15.936 63.461 16.296 ;
     RECT  63.245 52.464 63.461 53.784 ;
     RECT  63.097 9.936 63.493 10.104 ;
     RECT  62.669 33.552 63.497 33.576 ;
     RECT  62.309 19.968 63.529 19.992 ;
     RECT  62.104 18.192 63.569 18.216 ;
     RECT  63.529 19.344 63.569 19.992 ;
     RECT  63.349 36.096 63.569 37.08 ;
     RECT  62.741 63.072 63.601 63.288 ;
     RECT  63.389 49.008 63.605 50.664 ;
     RECT  63.461 52.656 63.605 53.784 ;
     RECT  63.425 2.784 63.641 3.336 ;
     RECT  62.813 21.408 63.673 21.528 ;
     RECT  63.605 49.008 63.677 50.616 ;
     RECT  63.601 62.64 63.685 63.288 ;
     RECT  62.561 26.736 63.745 27.816 ;
     RECT  63.493 9.024 63.749 10.104 ;
     RECT  63.353 23.568 63.749 25.08 ;
     RECT  62.849 57.84 63.749 61.656 ;
     RECT  63.673 21.216 63.817 21.528 ;
     RECT  62.435 70.656 63.817 70.68 ;
     RECT  63.605 52.656 63.821 52.92 ;
     RECT  63.685 63.072 63.827 63.288 ;
     RECT  63.817 70.464 63.853 70.68 ;
     RECT  62.104 71.856 63.853 71.88 ;
     RECT  63.349 11.952 63.857 13.32 ;
     RECT  63.857 12.336 63.929 13.32 ;
     RECT  63.749 61.632 63.929 61.656 ;
     RECT  62.957 47.328 63.961 47.88 ;
     RECT  63.749 23.568 64.001 24.84 ;
     RECT  62.813 41.136 64.001 41.16 ;
     RECT  63.569 37.056 64.069 37.08 ;
     RECT  63.961 46.752 64.109 47.88 ;
     RECT  63.677 49.872 64.109 50.616 ;
     RECT  63.749 10.08 64.145 10.104 ;
     RECT  63.929 12.336 64.145 12.504 ;
     RECT  63.749 57.84 64.145 60.6 ;
     RECT  63.817 21.216 64.177 22.008 ;
     RECT  63.821 52.8 64.217 52.92 ;
     RECT  63.641 3.264 64.253 3.336 ;
     RECT  63.745 31.296 64.325 31.32 ;
     RECT  63.827 63.168 64.325 63.288 ;
     RECT  63.169 64.992 64.325 65.016 ;
     RECT  63.029 42.192 64.393 42.216 ;
     RECT  62.921 43.536 64.393 45 ;
     RECT  64.069 37.056 64.397 37.896 ;
     RECT  64.145 12.336 64.433 12.36 ;
     RECT  64.109 50.592 64.433 50.616 ;
     RECT  63.781 77.376 64.433 77.4 ;
     RECT  63.637 32.496 64.501 32.52 ;
     RECT  63.493 39.168 64.501 39.192 ;
     RECT  64.501 32.448 64.502 32.52 ;
     RECT  62.104 67.968 64.537 68.28 ;
     RECT  64.501 39.168 64.541 39.384 ;
     RECT  64.537 67.776 64.573 68.28 ;
     RECT  64.393 42.192 64.577 45 ;
     RECT  62.849 55.392 64.609 56.808 ;
     RECT  64.145 57.84 64.609 59.976 ;
     RECT  63.745 26.736 64.645 28.488 ;
     RECT  64.217 52.896 64.645 52.92 ;
     RECT  63.133 4.896 64.681 4.92 ;
     RECT  64.645 26.592 64.721 28.488 ;
     RECT  64.577 42.672 64.721 45 ;
     RECT  63.749 9.024 64.789 9.048 ;
     RECT  63.569 19.344 64.793 19.368 ;
     RECT  64.541 39.36 64.796 39.384 ;
     RECT  64.789 8.304 64.825 9.048 ;
     RECT  64.177 21.216 64.825 22.776 ;
     RECT  64.285 34.464 64.829 34.488 ;
     RECT  64.721 42.768 64.865 45 ;
     RECT  64.796 39.36 64.883 40.008 ;
     RECT  64.001 24.48 64.892 24.84 ;
     RECT  64.825 8.304 64.901 9.096 ;
     RECT  63.461 16.08 64.933 16.296 ;
     RECT  64.573 67.776 64.933 68.856 ;
     RECT  63.853 70.464 64.933 71.88 ;
     RECT  64.933 15.504 64.969 17.112 ;
     RECT  64.901 9.072 64.973 9.096 ;
     RECT  64.892 24.48 64.979 25.176 ;
     RECT  64.933 67.776 64.979 71.88 ;
     RECT  64.681 4.272 65.005 4.92 ;
     RECT  64.979 68.736 65.009 71.88 ;
     RECT  64.645 52.896 65.081 53.592 ;
     RECT  64.789 75.648 65.081 75.672 ;
     RECT  64.721 26.592 65.113 28.056 ;
     RECT  64.502 32.448 65.173 32.472 ;
     RECT  64.033 61.728 65.189 61.752 ;
     RECT  65.149 29.04 65.233 29.688 ;
     RECT  65.009 68.736 65.261 70.056 ;
     RECT  65.261 68.832 65.297 70.056 ;
     RECT  64.865 42.768 65.333 44.856 ;
     RECT  65.297 68.928 65.333 70.056 ;
     RECT  64.253 3.264 65.365 3.288 ;
     RECT  64.969 15.216 65.365 17.112 ;
     RECT  64.609 55.392 65.369 59.976 ;
     RECT  65.173 32.352 65.411 32.472 ;
     RECT  65.369 55.392 65.411 59.736 ;
     RECT  65.233 29.184 65.437 29.688 ;
     RECT  64.979 24.48 65.441 24.504 ;
     RECT  64.397 37.584 65.473 37.896 ;
     RECT  64.325 63.168 65.473 63.24 ;
     RECT  65.473 37.392 65.509 37.896 ;
     RECT  65.411 55.392 65.509 59.4 ;
     RECT  65.005 4.272 65.513 5.256 ;
     RECT  64.249 66.336 65.513 66.36 ;
     RECT  65.113 26.208 65.545 28.056 ;
     RECT  65.473 51.84 65.545 51.864 ;
     RECT  65.081 53.568 65.545 53.592 ;
     RECT  65.509 54.672 65.545 59.4 ;
     RECT  64.109 46.992 65.549 47.88 ;
     RECT  65.545 53.568 65.555 59.4 ;
     RECT  65.545 51.84 65.557 51.96 ;
     RECT  65.365 19.056 65.585 19.08 ;
     RECT  65.555 53.568 65.585 54.696 ;
     RECT  65.411 32.448 65.617 32.472 ;
     RECT  65.365 33.936 65.617 34.392 ;
     RECT  64.825 20.832 65.621 22.776 ;
     RECT  65.621 22.704 65.657 22.776 ;
     RECT  65.437 29.184 65.729 30.36 ;
     RECT  65.545 25.632 65.765 28.056 ;
     RECT  65.621 20.832 65.797 21.528 ;
     RECT  65.333 43.536 65.801 44.856 ;
     RECT  64.213 72.864 65.873 72.888 ;
     RECT  65.365 15.216 65.893 17.64 ;
     RECT  65.797 20.688 65.893 21.528 ;
     RECT  65.893 15.216 65.909 18.408 ;
     RECT  65.909 16.08 65.939 18.408 ;
     RECT  65.509 37.152 65.977 37.896 ;
     RECT  65.939 18.384 65.98 18.408 ;
     RECT  65.893 19.776 65.98 21.528 ;
     RECT  65.617 32.448 65.981 34.392 ;
     RECT  64.883 39.36 66.049 39.384 ;
     RECT  65.941 10.944 66.085 10.968 ;
     RECT  65.401 78.384 66.089 78.408 ;
     RECT  66.085 10.848 66.125 10.968 ;
     RECT  65.729 29.184 66.125 29.688 ;
     RECT  65.981 32.448 66.125 32.472 ;
     RECT  65.765 25.632 66.197 27.816 ;
     RECT  65.981 33.888 66.229 34.392 ;
     RECT  65.009 71.136 66.265 71.88 ;
     RECT  65.941 40.944 66.301 40.968 ;
     RECT  66.049 39.312 66.337 39.384 ;
     RECT  66.301 40.512 66.337 40.968 ;
     RECT  65.513 5.232 66.409 5.256 ;
     RECT  65.473 63.12 66.481 63.24 ;
     RECT  66.085 64.704 66.481 64.728 ;
     RECT  65.329 67.44 66.481 67.464 ;
     RECT  65.977 36.816 66.517 37.896 ;
     RECT  65.365 2.592 66.553 3.288 ;
     RECT  65.657 22.752 66.589 22.776 ;
     RECT  66.337 39.024 66.589 40.968 ;
     RECT  65.473 74.16 66.589 74.184 ;
     RECT  66.229 33.888 66.625 34.68 ;
     RECT  66.517 36.48 66.625 37.896 ;
     RECT  66.589 39.024 66.625 41.016 ;
     RECT  66.625 8.832 66.661 8.856 ;
     RECT  66.589 22.752 66.697 23.4 ;
     RECT  65.801 43.536 66.697 44.232 ;
     RECT  66.481 67.44 66.697 68.232 ;
     RECT  65.333 69.264 66.697 70.056 ;
     RECT  66.589 73.872 66.7 74.184 ;
     RECT  66.265 71.136 66.841 72.84 ;
     RECT  66.7 73.824 66.841 74.184 ;
     RECT  65.555 56.064 66.877 59.4 ;
     RECT  66.877 77.28 66.913 77.4 ;
     RECT  65.549 47.328 66.949 47.88 ;
     RECT  65.581 49.008 66.949 49.032 ;
     RECT  66.197 26.592 66.985 27.816 ;
     RECT  66.625 33.888 67.057 35.448 ;
     RECT  66.625 36.48 67.057 41.016 ;
     RECT  66.697 43.296 67.057 44.232 ;
     RECT  66.985 26.592 67.093 28.2 ;
     RECT  66.517 45.552 67.093 45.576 ;
     RECT  66.481 63.12 67.093 64.728 ;
     RECT  66.697 67.44 67.093 70.056 ;
     RECT  66.841 71.136 67.093 74.184 ;
     RECT  67.093 63.072 67.129 64.728 ;
     RECT  66.553 2.256 67.208 3.288 ;
     RECT  66.409 5.232 67.208 5.784 ;
     RECT  66.661 7.44 67.208 8.856 ;
     RECT  66.125 10.848 67.208 10.872 ;
     RECT  66.553 11.952 67.208 11.976 ;
     RECT  65.689 14.112 67.208 14.136 ;
     RECT  65.939 16.08 67.208 16.92 ;
     RECT  65.98 20.544 67.208 21.528 ;
     RECT  66.697 22.704 67.208 23.4 ;
     RECT  66.373 24.72 67.208 24.744 ;
     RECT  67.093 26.592 67.208 28.44 ;
     RECT  66.125 29.664 67.208 29.688 ;
     RECT  66.589 31.488 67.208 31.512 ;
     RECT  67.057 33.888 67.208 41.016 ;
     RECT  67.057 43.296 67.208 44.472 ;
     RECT  67.093 45.552 67.208 45.72 ;
     RECT  66.949 47.328 67.208 49.032 ;
     RECT  65.557 51.936 67.208 51.96 ;
     RECT  65.585 54.096 67.208 54.696 ;
     RECT  66.877 56.064 67.208 59.496 ;
     RECT  65.473 61.056 67.208 61.08 ;
     RECT  67.129 62.976 67.208 64.728 ;
     RECT  67.093 67.44 67.208 74.184 ;
     RECT  66.913 77.28 67.208 77.592 ;
     RECT  66.121 78.864 67.208 78.888 ;
     RECT  67.208 2.148 67.312 79.932 ;
     RECT  67.312 2.256 67.504 79.662 ;
     RECT  67.504 71.184 67.601 71.208 ;
     RECT  67.504 13.632 67.637 19.416 ;
     RECT  67.504 24.48 67.637 24.504 ;
     RECT  67.504 6.768 67.715 9.528 ;
     RECT  67.504 62.976 67.745 63.24 ;
     RECT  67.504 5.76 67.811 5.784 ;
     RECT  67.504 22.56 67.853 23.4 ;
     RECT  67.504 49.536 67.853 49.56 ;
     RECT  67.504 56.064 67.889 58.152 ;
     RECT  67.504 47.136 67.925 48.12 ;
     RECT  67.504 67.248 67.961 68.424 ;
     RECT  67.504 2.256 67.997 4.104 ;
     RECT  67.504 36.624 67.997 39.336 ;
     RECT  67.637 17.664 68.003 19.416 ;
     RECT  67.504 25.584 68.003 30.024 ;
     RECT  67.504 76.56 68.033 77.592 ;
     RECT  67.504 20.592 68.099 21.528 ;
     RECT  67.504 59.472 68.105 59.496 ;
     RECT  67.504 33.936 68.141 35.448 ;
     RECT  67.504 72.528 68.177 73.848 ;
     RECT  67.997 2.832 68.195 4.104 ;
     RECT  68.099 20.592 68.213 20.712 ;
     RECT  67.961 67.68 68.243 68.424 ;
     RECT  68.213 20.592 68.249 20.616 ;
     RECT  68.003 17.664 68.291 19.368 ;
     RECT  68.291 18.096 68.429 19.368 ;
     RECT  67.504 54.096 68.429 54.696 ;
     RECT  67.715 8.496 68.483 9 ;
     RECT  67.853 22.56 68.497 22.728 ;
     RECT  67.889 56.064 68.497 57.384 ;
     RECT  67.715 6.768 68.533 7.368 ;
     RECT  67.504 11.424 68.533 11.976 ;
     RECT  68.177 73.824 68.537 73.848 ;
     RECT  68.243 68.064 68.573 68.424 ;
     RECT  68.492 10.32 68.579 10.344 ;
     RECT  68.033 76.752 68.609 77.592 ;
     RECT  67.504 78.768 68.609 79.32 ;
     RECT  67.504 40.56 68.645 42.216 ;
     RECT  67.997 37.44 68.681 39.336 ;
     RECT  68.645 42.144 68.713 42.216 ;
     RECT  67.504 43.296 68.713 44.472 ;
     RECT  67.504 65.664 68.713 65.88 ;
     RECT  67.504 31.2 68.717 32.136 ;
     RECT  68.605 24.336 68.749 24.36 ;
     RECT  68.003 25.584 68.749 27.192 ;
     RECT  68.533 11.424 68.825 12.12 ;
     RECT  68.497 22.464 68.825 22.728 ;
     RECT  68.141 34.656 68.893 35.448 ;
     RECT  68.609 76.992 68.897 77.592 ;
     RECT  68.533 6.48 68.929 7.368 ;
     RECT  67.637 13.632 68.929 16.632 ;
     RECT  68.681 38.16 68.929 39.336 ;
     RECT  68.645 40.56 68.929 40.584 ;
     RECT  68.177 72.528 68.929 72.792 ;
     RECT  68.893 34.656 69.005 35.88 ;
     RECT  68.003 28.224 69.041 30.024 ;
     RECT  68.785 46.848 69.041 46.872 ;
     RECT  68.497 55.824 69.041 57.384 ;
     RECT  68.929 72.432 69.041 72.792 ;
     RECT  68.825 22.512 69.109 22.728 ;
     RECT  69.005 34.656 69.113 34.68 ;
     RECT  68.713 65.52 69.185 65.88 ;
     RECT  68.195 3.168 69.257 3.192 ;
     RECT  69.185 65.52 69.257 65.688 ;
     RECT  69.109 22.512 69.289 23.304 ;
     RECT  68.749 24.336 69.289 27.192 ;
     RECT  67.745 63.072 69.289 63.24 ;
     RECT  69.041 72.768 69.325 72.792 ;
     RECT  68.713 42.144 69.329 44.472 ;
     RECT  68.429 54.624 69.349 54.696 ;
     RECT  69.041 55.824 69.349 55.848 ;
     RECT  68.573 68.064 69.349 68.28 ;
     RECT  68.929 13.632 69.361 17.112 ;
     RECT  68.429 18.096 69.361 18.168 ;
     RECT  68.429 19.344 69.365 19.368 ;
     RECT  67.925 48.096 69.365 48.12 ;
     RECT  69.289 59.232 69.433 59.256 ;
     RECT  69.181 60.96 69.433 60.984 ;
     RECT  68.929 38.16 69.443 40.584 ;
     RECT  69.356 51.888 69.443 51.912 ;
     RECT  69.361 13.632 69.469 18.168 ;
     RECT  68.825 11.952 69.541 12.12 ;
     RECT  69.433 59.232 69.545 60.984 ;
     RECT  69.325 72.768 69.577 72.936 ;
     RECT  69.545 60.384 69.581 60.984 ;
     RECT  69.541 11.952 69.649 12.216 ;
     RECT  69.469 13.44 69.649 18.168 ;
     RECT  69.041 28.368 69.653 30.024 ;
     RECT  69.443 38.16 69.653 39.048 ;
     RECT  69.041 56.928 69.685 57.384 ;
     RECT  69.289 62.688 69.685 63.24 ;
     RECT  69.349 67.728 69.689 68.28 ;
     RECT  69.577 72.768 69.725 73.992 ;
     RECT  68.609 79.296 69.761 79.32 ;
     RECT  69.725 72.912 69.797 73.992 ;
     RECT  69.649 11.952 69.833 18.168 ;
     RECT  68.929 6.24 69.865 7.368 ;
     RECT  69.797 72.912 69.869 73.56 ;
     RECT  69.037 10.704 69.877 10.776 ;
     RECT  69.329 42.144 69.937 43.272 ;
     RECT  68.483 8.976 69.973 9 ;
     RECT  69.877 10.704 69.973 10.872 ;
     RECT  69.865 6.24 69.977 7.896 ;
     RECT  68.929 49.536 70.009 49.56 ;
     RECT  69.829 50.832 70.009 50.856 ;
     RECT  69.973 8.976 70.045 9.624 ;
     RECT  69.973 10.704 70.045 11.064 ;
     RECT  69.361 46.704 70.045 46.728 ;
     RECT  67.504 45.696 70.076 45.72 ;
     RECT  70.045 46.704 70.076 47.304 ;
     RECT  70.045 30.288 70.081 30.696 ;
     RECT  68.717 32.112 70.081 32.136 ;
     RECT  69.349 54.624 70.081 55.848 ;
     RECT  69.685 56.928 70.081 58.152 ;
     RECT  70.076 45.696 70.117 47.304 ;
     RECT  70.045 8.976 70.121 11.064 ;
     RECT  69.937 41.952 70.157 43.272 ;
     RECT  69.721 75.312 70.157 75.336 ;
     RECT  70.117 45.408 70.163 47.304 ;
     RECT  69.005 35.856 70.193 35.88 ;
     RECT  70.081 54.624 70.213 58.152 ;
     RECT  70.121 8.976 70.229 10.728 ;
     RECT  69.833 12.048 70.229 18.168 ;
     RECT  70.213 54.096 70.259 58.152 ;
     RECT  69.977 6.48 70.261 7.896 ;
     RECT  70.22 48.384 70.261 48.408 ;
     RECT  70.009 49.536 70.261 50.856 ;
     RECT  70.229 12.048 70.265 14.04 ;
     RECT  70.163 46.464 70.265 47.304 ;
     RECT  70.259 55.344 70.265 58.152 ;
     RECT  69.689 68.256 70.265 68.28 ;
     RECT  69.325 21.408 70.297 21.432 ;
     RECT  69.289 22.512 70.297 27.192 ;
     RECT  70.259 54.096 70.301 54.12 ;
     RECT  70.261 48.384 70.307 50.856 ;
     RECT  70.297 21.408 70.337 27.192 ;
     RECT  69.685 62.64 70.337 63.24 ;
     RECT  70.189 3.408 70.397 3.432 ;
     RECT  70.337 23.808 70.409 27.192 ;
     RECT  70.307 48.672 70.409 49.56 ;
     RECT  70.397 2.784 70.441 3.432 ;
     RECT  70.265 12.048 70.445 13.56 ;
     RECT  70.081 30.288 70.445 32.136 ;
     RECT  70.441 2.256 70.451 3.432 ;
     RECT  70.451 2.256 70.481 2.808 ;
     RECT  70.409 23.808 70.481 24.36 ;
     RECT  70.261 52.464 70.513 52.488 ;
     RECT  70.265 46.464 70.547 46.68 ;
     RECT  70.337 21.408 70.549 22.824 ;
     RECT  70.229 15.12 70.553 18.168 ;
     RECT  69.577 19.92 70.604 19.944 ;
     RECT  70.513 52.464 70.621 53.4 ;
     RECT  70.445 30.288 70.625 30.936 ;
     RECT  70.513 74.544 70.625 74.568 ;
     RECT  70.409 48.672 70.643 48.888 ;
     RECT  70.604 19.344 70.691 19.944 ;
     RECT  69.653 39.024 70.693 39.048 ;
     RECT  69.653 28.368 70.697 29.16 ;
     RECT  70.547 46.656 70.697 46.68 ;
     RECT  70.307 50.832 70.697 50.856 ;
     RECT  70.229 8.976 70.733 9.96 ;
     RECT  70.265 55.344 70.733 55.896 ;
     RECT  69.257 65.52 70.733 65.544 ;
     RECT  70.157 41.952 70.801 42.312 ;
     RECT  70.081 67.248 70.801 67.272 ;
     RECT  70.643 48.672 70.805 48.696 ;
     RECT  70.801 41.856 70.841 42.312 ;
     RECT  70.801 67.248 70.909 68.232 ;
     RECT  70.841 41.856 70.913 42.168 ;
     RECT  69.581 60.384 70.945 60.408 ;
     RECT  69.829 33.6 70.985 33.624 ;
     RECT  70.265 56.976 70.985 58.152 ;
     RECT  70.261 6.48 71.053 7.944 ;
     RECT  70.733 8.976 71.053 9.72 ;
     RECT  69.545 59.232 71.053 59.256 ;
     RECT  70.945 60.384 71.053 60.504 ;
     RECT  70.409 25.68 71.057 27.192 ;
     RECT  70.445 32.112 71.057 32.136 ;
     RECT  67.504 69.792 71.089 69.816 ;
     RECT  69.469 77.664 71.125 77.688 ;
     RECT  69.869 73.248 71.161 73.56 ;
     RECT  70.553 15.36 71.165 18.168 ;
     RECT  70.693 38.16 71.197 39.048 ;
     RECT  71.125 77.664 71.201 77.976 ;
     RECT  71.161 72.912 71.221 73.56 ;
     RECT  71.057 26.208 71.237 27.192 ;
     RECT  71.221 72.912 71.267 73.752 ;
     RECT  71.053 6.48 71.273 9.72 ;
     RECT  70.549 21.36 71.273 22.824 ;
     RECT  70.697 28.416 71.273 29.16 ;
     RECT  71.273 6.48 71.309 7.944 ;
     RECT  70.985 57.024 71.341 58.152 ;
     RECT  71.197 37.968 71.345 39.048 ;
     RECT  70.909 66.72 71.345 68.232 ;
     RECT  70.445 12.288 71.377 13.56 ;
     RECT  71.309 6.48 71.381 7.896 ;
     RECT  71.197 79.152 71.381 79.176 ;
     RECT  70.621 52.176 71.453 53.4 ;
     RECT  71.053 59.232 71.453 60.504 ;
     RECT  71.201 77.952 71.521 77.976 ;
     RECT  70.625 30.288 71.593 30.84 ;
     RECT  71.165 15.36 71.629 17.112 ;
     RECT  70.337 63.024 71.665 63.24 ;
     RECT  70.913 41.856 71.701 41.88 ;
     RECT  70.837 5.088 71.708 5.112 ;
     RECT  71.377 12.288 71.737 13.656 ;
     RECT  71.453 52.176 71.737 53.016 ;
     RECT  71.708 5.088 71.749 5.448 ;
     RECT  71.593 29.76 71.773 30.84 ;
     RECT  71.737 12 71.797 13.656 ;
     RECT  71.629 14.88 71.797 17.112 ;
     RECT  71.797 12 71.809 17.112 ;
     RECT  71.749 4.464 71.845 5.448 ;
     RECT  71.237 26.736 71.881 27.192 ;
     RECT  71.089 69.552 71.917 69.816 ;
     RECT  71.267 73.344 71.953 73.752 ;
     RECT  71.773 29.76 72.025 31.128 ;
     RECT  70.733 55.776 72.037 55.896 ;
     RECT  71.341 57.024 72.037 58.248 ;
     RECT  71.453 60.48 72.061 60.504 ;
     RECT  71.665 62.736 72.133 63.24 ;
     RECT  71.345 67.776 72.133 68.232 ;
     RECT  71.917 69.264 72.133 69.816 ;
     RECT  70.481 24.336 72.169 24.36 ;
     RECT  70.765 71.856 72.169 71.88 ;
     RECT  70.873 64.608 72.205 64.632 ;
     RECT  71.701 41.088 72.313 41.88 ;
     RECT  71.773 76.368 72.313 76.392 ;
     RECT  72.205 64.608 72.349 65.448 ;
     RECT  71.273 21.36 72.373 21.384 ;
     RECT  71.273 22.8 72.373 22.824 ;
     RECT  72.133 62.016 72.38 63.24 ;
     RECT  72.373 21.36 72.385 22.824 ;
     RECT  71.665 43.872 72.385 43.896 ;
     RECT  72.025 29.76 72.421 32.04 ;
     RECT  71.453 59.232 72.421 59.256 ;
     RECT  72.061 60.48 72.421 60.888 ;
     RECT  71.345 39.024 72.449 39.048 ;
     RECT  72.349 64.608 72.469 65.784 ;
     RECT  72.313 76.224 72.469 76.392 ;
     RECT  72.169 24.336 72.493 24.504 ;
     RECT  72.385 43.872 72.493 44.136 ;
     RECT  71.273 28.416 72.529 28.44 ;
     RECT  72.421 29.52 72.529 32.04 ;
     RECT  71.521 77.952 72.529 78.12 ;
     RECT  70.481 2.256 72.608 2.28 ;
     RECT  71.629 3.264 72.608 3.288 ;
     RECT  71.845 4.368 72.608 5.448 ;
     RECT  71.381 6.48 72.608 6.504 ;
     RECT  71.381 7.872 72.608 7.896 ;
     RECT  71.273 8.976 72.608 9.72 ;
     RECT  71.809 11.664 72.608 17.112 ;
     RECT  71.165 18.144 72.608 18.168 ;
     RECT  70.691 19.92 72.608 19.944 ;
     RECT  72.385 21.36 72.608 23.352 ;
     RECT  72.493 24.336 72.608 25.08 ;
     RECT  71.881 26.736 72.608 27.288 ;
     RECT  72.529 28.416 72.608 32.04 ;
     RECT  72.169 35.808 72.608 35.832 ;
     RECT  71.345 37.968 72.608 37.992 ;
     RECT  72.449 39.024 72.608 39.432 ;
     RECT  72.313 41.088 72.608 41.928 ;
     RECT  72.493 43.536 72.608 44.136 ;
     RECT  70.163 45.408 72.608 45.432 ;
     RECT  71.845 50.4 72.608 50.424 ;
     RECT  71.737 51.744 72.608 53.016 ;
     RECT  72.037 55.776 72.608 58.248 ;
     RECT  72.421 59.232 72.608 60.888 ;
     RECT  72.38 61.92 72.608 63.24 ;
     RECT  72.469 64.608 72.608 66.168 ;
     RECT  72.133 67.776 72.608 69.816 ;
     RECT  72.169 71.664 72.608 71.88 ;
     RECT  71.953 73.344 72.608 74.136 ;
     RECT  72.469 75.408 72.608 76.392 ;
     RECT  72.529 77.616 72.608 78.12 ;
     RECT  72.608 2.148 72.712 79.932 ;
     RECT  72.712 2.418 72.904 79.662 ;
     RECT  72.904 28.416 72.929 32.04 ;
     RECT  72.904 60.96 73.109 65.784 ;
     RECT  72.929 28.416 73.145 31.992 ;
     RECT  72.904 68.208 73.181 72.984 ;
     RECT  72.904 20.544 73.217 24.456 ;
     RECT  72.904 46.608 73.253 47.496 ;
     RECT  72.904 26.88 73.289 27.192 ;
     RECT  72.904 75.408 73.289 75.864 ;
     RECT  73.217 22.608 73.325 24.456 ;
     RECT  72.904 74.112 73.379 74.136 ;
     RECT  72.904 57.072 73.397 58.728 ;
     RECT  73.181 68.928 73.468 72.984 ;
     RECT  72.904 77.712 73.469 78.12 ;
     RECT  72.904 6.576 73.541 6.888 ;
     RECT  72.904 41.904 73.541 42.168 ;
     RECT  72.904 37.968 73.577 39.24 ;
     RECT  73.469 77.712 73.577 77.976 ;
     RECT  72.904 3.408 73.613 4.488 ;
     RECT  73.145 28.416 73.613 31.512 ;
     RECT  72.904 9.6 73.649 10.488 ;
     RECT  72.904 18.144 73.649 19.224 ;
     RECT  73.468 68.928 73.649 69.576 ;
     RECT  73.289 75.84 73.649 75.864 ;
     RECT  72.904 11.76 73.685 12.84 ;
     RECT  73.217 20.544 73.721 21.288 ;
     RECT  73.721 21.12 73.793 21.288 ;
     RECT  73.613 28.416 73.829 31.368 ;
     RECT  73.109 60.96 73.865 65.4 ;
     RECT  72.904 14.688 73.973 15.864 ;
     RECT  72.904 54.96 73.973 56.088 ;
     RECT  72.904 25.68 74.009 25.704 ;
     RECT  72.904 36.624 74.041 36.648 ;
     RECT  73.253 46.704 74.077 47.496 ;
     RECT  73.397 58.368 74.099 58.728 ;
     RECT  73.649 10.368 74.113 10.488 ;
     RECT  74.041 36.624 74.113 36.744 ;
     RECT  73.865 61.968 74.113 65.4 ;
     RECT  73.577 38.16 74.117 39.24 ;
     RECT  72.904 59.76 74.117 59.784 ;
     RECT  73.577 77.712 74.117 77.736 ;
     RECT  73.325 22.608 74.189 22.824 ;
     RECT  73.829 30.576 74.189 31.368 ;
     RECT  74.189 30.576 74.225 31.224 ;
     RECT  74.077 46.704 74.257 47.64 ;
     RECT  73.325 23.808 74.261 24.456 ;
     RECT  72.904 43.68 74.329 44.136 ;
     RECT  73.397 57.072 74.329 57.384 ;
     RECT  73.933 66.96 74.329 66.984 ;
     RECT  74.113 10.368 74.365 10.632 ;
     RECT  73.541 6.624 74.441 6.888 ;
     RECT  74.099 58.368 74.477 58.392 ;
     RECT  74.113 36.576 74.545 36.744 ;
     RECT  73.973 54.96 74.545 55.8 ;
     RECT  73.541 42.144 74.549 42.168 ;
     RECT  74.329 66.72 74.549 66.984 ;
     RECT  74.261 23.904 74.581 24.456 ;
     RECT  72.904 17.088 74.585 17.112 ;
     RECT  74.549 66.72 74.585 66.744 ;
     RECT  73.649 68.928 74.585 68.952 ;
     RECT  74.117 38.64 74.617 39.24 ;
     RECT  74.365 10.368 74.653 10.68 ;
     RECT  73.973 14.688 74.653 15.816 ;
     RECT  73.468 70.944 74.653 72.984 ;
     RECT  74.545 7.008 74.681 7.416 ;
     RECT  74.365 35.52 74.693 35.544 ;
     RECT  72.904 48.816 74.693 50.616 ;
     RECT  73.685 11.76 74.725 12.312 ;
     RECT  74.473 33.6 74.729 33.624 ;
     RECT  74.693 48.816 74.729 49.944 ;
     RECT  74.189 22.608 74.761 22.632 ;
     RECT  73.289 27.12 74.765 27.192 ;
     RECT  74.545 36.576 74.765 37.272 ;
     RECT  74.329 56.88 74.765 57.384 ;
     RECT  74.617 38.64 74.801 39.912 ;
     RECT  73.793 21.216 74.833 21.288 ;
     RECT  72.904 45.408 74.833 45.432 ;
     RECT  74.257 46.704 74.833 47.832 ;
     RECT  74.833 45.408 74.905 47.832 ;
     RECT  74.653 10.32 74.941 10.68 ;
     RECT  74.833 21.12 74.945 21.288 ;
     RECT  74.653 13.968 74.977 15.816 ;
     RECT  74.113 61.968 75.013 65.448 ;
     RECT  74.293 59.712 75.016 59.736 ;
     RECT  74.725 11.76 75.017 12.936 ;
     RECT  75.016 59.664 75.017 59.736 ;
     RECT  73.649 19.2 75.053 19.224 ;
     RECT  74.869 42.576 75.061 42.6 ;
     RECT  74.329 43.68 75.061 44.184 ;
     RECT  75.049 69.504 75.068 69.528 ;
     RECT  74.653 70.944 75.068 73.656 ;
     RECT  73.613 4.032 75.085 4.488 ;
     RECT  74.941 9.6 75.085 10.68 ;
     RECT  74.765 36.576 75.085 36.648 ;
     RECT  75.017 59.664 75.085 59.688 ;
     RECT  73.865 60.96 75.085 60.984 ;
     RECT  75.013 61.968 75.085 66.408 ;
     RECT  74.765 27.168 75.109 27.192 ;
     RECT  75.085 4.032 75.125 4.536 ;
     RECT  75.061 42.576 75.125 44.184 ;
     RECT  75.109 27.168 75.155 27.384 ;
     RECT  75.068 69.504 75.155 73.656 ;
     RECT  75.155 70.704 75.157 73.656 ;
     RECT  75.121 75.744 75.157 75.768 ;
     RECT  74.545 54.576 75.161 55.8 ;
     RECT  75.085 59.28 75.169 59.688 ;
     RECT  74.977 13.968 75.193 16.008 ;
     RECT  74.681 7.008 75.197 7.464 ;
     RECT  74.801 38.64 75.205 39.24 ;
     RECT  75.125 42.576 75.233 44.088 ;
     RECT  75.085 35.952 75.251 36.648 ;
     RECT  75.085 60.96 75.305 66.408 ;
     RECT  75.085 9.312 75.341 10.68 ;
     RECT  74.945 21.12 75.341 21.192 ;
     RECT  75.305 60.96 75.341 62.184 ;
     RECT  75.205 38.4 75.377 39.24 ;
     RECT  75.125 4.464 75.449 4.536 ;
     RECT  75.449 4.512 75.481 4.536 ;
     RECT  74.761 22.416 75.485 22.632 ;
     RECT  74.581 23.904 75.485 24.792 ;
     RECT  75.017 12 75.517 12.936 ;
     RECT  75.193 13.968 75.517 16.584 ;
     RECT  75.485 22.608 75.517 22.632 ;
     RECT  75.161 55.488 75.517 55.8 ;
     RECT  75.481 4.512 75.521 5.112 ;
     RECT  75.341 61.2 75.521 62.184 ;
     RECT  75.305 63.216 75.521 66.408 ;
     RECT  74.437 77.328 75.541 77.352 ;
     RECT  73.829 28.416 75.557 29.544 ;
     RECT  75.445 52.128 75.557 52.152 ;
     RECT  75.341 9.6 75.629 10.68 ;
     RECT  75.485 24.768 75.701 24.792 ;
     RECT  75.557 28.896 75.701 29.544 ;
     RECT  74.689 32.304 75.701 32.328 ;
     RECT  75.157 70.704 75.733 73.752 ;
     RECT  75.157 74.832 75.733 75.768 ;
     RECT  75.341 21.12 75.737 21.144 ;
     RECT  75.197 7.008 75.769 7.176 ;
     RECT  75.481 8.208 75.773 8.232 ;
     RECT  73.649 18.144 75.805 18.168 ;
     RECT  74.797 53.424 75.805 53.448 ;
     RECT  75.517 55.488 75.805 55.848 ;
     RECT  74.765 56.88 75.805 57.096 ;
     RECT  74.729 49.92 75.841 49.944 ;
     RECT  75.541 77.328 75.841 77.544 ;
     RECT  75.517 12 75.845 16.584 ;
     RECT  75.697 58.464 75.881 58.488 ;
     RECT  75.521 61.2 75.881 61.224 ;
     RECT  74.905 45.408 75.917 48.648 ;
     RECT  75.769 6.864 75.949 7.176 ;
     RECT  75.841 49.92 75.949 50.76 ;
     RECT  75.805 55.488 75.949 57.096 ;
     RECT  75.517 22.608 75.953 23.544 ;
     RECT  75.949 49.2 75.953 50.76 ;
     RECT  75.701 29.04 75.98 29.544 ;
     RECT  74.225 30.576 75.98 31.128 ;
     RECT  75.805 52.848 75.985 53.448 ;
     RECT  75.155 69.504 75.985 69.528 ;
     RECT  75.233 42.576 75.989 43.896 ;
     RECT  75.98 29.04 76.021 31.128 ;
     RECT  75.733 70.704 76.057 75.768 ;
     RECT  75.589 41.568 76.061 41.592 ;
     RECT  76.021 29.04 76.067 31.944 ;
     RECT  75.377 38.736 76.165 39.24 ;
     RECT  75.917 45.408 76.165 48.216 ;
     RECT  75.985 69.168 76.205 69.528 ;
     RECT  76.165 45.072 76.241 48.216 ;
     RECT  75.949 6.336 76.273 7.176 ;
     RECT  76.057 70.704 76.273 75.912 ;
     RECT  75.841 76.896 76.273 77.544 ;
     RECT  76.273 70.704 76.277 77.544 ;
     RECT  76.273 26.208 76.309 26.232 ;
     RECT  75.155 27.36 76.309 27.384 ;
     RECT  75.521 63.216 76.309 63.864 ;
     RECT  75.845 12 76.313 15.72 ;
     RECT  76.067 29.04 76.313 30.84 ;
     RECT  75.521 64.896 76.313 66.408 ;
     RECT  76.277 73.728 76.313 77.544 ;
     RECT  75.805 18.096 76.349 18.168 ;
     RECT  76.313 29.04 76.349 29.352 ;
     RECT  76.309 62.784 76.349 63.864 ;
     RECT  76.241 45.072 76.357 47.832 ;
     RECT  75.629 10.32 76.385 10.68 ;
     RECT  75.985 52.848 76.421 53.592 ;
     RECT  76.313 75.888 76.421 77.544 ;
     RECT  75.949 55.488 76.457 57.336 ;
     RECT  76.313 13.968 76.493 15.72 ;
     RECT  75.953 49.2 76.493 49.944 ;
     RECT  76.313 64.896 76.493 65.448 ;
     RECT  76.421 75.888 76.529 76.2 ;
     RECT  76.349 63.84 76.561 63.864 ;
     RECT  76.421 53.568 76.565 53.592 ;
     RECT  76.457 55.488 76.565 55.512 ;
     RECT  76.313 73.728 76.565 74.328 ;
     RECT  75.521 5.088 76.597 5.112 ;
     RECT  76.273 6.336 76.597 7.224 ;
     RECT  75.169 59.664 76.597 59.688 ;
     RECT  76.385 10.32 76.601 10.584 ;
     RECT  76.277 70.704 76.601 72.696 ;
     RECT  76.597 59.664 76.633 60.408 ;
     RECT  75.913 20.544 76.637 20.568 ;
     RECT  76.561 63.84 76.637 64.392 ;
     RECT  76.349 18.096 76.673 18.12 ;
     RECT  75.953 23.52 76.705 23.544 ;
     RECT  76.637 63.936 76.709 64.392 ;
     RECT  76.313 12 76.745 12.552 ;
     RECT  76.309 26.208 76.817 27.384 ;
     RECT  76.165 38.736 76.844 39.912 ;
     RECT  76.493 49.2 76.853 49.8 ;
     RECT  76.601 71.952 76.925 72.696 ;
     RECT  76.844 38.64 76.931 39.912 ;
     RECT  76.349 62.784 76.933 62.808 ;
     RECT  76.067 31.92 76.957 31.944 ;
     RECT  76.705 23.52 76.961 24.504 ;
     RECT  76.201 51.504 76.961 51.624 ;
     RECT  76.933 61.872 76.979 62.808 ;
     RECT  76.313 30.816 77.029 30.84 ;
     RECT  76.957 31.92 77.029 32.376 ;
     RECT  76.493 14.4 77.033 15.72 ;
     RECT  76.853 49.2 77.173 49.752 ;
     RECT  76.961 51.6 77.209 51.624 ;
     RECT  76.357 45.024 77.425 47.832 ;
     RECT  77.173 49.008 77.425 49.752 ;
     RECT  76.493 65.424 77.425 65.448 ;
     RECT  76.961 24.48 77.461 24.504 ;
     RECT  76.817 26.208 77.461 26.232 ;
     RECT  76.601 10.56 77.569 10.584 ;
     RECT  77.425 45.024 77.569 49.752 ;
     RECT  77.173 53.904 77.605 53.928 ;
     RECT  75.251 35.952 77.677 35.976 ;
     RECT  76.565 74.304 77.713 74.328 ;
     RECT  76.529 75.936 77.713 76.2 ;
     RECT  75.989 42.72 77.749 43.896 ;
     RECT  77.569 44.88 77.749 49.752 ;
     RECT  77.569 10.416 77.785 10.584 ;
     RECT  77.677 35.52 77.785 35.976 ;
     RECT  77.749 42.72 77.785 49.752 ;
     RECT  77.785 42 77.845 49.752 ;
     RECT  77.425 65.424 77.857 65.544 ;
     RECT  76.813 17.616 77.893 17.64 ;
     RECT  77.785 34.752 77.893 35.976 ;
     RECT  76.709 64.368 77.893 64.392 ;
     RECT  77.857 65.424 77.893 65.688 ;
     RECT  77.713 74.304 77.893 76.2 ;
     RECT  77.893 74.304 77.965 76.392 ;
     RECT  76.597 5.088 78.008 7.224 ;
     RECT  77.785 10.128 78.008 10.584 ;
     RECT  76.745 12.528 78.008 12.552 ;
     RECT  77.033 14.4 78.008 14.76 ;
     RECT  77.893 16.368 78.008 16.392 ;
     RECT  77.893 17.616 78.008 18.456 ;
     RECT  77.353 21.072 78.008 21.096 ;
     RECT  76.489 22.224 78.008 22.248 ;
     RECT  77.677 23.328 78.008 23.352 ;
     RECT  77.461 24.48 78.008 26.232 ;
     RECT  76.817 27.36 78.008 27.384 ;
     RECT  76.349 29.04 78.008 29.064 ;
     RECT  77.029 30.816 78.008 32.376 ;
     RECT  77.845 33.552 78.008 33.576 ;
     RECT  77.893 34.656 78.008 35.976 ;
     RECT  77.893 37.632 78.008 37.656 ;
     RECT  76.931 39.216 78.008 39.24 ;
     RECT  77.641 40.56 78.008 40.584 ;
     RECT  77.845 41.616 78.008 49.752 ;
     RECT  77.209 51.6 78.008 52.44 ;
     RECT  77.605 53.904 78.008 54.696 ;
     RECT  76.457 56.496 78.008 57.336 ;
     RECT  77.065 58.464 78.008 58.488 ;
     RECT  76.633 59.472 78.008 60.408 ;
     RECT  76.979 61.872 78.008 62.712 ;
     RECT  77.893 64.368 78.008 65.688 ;
     RECT  77.461 67.056 78.008 67.08 ;
     RECT  76.205 69.168 78.008 69.192 ;
     RECT  76.601 70.704 78.008 70.728 ;
     RECT  76.925 72.672 78.008 72.696 ;
     RECT  77.965 74.064 78.008 76.392 ;
     RECT  78.008 2.148 78.112 79.932 ;
     RECT  78.112 2.418 78.304 79.662 ;
     RECT  78.304 18.72 78.329 18.888 ;
     RECT  78.304 43.872 78.329 48.504 ;
     RECT  78.304 63.504 78.329 65.688 ;
     RECT  78.304 75.792 78.365 75.816 ;
     RECT  78.304 27.36 78.419 27.816 ;
     RECT  78.304 29.328 78.419 29.352 ;
     RECT  78.304 30.576 78.419 30.6 ;
     RECT  78.304 67.872 78.445 70.152 ;
     RECT  78.329 65.184 78.473 65.688 ;
     RECT  78.304 74.064 78.473 74.088 ;
     RECT  78.304 57.024 78.545 59.496 ;
     RECT  78.304 10.128 78.581 13.704 ;
     RECT  78.581 10.416 78.625 13.704 ;
     RECT  78.304 9.072 78.653 9.096 ;
     RECT  78.329 18.864 78.653 18.888 ;
     RECT  78.304 37.056 78.653 38.808 ;
     RECT  78.329 44.064 78.653 48.504 ;
     RECT  78.304 61.728 78.653 62.472 ;
     RECT  78.445 67.872 78.653 69.624 ;
     RECT  78.653 44.88 78.659 48.504 ;
     RECT  78.625 10.416 78.689 13.08 ;
     RECT  78.304 23.328 78.689 23.352 ;
     RECT  78.419 27.792 78.689 27.816 ;
     RECT  78.473 65.184 78.725 65.544 ;
     RECT  78.304 40.56 78.797 40.584 ;
     RECT  78.329 63.504 78.803 64.104 ;
     RECT  78.689 12 78.869 12.024 ;
     RECT  78.304 42 78.869 42.744 ;
     RECT  78.304 54.672 78.869 54.696 ;
     RECT  78.545 57.024 78.869 57.048 ;
     RECT  78.545 58.032 78.892 59.496 ;
     RECT  78.892 58.704 78.897 59.496 ;
     RECT  78.869 42.576 78.899 42.744 ;
     RECT  78.659 45.024 78.905 48.504 ;
     RECT  78.897 58.704 78.905 59.208 ;
     RECT  78.304 16.368 78.947 16.44 ;
     RECT  78.304 22.224 78.947 22.248 ;
     RECT  78.725 65.52 78.947 65.544 ;
     RECT  78.905 47.376 79.049 48.504 ;
     RECT  78.947 16.368 79.085 16.392 ;
     RECT  78.905 45.024 79.085 46.056 ;
     RECT  78.304 34.128 79.121 35.976 ;
     RECT  79.049 47.856 79.121 48.504 ;
     RECT  78.653 38.208 79.139 38.808 ;
     RECT  79.121 34.128 79.157 35.256 ;
     RECT  79.085 46.032 79.157 46.056 ;
     RECT  79.157 34.128 79.187 34.968 ;
     RECT  78.304 53.568 79.187 53.592 ;
     RECT  78.905 58.704 79.187 58.728 ;
     RECT  78.653 37.056 79.193 37.08 ;
     RECT  79.139 38.208 79.193 38.232 ;
     RECT  78.653 67.872 79.193 68.76 ;
     RECT  79.187 34.128 79.229 34.776 ;
     RECT  79.193 67.872 79.229 68.088 ;
     RECT  79.229 34.128 79.235 34.632 ;
     RECT  79.085 45.024 79.235 45.048 ;
     RECT  79.235 34.128 79.265 34.152 ;
     RECT  78.653 61.728 79.265 62.232 ;
     RECT  78.899 42.576 79.301 42.6 ;
     RECT  79.229 67.872 79.301 67.896 ;
     RECT  79.265 61.728 79.373 61.752 ;
     RECT  78.689 13.056 79.805 13.08 ;
     RECT  79.121 47.856 79.849 47.88 ;
     RECT  80.341 25.872 80.377 25.896 ;
     RECT  79.549 52.464 80.377 52.488 ;
     RECT  80.053 54.384 80.845 54.408 ;
     RECT  80.377 25.872 80.881 25.992 ;
     RECT  80.377 51.792 80.881 52.584 ;
     RECT  80.845 53.808 80.881 54.408 ;
     RECT  80.881 25.872 80.917 26.76 ;
     RECT  80.881 51.792 80.917 54.408 ;
     RECT  80.917 51.6 80.953 54.408 ;
     RECT  80.917 25.488 81.889 26.952 ;
     RECT  81.889 25.488 81.961 27.144 ;
     RECT  81.961 25.296 82.044 27.144 ;
     RECT  80.953 51.408 82.044 54.408 ;
     RECT  82.044 25.296 82.073 25.32 ;
    LAYER M5 ;
     RECT  2.4 2.137 2.52 2.151 ;
     RECT  7.8 2.137 7.92 2.151 ;
     RECT  13.2 2.137 13.32 2.151 ;
     RECT  18.6 2.137 18.72 2.151 ;
     RECT  24 2.137 24.12 2.151 ;
     RECT  29.4 2.137 29.52 2.151 ;
     RECT  34.8 2.137 34.92 2.151 ;
     RECT  40.2 2.137 40.32 2.151 ;
     RECT  45.6 2.137 45.72 2.151 ;
     RECT  51 2.137 51.12 2.151 ;
     RECT  56.4 2.137 56.52 2.151 ;
     RECT  61.8 2.137 61.92 2.151 ;
     RECT  67.2 2.137 67.32 2.151 ;
     RECT  72.6 2.137 72.72 2.151 ;
     RECT  78 2.137 78.12 2.151 ;
     RECT  72.6 2.151 72.912 2.245 ;
     RECT  40.2 2.151 40.512 2.677 ;
     RECT  67.2 2.151 67.512 2.821 ;
     RECT  58.176 2.245 58.2 3.059 ;
     RECT  24 2.151 24.312 3.157 ;
     RECT  13.2 2.151 13.512 3.397 ;
     RECT  53.472 2.293 53.496 3.443 ;
     RECT  70.416 2.773 70.44 3.443 ;
     RECT  34.8 2.151 35.112 3.685 ;
     RECT  23.568 3.157 24.312 3.971 ;
     RECT  10.272 2.773 10.296 4.019 ;
     RECT  5.328 2.725 5.352 4.067 ;
     RECT  67.2 2.821 68.184 4.115 ;
     RECT  54.816 3.397 54.84 4.117 ;
     RECT  54.816 4.117 55.128 4.163 ;
     RECT  29.4 2.151 29.712 4.261 ;
     RECT  34.8 3.685 35.208 4.451 ;
     RECT  71.856 2.245 72.912 4.453 ;
     RECT  51 2.151 51.312 4.501 ;
     RECT  54.864 4.163 55.128 4.595 ;
     RECT  13.104 3.397 13.512 4.691 ;
     RECT  34.8 4.451 35.112 4.789 ;
     RECT  34.608 4.789 35.112 4.979 ;
     RECT  50.736 4.501 51.312 5.027 ;
     RECT  13.2 4.691 13.512 5.029 ;
     RECT  78 2.151 78.312 5.077 ;
     RECT  58.656 4.501 58.68 5.171 ;
     RECT  2.4 2.151 2.712 5.269 ;
     RECT  3.696 3.445 3.72 5.269 ;
     RECT  44.448 4.501 44.472 5.413 ;
     RECT  45.6 2.151 45.912 5.413 ;
     RECT  44.448 5.413 45.912 5.459 ;
     RECT  23.904 3.971 24.312 5.603 ;
     RECT  5.184 4.501 5.208 5.653 ;
     RECT  54.864 4.595 54.888 5.749 ;
     RECT  54.864 5.749 54.984 5.795 ;
     RECT  31.344 5.029 31.368 5.891 ;
     RECT  39.216 2.677 40.512 5.987 ;
     RECT  13.2 5.029 13.896 6.035 ;
     RECT  7.8 2.151 8.112 6.037 ;
     RECT  5.184 5.653 5.688 6.277 ;
     RECT  6.72 5.605 6.744 6.277 ;
     RECT  5.184 6.277 6.744 6.419 ;
     RECT  67.2 4.115 67.8 6.469 ;
     RECT  71.76 4.453 72.912 6.515 ;
     RECT  28.752 4.261 29.712 6.563 ;
     RECT  29.04 6.563 29.712 6.613 ;
     RECT  29.04 6.613 30.552 6.659 ;
     RECT  13.2 6.035 13.512 6.661 ;
     RECT  44.496 5.459 45.912 6.709 ;
     RECT  42.144 5.365 42.168 6.805 ;
     RECT  43.728 6.709 45.912 6.853 ;
     RECT  46.992 5.653 47.016 6.853 ;
     RECT  7.8 6.037 9.096 6.899 ;
     RECT  41.808 6.805 42.168 6.899 ;
     RECT  43.728 6.853 47.112 7.141 ;
     RECT  24 5.603 24.312 7.189 ;
     RECT  43.728 7.141 47.208 7.283 ;
     RECT  43.728 7.283 47.112 7.331 ;
     RECT  41.808 6.899 41.832 7.715 ;
     RECT  56.4 2.151 56.712 7.909 ;
     RECT  24 7.189 24.408 8.003 ;
     RECT  43.728 7.331 46.872 8.147 ;
     RECT  37.584 7.957 37.608 8.149 ;
     RECT  37.152 8.149 37.608 8.195 ;
     RECT  5.184 6.419 5.208 8.293 ;
     RECT  6.24 6.419 6.744 8.293 ;
     RECT  29.4 6.659 30.552 8.341 ;
     RECT  12.24 6.661 13.512 8.485 ;
     RECT  51 5.027 51.312 9.013 ;
     RECT  56.208 7.909 56.712 9.013 ;
     RECT  56.208 9.013 57 9.059 ;
     RECT  77.232 5.077 78.312 9.061 ;
     RECT  2.4 5.269 3.72 9.109 ;
     RECT  58.464 8.533 58.488 9.155 ;
     RECT  12.24 8.485 14.232 9.251 ;
     RECT  67.2 6.469 68.568 9.539 ;
     RECT  5.184 8.293 6.744 9.731 ;
     RECT  2.4 9.109 3.912 9.925 ;
     RECT  5.184 9.731 6.216 9.925 ;
     RECT  37.152 8.195 37.176 10.019 ;
     RECT  29.4 8.341 30.648 10.451 ;
     RECT  56.4 9.059 57 10.595 ;
     RECT  77.232 9.061 78.6 10.595 ;
     RECT  12.24 9.251 13.704 10.739 ;
     RECT  34.8 4.979 35.112 10.741 ;
     RECT  49.248 7.717 49.272 10.741 ;
     RECT  43.728 8.147 45.912 10.789 ;
     RECT  37.92 10.021 37.944 10.835 ;
     RECT  2.4 9.925 6.216 10.883 ;
     RECT  52.992 10.741 53.016 10.931 ;
     RECT  7.8 6.899 8.112 11.269 ;
     RECT  12.24 10.739 13.512 11.365 ;
     RECT  43.632 10.789 45.912 11.365 ;
     RECT  49.248 10.741 49.416 11.365 ;
     RECT  43.344 11.365 45.912 11.509 ;
     RECT  49.008 11.365 49.416 11.555 ;
     RECT  2.4 10.883 5.496 11.747 ;
     RECT  49.392 11.555 49.416 11.747 ;
     RECT  24 8.003 24.312 11.941 ;
     RECT  40.2 5.987 40.512 11.941 ;
     RECT  67.2 9.539 67.512 11.941 ;
     RECT  68.544 9.539 68.568 11.941 ;
     RECT  69.888 10.837 69.912 12.085 ;
     RECT  67.2 11.941 68.568 12.131 ;
     RECT  6.72 12.133 6.744 12.277 ;
     RECT  7.8 11.269 8.232 12.277 ;
     RECT  2.4 11.747 4.344 12.323 ;
     RECT  69.888 12.085 70.008 12.323 ;
     RECT  27.264 10.501 27.288 12.325 ;
     RECT  6.72 12.277 8.232 12.419 ;
     RECT  11.424 11.365 13.512 12.467 ;
     RECT  69.888 12.323 69.912 12.467 ;
     RECT  5.472 11.747 5.496 12.469 ;
     RECT  11.424 12.467 11.448 12.469 ;
     RECT  10.8 12.469 11.448 12.515 ;
     RECT  42.48 11.509 45.912 12.515 ;
     RECT  54.96 5.795 54.984 12.517 ;
     RECT  34.224 10.741 35.112 12.563 ;
     RECT  56.4 10.595 56.712 12.565 ;
     RECT  5.472 12.469 6.36 12.899 ;
     RECT  5.472 12.899 5.496 12.995 ;
     RECT  23.472 11.941 24.312 13.043 ;
     RECT  39.264 11.941 40.512 13.043 ;
     RECT  78 10.595 78.6 13.045 ;
     RECT  54 12.517 54.984 13.139 ;
     RECT  56.304 12.565 56.712 13.427 ;
     RECT  72.6 6.515 72.912 13.477 ;
     RECT  54 13.139 54.024 13.571 ;
     RECT  4.224 12.323 4.344 13.619 ;
     RECT  2.4 12.323 2.712 13.621 ;
     RECT  43.344 12.515 45.912 13.621 ;
     RECT  67.2 12.131 68.28 13.621 ;
     RECT  7.8 12.419 8.232 13.715 ;
     RECT  26.688 12.325 27.288 13.715 ;
     RECT  10.8 12.515 10.824 13.859 ;
     RECT  26.688 13.715 26.712 14.099 ;
     RECT  24 13.043 24.312 14.197 ;
     RECT  42.288 13.429 42.312 14.197 ;
     RECT  43.344 13.621 46.104 14.197 ;
     RECT  42.288 14.197 46.104 14.243 ;
     RECT  67.2 13.621 68.376 14.291 ;
     RECT  2.4 13.621 2.808 14.387 ;
     RECT  12.528 12.467 13.512 14.485 ;
     RECT  49.2 13.573 49.224 14.531 ;
     RECT  5.136 13.621 5.16 14.627 ;
     RECT  69.648 13.477 69.672 14.723 ;
     RECT  76.368 12.517 76.392 14.725 ;
     RECT  18.6 2.151 18.912 14.773 ;
     RECT  76.032 14.725 76.392 14.867 ;
     RECT  71.76 13.477 72.912 14.915 ;
     RECT  12.528 14.485 14.28 14.963 ;
     RECT  42.576 14.243 46.104 15.013 ;
     RECT  42.576 15.013 46.536 15.107 ;
     RECT  13.056 14.963 14.28 15.443 ;
     RECT  47.664 14.485 47.688 15.491 ;
     RECT  57.888 14.197 57.912 15.635 ;
     RECT  76.032 14.867 76.056 15.683 ;
     RECT  34.8 12.563 35.112 15.733 ;
     RECT  29.4 10.451 30.36 15.877 ;
     RECT  67.2 14.291 68.28 15.877 ;
     RECT  61.8 2.151 62.112 15.925 ;
     RECT  17.472 14.917 17.496 16.019 ;
     RECT  36.432 15.349 36.456 16.019 ;
     RECT  34.8 15.733 35.208 16.067 ;
     RECT  65.04 15.349 65.064 16.115 ;
     RECT  61.8 15.925 63 16.261 ;
     RECT  61.8 16.261 63.048 16.357 ;
     RECT  78 13.045 78.936 16.357 ;
     RECT  43.344 15.107 46.536 16.501 ;
     RECT  54.672 16.357 54.696 16.549 ;
     RECT  71.376 15.973 71.4 16.595 ;
     RECT  61.536 16.357 63.048 16.787 ;
     RECT  38.208 14.773 38.232 16.933 ;
     RECT  61.536 16.787 63 17.075 ;
     RECT  54.096 16.549 54.696 17.123 ;
     RECT  64.992 16.885 65.016 17.123 ;
     RECT  40.2 13.043 40.512 17.461 ;
     RECT  31.92 15.349 31.944 17.605 ;
     RECT  43.344 16.501 46.632 17.605 ;
     RECT  4.56 16.405 4.584 17.699 ;
     RECT  50.592 9.013 51.312 17.797 ;
     RECT  13.056 15.443 13.512 17.989 ;
     RECT  29.28 15.877 30.36 18.037 ;
     RECT  77.904 16.357 78.936 18.467 ;
     RECT  5.952 15.925 5.976 18.469 ;
     RECT  12.912 17.989 13.512 18.517 ;
     RECT  12.912 18.517 13.656 18.563 ;
     RECT  5.952 18.469 6.744 18.613 ;
     RECT  57.984 17.605 58.008 18.707 ;
     RECT  54.672 17.123 54.696 18.757 ;
     RECT  27.216 17.605 27.24 18.851 ;
     RECT  38.064 16.933 38.232 18.851 ;
     RECT  61.536 17.075 62.112 18.851 ;
     RECT  67.2 15.877 68.376 18.851 ;
     RECT  29.04 18.037 30.36 19.235 ;
     RECT  14.736 17.989 14.76 19.285 ;
     RECT  31.92 17.605 32.904 19.285 ;
     RECT  5.76 18.613 6.744 19.379 ;
     RECT  29.04 19.235 30.264 19.427 ;
     RECT  43.248 17.605 46.632 19.427 ;
     RECT  67.2 18.851 67.992 19.427 ;
     RECT  14.736 19.285 14.856 19.475 ;
     RECT  31.92 19.285 33 19.475 ;
     RECT  13.056 18.563 13.656 19.523 ;
     RECT  40.08 17.461 40.512 19.523 ;
     RECT  53.952 18.757 54.696 19.667 ;
     RECT  31.92 19.475 31.944 19.763 ;
     RECT  43.248 19.427 43.272 19.763 ;
     RECT  44.352 19.427 46.632 19.811 ;
     RECT  45.024 19.811 46.632 19.859 ;
     RECT  45.12 19.859 46.632 19.907 ;
     RECT  13.056 19.523 13.512 19.909 ;
     RECT  70.656 19.333 70.68 19.955 ;
     RECT  26.784 19.909 26.808 20.051 ;
     RECT  14.832 19.475 14.856 20.099 ;
     RECT  23.616 14.197 24.312 20.195 ;
     RECT  45.216 19.907 46.632 20.339 ;
     RECT  28.08 19.909 28.104 20.483 ;
     RECT  12.528 19.909 13.512 20.579 ;
     RECT  38.208 18.851 38.232 20.579 ;
     RECT  6.72 19.379 6.744 20.629 ;
     RECT  22.512 19.381 22.536 20.725 ;
     RECT  65.904 17.605 65.928 20.867 ;
     RECT  45.216 20.339 46.104 20.915 ;
     RECT  36.768 20.485 36.792 20.917 ;
     RECT  36.768 20.917 36.888 20.963 ;
     RECT  50.4 17.797 51.312 21.013 ;
     RECT  9.888 18.181 9.912 21.155 ;
     RECT  11.232 20.677 11.256 21.155 ;
     RECT  21.552 20.725 22.536 21.155 ;
     RECT  36.864 20.963 36.888 21.155 ;
     RECT  45.216 20.915 45.912 21.155 ;
     RECT  32.976 19.475 33 21.251 ;
     RECT  7.8 13.715 8.112 21.349 ;
     RECT  45.504 21.155 45.912 21.395 ;
     RECT  50.4 21.013 51.432 21.443 ;
     RECT  61.8 18.851 62.112 21.445 ;
     RECT  6.48 20.629 6.744 21.493 ;
     RECT  7.8 21.349 9.288 21.493 ;
     RECT  67.2 19.427 67.848 21.493 ;
     RECT  40.2 19.523 40.512 21.589 ;
     RECT  18.48 14.773 18.912 21.637 ;
     RECT  6.48 21.493 9.288 21.731 ;
     RECT  2.4 14.387 2.712 22.165 ;
     RECT  72.6 14.915 72.912 22.165 ;
     RECT  38.784 21.637 38.808 22.211 ;
     RECT  18.48 21.637 19.8 22.259 ;
     RECT  21.552 21.155 21.576 22.259 ;
     RECT  61.8 21.445 62.76 22.259 ;
     RECT  78 18.467 78.936 22.259 ;
     RECT  54.672 19.667 54.696 22.499 ;
     RECT  29.088 19.427 30.264 22.835 ;
     RECT  72.384 22.165 72.912 22.835 ;
     RECT  29.4 22.835 30.264 23.125 ;
     RECT  2.4 22.165 3.624 23.555 ;
     RECT  19.92 22.741 19.944 23.555 ;
     RECT  5.472 22.069 5.496 23.701 ;
     RECT  6.72 21.731 9.288 23.701 ;
     RECT  24 20.195 24.312 23.701 ;
     RECT  60.576 22.741 60.6 23.843 ;
     RECT  50.496 21.443 51.432 23.987 ;
     RECT  34.8 16.067 35.112 24.133 ;
     RECT  5.472 23.701 9.288 24.325 ;
     RECT  72.6 22.835 72.912 24.421 ;
     RECT  61.8 22.259 62.112 24.469 ;
     RECT  64.656 22.693 64.68 24.469 ;
     RECT  72.6 24.421 73.896 24.469 ;
     RECT  78 22.259 78.312 24.469 ;
     RECT  34.704 24.133 35.112 24.659 ;
     RECT  54.48 22.741 54.504 24.659 ;
     RECT  16.752 22.165 16.776 24.803 ;
     RECT  32.592 22.741 32.616 25.093 ;
     RECT  12 24.469 12.024 25.139 ;
     RECT  32.352 25.093 32.616 25.139 ;
     RECT  61.8 24.469 62.904 25.187 ;
     RECT  64.656 24.469 64.968 25.187 ;
     RECT  48.048 22.117 48.072 25.669 ;
     RECT  52.464 24.229 52.488 25.715 ;
     RECT  72.336 24.469 73.896 25.715 ;
     RECT  76.896 24.469 78.312 25.715 ;
     RECT  48.048 25.669 48.456 25.813 ;
     RECT  32.352 25.139 32.376 26.005 ;
     RECT  45.6 21.395 45.912 26.101 ;
     RECT  18.6 22.259 18.912 26.197 ;
     RECT  0.144 26.053 0.168 26.243 ;
     RECT  37.008 25.573 37.032 26.243 ;
     RECT  60.096 25.093 60.12 26.245 ;
     RECT  61.8 25.187 62.112 26.245 ;
     RECT  60.096 26.245 62.112 26.291 ;
     RECT  67.2 21.493 68.088 26.389 ;
     RECT  56.4 13.427 56.712 26.629 ;
     RECT  67.2 26.389 68.184 26.629 ;
     RECT  18.48 26.197 19.848 26.771 ;
     RECT  24 23.701 25.128 26.771 ;
     RECT  64.656 25.187 64.68 26.771 ;
     RECT  67.2 26.629 68.376 26.771 ;
     RECT  15.408 26.101 15.432 26.819 ;
     RECT  55.824 26.629 57.288 26.819 ;
     RECT  47.904 25.813 48.456 26.915 ;
     RECT  69.408 26.197 69.432 27.203 ;
     RECT  72.336 25.715 72.912 27.203 ;
     RECT  32.016 26.005 32.376 27.301 ;
     RECT  78 25.715 78.312 27.349 ;
     RECT  76.896 25.715 76.92 27.395 ;
     RECT  55.824 26.819 56.712 27.443 ;
     RECT  45.6 26.101 46.008 27.587 ;
     RECT  48.432 26.915 48.456 27.877 ;
     RECT  13.056 20.579 13.512 27.971 ;
     RECT  32.016 27.301 32.472 27.971 ;
     RECT  29.4 23.125 30.504 28.021 ;
     RECT  29.4 28.021 31.272 28.067 ;
     RECT  22.224 27.877 22.248 28.163 ;
     RECT  40.2 21.589 41.16 28.165 ;
     RECT  2.4 23.555 2.712 28.309 ;
     RECT  64.32 27.877 64.344 28.499 ;
     RECT  48.432 27.877 48.504 28.933 ;
     RECT  29.4 28.067 29.712 29.029 ;
     RECT  18.6 26.771 19.848 29.123 ;
     RECT  38.736 24.229 38.76 29.171 ;
     RECT  39.888 28.165 41.16 29.267 ;
     RECT  53.568 27.157 53.592 29.509 ;
     RECT  32.448 27.971 32.472 29.651 ;
     RECT  54.672 27.589 54.696 29.651 ;
     RECT  4.8 24.325 9.288 29.699 ;
     RECT  2.304 28.309 2.712 29.795 ;
     RECT  53.472 29.509 53.592 29.843 ;
     RECT  75.12 27.157 75.144 29.941 ;
     RECT  36.096 28.261 36.12 30.083 ;
     RECT  5.472 29.699 9.288 30.181 ;
     RECT  48.384 28.933 48.792 30.421 ;
     RECT  50.496 23.987 51.312 30.469 ;
     RECT  75.12 29.941 76.056 30.565 ;
     RECT  29.184 29.029 29.712 30.611 ;
     RECT  78 27.349 78.408 30.611 ;
     RECT  34.8 24.659 35.112 30.709 ;
     RECT  48.192 30.421 48.792 30.709 ;
     RECT  74.64 30.565 76.056 30.755 ;
     RECT  5.472 30.181 9.576 30.803 ;
     RECT  53.568 29.843 53.592 30.803 ;
     RECT  75.12 30.755 76.056 30.851 ;
     RECT  13.2 27.971 13.512 31.045 ;
     RECT  13.104 31.045 13.512 31.187 ;
     RECT  2.4 29.795 2.712 31.525 ;
     RECT  3.984 30.421 4.008 31.525 ;
     RECT  48.192 30.709 48.888 31.715 ;
     RECT  78 30.611 78.312 31.765 ;
     RECT  45.6 27.587 45.912 31.861 ;
     RECT  36.912 30.661 36.936 31.907 ;
     RECT  13.2 31.187 13.512 31.909 ;
     RECT  2.4 31.525 4.008 31.955 ;
     RECT  76.032 30.851 76.056 31.955 ;
     RECT  11.712 26.629 11.736 32.149 ;
     RECT  65.184 29.029 65.208 32.341 ;
     RECT  65.184 32.341 65.4 32.387 ;
     RECT  54.048 30.997 54.072 32.483 ;
     RECT  50.496 30.469 51.432 32.531 ;
     RECT  13.2 31.909 13.608 32.579 ;
     RECT  44.88 31.861 45.912 32.725 ;
     RECT  50.832 32.531 51.432 32.725 ;
     RECT  50.832 32.725 51.72 32.867 ;
     RECT  11.712 32.149 11.928 32.915 ;
     RECT  13.2 32.579 13.512 32.917 ;
     RECT  37.488 32.389 37.512 33.013 ;
     RECT  13.056 32.917 13.512 33.059 ;
     RECT  31.248 28.067 31.272 33.107 ;
     RECT  34.608 30.709 35.112 33.251 ;
     RECT  2.4 31.955 3.432 33.299 ;
     RECT  21.744 30.181 21.768 33.299 ;
     RECT  37.488 33.013 37.608 33.299 ;
     RECT  44.88 32.725 46.44 33.299 ;
     RECT  61.056 26.291 62.112 33.397 ;
     RECT  11.712 32.915 11.736 33.779 ;
     RECT  67.2 26.771 68.04 33.877 ;
     RECT  40.2 29.267 41.16 33.925 ;
     RECT  65.376 32.387 65.4 33.971 ;
     RECT  5.472 30.803 9.288 34.117 ;
     RECT  77.04 31.765 78.312 34.117 ;
     RECT  13.2 33.059 13.512 34.165 ;
     RECT  15.456 28.357 15.48 34.259 ;
     RECT  77.04 34.117 79.08 34.597 ;
     RECT  39.6 33.925 41.16 34.645 ;
     RECT  31.824 34.117 31.848 34.741 ;
     RECT  50.88 32.867 51.72 34.741 ;
     RECT  56.4 27.443 56.712 34.741 ;
     RECT  37.584 33.299 37.608 34.789 ;
     RECT  37.104 34.789 37.608 34.835 ;
     RECT  49.92 34.741 51.72 35.123 ;
     RECT  43.152 34.741 43.176 35.171 ;
     RECT  66.912 33.877 68.04 35.317 ;
     RECT  38.688 34.645 41.16 35.363 ;
     RECT  10.416 34.213 10.44 35.365 ;
     RECT  10.416 35.365 10.536 35.459 ;
     RECT  12.528 34.165 13.512 35.507 ;
     RECT  55.872 34.741 56.712 35.555 ;
     RECT  18.6 29.123 18.912 35.557 ;
     RECT  17.664 35.557 18.912 35.747 ;
     RECT  5.472 34.117 9.336 35.845 ;
     RECT  31.344 34.741 31.848 35.939 ;
     RECT  77.04 34.597 79.224 35.941 ;
     RECT  37.104 34.835 37.128 36.275 ;
     RECT  31.344 35.939 31.608 36.515 ;
     RECT  39.312 35.363 41.16 36.611 ;
     RECT  13.2 35.507 13.512 36.805 ;
     RECT  29.4 30.611 29.712 36.997 ;
     RECT  63.36 36.085 63.384 37.091 ;
     RECT  5.472 35.845 9.48 37.285 ;
     RECT  10.512 35.459 10.536 37.285 ;
     RECT  45.6 33.299 46.44 37.381 ;
     RECT  48.864 31.715 48.888 37.427 ;
     RECT  38.784 37.045 38.808 37.621 ;
     RECT  40.08 36.611 41.16 37.621 ;
     RECT  45.6 37.381 47.064 37.667 ;
     RECT  66.912 35.317 68.376 37.669 ;
     RECT  66.672 37.669 68.376 37.907 ;
     RECT  5.472 37.285 10.536 38.099 ;
     RECT  50.88 35.123 51.72 38.435 ;
     RECT  18.192 35.747 18.912 38.677 ;
     RECT  18.192 38.677 19.752 38.819 ;
     RECT  29.4 36.997 30.216 38.819 ;
     RECT  75.216 36.613 75.24 38.915 ;
     RECT  72.6 27.203 72.912 39.013 ;
     RECT  66.912 37.907 68.376 39.059 ;
     RECT  45.6 37.667 45.912 39.061 ;
     RECT  47.04 37.667 47.064 39.061 ;
     RECT  13.2 36.805 13.704 39.203 ;
     RECT  45.6 39.061 47.064 39.299 ;
     RECT  38.784 37.621 41.16 39.347 ;
     RECT  72.48 39.013 72.912 39.443 ;
     RECT  76.896 35.941 79.224 39.731 ;
     RECT  45.6 39.299 46.488 39.923 ;
     RECT  64.848 39.349 64.872 40.019 ;
     RECT  29.4 38.819 30.072 40.067 ;
     RECT  5.472 38.099 9.72 40.165 ;
     RECT  39.888 39.347 41.16 40.405 ;
     RECT  38.784 39.347 38.808 40.499 ;
     RECT  59.232 39.301 59.256 40.547 ;
     RECT  69.408 38.149 69.432 40.595 ;
     RECT  66.912 39.059 67.512 40.643 ;
     RECT  44.448 39.253 44.472 40.741 ;
     RECT  13.2 39.203 13.512 41.029 ;
     RECT  50.88 38.435 51.312 41.075 ;
     RECT  0.192 30.661 0.216 41.171 ;
     RECT  39.792 40.405 41.16 41.221 ;
     RECT  43.584 40.741 44.472 41.267 ;
     RECT  12.48 41.029 13.512 41.363 ;
     RECT  39.792 41.221 41.304 41.363 ;
     RECT  67.2 40.643 67.512 41.365 ;
     RECT  31.584 36.515 31.608 41.411 ;
     RECT  26.592 40.837 26.616 41.459 ;
     RECT  10.848 41.461 10.872 41.509 ;
     RECT  58.56 41.221 58.584 41.509 ;
     RECT  39.888 41.363 41.304 41.605 ;
     RECT  39.888 41.605 41.928 41.651 ;
     RECT  77.856 39.731 79.224 41.651 ;
     RECT  2.4 33.299 2.712 42.037 ;
     RECT  34.8 33.251 35.112 42.037 ;
     RECT  2.4 42.037 3 42.179 ;
     RECT  37.008 41.317 37.032 42.179 ;
     RECT  61.056 33.397 62.232 42.181 ;
     RECT  67.2 41.365 67.752 42.227 ;
     RECT  10.848 41.509 11.448 42.275 ;
     RECT  61.056 42.181 62.712 42.277 ;
     RECT  5.472 40.165 9.864 42.325 ;
     RECT  10.848 42.275 10.872 42.325 ;
     RECT  40.2 41.651 41.928 42.373 ;
     RECT  40.2 42.373 42.168 42.419 ;
     RECT  26.88 41.509 26.904 42.611 ;
     RECT  4.368 34.501 4.392 42.661 ;
     RECT  5.472 42.325 10.872 42.661 ;
     RECT  32.16 42.709 32.184 42.757 ;
     RECT  2.4 42.179 2.904 42.995 ;
     RECT  32.16 42.757 33.144 43.139 ;
     RECT  78 41.651 79.224 43.237 ;
     RECT  4.368 42.661 10.872 43.285 ;
     RECT  43.584 41.267 43.608 43.285 ;
     RECT  75.072 42.565 75.096 43.379 ;
     RECT  4.368 43.285 11.4 43.427 ;
     RECT  34.8 42.037 35.352 43.427 ;
     RECT  13.2 41.363 13.512 43.765 ;
     RECT  14.832 43.285 14.856 43.765 ;
     RECT  4.368 43.427 10.68 43.811 ;
     RECT  29.4 40.067 29.712 43.861 ;
     RECT  67.2 42.227 67.512 43.861 ;
     RECT  58.56 41.509 59.256 43.907 ;
     RECT  43.584 43.285 44.472 43.955 ;
     RECT  68.976 42.709 69 43.955 ;
     RECT  4.512 43.811 10.68 44.051 ;
     RECT  42.144 42.419 42.168 44.051 ;
     RECT  51 41.075 51.312 44.053 ;
     RECT  13.056 43.765 14.856 44.099 ;
     RECT  51 44.053 51.768 44.149 ;
     RECT  2.4 42.995 2.808 44.243 ;
     RECT  61.056 42.277 62.808 44.243 ;
     RECT  51 44.149 51.816 44.339 ;
     RECT  5.472 44.051 10.68 44.773 ;
     RECT  40.2 42.419 41.16 44.965 ;
     RECT  76.608 42.709 76.632 45.013 ;
     RECT  76.368 45.013 76.632 45.059 ;
     RECT  77.904 43.237 79.224 45.059 ;
     RECT  5.472 44.773 11.4 45.155 ;
     RECT  48.096 43.285 48.12 45.155 ;
     RECT  51 44.339 51.768 45.203 ;
     RECT  13.056 44.099 14.28 45.205 ;
     RECT  77.904 45.059 78.648 45.251 ;
     RECT  12.96 45.205 14.28 45.491 ;
     RECT  18.6 38.819 18.912 45.493 ;
     RECT  56.4 35.555 56.712 45.541 ;
     RECT  39.888 44.965 41.16 45.587 ;
     RECT  33.264 44.869 33.288 45.731 ;
     RECT  59.856 44.341 59.88 45.731 ;
     RECT  17.568 44.869 17.592 46.019 ;
     RECT  78 45.251 78.648 46.019 ;
     RECT  58.56 43.907 58.584 46.117 ;
     RECT  10.464 45.155 11.4 46.259 ;
     RECT  56.4 45.541 56.808 46.259 ;
     RECT  13.2 45.491 14.28 46.355 ;
     RECT  70.128 45.397 70.152 46.453 ;
     RECT  18.6 45.493 19.656 46.547 ;
     RECT  18.6 46.547 18.912 46.549 ;
     RECT  76.368 45.059 76.392 46.645 ;
     RECT  70.128 46.453 70.536 46.693 ;
     RECT  54.384 44.869 54.408 46.741 ;
     RECT  69.408 46.693 70.536 46.787 ;
     RECT  24 26.771 24.312 46.789 ;
     RECT  25.344 42.709 25.368 46.835 ;
     RECT  51 45.203 51.312 46.885 ;
     RECT  48.192 46.501 48.216 46.931 ;
     RECT  54.384 46.741 54.744 47.075 ;
     RECT  50.88 46.885 51.312 47.125 ;
     RECT  40.2 45.587 41.16 47.173 ;
     RECT  61.056 44.243 62.616 47.173 ;
     RECT  5.472 45.155 9.48 47.221 ;
     RECT  5.424 47.221 9.48 47.269 ;
     RECT  10.464 46.259 11.112 47.269 ;
     RECT  75.408 46.645 76.392 47.363 ;
     RECT  29.088 43.861 29.712 47.653 ;
     RECT  75.408 47.363 75.432 47.797 ;
     RECT  75.216 47.797 75.432 47.843 ;
     RECT  67.104 43.861 67.512 47.845 ;
     RECT  58.56 46.117 59.256 47.891 ;
     RECT  5.424 47.269 11.112 47.893 ;
     RECT  28.656 47.653 29.712 47.939 ;
     RECT  36.432 43.525 36.456 47.939 ;
     RECT  60.528 47.173 62.616 47.939 ;
     RECT  29.088 47.939 29.712 48.371 ;
     RECT  69.408 46.787 69.432 48.373 ;
     RECT  70.512 46.787 70.536 48.373 ;
     RECT  61.056 47.939 62.616 48.421 ;
     RECT  66.96 47.845 67.512 48.515 ;
     RECT  32.16 43.139 32.184 48.659 ;
     RECT  75.216 47.843 75.24 48.659 ;
     RECT  69.408 48.373 70.536 48.853 ;
     RECT  21.12 47.845 21.144 48.997 ;
     RECT  78 46.019 78.312 48.997 ;
     RECT  37.008 48.901 37.032 49.043 ;
     RECT  54.384 47.075 54.408 49.285 ;
     RECT  5.04 47.893 11.112 49.477 ;
     RECT  21.024 48.997 21.144 49.477 ;
     RECT  43.584 43.955 43.608 49.523 ;
     RECT  50.112 47.125 51.312 49.523 ;
     RECT  5.04 49.477 11.4 49.571 ;
     RECT  5.04 49.571 9.72 49.619 ;
     RECT  21.024 49.477 21.24 49.619 ;
     RECT  32.112 48.949 32.136 49.619 ;
     RECT  53.472 49.285 54.408 49.619 ;
     RECT  77.808 48.997 78.312 49.763 ;
     RECT  21.216 49.619 21.24 50.005 ;
     RECT  58.56 47.891 58.584 50.051 ;
     RECT  53.472 49.619 54.168 50.147 ;
     RECT  23.04 46.789 24.312 50.293 ;
     RECT  16.512 48.277 16.536 50.387 ;
     RECT  45.6 39.923 45.912 50.389 ;
     RECT  11.376 49.571 11.4 50.435 ;
     RECT  40.08 47.173 41.16 50.579 ;
     RECT  13.2 46.355 13.512 50.581 ;
     RECT  5.424 49.619 9.72 50.677 ;
     RECT  48.72 50.389 48.744 50.677 ;
     RECT  21.216 50.005 21.624 50.771 ;
     RECT  50.736 49.523 51.312 50.771 ;
     RECT  61.056 48.421 62.904 50.819 ;
     RECT  48.72 50.677 49.32 50.965 ;
     RECT  18.48 46.549 18.912 51.107 ;
     RECT  32.832 50.677 32.856 51.107 ;
     RECT  18.6 51.107 18.912 51.205 ;
     RECT  45.6 50.389 46.824 51.251 ;
     RECT  23.04 50.293 25.08 51.347 ;
     RECT  59.52 50.773 59.544 51.493 ;
     RECT  23.088 51.347 25.08 51.635 ;
     RECT  5.424 50.677 10.584 51.781 ;
     RECT  18.6 51.205 19.032 51.923 ;
     RECT  23.088 51.635 24.312 51.923 ;
     RECT  48.48 50.965 49.32 51.923 ;
     RECT  59.184 51.493 59.544 51.923 ;
     RECT  69.408 48.853 70.632 51.923 ;
     RECT  53.472 50.147 53.496 52.309 ;
     RECT  53.136 52.309 53.496 52.405 ;
     RECT  42.768 51.205 42.792 52.499 ;
     RECT  70.272 51.923 70.632 52.499 ;
     RECT  79.776 47.845 79.8 52.499 ;
     RECT  61.2 50.819 62.904 52.979 ;
     RECT  18.6 51.923 18.912 52.981 ;
     RECT  48.48 51.923 48.504 53.027 ;
     RECT  70.608 52.499 70.632 53.027 ;
     RECT  18.6 52.981 19.416 53.029 ;
     RECT  3.936 50.389 3.96 53.075 ;
     RECT  5.424 51.781 11.16 53.075 ;
     RECT  18.192 53.029 19.416 53.171 ;
     RECT  34.8 43.427 35.112 53.557 ;
     RECT  45.6 51.251 45.912 53.557 ;
     RECT  78 49.763 78.312 53.557 ;
     RECT  5.424 53.075 8.376 53.603 ;
     RECT  16.464 50.677 16.488 53.795 ;
     RECT  61.8 52.979 62.904 53.795 ;
     RECT  56.4 46.259 56.712 53.893 ;
     RECT  9.504 53.075 11.16 54.083 ;
     RECT  53.136 52.405 54.168 54.083 ;
     RECT  56.304 53.893 56.712 54.085 ;
     RECT  57.744 53.893 57.768 54.085 ;
     RECT  21.6 50.771 21.624 54.179 ;
     RECT  45.6 53.557 46.728 54.323 ;
     RECT  59.184 51.923 59.208 54.323 ;
     RECT  53.136 54.083 53.544 54.613 ;
     RECT  70.224 54.085 70.248 54.613 ;
     RECT  18.6 53.171 19.416 54.661 ;
     RECT  67.2 48.515 67.512 54.661 ;
     RECT  2.4 44.243 2.712 54.709 ;
     RECT  47.904 53.941 47.928 54.755 ;
     RECT  52.464 54.613 53.544 54.755 ;
     RECT  51 50.771 51.312 54.997 ;
     RECT  52.464 54.755 52.488 54.997 ;
     RECT  5.424 53.603 8.28 55.237 ;
     RECT  9.504 54.083 10.104 55.237 ;
     RECT  43.872 54.325 43.896 55.331 ;
     RECT  51 54.997 52.488 55.331 ;
     RECT  69.36 54.613 70.248 55.379 ;
     RECT  65.52 51.829 65.544 55.427 ;
     RECT  30.72 54.853 30.744 55.475 ;
     RECT  72.6 39.443 72.912 55.765 ;
     RECT  29.136 48.371 29.712 55.813 ;
     RECT  61.8 53.795 62.112 55.813 ;
     RECT  55.536 54.085 57.768 56.099 ;
     RECT  67.2 54.661 68.232 56.195 ;
     RECT  11.136 54.083 11.16 56.243 ;
     RECT  61.8 55.813 62.808 56.243 ;
     RECT  13.2 50.581 13.656 56.341 ;
     RECT  51 55.331 52.152 56.389 ;
     RECT  66.096 56.053 66.12 56.483 ;
     RECT  2.4 54.709 3.432 56.531 ;
     RECT  24 51.923 24.312 56.629 ;
     RECT  72.048 55.765 72.912 56.723 ;
     RECT  59.856 55.237 59.88 56.773 ;
     RECT  5.424 55.237 10.104 57.013 ;
     RECT  45.6 54.323 46.296 57.059 ;
     RECT  58.896 56.773 59.88 57.107 ;
     RECT  36.288 54.085 36.312 57.109 ;
     RECT  13.2 56.341 14.232 57.155 ;
     RECT  32.784 56.581 32.808 57.251 ;
     RECT  24 56.629 24.504 57.299 ;
     RECT  36.288 57.109 37.08 57.347 ;
     RECT  30.864 56.629 30.888 57.443 ;
     RECT  37.056 57.347 37.08 57.443 ;
     RECT  61.8 56.243 62.112 57.445 ;
     RECT  5.424 57.013 10.2 57.683 ;
     RECT  58.896 57.107 58.92 57.875 ;
     RECT  57.744 56.099 57.768 57.923 ;
     RECT  45.6 57.059 45.912 57.973 ;
     RECT  51 56.389 52.248 57.973 ;
     RECT  51 57.973 52.536 58.021 ;
     RECT  29.088 55.813 29.712 58.117 ;
     RECT  18.6 54.661 19.848 58.163 ;
     RECT  63.936 56.533 63.96 58.163 ;
     RECT  5.472 57.683 10.2 58.307 ;
     RECT  5.472 58.307 9.096 58.355 ;
     RECT  24 57.299 24.456 58.739 ;
     RECT  45.504 57.973 45.912 58.739 ;
     RECT  59.808 58.117 59.832 58.739 ;
     RECT  74.064 57.253 74.088 58.739 ;
     RECT  78 53.557 79.176 58.739 ;
     RECT  43.776 57.973 43.8 58.787 ;
     RECT  32.592 57.733 32.616 58.835 ;
     RECT  31.2 57.877 31.272 59.269 ;
     RECT  30.816 59.269 31.272 59.315 ;
     RECT  34.8 53.557 35.208 59.315 ;
     RECT  50.256 58.021 52.536 59.315 ;
     RECT  75.12 53.413 75.144 59.315 ;
     RECT  27.888 58.645 27.912 59.411 ;
     RECT  10.176 58.307 10.2 59.507 ;
     RECT  78 58.739 78.84 59.507 ;
     RECT  29.088 58.117 29.832 59.651 ;
     RECT  65.376 57.829 65.4 59.747 ;
     RECT  29.28 59.651 29.832 59.797 ;
     RECT  30.816 59.315 31.224 59.797 ;
     RECT  2.4 56.531 2.712 59.941 ;
     RECT  49.008 58.885 49.032 59.941 ;
     RECT  48.864 59.941 49.032 59.987 ;
     RECT  61.68 57.445 62.112 60.131 ;
     RECT  63.984 59.797 64.008 60.133 ;
     RECT  24 58.739 24.312 60.277 ;
     RECT  29.28 59.797 31.224 60.323 ;
     RECT  5.472 58.355 8.28 60.373 ;
     RECT  78 59.507 78.312 60.373 ;
     RECT  23.232 60.277 24.312 60.419 ;
     RECT  63.792 60.133 64.008 60.611 ;
     RECT  48.864 59.987 48.888 60.613 ;
     RECT  2.4 59.941 2.808 60.851 ;
     RECT  55.536 56.099 56.712 60.949 ;
     RECT  5.472 60.373 8.808 60.995 ;
     RECT  55.296 60.949 56.712 60.995 ;
     RECT  58.704 60.277 58.728 61.043 ;
     RECT  29.28 60.323 30.792 61.189 ;
     RECT  24 60.419 24.312 61.333 ;
     RECT  40.2 50.579 41.16 61.381 ;
     RECT  34.8 59.315 35.112 61.429 ;
     RECT  61.8 60.131 62.112 61.477 ;
     RECT  53.52 54.755 53.544 61.573 ;
     RECT  37.92 60.901 37.944 61.619 ;
     RECT  44.256 58.981 44.28 61.619 ;
     RECT  50.256 59.315 52.248 61.619 ;
     RECT  46.944 59.221 46.968 61.717 ;
     RECT  11.904 61.045 11.928 61.861 ;
     RECT  13.2 57.155 13.656 61.861 ;
     RECT  77.28 60.373 78.312 61.861 ;
     RECT  11.904 61.861 13.656 61.907 ;
     RECT  72.6 56.723 72.912 61.909 ;
     RECT  5.472 60.995 8.28 61.957 ;
     RECT  0.144 61.813 0.168 62.003 ;
     RECT  50.4 61.619 52.248 62.003 ;
     RECT  76.944 61.861 78.312 62.005 ;
     RECT  5.472 61.957 8.664 62.053 ;
     RECT  76.944 62.005 78.408 62.053 ;
     RECT  28.608 61.189 30.792 62.147 ;
     RECT  10.128 60.613 10.152 62.149 ;
     RECT  12 61.907 13.656 62.149 ;
     RECT  10.128 62.149 10.584 62.195 ;
     RECT  18.6 58.163 19.752 62.195 ;
     RECT  76.944 62.053 78.792 62.195 ;
     RECT  40.2 61.381 42.072 62.291 ;
     RECT  34.8 61.429 35.448 62.341 ;
     RECT  46.944 61.717 47.304 62.341 ;
     RECT  48.336 60.613 48.888 62.341 ;
     RECT  5.424 62.053 8.664 62.485 ;
     RECT  40.2 62.291 41.16 62.531 ;
     RECT  5.424 62.485 8.712 62.533 ;
     RECT  5.424 62.533 8.856 62.629 ;
     RECT  24 61.333 24.456 62.629 ;
     RECT  55.296 60.995 55.32 62.629 ;
     RECT  56.4 60.995 56.712 62.629 ;
     RECT  63.792 60.611 63.816 62.629 ;
     RECT  53.52 61.573 53.64 62.675 ;
     RECT  50.4 62.003 52.2 62.723 ;
     RECT  76.944 62.195 76.968 62.819 ;
     RECT  2.4 60.851 2.712 62.821 ;
     RECT  72.432 61.909 72.912 62.915 ;
     RECT  46.944 62.341 48.888 62.917 ;
     RECT  10.56 62.195 10.584 63.011 ;
     RECT  67.2 56.195 67.512 63.061 ;
     RECT  55.296 62.629 56.712 63.107 ;
     RECT  69.36 55.379 69.384 63.107 ;
     RECT  61.8 61.477 62.328 63.109 ;
     RECT  63.648 62.629 63.816 63.203 ;
     RECT  67.104 63.061 67.512 63.205 ;
     RECT  34.8 62.341 35.88 63.251 ;
     RECT  5.184 62.629 8.856 63.299 ;
     RECT  63.648 63.203 63.672 63.299 ;
     RECT  45.6 58.739 45.912 63.637 ;
     RECT  46.944 62.917 49.08 63.637 ;
     RECT  2.4 62.821 3.576 63.779 ;
     RECT  12 62.149 14.184 63.779 ;
     RECT  28.608 62.147 30.216 63.779 ;
     RECT  45.6 63.637 49.08 63.877 ;
     RECT  50.4 62.723 51.312 63.877 ;
     RECT  61.8 63.109 62.424 63.923 ;
     RECT  78 62.195 78.792 64.115 ;
     RECT  45.6 63.877 51.312 64.307 ;
     RECT  28.608 63.779 29.712 64.355 ;
     RECT  34.8 63.251 35.448 64.357 ;
     RECT  58.896 62.005 58.92 64.357 ;
     RECT  53.616 62.675 53.64 64.595 ;
     RECT  72.6 62.915 72.912 64.597 ;
     RECT  12 63.779 13.752 64.643 ;
     RECT  34.8 64.357 35.88 64.643 ;
     RECT  24 62.629 24.504 64.693 ;
     RECT  45.6 64.307 49.656 64.931 ;
     RECT  52.56 64.693 52.584 64.931 ;
     RECT  58.128 64.357 58.92 64.931 ;
     RECT  40.2 62.531 40.512 64.933 ;
     RECT  45.6 64.931 48.36 64.933 ;
     RECT  58.896 64.931 58.92 65.027 ;
     RECT  38.832 64.405 38.856 65.075 ;
     RECT  55.296 63.107 55.32 65.171 ;
     RECT  7.008 63.299 8.856 65.173 ;
     RECT  78 64.115 78.408 65.509 ;
     RECT  5.184 63.299 5.784 65.603 ;
     RECT  12.24 64.643 13.752 65.651 ;
     RECT  23.568 64.693 24.504 65.651 ;
     RECT  42.144 64.933 42.168 65.699 ;
     RECT  40.08 64.933 40.512 65.795 ;
     RECT  5.184 65.603 5.208 65.939 ;
     RECT  7.008 65.173 9.048 65.939 ;
     RECT  0.144 65.797 0.168 65.987 ;
     RECT  13.104 65.651 13.752 65.987 ;
     RECT  16.032 63.157 16.056 66.083 ;
     RECT  27.36 65.845 27.384 66.085 ;
     RECT  28.8 64.355 29.712 66.131 ;
     RECT  72.48 64.597 72.912 66.179 ;
     RECT  61.8 63.923 62.232 66.323 ;
     RECT  24 65.651 24.504 66.707 ;
     RECT  27.264 66.085 27.384 66.707 ;
     RECT  27.36 66.707 27.384 66.755 ;
     RECT  58.656 66.085 58.68 66.755 ;
     RECT  49.632 64.931 49.656 66.851 ;
     RECT  34.8 64.643 35.112 66.853 ;
     RECT  44.736 64.933 48.36 66.899 ;
     RECT  56.4 63.107 56.712 67.381 ;
     RECT  7.008 65.939 8.568 67.525 ;
     RECT  51 64.307 51.312 67.669 ;
     RECT  66.96 63.205 67.512 67.669 ;
     RECT  32.832 66.661 32.856 67.765 ;
     RECT  11.568 65.653 11.592 67.811 ;
     RECT  6.912 67.525 8.568 67.859 ;
     RECT  78 65.509 78.936 67.907 ;
     RECT  66.96 67.669 68.232 68.099 ;
     RECT  32.736 67.765 32.856 68.197 ;
     RECT  45.6 66.899 48.36 68.245 ;
     RECT  38.784 65.317 38.808 68.339 ;
     RECT  2.4 63.779 2.712 68.341 ;
     RECT  13.104 65.987 13.512 68.341 ;
     RECT  54.672 66.709 54.696 68.341 ;
     RECT  45.456 68.245 48.36 68.435 ;
     RECT  34.8 66.853 35.208 68.531 ;
     RECT  36.912 67.669 36.936 68.677 ;
     RECT  54.336 68.341 54.696 68.725 ;
     RECT  54 68.725 54.696 68.915 ;
     RECT  54 68.915 54.6 68.917 ;
     RECT  6.912 67.859 8.112 68.963 ;
     RECT  2.4 68.341 2.952 69.107 ;
     RECT  5.472 69.253 5.496 69.301 ;
     RECT  60.624 68.101 60.648 69.301 ;
     RECT  5.472 69.301 5.592 69.349 ;
     RECT  46.992 68.435 47.784 69.491 ;
     RECT  13.104 68.341 13.608 69.493 ;
     RECT  51 67.669 51.672 69.493 ;
     RECT  36.864 68.677 36.936 69.587 ;
     RECT  66.96 68.099 67.512 69.587 ;
     RECT  32.736 68.197 33.048 69.731 ;
     RECT  45.456 68.435 45.912 69.779 ;
     RECT  72.6 66.179 72.912 69.781 ;
     RECT  69.36 67.717 69.384 69.827 ;
     RECT  59.856 69.301 60.648 69.971 ;
     RECT  47.04 69.491 47.784 70.117 ;
     RECT  78 67.907 78.408 70.163 ;
     RECT  13.104 69.493 13.848 70.259 ;
     RECT  72.6 69.781 73.416 70.259 ;
     RECT  40.2 65.795 40.512 70.453 ;
     RECT  61.8 66.323 62.112 70.597 ;
     RECT  36.864 69.587 36.888 70.645 ;
     RECT  27.936 68.917 27.96 70.691 ;
     RECT  53.904 68.917 54.6 70.789 ;
     RECT  47.04 70.117 47.88 70.835 ;
     RECT  75.12 70.405 75.144 70.933 ;
     RECT  52.992 70.789 54.6 70.979 ;
     RECT  2.4 69.107 2.712 71.173 ;
     RECT  72.6 70.259 73.368 71.317 ;
     RECT  5.376 69.349 5.592 71.363 ;
     RECT  75.12 70.933 75.864 71.363 ;
     RECT  72.6 71.317 73.752 71.699 ;
     RECT  64.944 67.765 64.968 71.891 ;
     RECT  5.472 71.363 5.592 71.939 ;
     RECT  32.736 69.731 32.76 72.037 ;
     RECT  32.496 72.037 32.76 72.083 ;
     RECT  38.496 71.077 38.52 72.323 ;
     RECT  13.104 70.259 13.608 72.325 ;
     RECT  13.104 72.325 13.656 72.421 ;
     RECT  47.088 70.835 47.88 72.467 ;
     RECT  75.84 71.363 75.864 72.613 ;
     RECT  36.432 70.645 36.888 72.755 ;
     RECT  41.856 72.181 41.88 72.995 ;
     RECT  72.6 71.699 73.56 72.995 ;
     RECT  29.28 66.131 29.712 73.045 ;
     RECT  5.568 71.939 5.592 73.139 ;
     RECT  53.808 70.979 54.6 73.139 ;
     RECT  75.552 72.613 75.864 73.235 ;
     RECT  29.28 73.045 29.832 73.237 ;
     RECT  39.696 70.453 40.512 73.237 ;
     RECT  53.808 73.139 54.024 73.285 ;
     RECT  38.784 73.237 40.512 73.381 ;
     RECT  45.6 69.779 45.912 73.477 ;
     RECT  7.44 68.963 8.112 73.571 ;
     RECT  38.64 73.381 40.512 73.571 ;
     RECT  28.896 73.237 29.928 73.667 ;
     RECT  71.232 72.901 71.256 73.763 ;
     RECT  4.464 73.237 4.488 74.003 ;
     RECT  47.088 72.467 47.16 74.053 ;
     RECT  36.432 72.755 36.456 74.099 ;
     RECT  47.088 74.053 47.88 74.147 ;
     RECT  72.6 72.995 73.368 74.147 ;
     RECT  56.4 67.381 56.808 74.195 ;
     RECT  10.848 71.797 10.872 74.387 ;
     RECT  32.496 72.083 32.52 74.581 ;
     RECT  32.496 74.581 32.808 74.627 ;
     RECT  2.4 71.173 2.808 74.629 ;
     RECT  12.912 72.421 13.656 74.629 ;
     RECT  44.88 73.477 45.912 74.723 ;
     RECT  47.136 74.147 47.88 74.723 ;
     RECT  53.664 73.285 54.024 74.723 ;
     RECT  12 74.629 13.656 74.867 ;
     RECT  47.136 74.723 47.16 74.915 ;
     RECT  51 69.493 51.72 74.917 ;
     RECT  38.64 73.571 38.808 75.013 ;
     RECT  40.2 73.571 40.512 75.013 ;
     RECT  12.96 74.867 13.656 75.155 ;
     RECT  29.4 73.667 29.928 75.157 ;
     RECT  78 70.163 78.312 75.157 ;
     RECT  50.88 74.917 51.72 75.205 ;
     RECT  9.552 73.621 9.576 75.299 ;
     RECT  59.856 69.971 59.88 75.349 ;
     RECT  12.96 75.155 13.512 75.395 ;
     RECT  59.856 75.349 60.12 75.395 ;
     RECT  72.6 74.147 72.912 75.397 ;
     RECT  50.88 75.205 52.44 75.491 ;
     RECT  29.4 75.157 30.84 75.731 ;
     RECT  27.216 74.965 27.24 75.779 ;
     RECT  11.424 75.157 11.544 75.875 ;
     RECT  72.48 75.397 72.912 76.403 ;
     RECT  77.904 75.157 78.312 76.403 ;
     RECT  2.4 74.629 2.856 76.451 ;
     RECT  30.816 75.731 30.84 76.451 ;
     RECT  51 75.491 52.44 76.501 ;
     RECT  32.784 74.627 32.808 76.883 ;
     RECT  4.512 75.109 4.536 76.979 ;
     RECT  38.64 75.013 40.512 76.979 ;
     RECT  29.4 75.731 29.832 77.029 ;
     RECT  29.232 77.029 29.832 77.125 ;
     RECT  14.928 72.805 14.952 77.171 ;
     RECT  5.712 76.357 5.736 77.173 ;
     RECT  5.712 77.173 5.928 77.219 ;
     RECT  29.232 77.125 30.792 77.461 ;
     RECT  53.664 74.723 53.688 77.507 ;
     RECT  43.392 68.341 43.416 77.555 ;
     RECT  75.552 73.235 75.576 77.555 ;
     RECT  11.52 75.875 11.544 77.843 ;
     RECT  51 76.501 52.488 77.939 ;
     RECT  60.096 75.395 60.12 77.941 ;
     RECT  60.096 77.941 60.408 77.987 ;
     RECT  52.464 77.939 52.488 78.131 ;
     RECT  28.56 77.461 30.792 78.227 ;
     RECT  28.56 78.227 29.712 78.467 ;
     RECT  60.384 77.987 60.408 78.707 ;
     RECT  61.8 70.597 62.424 78.707 ;
     RECT  61.8 78.707 62.112 78.901 ;
     RECT  5.904 77.219 5.928 78.997 ;
     RECT  30.768 78.227 30.792 79.187 ;
     RECT  48.24 78.085 48.264 79.187 ;
     RECT  5.904 78.997 6.792 79.235 ;
     RECT  14.88 78.037 14.904 79.235 ;
     RECT  41.808 78.613 41.832 79.235 ;
     RECT  61.104 78.901 62.112 79.427 ;
     RECT  6.768 79.235 6.792 79.475 ;
     RECT  39.552 76.979 40.512 79.523 ;
     RECT  2.4 76.451 2.712 79.929 ;
     RECT  7.8 73.571 8.112 79.929 ;
     RECT  13.2 75.395 13.512 79.929 ;
     RECT  18.6 62.195 18.912 79.929 ;
     RECT  24 66.707 24.312 79.929 ;
     RECT  29.4 78.467 29.712 79.929 ;
     RECT  34.8 68.531 35.112 79.929 ;
     RECT  40.2 79.523 40.512 79.929 ;
     RECT  45.6 74.723 45.912 79.929 ;
     RECT  51 77.939 51.312 79.929 ;
     RECT  56.4 74.195 56.712 79.929 ;
     RECT  61.8 79.427 62.112 79.929 ;
     RECT  67.2 69.587 67.512 79.929 ;
     RECT  72.6 76.403 72.912 79.929 ;
     RECT  78 76.403 78.312 79.929 ;
     RECT  2.4 79.929 2.52 79.943 ;
     RECT  7.8 79.929 7.92 79.943 ;
     RECT  13.2 79.929 13.32 79.943 ;
     RECT  18.6 79.929 18.72 79.943 ;
     RECT  24 79.929 24.12 79.943 ;
     RECT  29.4 79.929 29.52 79.943 ;
     RECT  34.8 79.929 34.92 79.943 ;
     RECT  40.2 79.929 40.32 79.943 ;
     RECT  45.6 79.929 45.72 79.943 ;
     RECT  51 79.929 51.12 79.943 ;
     RECT  56.4 79.929 56.52 79.943 ;
     RECT  61.8 79.929 61.92 79.943 ;
     RECT  67.2 79.929 67.32 79.943 ;
     RECT  72.6 79.929 72.72 79.943 ;
     RECT  78 79.929 78.12 79.943 ;
     RECT  56.712 2.245 58.176 3.059 ;
     RECT  70.44 2.773 71.856 3.443 ;
     RECT  53.496 3.397 54.816 3.443 ;
     RECT  71.76 3.443 71.856 4.453 ;
     RECT  2.712 3.445 3.696 5.269 ;
     RECT  55.128 4.117 56.4 4.595 ;
     RECT  3.72 4.501 5.184 9.109 ;
     RECT  44.472 4.501 45.6 5.413 ;
     RECT  54.888 4.595 56.4 5.749 ;
     RECT  44.448 5.459 44.496 6.709 ;
     RECT  5.208 5.605 6.72 5.653 ;
     RECT  6.744 5.605 7.8 9.731 ;
     RECT  5.688 5.653 6.72 6.277 ;
     RECT  45.912 5.653 46.992 6.853 ;
     RECT  54.984 5.749 56.4 7.909 ;
     RECT  5.208 6.419 6.24 8.293 ;
     RECT  40.512 6.805 41.808 7.715 ;
     RECT  54.984 7.909 56.208 9.059 ;
     RECT  49.272 9.013 50.592 10.741 ;
     RECT  57 9.013 58.464 9.155 ;
     RECT  54.984 9.059 56.4 12.565 ;
     RECT  3.912 9.109 5.184 9.925 ;
     RECT  67.512 9.539 68.544 11.941 ;
     RECT  49.416 10.741 50.592 11.747 ;
     RECT  68.568 10.837 69.888 12.131 ;
     RECT  5.496 10.883 6.216 12.133 ;
     RECT  4.344 11.747 5.472 12.995 ;
     RECT  68.28 12.131 69.888 12.467 ;
     RECT  5.496 12.133 6.72 12.419 ;
     RECT  6.744 12.133 7.8 12.277 ;
     RECT  2.712 12.323 4.224 13.619 ;
     RECT  5.496 12.419 7.8 12.469 ;
     RECT  11.448 12.467 12.528 12.515 ;
     RECT  68.28 12.467 69.672 13.477 ;
     RECT  6.36 12.469 7.8 12.899 ;
     RECT  42.48 12.515 43.344 13.429 ;
     RECT  54.984 12.565 56.304 13.139 ;
     RECT  4.344 12.995 5.16 13.619 ;
     RECT  23.616 13.043 24 14.197 ;
     RECT  42.312 13.429 43.344 14.197 ;
     RECT  68.28 13.477 69.648 13.621 ;
     RECT  49.224 13.573 50.592 14.531 ;
     RECT  2.712 13.619 2.808 13.621 ;
     RECT  5.136 13.619 5.16 13.621 ;
     RECT  68.376 13.621 69.648 14.291 ;
     RECT  56.712 14.197 57.888 15.635 ;
     RECT  68.28 14.291 69.648 14.723 ;
     RECT  47.688 14.485 49.2 14.531 ;
     RECT  68.28 14.723 68.376 15.877 ;
     RECT  71.76 14.915 72.6 15.973 ;
     RECT  17.496 14.917 18.48 16.019 ;
     RECT  46.536 15.013 47.664 15.491 ;
     RECT  35.112 15.349 36.432 15.733 ;
     RECT  46.536 15.491 46.632 16.501 ;
     RECT  35.208 15.733 36.432 16.019 ;
     RECT  71.4 15.973 72.6 16.595 ;
     RECT  4.584 16.405 5.952 17.699 ;
     RECT  56.712 17.605 57.984 18.707 ;
     RECT  65.928 17.605 67.2 20.867 ;
     RECT  5.76 17.699 5.952 18.613 ;
     RECT  13.512 17.989 14.736 18.517 ;
     RECT  6.744 18.469 7.8 21.493 ;
     RECT  13.656 18.517 14.736 19.475 ;
     RECT  12.912 18.563 13.056 19.909 ;
     RECT  27.216 18.851 27.24 19.909 ;
     RECT  6.48 19.379 6.72 20.629 ;
     RECT  22.536 19.381 23.616 20.195 ;
     RECT  29.04 19.427 29.088 19.909 ;
     RECT  43.272 19.427 44.352 19.763 ;
     RECT  13.656 19.475 14.832 19.523 ;
     RECT  31.944 19.475 32.976 19.763 ;
     RECT  13.512 19.523 14.832 20.099 ;
     RECT  26.808 19.909 28.08 20.051 ;
     RECT  28.104 19.909 29.088 20.483 ;
     RECT  22.536 20.195 24 21.155 ;
     RECT  36.792 20.485 38.208 20.579 ;
     RECT  36.792 20.579 36.888 20.917 ;
     RECT  9.912 20.677 11.232 21.155 ;
     RECT  38.808 21.637 40.2 22.211 ;
     RECT  6.48 21.731 6.72 22.069 ;
     RECT  5.496 22.069 6.72 23.701 ;
     RECT  18.912 22.259 19.8 22.741 ;
     RECT  18.912 22.741 19.92 23.555 ;
     RECT  60.6 22.741 61.8 23.843 ;
     RECT  51.312 23.987 51.432 24.229 ;
     RECT  38.76 24.229 40.2 28.165 ;
     RECT  51.312 24.229 52.464 25.715 ;
     RECT  12.024 24.469 13.056 25.139 ;
     RECT  12 25.139 13.056 26.629 ;
     RECT  76.92 25.715 78 27.395 ;
     RECT  30.504 26.005 32.016 27.971 ;
     RECT  68.088 26.197 69.408 26.389 ;
     RECT  68.184 26.389 69.408 26.629 ;
     RECT  11.736 26.629 13.056 27.971 ;
     RECT  68.376 26.629 69.408 26.771 ;
     RECT  68.04 26.771 69.408 27.203 ;
     RECT  53.592 27.589 54.672 29.651 ;
     RECT  11.736 27.971 13.2 31.045 ;
     RECT  30.504 27.971 32.448 28.021 ;
     RECT  31.272 28.021 32.448 29.651 ;
     RECT  38.76 28.165 39.888 29.171 ;
     RECT  35.112 28.261 36.096 30.083 ;
     RECT  53.592 29.651 54.072 30.803 ;
     RECT  4.8 29.699 5.472 30.421 ;
     RECT  2.712 30.421 3.984 31.525 ;
     RECT  4.008 30.421 5.472 31.955 ;
     RECT  54.048 30.803 54.072 30.997 ;
     RECT  11.736 31.045 13.104 31.187 ;
     RECT  11.736 31.187 13.2 32.149 ;
     RECT  76.056 31.765 77.04 31.955 ;
     RECT  11.928 32.149 13.2 32.915 ;
     RECT  11.736 32.915 13.2 32.917 ;
     RECT  11.736 32.917 13.056 33.059 ;
     RECT  11.736 33.059 13.2 33.779 ;
     RECT  37.488 33.299 37.584 34.789 ;
     RECT  12.528 33.779 13.2 34.165 ;
     RECT  65.4 33.877 66.912 33.971 ;
     RECT  9.336 34.213 10.416 35.459 ;
     RECT  4.392 34.501 5.472 42.661 ;
     RECT  37.608 34.645 38.688 34.835 ;
     RECT  48.888 34.741 49.92 35.123 ;
     RECT  9.336 35.459 10.512 35.845 ;
     RECT  9.48 35.845 10.512 37.285 ;
     RECT  62.232 36.085 63.36 37.091 ;
     RECT  31.344 36.515 31.584 36.997 ;
     RECT  39.312 36.611 40.08 37.045 ;
     RECT  30.216 36.997 31.584 38.819 ;
     RECT  38.808 37.045 40.08 37.621 ;
     RECT  45.912 37.667 47.04 39.061 ;
     RECT  68.376 38.149 69.408 39.059 ;
     RECT  30.072 38.819 31.584 40.067 ;
     RECT  44.472 39.253 45.6 41.267 ;
     RECT  38.808 39.347 39.888 40.405 ;
     RECT  38.808 40.405 39.792 40.499 ;
     RECT  59.232 40.547 59.256 41.221 ;
     RECT  58.584 41.221 59.256 41.509 ;
     RECT  9.864 41.461 10.848 42.325 ;
     RECT  77.856 41.651 78 42.709 ;
     RECT  3 42.037 4.368 42.179 ;
     RECT  2.904 42.179 4.368 42.995 ;
     RECT  67.512 42.227 67.752 42.709 ;
     RECT  10.872 42.275 11.4 43.285 ;
     RECT  42.168 42.373 43.584 44.051 ;
     RECT  41.16 42.419 42.144 44.051 ;
     RECT  24.312 42.709 25.344 46.835 ;
     RECT  67.512 42.709 68.976 43.955 ;
     RECT  75.096 42.709 76.608 43.379 ;
     RECT  76.632 42.709 78 43.237 ;
     RECT  76.632 43.237 77.904 45.059 ;
     RECT  13.512 43.285 14.832 43.765 ;
     RECT  44.472 43.285 45.6 43.955 ;
     RECT  10.68 43.427 11.4 44.773 ;
     RECT  35.112 43.427 35.352 43.525 ;
     RECT  35.112 43.525 36.432 47.939 ;
     RECT  58.584 43.907 59.256 44.341 ;
     RECT  58.584 44.341 59.856 45.731 ;
     RECT  59.88 44.341 61.056 45.731 ;
     RECT  17.592 44.869 18.6 46.019 ;
     RECT  32.184 44.869 33.264 45.731 ;
     RECT  33.288 44.869 34.8 45.731 ;
     RECT  76.392 45.059 77.904 45.251 ;
     RECT  9.48 45.155 10.464 47.269 ;
     RECT  58.584 45.731 61.056 46.117 ;
     RECT  18.48 46.019 18.6 46.549 ;
     RECT  59.256 46.117 61.056 47.173 ;
     RECT  69.432 46.787 70.512 48.373 ;
     RECT  59.256 47.173 60.528 47.891 ;
     RECT  78.312 47.845 79.776 52.499 ;
     RECT  50.112 49.523 50.736 50.389 ;
     RECT  9.72 49.571 11.376 50.435 ;
     RECT  5.04 49.619 5.424 50.389 ;
     RECT  21.624 50.005 23.04 51.347 ;
     RECT  2.712 50.389 3.936 53.075 ;
     RECT  3.96 50.389 5.424 53.075 ;
     RECT  48.744 50.389 50.736 50.677 ;
     RECT  9.72 50.435 11.16 50.677 ;
     RECT  10.584 50.677 11.16 51.781 ;
     RECT  49.32 50.677 50.736 50.771 ;
     RECT  59.544 50.773 61.056 50.819 ;
     RECT  21.624 51.347 23.088 51.923 ;
     RECT  18.912 51.923 19.032 52.981 ;
     RECT  78.312 52.499 79.176 53.557 ;
     RECT  8.376 53.075 9.504 53.603 ;
     RECT  8.28 53.603 9.504 55.237 ;
     RECT  56.712 53.893 57.744 54.085 ;
     RECT  57.768 53.893 59.184 54.323 ;
     RECT  46.728 53.941 47.904 54.323 ;
     RECT  10.104 54.083 11.136 56.243 ;
     RECT  35.208 54.085 36.288 57.347 ;
     RECT  51.312 54.613 52.464 54.997 ;
     RECT  68.232 54.661 69.36 56.195 ;
     RECT  52.488 54.755 53.52 55.331 ;
     RECT  29.712 54.853 30.72 55.475 ;
     RECT  52.152 55.331 53.52 56.389 ;
     RECT  29.712 55.475 30.744 56.629 ;
     RECT  66.12 56.053 67.2 56.483 ;
     RECT  56.712 56.099 57.744 57.923 ;
     RECT  10.104 56.243 10.2 57.013 ;
     RECT  52.248 56.389 53.52 57.973 ;
     RECT  29.712 56.629 30.864 57.443 ;
     RECT  57.768 56.773 58.896 57.875 ;
     RECT  58.92 57.107 59.832 57.875 ;
     RECT  72.912 57.253 74.064 58.739 ;
     RECT  74.088 57.253 75.12 58.739 ;
     RECT  29.712 57.443 30.888 57.877 ;
     RECT  63.96 57.829 65.376 58.163 ;
     RECT  59.808 57.875 59.832 58.117 ;
     RECT  29.712 57.877 31.2 58.117 ;
     RECT  31.272 57.877 32.592 58.835 ;
     RECT  52.536 57.973 53.52 59.315 ;
     RECT  29.832 58.117 31.2 59.269 ;
     RECT  9.096 58.307 10.176 58.355 ;
     RECT  27.912 58.645 29.088 59.411 ;
     RECT  45.504 58.739 45.6 58.981 ;
     RECT  49.032 58.885 50.256 59.987 ;
     RECT  44.28 58.981 45.6 61.619 ;
     RECT  45.912 59.221 46.944 63.637 ;
     RECT  29.832 59.269 30.816 59.797 ;
     RECT  52.248 59.315 53.52 62.003 ;
     RECT  48.888 59.987 50.256 61.619 ;
     RECT  8.808 60.613 10.128 60.995 ;
     RECT  46.968 60.613 48.336 61.717 ;
     RECT  8.28 60.995 10.128 61.957 ;
     RECT  55.32 60.995 56.4 62.629 ;
     RECT  11.928 61.045 13.2 61.861 ;
     RECT  62.328 61.477 63.792 62.629 ;
     RECT  48.888 61.619 50.4 62.917 ;
     RECT  47.304 61.717 48.336 62.341 ;
     RECT  11.904 61.907 12 62.149 ;
     RECT  8.664 61.957 10.128 62.195 ;
     RECT  52.2 62.003 53.52 62.675 ;
     RECT  10.584 62.149 12 63.011 ;
     RECT  8.664 62.195 8.856 62.485 ;
     RECT  76.968 62.195 78 62.819 ;
     RECT  8.712 62.485 8.856 62.533 ;
     RECT  62.328 62.629 63.648 63.109 ;
     RECT  52.2 62.675 53.616 62.723 ;
     RECT  49.08 62.917 50.4 63.877 ;
     RECT  55.32 63.107 56.4 65.171 ;
     RECT  62.424 63.109 63.648 63.299 ;
     RECT  35.448 63.251 35.88 64.357 ;
     RECT  5.784 63.299 7.008 65.603 ;
     RECT  78.408 64.115 78.792 65.509 ;
     RECT  49.656 64.307 51 66.851 ;
     RECT  28.608 64.355 28.8 65.845 ;
     RECT  56.712 64.357 58.128 64.931 ;
     RECT  38.856 64.405 40.2 64.933 ;
     RECT  12 64.643 12.24 65.651 ;
     RECT  51.312 64.693 52.56 64.931 ;
     RECT  48.36 64.931 49.632 66.851 ;
     RECT  58.656 64.931 58.896 65.027 ;
     RECT  38.856 64.933 40.08 65.075 ;
     RECT  58.656 65.027 58.68 66.085 ;
     RECT  38.832 65.075 40.08 65.317 ;
     RECT  38.808 65.317 40.08 65.795 ;
     RECT  12 65.651 13.104 65.653 ;
     RECT  11.592 65.653 13.104 67.811 ;
     RECT  38.808 65.795 40.2 68.339 ;
     RECT  27.384 65.845 28.8 66.131 ;
     RECT  45.456 66.899 45.6 68.245 ;
     RECT  68.232 67.717 69.36 68.099 ;
     RECT  60.648 68.101 61.8 69.971 ;
     RECT  45.912 68.435 46.992 69.491 ;
     RECT  27.96 68.917 29.28 70.691 ;
     RECT  45.912 69.491 47.04 70.835 ;
     RECT  73.368 70.259 73.416 71.317 ;
     RECT  35.112 70.645 36.432 74.099 ;
     RECT  51.72 70.789 52.992 70.979 ;
     RECT  45.912 70.835 47.088 74.147 ;
     RECT  38.52 71.077 39.696 72.323 ;
     RECT  73.752 71.317 75.12 71.363 ;
     RECT  75.552 71.363 75.84 72.613 ;
     RECT  40.512 72.181 41.856 72.995 ;
     RECT  41.88 72.181 43.392 72.995 ;
     RECT  38.64 72.323 39.696 73.237 ;
     RECT  13.656 72.805 14.928 75.155 ;
     RECT  71.256 72.901 72.6 73.763 ;
     RECT  38.64 73.237 38.784 73.381 ;
     RECT  43.416 73.477 44.88 74.723 ;
     RECT  38.808 73.571 40.2 75.013 ;
     RECT  8.112 73.621 9.552 75.299 ;
     RECT  9.576 73.621 10.848 74.387 ;
     RECT  45.912 74.147 47.136 74.915 ;
     RECT  12 74.867 12.96 75.157 ;
     RECT  13.512 75.155 14.928 77.171 ;
     RECT  11.544 75.157 12.96 75.395 ;
     RECT  52.44 75.205 53.664 76.501 ;
     RECT  29.832 75.731 30.816 76.451 ;
     RECT  4.536 76.357 5.712 76.979 ;
     RECT  29.832 76.451 30.792 77.125 ;
     RECT  52.488 76.501 53.664 77.507 ;
     RECT  13.512 77.171 14.904 78.037 ;
     RECT  51.312 77.939 52.464 78.131 ;
     RECT  60.408 77.941 61.8 78.707 ;
     RECT  13.512 78.037 14.88 79.235 ;
     RECT  29.712 78.227 30.768 79.187 ;
     RECT  40.512 78.613 41.808 79.235 ;
     RECT  61.104 78.707 61.8 78.901 ;
     RECT  6.792 78.997 7.8 79.475 ;
  END
END ot_hcoll_reduce_lane8
END LIBRARY
